VERSION 5.8 ;
BUSBITCHARS "[]" ;
DIVIDERCHAR "/" ;
UNITS
    DATABASE MICRONS 1000 ;
END UNITS

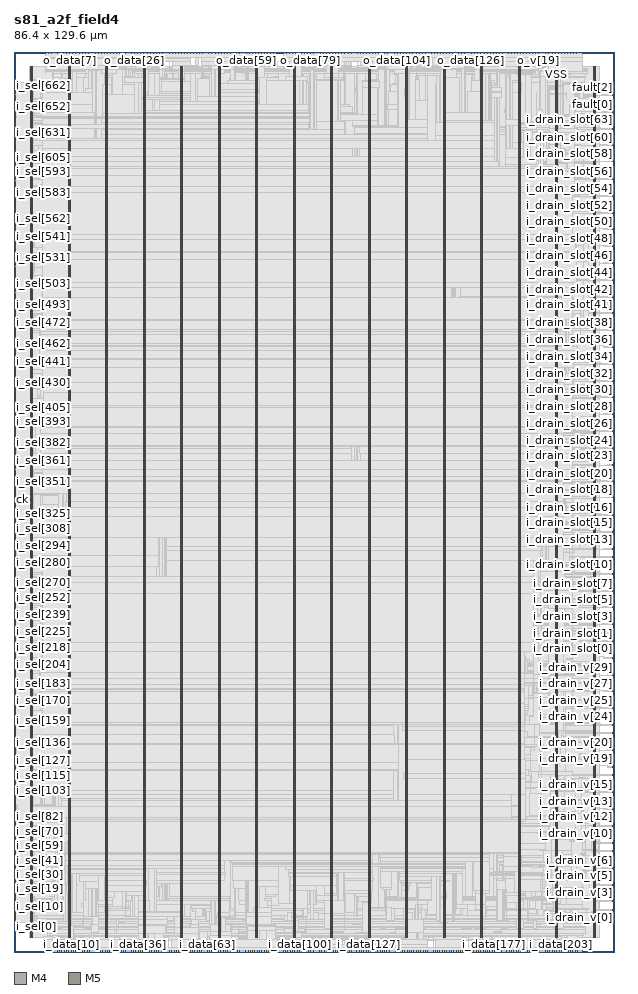
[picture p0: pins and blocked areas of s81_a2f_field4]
MACRO s81_a2f_field4
  FOREIGN s81_a2f_field4 0 0 ;
  CLASS BLOCK ;
  SIZE 86.4 BY 129.6 ;
  PIN ck
    DIRECTION INPUT ;
    USE SIGNAL ;
    PORT
      LAYER M4 ;
        RECT  0 64.08 0.192 64.104 ;
    END
  END ck
  PIN fault[0]
    DIRECTION OUTPUT ;
    USE SIGNAL ;
    PORT
      LAYER M4 ;
        RECT  86.208 120.96 86.4 120.984 ;
    END
  END fault[0]
  PIN fault[1]
    DIRECTION OUTPUT ;
    USE SIGNAL ;
    PORT
      LAYER M4 ;
        RECT  86.208 122.256 86.4 122.28 ;
    END
  END fault[1]
  PIN fault[2]
    DIRECTION OUTPUT ;
    USE SIGNAL ;
    PORT
      LAYER M4 ;
        RECT  86.208 123.408 86.4 123.432 ;
    END
  END fault[2]
  PIN fault[3]
    DIRECTION OUTPUT ;
    USE SIGNAL ;
    PORT
      LAYER M4 ;
        RECT  86.208 124.56 86.4 124.584 ;
    END
  END fault[3]
  PIN i_data[0]
    DIRECTION INPUT ;
    USE SIGNAL ;
    PORT
      LAYER M5 ;
        RECT  4.464 0 4.488 0.192 ;
    END
  END i_data[0]
  PIN i_data[100]
    DIRECTION INPUT ;
    USE SIGNAL ;
    PORT
      LAYER M5 ;
        RECT  41.136 0 41.16 0.192 ;
    END
  END i_data[100]
  PIN i_data[101]
    DIRECTION INPUT ;
    USE SIGNAL ;
    PORT
      LAYER M5 ;
        RECT  41.424 0 41.448 0.192 ;
    END
  END i_data[101]
  PIN i_data[102]
    DIRECTION INPUT ;
    USE SIGNAL ;
    PORT
      LAYER M5 ;
        RECT  41.712 0 41.736 0.192 ;
    END
  END i_data[102]
  PIN i_data[103]
    DIRECTION INPUT ;
    USE SIGNAL ;
    PORT
      LAYER M5 ;
        RECT  42.144 0 42.168 0.192 ;
    END
  END i_data[103]
  PIN i_data[104]
    DIRECTION INPUT ;
    USE SIGNAL ;
    PORT
      LAYER M5 ;
        RECT  42.432 0 42.456 0.192 ;
    END
  END i_data[104]
  PIN i_data[105]
    DIRECTION INPUT ;
    USE SIGNAL ;
    PORT
      LAYER M5 ;
        RECT  42.72 0 42.744 0.192 ;
    END
  END i_data[105]
  PIN i_data[106]
    DIRECTION INPUT ;
    USE SIGNAL ;
    PORT
      LAYER M5 ;
        RECT  43.152 0 43.176 0.192 ;
    END
  END i_data[106]
  PIN i_data[107]
    DIRECTION INPUT ;
    USE SIGNAL ;
    PORT
      LAYER M5 ;
        RECT  43.968 0 43.992 0.192 ;
    END
  END i_data[107]
  PIN i_data[108]
    DIRECTION INPUT ;
    USE SIGNAL ;
    PORT
      LAYER M5 ;
        RECT  44.256 0 44.28 0.192 ;
    END
  END i_data[108]
  PIN i_data[109]
    DIRECTION INPUT ;
    USE SIGNAL ;
    PORT
      LAYER M5 ;
        RECT  44.688 0 44.712 0.192 ;
    END
  END i_data[109]
  PIN i_data[10]
    DIRECTION INPUT ;
    USE SIGNAL ;
    PORT
      LAYER M5 ;
        RECT  8.304 0 8.328 0.192 ;
    END
  END i_data[10]
  PIN i_data[110]
    DIRECTION INPUT ;
    USE SIGNAL ;
    PORT
      LAYER M5 ;
        RECT  44.976 0 45 0.192 ;
    END
  END i_data[110]
  PIN i_data[111]
    DIRECTION INPUT ;
    USE SIGNAL ;
    PORT
      LAYER M5 ;
        RECT  45.264 0 45.288 0.192 ;
    END
  END i_data[111]
  PIN i_data[112]
    DIRECTION INPUT ;
    USE SIGNAL ;
    PORT
      LAYER M5 ;
        RECT  45.552 0 45.576 0.192 ;
    END
  END i_data[112]
  PIN i_data[113]
    DIRECTION INPUT ;
    USE SIGNAL ;
    PORT
      LAYER M5 ;
        RECT  45.984 0 46.008 0.192 ;
    END
  END i_data[113]
  PIN i_data[114]
    DIRECTION INPUT ;
    USE SIGNAL ;
    PORT
      LAYER M5 ;
        RECT  46.272 0 46.296 0.192 ;
    END
  END i_data[114]
  PIN i_data[115]
    DIRECTION INPUT ;
    USE SIGNAL ;
    PORT
      LAYER M5 ;
        RECT  46.56 0 46.584 0.192 ;
    END
  END i_data[115]
  PIN i_data[116]
    DIRECTION INPUT ;
    USE SIGNAL ;
    PORT
      LAYER M5 ;
        RECT  46.992 0 47.016 0.192 ;
    END
  END i_data[116]
  PIN i_data[117]
    DIRECTION INPUT ;
    USE SIGNAL ;
    PORT
      LAYER M5 ;
        RECT  47.28 0 47.304 0.192 ;
    END
  END i_data[117]
  PIN i_data[118]
    DIRECTION INPUT ;
    USE SIGNAL ;
    PORT
      LAYER M5 ;
        RECT  47.568 0 47.592 0.192 ;
    END
  END i_data[118]
  PIN i_data[119]
    DIRECTION INPUT ;
    USE SIGNAL ;
    PORT
      LAYER M5 ;
        RECT  48 0 48.024 0.192 ;
    END
  END i_data[119]
  PIN i_data[11]
    DIRECTION INPUT ;
    USE SIGNAL ;
    PORT
      LAYER M5 ;
        RECT  8.592 0 8.616 0.192 ;
    END
  END i_data[11]
  PIN i_data[120]
    DIRECTION INPUT ;
    USE SIGNAL ;
    PORT
      LAYER M5 ;
        RECT  48.288 0 48.312 0.192 ;
    END
  END i_data[120]
  PIN i_data[121]
    DIRECTION INPUT ;
    USE SIGNAL ;
    PORT
      LAYER M5 ;
        RECT  48.576 0 48.6 0.192 ;
    END
  END i_data[121]
  PIN i_data[122]
    DIRECTION INPUT ;
    USE SIGNAL ;
    PORT
      LAYER M5 ;
        RECT  49.344 0 49.368 0.192 ;
    END
  END i_data[122]
  PIN i_data[123]
    DIRECTION INPUT ;
    USE SIGNAL ;
    PORT
      LAYER M5 ;
        RECT  49.776 0 49.8 0.192 ;
    END
  END i_data[123]
  PIN i_data[124]
    DIRECTION INPUT ;
    USE SIGNAL ;
    PORT
      LAYER M5 ;
        RECT  50.064 0 50.088 0.192 ;
    END
  END i_data[124]
  PIN i_data[125]
    DIRECTION INPUT ;
    USE SIGNAL ;
    PORT
      LAYER M5 ;
        RECT  50.352 0 50.376 0.192 ;
    END
  END i_data[125]
  PIN i_data[126]
    DIRECTION INPUT ;
    USE SIGNAL ;
    PORT
      LAYER M5 ;
        RECT  50.784 0 50.808 0.192 ;
    END
  END i_data[126]
  PIN i_data[127]
    DIRECTION INPUT ;
    USE SIGNAL ;
    PORT
      LAYER M5 ;
        RECT  51.072 0 51.096 0.192 ;
    END
  END i_data[127]
  PIN i_data[128]
    DIRECTION INPUT ;
    USE SIGNAL ;
    PORT
      LAYER M5 ;
        RECT  51.36 0 51.384 0.192 ;
    END
  END i_data[128]
  PIN i_data[129]
    DIRECTION INPUT ;
    USE SIGNAL ;
    PORT
      LAYER M5 ;
        RECT  51.792 0 51.816 0.192 ;
    END
  END i_data[129]
  PIN i_data[12]
    DIRECTION INPUT ;
    USE SIGNAL ;
    PORT
      LAYER M5 ;
        RECT  8.88 0 8.904 0.192 ;
    END
  END i_data[12]
  PIN i_data[130]
    DIRECTION INPUT ;
    USE SIGNAL ;
    PORT
      LAYER M5 ;
        RECT  52.08 0 52.104 0.192 ;
    END
  END i_data[130]
  PIN i_data[131]
    DIRECTION INPUT ;
    USE SIGNAL ;
    PORT
      LAYER M5 ;
        RECT  52.368 0 52.392 0.192 ;
    END
  END i_data[131]
  PIN i_data[132]
    DIRECTION INPUT ;
    USE SIGNAL ;
    PORT
      LAYER M5 ;
        RECT  52.8 0 52.824 0.192 ;
    END
  END i_data[132]
  PIN i_data[133]
    DIRECTION INPUT ;
    USE SIGNAL ;
    PORT
      LAYER M5 ;
        RECT  53.088 0 53.112 0.192 ;
    END
  END i_data[133]
  PIN i_data[134]
    DIRECTION INPUT ;
    USE SIGNAL ;
    PORT
      LAYER M5 ;
        RECT  53.376 0 53.4 0.192 ;
    END
  END i_data[134]
  PIN i_data[135]
    DIRECTION INPUT ;
    USE SIGNAL ;
    PORT
      LAYER M5 ;
        RECT  53.664 0 53.688 0.192 ;
    END
  END i_data[135]
  PIN i_data[136]
    DIRECTION INPUT ;
    USE SIGNAL ;
    PORT
      LAYER M5 ;
        RECT  54.096 0 54.12 0.192 ;
    END
  END i_data[136]
  PIN i_data[137]
    DIRECTION INPUT ;
    USE SIGNAL ;
    PORT
      LAYER M5 ;
        RECT  54.912 0 54.936 0.192 ;
    END
  END i_data[137]
  PIN i_data[138]
    DIRECTION INPUT ;
    USE SIGNAL ;
    PORT
      LAYER M5 ;
        RECT  55.2 0 55.224 0.192 ;
    END
  END i_data[138]
  PIN i_data[139]
    DIRECTION INPUT ;
    USE SIGNAL ;
    PORT
      LAYER M5 ;
        RECT  55.632 0 55.656 0.192 ;
    END
  END i_data[139]
  PIN i_data[13]
    DIRECTION INPUT ;
    USE SIGNAL ;
    PORT
      LAYER M5 ;
        RECT  9.312 0 9.336 0.192 ;
    END
  END i_data[13]
  PIN i_data[140]
    DIRECTION INPUT ;
    USE SIGNAL ;
    PORT
      LAYER M5 ;
        RECT  55.92 0 55.944 0.192 ;
    END
  END i_data[140]
  PIN i_data[141]
    DIRECTION INPUT ;
    USE SIGNAL ;
    PORT
      LAYER M5 ;
        RECT  56.208 0 56.232 0.192 ;
    END
  END i_data[141]
  PIN i_data[142]
    DIRECTION INPUT ;
    USE SIGNAL ;
    PORT
      LAYER M5 ;
        RECT  56.64 0 56.664 0.192 ;
    END
  END i_data[142]
  PIN i_data[143]
    DIRECTION INPUT ;
    USE SIGNAL ;
    PORT
      LAYER M5 ;
        RECT  56.928 0 56.952 0.192 ;
    END
  END i_data[143]
  PIN i_data[144]
    DIRECTION INPUT ;
    USE SIGNAL ;
    PORT
      LAYER M5 ;
        RECT  57.216 0 57.24 0.192 ;
    END
  END i_data[144]
  PIN i_data[145]
    DIRECTION INPUT ;
    USE SIGNAL ;
    PORT
      LAYER M5 ;
        RECT  57.504 0 57.528 0.192 ;
    END
  END i_data[145]
  PIN i_data[146]
    DIRECTION INPUT ;
    USE SIGNAL ;
    PORT
      LAYER M5 ;
        RECT  57.936 0 57.96 0.192 ;
    END
  END i_data[146]
  PIN i_data[147]
    DIRECTION INPUT ;
    USE SIGNAL ;
    PORT
      LAYER M5 ;
        RECT  58.224 0 58.248 0.192 ;
    END
  END i_data[147]
  PIN i_data[148]
    DIRECTION INPUT ;
    USE SIGNAL ;
    PORT
      LAYER M5 ;
        RECT  58.512 0 58.536 0.192 ;
    END
  END i_data[148]
  PIN i_data[149]
    DIRECTION INPUT ;
    USE SIGNAL ;
    PORT
      LAYER M5 ;
        RECT  58.944 0 58.968 0.192 ;
    END
  END i_data[149]
  PIN i_data[14]
    DIRECTION INPUT ;
    USE SIGNAL ;
    PORT
      LAYER M5 ;
        RECT  9.6 0 9.624 0.192 ;
    END
  END i_data[14]
  PIN i_data[150]
    DIRECTION INPUT ;
    USE SIGNAL ;
    PORT
      LAYER M5 ;
        RECT  59.232 0 59.256 0.192 ;
    END
  END i_data[150]
  PIN i_data[151]
    DIRECTION INPUT ;
    USE SIGNAL ;
    PORT
      LAYER M5 ;
        RECT  59.52 0 59.544 0.192 ;
    END
  END i_data[151]
  PIN i_data[152]
    DIRECTION INPUT ;
    USE SIGNAL ;
    PORT
      LAYER M5 ;
        RECT  60.432 0 60.456 0.192 ;
    END
  END i_data[152]
  PIN i_data[153]
    DIRECTION INPUT ;
    USE SIGNAL ;
    PORT
      LAYER M5 ;
        RECT  60.72 0 60.744 0.192 ;
    END
  END i_data[153]
  PIN i_data[154]
    DIRECTION INPUT ;
    USE SIGNAL ;
    PORT
      LAYER M5 ;
        RECT  61.008 0 61.032 0.192 ;
    END
  END i_data[154]
  PIN i_data[155]
    DIRECTION INPUT ;
    USE SIGNAL ;
    PORT
      LAYER M5 ;
        RECT  61.296 0 61.32 0.192 ;
    END
  END i_data[155]
  PIN i_data[156]
    DIRECTION INPUT ;
    USE SIGNAL ;
    PORT
      LAYER M5 ;
        RECT  61.728 0 61.752 0.192 ;
    END
  END i_data[156]
  PIN i_data[157]
    DIRECTION INPUT ;
    USE SIGNAL ;
    PORT
      LAYER M5 ;
        RECT  62.016 0 62.04 0.192 ;
    END
  END i_data[157]
  PIN i_data[158]
    DIRECTION INPUT ;
    USE SIGNAL ;
    PORT
      LAYER M5 ;
        RECT  62.304 0 62.328 0.192 ;
    END
  END i_data[158]
  PIN i_data[159]
    DIRECTION INPUT ;
    USE SIGNAL ;
    PORT
      LAYER M5 ;
        RECT  62.736 0 62.76 0.192 ;
    END
  END i_data[159]
  PIN i_data[15]
    DIRECTION INPUT ;
    USE SIGNAL ;
    PORT
      LAYER M5 ;
        RECT  9.888 0 9.912 0.192 ;
    END
  END i_data[15]
  PIN i_data[160]
    DIRECTION INPUT ;
    USE SIGNAL ;
    PORT
      LAYER M5 ;
        RECT  63.024 0 63.048 0.192 ;
    END
  END i_data[160]
  PIN i_data[161]
    DIRECTION INPUT ;
    USE SIGNAL ;
    PORT
      LAYER M5 ;
        RECT  63.312 0 63.336 0.192 ;
    END
  END i_data[161]
  PIN i_data[162]
    DIRECTION INPUT ;
    USE SIGNAL ;
    PORT
      LAYER M5 ;
        RECT  63.744 0 63.768 0.192 ;
    END
  END i_data[162]
  PIN i_data[163]
    DIRECTION INPUT ;
    USE SIGNAL ;
    PORT
      LAYER M5 ;
        RECT  64.032 0 64.056 0.192 ;
    END
  END i_data[163]
  PIN i_data[164]
    DIRECTION INPUT ;
    USE SIGNAL ;
    PORT
      LAYER M5 ;
        RECT  64.32 0 64.344 0.192 ;
    END
  END i_data[164]
  PIN i_data[165]
    DIRECTION INPUT ;
    USE SIGNAL ;
    PORT
      LAYER M5 ;
        RECT  64.608 0 64.632 0.192 ;
    END
  END i_data[165]
  PIN i_data[166]
    DIRECTION INPUT ;
    USE SIGNAL ;
    PORT
      LAYER M5 ;
        RECT  65.568 0 65.592 0.192 ;
    END
  END i_data[166]
  PIN i_data[167]
    DIRECTION INPUT ;
    USE SIGNAL ;
    PORT
      LAYER M5 ;
        RECT  65.856 0 65.88 0.192 ;
    END
  END i_data[167]
  PIN i_data[168]
    DIRECTION INPUT ;
    USE SIGNAL ;
    PORT
      LAYER M5 ;
        RECT  66.144 0 66.168 0.192 ;
    END
  END i_data[168]
  PIN i_data[169]
    DIRECTION INPUT ;
    USE SIGNAL ;
    PORT
      LAYER M5 ;
        RECT  66.576 0 66.6 0.192 ;
    END
  END i_data[169]
  PIN i_data[16]
    DIRECTION INPUT ;
    USE SIGNAL ;
    PORT
      LAYER M5 ;
        RECT  10.176 0 10.2 0.192 ;
    END
  END i_data[16]
  PIN i_data[170]
    DIRECTION INPUT ;
    USE SIGNAL ;
    PORT
      LAYER M5 ;
        RECT  66.864 0 66.888 0.192 ;
    END
  END i_data[170]
  PIN i_data[171]
    DIRECTION INPUT ;
    USE SIGNAL ;
    PORT
      LAYER M5 ;
        RECT  67.152 0 67.176 0.192 ;
    END
  END i_data[171]
  PIN i_data[172]
    DIRECTION INPUT ;
    USE SIGNAL ;
    PORT
      LAYER M5 ;
        RECT  67.584 0 67.608 0.192 ;
    END
  END i_data[172]
  PIN i_data[173]
    DIRECTION INPUT ;
    USE SIGNAL ;
    PORT
      LAYER M5 ;
        RECT  67.872 0 67.896 0.192 ;
    END
  END i_data[173]
  PIN i_data[174]
    DIRECTION INPUT ;
    USE SIGNAL ;
    PORT
      LAYER M5 ;
        RECT  68.16 0 68.184 0.192 ;
    END
  END i_data[174]
  PIN i_data[175]
    DIRECTION INPUT ;
    USE SIGNAL ;
    PORT
      LAYER M5 ;
        RECT  68.448 0 68.472 0.192 ;
    END
  END i_data[175]
  PIN i_data[176]
    DIRECTION INPUT ;
    USE SIGNAL ;
    PORT
      LAYER M5 ;
        RECT  68.88 0 68.904 0.192 ;
    END
  END i_data[176]
  PIN i_data[177]
    DIRECTION INPUT ;
    USE SIGNAL ;
    PORT
      LAYER M5 ;
        RECT  69.168 0 69.192 0.192 ;
    END
  END i_data[177]
  PIN i_data[178]
    DIRECTION INPUT ;
    USE SIGNAL ;
    PORT
      LAYER M5 ;
        RECT  69.456 0 69.48 0.192 ;
    END
  END i_data[178]
  PIN i_data[179]
    DIRECTION INPUT ;
    USE SIGNAL ;
    PORT
      LAYER M5 ;
        RECT  69.888 0 69.912 0.192 ;
    END
  END i_data[179]
  PIN i_data[17]
    DIRECTION INPUT ;
    USE SIGNAL ;
    PORT
      LAYER M5 ;
        RECT  10.608 0 10.632 0.192 ;
    END
  END i_data[17]
  PIN i_data[180]
    DIRECTION INPUT ;
    USE SIGNAL ;
    PORT
      LAYER M5 ;
        RECT  70.176 0 70.2 0.192 ;
    END
  END i_data[180]
  PIN i_data[181]
    DIRECTION INPUT ;
    USE SIGNAL ;
    PORT
      LAYER M5 ;
        RECT  70.944 0 70.968 0.192 ;
    END
  END i_data[181]
  PIN i_data[182]
    DIRECTION INPUT ;
    USE SIGNAL ;
    PORT
      LAYER M5 ;
        RECT  71.376 0 71.4 0.192 ;
    END
  END i_data[182]
  PIN i_data[183]
    DIRECTION INPUT ;
    USE SIGNAL ;
    PORT
      LAYER M5 ;
        RECT  71.664 0 71.688 0.192 ;
    END
  END i_data[183]
  PIN i_data[184]
    DIRECTION INPUT ;
    USE SIGNAL ;
    PORT
      LAYER M5 ;
        RECT  71.952 0 71.976 0.192 ;
    END
  END i_data[184]
  PIN i_data[185]
    DIRECTION INPUT ;
    USE SIGNAL ;
    PORT
      LAYER M5 ;
        RECT  72.384 0 72.408 0.192 ;
    END
  END i_data[185]
  PIN i_data[186]
    DIRECTION INPUT ;
    USE SIGNAL ;
    PORT
      LAYER M5 ;
        RECT  72.672 0 72.696 0.192 ;
    END
  END i_data[186]
  PIN i_data[187]
    DIRECTION INPUT ;
    USE SIGNAL ;
    PORT
      LAYER M5 ;
        RECT  72.96 0 72.984 0.192 ;
    END
  END i_data[187]
  PIN i_data[188]
    DIRECTION INPUT ;
    USE SIGNAL ;
    PORT
      LAYER M5 ;
        RECT  73.248 0 73.272 0.192 ;
    END
  END i_data[188]
  PIN i_data[189]
    DIRECTION INPUT ;
    USE SIGNAL ;
    PORT
      LAYER M5 ;
        RECT  73.68 0 73.704 0.192 ;
    END
  END i_data[189]
  PIN i_data[18]
    DIRECTION INPUT ;
    USE SIGNAL ;
    PORT
      LAYER M5 ;
        RECT  10.896 0 10.92 0.192 ;
    END
  END i_data[18]
  PIN i_data[190]
    DIRECTION INPUT ;
    USE SIGNAL ;
    PORT
      LAYER M5 ;
        RECT  73.968 0 73.992 0.192 ;
    END
  END i_data[190]
  PIN i_data[191]
    DIRECTION INPUT ;
    USE SIGNAL ;
    PORT
      LAYER M5 ;
        RECT  74.256 0 74.28 0.192 ;
    END
  END i_data[191]
  PIN i_data[192]
    DIRECTION INPUT ;
    USE SIGNAL ;
    PORT
      LAYER M5 ;
        RECT  74.688 0 74.712 0.192 ;
    END
  END i_data[192]
  PIN i_data[193]
    DIRECTION INPUT ;
    USE SIGNAL ;
    PORT
      LAYER M5 ;
        RECT  74.976 0 75 0.192 ;
    END
  END i_data[193]
  PIN i_data[194]
    DIRECTION INPUT ;
    USE SIGNAL ;
    PORT
      LAYER M5 ;
        RECT  75.264 0 75.288 0.192 ;
    END
  END i_data[194]
  PIN i_data[195]
    DIRECTION INPUT ;
    USE SIGNAL ;
    PORT
      LAYER M5 ;
        RECT  75.696 0 75.72 0.192 ;
    END
  END i_data[195]
  PIN i_data[196]
    DIRECTION INPUT ;
    USE SIGNAL ;
    PORT
      LAYER M5 ;
        RECT  76.512 0 76.536 0.192 ;
    END
  END i_data[196]
  PIN i_data[197]
    DIRECTION INPUT ;
    USE SIGNAL ;
    PORT
      LAYER M5 ;
        RECT  76.8 0 76.824 0.192 ;
    END
  END i_data[197]
  PIN i_data[198]
    DIRECTION INPUT ;
    USE SIGNAL ;
    PORT
      LAYER M5 ;
        RECT  77.088 0 77.112 0.192 ;
    END
  END i_data[198]
  PIN i_data[199]
    DIRECTION INPUT ;
    USE SIGNAL ;
    PORT
      LAYER M5 ;
        RECT  77.52 0 77.544 0.192 ;
    END
  END i_data[199]
  PIN i_data[19]
    DIRECTION INPUT ;
    USE SIGNAL ;
    PORT
      LAYER M5 ;
        RECT  11.712 0 11.736 0.192 ;
    END
  END i_data[19]
  PIN i_data[1]
    DIRECTION INPUT ;
    USE SIGNAL ;
    PORT
      LAYER M5 ;
        RECT  4.752 0 4.776 0.192 ;
    END
  END i_data[1]
  PIN i_data[200]
    DIRECTION INPUT ;
    USE SIGNAL ;
    PORT
      LAYER M5 ;
        RECT  77.808 0 77.832 0.192 ;
    END
  END i_data[200]
  PIN i_data[201]
    DIRECTION INPUT ;
    USE SIGNAL ;
    PORT
      LAYER M5 ;
        RECT  78.096 0 78.12 0.192 ;
    END
  END i_data[201]
  PIN i_data[202]
    DIRECTION INPUT ;
    USE SIGNAL ;
    PORT
      LAYER M5 ;
        RECT  78.528 0 78.552 0.192 ;
    END
  END i_data[202]
  PIN i_data[203]
    DIRECTION INPUT ;
    USE SIGNAL ;
    PORT
      LAYER M5 ;
        RECT  78.816 0 78.84 0.192 ;
    END
  END i_data[203]
  PIN i_data[204]
    DIRECTION INPUT ;
    USE SIGNAL ;
    PORT
      LAYER M5 ;
        RECT  79.104 0 79.128 0.192 ;
    END
  END i_data[204]
  PIN i_data[205]
    DIRECTION INPUT ;
    USE SIGNAL ;
    PORT
      LAYER M5 ;
        RECT  79.536 0 79.56 0.192 ;
    END
  END i_data[205]
  PIN i_data[206]
    DIRECTION INPUT ;
    USE SIGNAL ;
    PORT
      LAYER M5 ;
        RECT  79.824 0 79.848 0.192 ;
    END
  END i_data[206]
  PIN i_data[207]
    DIRECTION INPUT ;
    USE SIGNAL ;
    PORT
      LAYER M5 ;
        RECT  80.112 0 80.136 0.192 ;
    END
  END i_data[207]
  PIN i_data[208]
    DIRECTION INPUT ;
    USE SIGNAL ;
    PORT
      LAYER M5 ;
        RECT  80.4 0 80.424 0.192 ;
    END
  END i_data[208]
  PIN i_data[209]
    DIRECTION INPUT ;
    USE SIGNAL ;
    PORT
      LAYER M5 ;
        RECT  80.832 0 80.856 0.192 ;
    END
  END i_data[209]
  PIN i_data[20]
    DIRECTION INPUT ;
    USE SIGNAL ;
    PORT
      LAYER M5 ;
        RECT  12.144 0 12.168 0.192 ;
    END
  END i_data[20]
  PIN i_data[210]
    DIRECTION INPUT ;
    USE SIGNAL ;
    PORT
      LAYER M5 ;
        RECT  81.12 0 81.144 0.192 ;
    END
  END i_data[210]
  PIN i_data[211]
    DIRECTION INPUT ;
    USE SIGNAL ;
    PORT
      LAYER M5 ;
        RECT  81.888 0 81.912 0.192 ;
    END
  END i_data[211]
  PIN i_data[21]
    DIRECTION INPUT ;
    USE SIGNAL ;
    PORT
      LAYER M5 ;
        RECT  12.432 0 12.456 0.192 ;
    END
  END i_data[21]
  PIN i_data[22]
    DIRECTION INPUT ;
    USE SIGNAL ;
    PORT
      LAYER M5 ;
        RECT  12.72 0 12.744 0.192 ;
    END
  END i_data[22]
  PIN i_data[23]
    DIRECTION INPUT ;
    USE SIGNAL ;
    PORT
      LAYER M5 ;
        RECT  13.152 0 13.176 0.192 ;
    END
  END i_data[23]
  PIN i_data[24]
    DIRECTION INPUT ;
    USE SIGNAL ;
    PORT
      LAYER M5 ;
        RECT  13.44 0 13.464 0.192 ;
    END
  END i_data[24]
  PIN i_data[25]
    DIRECTION INPUT ;
    USE SIGNAL ;
    PORT
      LAYER M5 ;
        RECT  13.728 0 13.752 0.192 ;
    END
  END i_data[25]
  PIN i_data[26]
    DIRECTION INPUT ;
    USE SIGNAL ;
    PORT
      LAYER M5 ;
        RECT  14.16 0 14.184 0.192 ;
    END
  END i_data[26]
  PIN i_data[27]
    DIRECTION INPUT ;
    USE SIGNAL ;
    PORT
      LAYER M5 ;
        RECT  14.448 0 14.472 0.192 ;
    END
  END i_data[27]
  PIN i_data[28]
    DIRECTION INPUT ;
    USE SIGNAL ;
    PORT
      LAYER M5 ;
        RECT  14.736 0 14.76 0.192 ;
    END
  END i_data[28]
  PIN i_data[29]
    DIRECTION INPUT ;
    USE SIGNAL ;
    PORT
      LAYER M5 ;
        RECT  15.024 0 15.048 0.192 ;
    END
  END i_data[29]
  PIN i_data[2]
    DIRECTION INPUT ;
    USE SIGNAL ;
    PORT
      LAYER M5 ;
        RECT  5.04 0 5.064 0.192 ;
    END
  END i_data[2]
  PIN i_data[30]
    DIRECTION INPUT ;
    USE SIGNAL ;
    PORT
      LAYER M5 ;
        RECT  15.456 0 15.48 0.192 ;
    END
  END i_data[30]
  PIN i_data[31]
    DIRECTION INPUT ;
    USE SIGNAL ;
    PORT
      LAYER M5 ;
        RECT  15.744 0 15.768 0.192 ;
    END
  END i_data[31]
  PIN i_data[32]
    DIRECTION INPUT ;
    USE SIGNAL ;
    PORT
      LAYER M5 ;
        RECT  16.032 0 16.056 0.192 ;
    END
  END i_data[32]
  PIN i_data[33]
    DIRECTION INPUT ;
    USE SIGNAL ;
    PORT
      LAYER M5 ;
        RECT  16.944 0 16.968 0.192 ;
    END
  END i_data[33]
  PIN i_data[34]
    DIRECTION INPUT ;
    USE SIGNAL ;
    PORT
      LAYER M5 ;
        RECT  17.232 0 17.256 0.192 ;
    END
  END i_data[34]
  PIN i_data[35]
    DIRECTION INPUT ;
    USE SIGNAL ;
    PORT
      LAYER M5 ;
        RECT  17.52 0 17.544 0.192 ;
    END
  END i_data[35]
  PIN i_data[36]
    DIRECTION INPUT ;
    USE SIGNAL ;
    PORT
      LAYER M5 ;
        RECT  17.952 0 17.976 0.192 ;
    END
  END i_data[36]
  PIN i_data[37]
    DIRECTION INPUT ;
    USE SIGNAL ;
    PORT
      LAYER M5 ;
        RECT  18.24 0 18.264 0.192 ;
    END
  END i_data[37]
  PIN i_data[38]
    DIRECTION INPUT ;
    USE SIGNAL ;
    PORT
      LAYER M5 ;
        RECT  18.528 0 18.552 0.192 ;
    END
  END i_data[38]
  PIN i_data[39]
    DIRECTION INPUT ;
    USE SIGNAL ;
    PORT
      LAYER M5 ;
        RECT  18.816 0 18.84 0.192 ;
    END
  END i_data[39]
  PIN i_data[3]
    DIRECTION INPUT ;
    USE SIGNAL ;
    PORT
      LAYER M5 ;
        RECT  5.472 0 5.496 0.192 ;
    END
  END i_data[3]
  PIN i_data[40]
    DIRECTION INPUT ;
    USE SIGNAL ;
    PORT
      LAYER M5 ;
        RECT  19.248 0 19.272 0.192 ;
    END
  END i_data[40]
  PIN i_data[41]
    DIRECTION INPUT ;
    USE SIGNAL ;
    PORT
      LAYER M5 ;
        RECT  19.536 0 19.56 0.192 ;
    END
  END i_data[41]
  PIN i_data[42]
    DIRECTION INPUT ;
    USE SIGNAL ;
    PORT
      LAYER M5 ;
        RECT  19.824 0 19.848 0.192 ;
    END
  END i_data[42]
  PIN i_data[43]
    DIRECTION INPUT ;
    USE SIGNAL ;
    PORT
      LAYER M5 ;
        RECT  20.256 0 20.28 0.192 ;
    END
  END i_data[43]
  PIN i_data[44]
    DIRECTION INPUT ;
    USE SIGNAL ;
    PORT
      LAYER M5 ;
        RECT  20.544 0 20.568 0.192 ;
    END
  END i_data[44]
  PIN i_data[45]
    DIRECTION INPUT ;
    USE SIGNAL ;
    PORT
      LAYER M5 ;
        RECT  20.832 0 20.856 0.192 ;
    END
  END i_data[45]
  PIN i_data[46]
    DIRECTION INPUT ;
    USE SIGNAL ;
    PORT
      LAYER M5 ;
        RECT  21.264 0 21.288 0.192 ;
    END
  END i_data[46]
  PIN i_data[47]
    DIRECTION INPUT ;
    USE SIGNAL ;
    PORT
      LAYER M5 ;
        RECT  21.552 0 21.576 0.192 ;
    END
  END i_data[47]
  PIN i_data[48]
    DIRECTION INPUT ;
    USE SIGNAL ;
    PORT
      LAYER M5 ;
        RECT  22.368 0 22.392 0.192 ;
    END
  END i_data[48]
  PIN i_data[49]
    DIRECTION INPUT ;
    USE SIGNAL ;
    PORT
      LAYER M5 ;
        RECT  22.656 0 22.68 0.192 ;
    END
  END i_data[49]
  PIN i_data[4]
    DIRECTION INPUT ;
    USE SIGNAL ;
    PORT
      LAYER M5 ;
        RECT  6.288 0 6.312 0.192 ;
    END
  END i_data[4]
  PIN i_data[50]
    DIRECTION INPUT ;
    USE SIGNAL ;
    PORT
      LAYER M5 ;
        RECT  23.088 0 23.112 0.192 ;
    END
  END i_data[50]
  PIN i_data[51]
    DIRECTION INPUT ;
    USE SIGNAL ;
    PORT
      LAYER M5 ;
        RECT  23.376 0 23.4 0.192 ;
    END
  END i_data[51]
  PIN i_data[52]
    DIRECTION INPUT ;
    USE SIGNAL ;
    PORT
      LAYER M5 ;
        RECT  23.664 0 23.688 0.192 ;
    END
  END i_data[52]
  PIN i_data[53]
    DIRECTION INPUT ;
    USE SIGNAL ;
    PORT
      LAYER M5 ;
        RECT  24.096 0 24.12 0.192 ;
    END
  END i_data[53]
  PIN i_data[54]
    DIRECTION INPUT ;
    USE SIGNAL ;
    PORT
      LAYER M5 ;
        RECT  24.384 0 24.408 0.192 ;
    END
  END i_data[54]
  PIN i_data[55]
    DIRECTION INPUT ;
    USE SIGNAL ;
    PORT
      LAYER M5 ;
        RECT  24.672 0 24.696 0.192 ;
    END
  END i_data[55]
  PIN i_data[56]
    DIRECTION INPUT ;
    USE SIGNAL ;
    PORT
      LAYER M5 ;
        RECT  25.104 0 25.128 0.192 ;
    END
  END i_data[56]
  PIN i_data[57]
    DIRECTION INPUT ;
    USE SIGNAL ;
    PORT
      LAYER M5 ;
        RECT  25.392 0 25.416 0.192 ;
    END
  END i_data[57]
  PIN i_data[58]
    DIRECTION INPUT ;
    USE SIGNAL ;
    PORT
      LAYER M5 ;
        RECT  25.68 0 25.704 0.192 ;
    END
  END i_data[58]
  PIN i_data[59]
    DIRECTION INPUT ;
    USE SIGNAL ;
    PORT
      LAYER M5 ;
        RECT  25.968 0 25.992 0.192 ;
    END
  END i_data[59]
  PIN i_data[5]
    DIRECTION INPUT ;
    USE SIGNAL ;
    PORT
      LAYER M5 ;
        RECT  6.576 0 6.6 0.192 ;
    END
  END i_data[5]
  PIN i_data[60]
    DIRECTION INPUT ;
    USE SIGNAL ;
    PORT
      LAYER M5 ;
        RECT  26.4 0 26.424 0.192 ;
    END
  END i_data[60]
  PIN i_data[61]
    DIRECTION INPUT ;
    USE SIGNAL ;
    PORT
      LAYER M5 ;
        RECT  26.688 0 26.712 0.192 ;
    END
  END i_data[61]
  PIN i_data[62]
    DIRECTION INPUT ;
    USE SIGNAL ;
    PORT
      LAYER M5 ;
        RECT  26.976 0 27 0.192 ;
    END
  END i_data[62]
  PIN i_data[63]
    DIRECTION INPUT ;
    USE SIGNAL ;
    PORT
      LAYER M5 ;
        RECT  27.888 0 27.912 0.192 ;
    END
  END i_data[63]
  PIN i_data[64]
    DIRECTION INPUT ;
    USE SIGNAL ;
    PORT
      LAYER M5 ;
        RECT  28.176 0 28.2 0.192 ;
    END
  END i_data[64]
  PIN i_data[65]
    DIRECTION INPUT ;
    USE SIGNAL ;
    PORT
      LAYER M5 ;
        RECT  28.464 0 28.488 0.192 ;
    END
  END i_data[65]
  PIN i_data[66]
    DIRECTION INPUT ;
    USE SIGNAL ;
    PORT
      LAYER M5 ;
        RECT  28.896 0 28.92 0.192 ;
    END
  END i_data[66]
  PIN i_data[67]
    DIRECTION INPUT ;
    USE SIGNAL ;
    PORT
      LAYER M5 ;
        RECT  29.184 0 29.208 0.192 ;
    END
  END i_data[67]
  PIN i_data[68]
    DIRECTION INPUT ;
    USE SIGNAL ;
    PORT
      LAYER M5 ;
        RECT  29.472 0 29.496 0.192 ;
    END
  END i_data[68]
  PIN i_data[69]
    DIRECTION INPUT ;
    USE SIGNAL ;
    PORT
      LAYER M5 ;
        RECT  29.76 0 29.784 0.192 ;
    END
  END i_data[69]
  PIN i_data[6]
    DIRECTION INPUT ;
    USE SIGNAL ;
    PORT
      LAYER M5 ;
        RECT  6.864 0 6.888 0.192 ;
    END
  END i_data[6]
  PIN i_data[70]
    DIRECTION INPUT ;
    USE SIGNAL ;
    PORT
      LAYER M5 ;
        RECT  30.192 0 30.216 0.192 ;
    END
  END i_data[70]
  PIN i_data[71]
    DIRECTION INPUT ;
    USE SIGNAL ;
    PORT
      LAYER M5 ;
        RECT  30.48 0 30.504 0.192 ;
    END
  END i_data[71]
  PIN i_data[72]
    DIRECTION INPUT ;
    USE SIGNAL ;
    PORT
      LAYER M5 ;
        RECT  30.768 0 30.792 0.192 ;
    END
  END i_data[72]
  PIN i_data[73]
    DIRECTION INPUT ;
    USE SIGNAL ;
    PORT
      LAYER M5 ;
        RECT  31.2 0 31.224 0.192 ;
    END
  END i_data[73]
  PIN i_data[74]
    DIRECTION INPUT ;
    USE SIGNAL ;
    PORT
      LAYER M5 ;
        RECT  31.488 0 31.512 0.192 ;
    END
  END i_data[74]
  PIN i_data[75]
    DIRECTION INPUT ;
    USE SIGNAL ;
    PORT
      LAYER M5 ;
        RECT  31.776 0 31.8 0.192 ;
    END
  END i_data[75]
  PIN i_data[76]
    DIRECTION INPUT ;
    USE SIGNAL ;
    PORT
      LAYER M5 ;
        RECT  32.208 0 32.232 0.192 ;
    END
  END i_data[76]
  PIN i_data[77]
    DIRECTION INPUT ;
    USE SIGNAL ;
    PORT
      LAYER M5 ;
        RECT  32.496 0 32.52 0.192 ;
    END
  END i_data[77]
  PIN i_data[78]
    DIRECTION INPUT ;
    USE SIGNAL ;
    PORT
      LAYER M5 ;
        RECT  33.312 0 33.336 0.192 ;
    END
  END i_data[78]
  PIN i_data[79]
    DIRECTION INPUT ;
    USE SIGNAL ;
    PORT
      LAYER M5 ;
        RECT  33.744 0 33.768 0.192 ;
    END
  END i_data[79]
  PIN i_data[7]
    DIRECTION INPUT ;
    USE SIGNAL ;
    PORT
      LAYER M5 ;
        RECT  7.296 0 7.32 0.192 ;
    END
  END i_data[7]
  PIN i_data[80]
    DIRECTION INPUT ;
    USE SIGNAL ;
    PORT
      LAYER M5 ;
        RECT  34.032 0 34.056 0.192 ;
    END
  END i_data[80]
  PIN i_data[81]
    DIRECTION INPUT ;
    USE SIGNAL ;
    PORT
      LAYER M5 ;
        RECT  34.32 0 34.344 0.192 ;
    END
  END i_data[81]
  PIN i_data[82]
    DIRECTION INPUT ;
    USE SIGNAL ;
    PORT
      LAYER M5 ;
        RECT  34.608 0 34.632 0.192 ;
    END
  END i_data[82]
  PIN i_data[83]
    DIRECTION INPUT ;
    USE SIGNAL ;
    PORT
      LAYER M5 ;
        RECT  35.04 0 35.064 0.192 ;
    END
  END i_data[83]
  PIN i_data[84]
    DIRECTION INPUT ;
    USE SIGNAL ;
    PORT
      LAYER M5 ;
        RECT  35.328 0 35.352 0.192 ;
    END
  END i_data[84]
  PIN i_data[85]
    DIRECTION INPUT ;
    USE SIGNAL ;
    PORT
      LAYER M5 ;
        RECT  35.616 0 35.64 0.192 ;
    END
  END i_data[85]
  PIN i_data[86]
    DIRECTION INPUT ;
    USE SIGNAL ;
    PORT
      LAYER M5 ;
        RECT  36.048 0 36.072 0.192 ;
    END
  END i_data[86]
  PIN i_data[87]
    DIRECTION INPUT ;
    USE SIGNAL ;
    PORT
      LAYER M5 ;
        RECT  36.336 0 36.36 0.192 ;
    END
  END i_data[87]
  PIN i_data[88]
    DIRECTION INPUT ;
    USE SIGNAL ;
    PORT
      LAYER M5 ;
        RECT  36.624 0 36.648 0.192 ;
    END
  END i_data[88]
  PIN i_data[89]
    DIRECTION INPUT ;
    USE SIGNAL ;
    PORT
      LAYER M5 ;
        RECT  37.056 0 37.08 0.192 ;
    END
  END i_data[89]
  PIN i_data[8]
    DIRECTION INPUT ;
    USE SIGNAL ;
    PORT
      LAYER M5 ;
        RECT  7.584 0 7.608 0.192 ;
    END
  END i_data[8]
  PIN i_data[90]
    DIRECTION INPUT ;
    USE SIGNAL ;
    PORT
      LAYER M5 ;
        RECT  37.344 0 37.368 0.192 ;
    END
  END i_data[90]
  PIN i_data[91]
    DIRECTION INPUT ;
    USE SIGNAL ;
    PORT
      LAYER M5 ;
        RECT  37.632 0 37.656 0.192 ;
    END
  END i_data[91]
  PIN i_data[92]
    DIRECTION INPUT ;
    USE SIGNAL ;
    PORT
      LAYER M5 ;
        RECT  37.92 0 37.944 0.192 ;
    END
  END i_data[92]
  PIN i_data[93]
    DIRECTION INPUT ;
    USE SIGNAL ;
    PORT
      LAYER M5 ;
        RECT  38.832 0 38.856 0.192 ;
    END
  END i_data[93]
  PIN i_data[94]
    DIRECTION INPUT ;
    USE SIGNAL ;
    PORT
      LAYER M5 ;
        RECT  39.12 0 39.144 0.192 ;
    END
  END i_data[94]
  PIN i_data[95]
    DIRECTION INPUT ;
    USE SIGNAL ;
    PORT
      LAYER M5 ;
        RECT  39.408 0 39.432 0.192 ;
    END
  END i_data[95]
  PIN i_data[96]
    DIRECTION INPUT ;
    USE SIGNAL ;
    PORT
      LAYER M5 ;
        RECT  39.84 0 39.864 0.192 ;
    END
  END i_data[96]
  PIN i_data[97]
    DIRECTION INPUT ;
    USE SIGNAL ;
    PORT
      LAYER M5 ;
        RECT  40.128 0 40.152 0.192 ;
    END
  END i_data[97]
  PIN i_data[98]
    DIRECTION INPUT ;
    USE SIGNAL ;
    PORT
      LAYER M5 ;
        RECT  40.416 0 40.44 0.192 ;
    END
  END i_data[98]
  PIN i_data[99]
    DIRECTION INPUT ;
    USE SIGNAL ;
    PORT
      LAYER M5 ;
        RECT  40.848 0 40.872 0.192 ;
    END
  END i_data[99]
  PIN i_data[9]
    DIRECTION INPUT ;
    USE SIGNAL ;
    PORT
      LAYER M5 ;
        RECT  7.872 0 7.896 0.192 ;
    END
  END i_data[9]
  PIN i_drain_slot[0]
    DIRECTION INPUT ;
    USE SIGNAL ;
    PORT
      LAYER M4 ;
        RECT  86.208 43.632 86.4 43.656 ;
    END
  END i_drain_slot[0]
  PIN i_drain_slot[10]
    DIRECTION INPUT ;
    USE SIGNAL ;
    PORT
      LAYER M4 ;
        RECT  86.208 55.728 86.4 55.752 ;
    END
  END i_drain_slot[10]
  PIN i_drain_slot[11]
    DIRECTION INPUT ;
    USE SIGNAL ;
    PORT
      LAYER M4 ;
        RECT  86.208 56.88 86.4 56.904 ;
    END
  END i_drain_slot[11]
  PIN i_drain_slot[12]
    DIRECTION INPUT ;
    USE SIGNAL ;
    PORT
      LAYER M4 ;
        RECT  86.208 58.032 86.4 58.056 ;
    END
  END i_drain_slot[12]
  PIN i_drain_slot[13]
    DIRECTION INPUT ;
    USE SIGNAL ;
    PORT
      LAYER M4 ;
        RECT  86.208 59.328 86.4 59.352 ;
    END
  END i_drain_slot[13]
  PIN i_drain_slot[14]
    DIRECTION INPUT ;
    USE SIGNAL ;
    PORT
      LAYER M4 ;
        RECT  86.208 60.48 86.4 60.504 ;
    END
  END i_drain_slot[14]
  PIN i_drain_slot[15]
    DIRECTION INPUT ;
    USE SIGNAL ;
    PORT
      LAYER M4 ;
        RECT  86.208 61.776 86.4 61.8 ;
    END
  END i_drain_slot[15]
  PIN i_drain_slot[16]
    DIRECTION INPUT ;
    USE SIGNAL ;
    PORT
      LAYER M4 ;
        RECT  86.208 62.928 86.4 62.952 ;
    END
  END i_drain_slot[16]
  PIN i_drain_slot[17]
    DIRECTION INPUT ;
    USE SIGNAL ;
    PORT
      LAYER M4 ;
        RECT  86.208 64.08 86.4 64.104 ;
    END
  END i_drain_slot[17]
  PIN i_drain_slot[18]
    DIRECTION INPUT ;
    USE SIGNAL ;
    PORT
      LAYER M4 ;
        RECT  86.208 65.376 86.4 65.4 ;
    END
  END i_drain_slot[18]
  PIN i_drain_slot[19]
    DIRECTION INPUT ;
    USE SIGNAL ;
    PORT
      LAYER M4 ;
        RECT  86.208 66.528 86.4 66.552 ;
    END
  END i_drain_slot[19]
  PIN i_drain_slot[1]
    DIRECTION INPUT ;
    USE SIGNAL ;
    PORT
      LAYER M4 ;
        RECT  86.208 44.784 86.4 44.808 ;
    END
  END i_drain_slot[1]
  PIN i_drain_slot[20]
    DIRECTION INPUT ;
    USE SIGNAL ;
    PORT
      LAYER M4 ;
        RECT  86.208 67.824 86.4 67.848 ;
    END
  END i_drain_slot[20]
  PIN i_drain_slot[21]
    DIRECTION INPUT ;
    USE SIGNAL ;
    PORT
      LAYER M4 ;
        RECT  86.208 68.976 86.4 69 ;
    END
  END i_drain_slot[21]
  PIN i_drain_slot[22]
    DIRECTION INPUT ;
    USE SIGNAL ;
    PORT
      LAYER M4 ;
        RECT  86.208 70.128 86.4 70.152 ;
    END
  END i_drain_slot[22]
  PIN i_drain_slot[23]
    DIRECTION INPUT ;
    USE SIGNAL ;
    PORT
      LAYER M4 ;
        RECT  86.208 71.424 86.4 71.448 ;
    END
  END i_drain_slot[23]
  PIN i_drain_slot[24]
    DIRECTION INPUT ;
    USE SIGNAL ;
    PORT
      LAYER M4 ;
        RECT  86.208 72.576 86.4 72.6 ;
    END
  END i_drain_slot[24]
  PIN i_drain_slot[25]
    DIRECTION INPUT ;
    USE SIGNAL ;
    PORT
      LAYER M4 ;
        RECT  86.208 73.872 86.4 73.896 ;
    END
  END i_drain_slot[25]
  PIN i_drain_slot[26]
    DIRECTION INPUT ;
    USE SIGNAL ;
    PORT
      LAYER M4 ;
        RECT  86.208 75.024 86.4 75.048 ;
    END
  END i_drain_slot[26]
  PIN i_drain_slot[27]
    DIRECTION INPUT ;
    USE SIGNAL ;
    PORT
      LAYER M4 ;
        RECT  86.208 76.176 86.4 76.2 ;
    END
  END i_drain_slot[27]
  PIN i_drain_slot[28]
    DIRECTION INPUT ;
    USE SIGNAL ;
    PORT
      LAYER M4 ;
        RECT  86.208 77.472 86.4 77.496 ;
    END
  END i_drain_slot[28]
  PIN i_drain_slot[29]
    DIRECTION INPUT ;
    USE SIGNAL ;
    PORT
      LAYER M4 ;
        RECT  86.208 78.624 86.4 78.648 ;
    END
  END i_drain_slot[29]
  PIN i_drain_slot[2]
    DIRECTION INPUT ;
    USE SIGNAL ;
    PORT
      LAYER M4 ;
        RECT  86.208 45.936 86.4 45.96 ;
    END
  END i_drain_slot[2]
  PIN i_drain_slot[30]
    DIRECTION INPUT ;
    USE SIGNAL ;
    PORT
      LAYER M4 ;
        RECT  86.208 79.92 86.4 79.944 ;
    END
  END i_drain_slot[30]
  PIN i_drain_slot[31]
    DIRECTION INPUT ;
    USE SIGNAL ;
    PORT
      LAYER M4 ;
        RECT  86.208 81.072 86.4 81.096 ;
    END
  END i_drain_slot[31]
  PIN i_drain_slot[32]
    DIRECTION INPUT ;
    USE SIGNAL ;
    PORT
      LAYER M4 ;
        RECT  86.208 82.224 86.4 82.248 ;
    END
  END i_drain_slot[32]
  PIN i_drain_slot[33]
    DIRECTION INPUT ;
    USE SIGNAL ;
    PORT
      LAYER M4 ;
        RECT  86.208 83.52 86.4 83.544 ;
    END
  END i_drain_slot[33]
  PIN i_drain_slot[34]
    DIRECTION INPUT ;
    USE SIGNAL ;
    PORT
      LAYER M4 ;
        RECT  86.208 84.672 86.4 84.696 ;
    END
  END i_drain_slot[34]
  PIN i_drain_slot[35]
    DIRECTION INPUT ;
    USE SIGNAL ;
    PORT
      LAYER M4 ;
        RECT  86.208 85.968 86.4 85.992 ;
    END
  END i_drain_slot[35]
  PIN i_drain_slot[36]
    DIRECTION INPUT ;
    USE SIGNAL ;
    PORT
      LAYER M4 ;
        RECT  86.208 87.12 86.4 87.144 ;
    END
  END i_drain_slot[36]
  PIN i_drain_slot[37]
    DIRECTION INPUT ;
    USE SIGNAL ;
    PORT
      LAYER M4 ;
        RECT  86.208 88.272 86.4 88.296 ;
    END
  END i_drain_slot[37]
  PIN i_drain_slot[38]
    DIRECTION INPUT ;
    USE SIGNAL ;
    PORT
      LAYER M4 ;
        RECT  86.208 89.568 86.4 89.592 ;
    END
  END i_drain_slot[38]
  PIN i_drain_slot[39]
    DIRECTION INPUT ;
    USE SIGNAL ;
    PORT
      LAYER M4 ;
        RECT  86.208 90.72 86.4 90.744 ;
    END
  END i_drain_slot[39]
  PIN i_drain_slot[3]
    DIRECTION INPUT ;
    USE SIGNAL ;
    PORT
      LAYER M4 ;
        RECT  86.208 47.232 86.4 47.256 ;
    END
  END i_drain_slot[3]
  PIN i_drain_slot[40]
    DIRECTION INPUT ;
    USE SIGNAL ;
    PORT
      LAYER M4 ;
        RECT  86.208 92.016 86.4 92.04 ;
    END
  END i_drain_slot[40]
  PIN i_drain_slot[41]
    DIRECTION INPUT ;
    USE SIGNAL ;
    PORT
      LAYER M4 ;
        RECT  86.208 93.168 86.4 93.192 ;
    END
  END i_drain_slot[41]
  PIN i_drain_slot[42]
    DIRECTION INPUT ;
    USE SIGNAL ;
    PORT
      LAYER M4 ;
        RECT  86.208 94.32 86.4 94.344 ;
    END
  END i_drain_slot[42]
  PIN i_drain_slot[43]
    DIRECTION INPUT ;
    USE SIGNAL ;
    PORT
      LAYER M4 ;
        RECT  86.208 95.616 86.4 95.64 ;
    END
  END i_drain_slot[43]
  PIN i_drain_slot[44]
    DIRECTION INPUT ;
    USE SIGNAL ;
    PORT
      LAYER M4 ;
        RECT  86.208 96.768 86.4 96.792 ;
    END
  END i_drain_slot[44]
  PIN i_drain_slot[45]
    DIRECTION INPUT ;
    USE SIGNAL ;
    PORT
      LAYER M4 ;
        RECT  86.208 98.064 86.4 98.088 ;
    END
  END i_drain_slot[45]
  PIN i_drain_slot[46]
    DIRECTION INPUT ;
    USE SIGNAL ;
    PORT
      LAYER M4 ;
        RECT  86.208 99.216 86.4 99.24 ;
    END
  END i_drain_slot[46]
  PIN i_drain_slot[47]
    DIRECTION INPUT ;
    USE SIGNAL ;
    PORT
      LAYER M4 ;
        RECT  86.208 100.368 86.4 100.392 ;
    END
  END i_drain_slot[47]
  PIN i_drain_slot[48]
    DIRECTION INPUT ;
    USE SIGNAL ;
    PORT
      LAYER M4 ;
        RECT  86.208 101.664 86.4 101.688 ;
    END
  END i_drain_slot[48]
  PIN i_drain_slot[49]
    DIRECTION INPUT ;
    USE SIGNAL ;
    PORT
      LAYER M4 ;
        RECT  86.208 102.816 86.4 102.84 ;
    END
  END i_drain_slot[49]
  PIN i_drain_slot[4]
    DIRECTION INPUT ;
    USE SIGNAL ;
    PORT
      LAYER M4 ;
        RECT  86.208 48.384 86.4 48.408 ;
    END
  END i_drain_slot[4]
  PIN i_drain_slot[50]
    DIRECTION INPUT ;
    USE SIGNAL ;
    PORT
      LAYER M4 ;
        RECT  86.208 104.112 86.4 104.136 ;
    END
  END i_drain_slot[50]
  PIN i_drain_slot[51]
    DIRECTION INPUT ;
    USE SIGNAL ;
    PORT
      LAYER M4 ;
        RECT  86.208 105.264 86.4 105.288 ;
    END
  END i_drain_slot[51]
  PIN i_drain_slot[52]
    DIRECTION INPUT ;
    USE SIGNAL ;
    PORT
      LAYER M4 ;
        RECT  86.208 106.416 86.4 106.44 ;
    END
  END i_drain_slot[52]
  PIN i_drain_slot[53]
    DIRECTION INPUT ;
    USE SIGNAL ;
    PORT
      LAYER M4 ;
        RECT  86.208 107.712 86.4 107.736 ;
    END
  END i_drain_slot[53]
  PIN i_drain_slot[54]
    DIRECTION INPUT ;
    USE SIGNAL ;
    PORT
      LAYER M4 ;
        RECT  86.208 108.864 86.4 108.888 ;
    END
  END i_drain_slot[54]
  PIN i_drain_slot[55]
    DIRECTION INPUT ;
    USE SIGNAL ;
    PORT
      LAYER M4 ;
        RECT  86.208 110.16 86.4 110.184 ;
    END
  END i_drain_slot[55]
  PIN i_drain_slot[56]
    DIRECTION INPUT ;
    USE SIGNAL ;
    PORT
      LAYER M4 ;
        RECT  86.208 111.312 86.4 111.336 ;
    END
  END i_drain_slot[56]
  PIN i_drain_slot[57]
    DIRECTION INPUT ;
    USE SIGNAL ;
    PORT
      LAYER M4 ;
        RECT  86.208 112.464 86.4 112.488 ;
    END
  END i_drain_slot[57]
  PIN i_drain_slot[58]
    DIRECTION INPUT ;
    USE SIGNAL ;
    PORT
      LAYER M4 ;
        RECT  86.208 113.76 86.4 113.784 ;
    END
  END i_drain_slot[58]
  PIN i_drain_slot[59]
    DIRECTION INPUT ;
    USE SIGNAL ;
    PORT
      LAYER M4 ;
        RECT  86.208 114.912 86.4 114.936 ;
    END
  END i_drain_slot[59]
  PIN i_drain_slot[5]
    DIRECTION INPUT ;
    USE SIGNAL ;
    PORT
      LAYER M4 ;
        RECT  86.208 49.68 86.4 49.704 ;
    END
  END i_drain_slot[5]
  PIN i_drain_slot[60]
    DIRECTION INPUT ;
    USE SIGNAL ;
    PORT
      LAYER M4 ;
        RECT  86.208 116.208 86.4 116.232 ;
    END
  END i_drain_slot[60]
  PIN i_drain_slot[61]
    DIRECTION INPUT ;
    USE SIGNAL ;
    PORT
      LAYER M4 ;
        RECT  86.208 117.36 86.4 117.384 ;
    END
  END i_drain_slot[61]
  PIN i_drain_slot[62]
    DIRECTION INPUT ;
    USE SIGNAL ;
    PORT
      LAYER M4 ;
        RECT  86.208 118.512 86.4 118.536 ;
    END
  END i_drain_slot[62]
  PIN i_drain_slot[63]
    DIRECTION INPUT ;
    USE SIGNAL ;
    PORT
      LAYER M4 ;
        RECT  86.208 119.808 86.4 119.832 ;
    END
  END i_drain_slot[63]
  PIN i_drain_slot[6]
    DIRECTION INPUT ;
    USE SIGNAL ;
    PORT
      LAYER M4 ;
        RECT  86.208 50.832 86.4 50.856 ;
    END
  END i_drain_slot[6]
  PIN i_drain_slot[7]
    DIRECTION INPUT ;
    USE SIGNAL ;
    PORT
      LAYER M4 ;
        RECT  86.208 51.984 86.4 52.008 ;
    END
  END i_drain_slot[7]
  PIN i_drain_slot[8]
    DIRECTION INPUT ;
    USE SIGNAL ;
    PORT
      LAYER M4 ;
        RECT  86.208 53.28 86.4 53.304 ;
    END
  END i_drain_slot[8]
  PIN i_drain_slot[9]
    DIRECTION INPUT ;
    USE SIGNAL ;
    PORT
      LAYER M4 ;
        RECT  86.208 54.432 86.4 54.456 ;
    END
  END i_drain_slot[9]
  PIN i_drain_v[0]
    DIRECTION INPUT ;
    USE SIGNAL ;
    PORT
      LAYER M4 ;
        RECT  86.208 4.896 86.4 4.92 ;
    END
  END i_drain_v[0]
  PIN i_drain_v[10]
    DIRECTION INPUT ;
    USE SIGNAL ;
    PORT
      LAYER M4 ;
        RECT  86.208 16.992 86.4 17.016 ;
    END
  END i_drain_v[10]
  PIN i_drain_v[11]
    DIRECTION INPUT ;
    USE SIGNAL ;
    PORT
      LAYER M4 ;
        RECT  86.208 18.144 86.4 18.168 ;
    END
  END i_drain_v[11]
  PIN i_drain_v[12]
    DIRECTION INPUT ;
    USE SIGNAL ;
    PORT
      LAYER M4 ;
        RECT  86.208 19.44 86.4 19.464 ;
    END
  END i_drain_v[12]
  PIN i_drain_v[13]
    DIRECTION INPUT ;
    USE SIGNAL ;
    PORT
      LAYER M4 ;
        RECT  86.208 20.592 86.4 20.616 ;
    END
  END i_drain_v[13]
  PIN i_drain_v[14]
    DIRECTION INPUT ;
    USE SIGNAL ;
    PORT
      LAYER M4 ;
        RECT  86.208 21.744 86.4 21.768 ;
    END
  END i_drain_v[14]
  PIN i_drain_v[15]
    DIRECTION INPUT ;
    USE SIGNAL ;
    PORT
      LAYER M4 ;
        RECT  86.208 23.04 86.4 23.064 ;
    END
  END i_drain_v[15]
  PIN i_drain_v[16]
    DIRECTION INPUT ;
    USE SIGNAL ;
    PORT
      LAYER M4 ;
        RECT  86.208 24.192 86.4 24.216 ;
    END
  END i_drain_v[16]
  PIN i_drain_v[17]
    DIRECTION INPUT ;
    USE SIGNAL ;
    PORT
      LAYER M4 ;
        RECT  86.208 25.488 86.4 25.512 ;
    END
  END i_drain_v[17]
  PIN i_drain_v[18]
    DIRECTION INPUT ;
    USE SIGNAL ;
    PORT
      LAYER M4 ;
        RECT  86.208 26.64 86.4 26.664 ;
    END
  END i_drain_v[18]
  PIN i_drain_v[19]
    DIRECTION INPUT ;
    USE SIGNAL ;
    PORT
      LAYER M4 ;
        RECT  86.208 27.792 86.4 27.816 ;
    END
  END i_drain_v[19]
  PIN i_drain_v[1]
    DIRECTION INPUT ;
    USE SIGNAL ;
    PORT
      LAYER M4 ;
        RECT  86.208 6.048 86.4 6.072 ;
    END
  END i_drain_v[1]
  PIN i_drain_v[20]
    DIRECTION INPUT ;
    USE SIGNAL ;
    PORT
      LAYER M4 ;
        RECT  86.208 29.088 86.4 29.112 ;
    END
  END i_drain_v[20]
  PIN i_drain_v[21]
    DIRECTION INPUT ;
    USE SIGNAL ;
    PORT
      LAYER M4 ;
        RECT  86.208 30.24 86.4 30.264 ;
    END
  END i_drain_v[21]
  PIN i_drain_v[22]
    DIRECTION INPUT ;
    USE SIGNAL ;
    PORT
      LAYER M4 ;
        RECT  86.208 31.536 86.4 31.56 ;
    END
  END i_drain_v[22]
  PIN i_drain_v[23]
    DIRECTION INPUT ;
    USE SIGNAL ;
    PORT
      LAYER M4 ;
        RECT  86.208 32.688 86.4 32.712 ;
    END
  END i_drain_v[23]
  PIN i_drain_v[24]
    DIRECTION INPUT ;
    USE SIGNAL ;
    PORT
      LAYER M4 ;
        RECT  86.208 33.84 86.4 33.864 ;
    END
  END i_drain_v[24]
  PIN i_drain_v[25]
    DIRECTION INPUT ;
    USE SIGNAL ;
    PORT
      LAYER M4 ;
        RECT  86.208 35.136 86.4 35.16 ;
    END
  END i_drain_v[25]
  PIN i_drain_v[26]
    DIRECTION INPUT ;
    USE SIGNAL ;
    PORT
      LAYER M4 ;
        RECT  86.208 36.288 86.4 36.312 ;
    END
  END i_drain_v[26]
  PIN i_drain_v[27]
    DIRECTION INPUT ;
    USE SIGNAL ;
    PORT
      LAYER M4 ;
        RECT  86.208 37.584 86.4 37.608 ;
    END
  END i_drain_v[27]
  PIN i_drain_v[28]
    DIRECTION INPUT ;
    USE SIGNAL ;
    PORT
      LAYER M4 ;
        RECT  86.208 38.736 86.4 38.76 ;
    END
  END i_drain_v[28]
  PIN i_drain_v[29]
    DIRECTION INPUT ;
    USE SIGNAL ;
    PORT
      LAYER M4 ;
        RECT  86.208 39.888 86.4 39.912 ;
    END
  END i_drain_v[29]
  PIN i_drain_v[2]
    DIRECTION INPUT ;
    USE SIGNAL ;
    PORT
      LAYER M4 ;
        RECT  86.208 7.344 86.4 7.368 ;
    END
  END i_drain_v[2]
  PIN i_drain_v[30]
    DIRECTION INPUT ;
    USE SIGNAL ;
    PORT
      LAYER M4 ;
        RECT  86.208 41.184 86.4 41.208 ;
    END
  END i_drain_v[30]
  PIN i_drain_v[31]
    DIRECTION INPUT ;
    USE SIGNAL ;
    PORT
      LAYER M4 ;
        RECT  86.208 42.336 86.4 42.36 ;
    END
  END i_drain_v[31]
  PIN i_drain_v[3]
    DIRECTION INPUT ;
    USE SIGNAL ;
    PORT
      LAYER M4 ;
        RECT  86.208 8.496 86.4 8.52 ;
    END
  END i_drain_v[3]
  PIN i_drain_v[4]
    DIRECTION INPUT ;
    USE SIGNAL ;
    PORT
      LAYER M4 ;
        RECT  86.208 9.648 86.4 9.672 ;
    END
  END i_drain_v[4]
  PIN i_drain_v[5]
    DIRECTION INPUT ;
    USE SIGNAL ;
    PORT
      LAYER M4 ;
        RECT  86.208 10.944 86.4 10.968 ;
    END
  END i_drain_v[5]
  PIN i_drain_v[6]
    DIRECTION INPUT ;
    USE SIGNAL ;
    PORT
      LAYER M4 ;
        RECT  86.208 12.096 86.4 12.12 ;
    END
  END i_drain_v[6]
  PIN i_drain_v[7]
    DIRECTION INPUT ;
    USE SIGNAL ;
    PORT
      LAYER M4 ;
        RECT  86.208 13.392 86.4 13.416 ;
    END
  END i_drain_v[7]
  PIN i_drain_v[8]
    DIRECTION INPUT ;
    USE SIGNAL ;
    PORT
      LAYER M4 ;
        RECT  86.208 14.544 86.4 14.568 ;
    END
  END i_drain_v[8]
  PIN i_drain_v[9]
    DIRECTION INPUT ;
    USE SIGNAL ;
    PORT
      LAYER M4 ;
        RECT  86.208 15.696 86.4 15.72 ;
    END
  END i_drain_v[9]
  PIN i_sel[0]
    DIRECTION INPUT ;
    USE SIGNAL ;
    PORT
      LAYER M4 ;
        RECT  0 4.752 0.192 4.776 ;
    END
  END i_sel[0]
  PIN i_sel[100]
    DIRECTION INPUT ;
    USE SIGNAL ;
    PORT
      LAYER M4 ;
        RECT  0 22.608 0.192 22.632 ;
    END
  END i_sel[100]
  PIN i_sel[101]
    DIRECTION INPUT ;
    USE SIGNAL ;
    PORT
      LAYER M4 ;
        RECT  0 22.752 0.192 22.776 ;
    END
  END i_sel[101]
  PIN i_sel[102]
    DIRECTION INPUT ;
    USE SIGNAL ;
    PORT
      LAYER M4 ;
        RECT  0 23.04 0.192 23.064 ;
    END
  END i_sel[102]
  PIN i_sel[103]
    DIRECTION INPUT ;
    USE SIGNAL ;
    PORT
      LAYER M4 ;
        RECT  0 23.184 0.192 23.208 ;
    END
  END i_sel[103]
  PIN i_sel[104]
    DIRECTION INPUT ;
    USE SIGNAL ;
    PORT
      LAYER M4 ;
        RECT  0 23.328 0.192 23.352 ;
    END
  END i_sel[104]
  PIN i_sel[105]
    DIRECTION INPUT ;
    USE SIGNAL ;
    PORT
      LAYER M4 ;
        RECT  0 23.472 0.192 23.496 ;
    END
  END i_sel[105]
  PIN i_sel[106]
    DIRECTION INPUT ;
    USE SIGNAL ;
    PORT
      LAYER M4 ;
        RECT  0 23.76 0.192 23.784 ;
    END
  END i_sel[106]
  PIN i_sel[107]
    DIRECTION INPUT ;
    USE SIGNAL ;
    PORT
      LAYER M4 ;
        RECT  0 23.904 0.192 23.928 ;
    END
  END i_sel[107]
  PIN i_sel[108]
    DIRECTION INPUT ;
    USE SIGNAL ;
    PORT
      LAYER M4 ;
        RECT  0 24.048 0.192 24.072 ;
    END
  END i_sel[108]
  PIN i_sel[109]
    DIRECTION INPUT ;
    USE SIGNAL ;
    PORT
      LAYER M4 ;
        RECT  0 24.192 0.192 24.216 ;
    END
  END i_sel[109]
  PIN i_sel[10]
    DIRECTION INPUT ;
    USE SIGNAL ;
    PORT
      LAYER M4 ;
        RECT  0 6.48 0.192 6.504 ;
    END
  END i_sel[10]
  PIN i_sel[110]
    DIRECTION INPUT ;
    USE SIGNAL ;
    PORT
      LAYER M4 ;
        RECT  0 24.48 0.192 24.504 ;
    END
  END i_sel[110]
  PIN i_sel[111]
    DIRECTION INPUT ;
    USE SIGNAL ;
    PORT
      LAYER M4 ;
        RECT  0 24.624 0.192 24.648 ;
    END
  END i_sel[111]
  PIN i_sel[112]
    DIRECTION INPUT ;
    USE SIGNAL ;
    PORT
      LAYER M4 ;
        RECT  0 24.768 0.192 24.792 ;
    END
  END i_sel[112]
  PIN i_sel[113]
    DIRECTION INPUT ;
    USE SIGNAL ;
    PORT
      LAYER M4 ;
        RECT  0 24.912 0.192 24.936 ;
    END
  END i_sel[113]
  PIN i_sel[114]
    DIRECTION INPUT ;
    USE SIGNAL ;
    PORT
      LAYER M4 ;
        RECT  0 25.2 0.192 25.224 ;
    END
  END i_sel[114]
  PIN i_sel[115]
    DIRECTION INPUT ;
    USE SIGNAL ;
    PORT
      LAYER M4 ;
        RECT  0 25.344 0.192 25.368 ;
    END
  END i_sel[115]
  PIN i_sel[116]
    DIRECTION INPUT ;
    USE SIGNAL ;
    PORT
      LAYER M4 ;
        RECT  0 25.488 0.192 25.512 ;
    END
  END i_sel[116]
  PIN i_sel[117]
    DIRECTION INPUT ;
    USE SIGNAL ;
    PORT
      LAYER M4 ;
        RECT  0 25.632 0.192 25.656 ;
    END
  END i_sel[117]
  PIN i_sel[118]
    DIRECTION INPUT ;
    USE SIGNAL ;
    PORT
      LAYER M4 ;
        RECT  0 25.92 0.192 25.944 ;
    END
  END i_sel[118]
  PIN i_sel[119]
    DIRECTION INPUT ;
    USE SIGNAL ;
    PORT
      LAYER M4 ;
        RECT  0 26.064 0.192 26.088 ;
    END
  END i_sel[119]
  PIN i_sel[11]
    DIRECTION INPUT ;
    USE SIGNAL ;
    PORT
      LAYER M4 ;
        RECT  0 6.624 0.192 6.648 ;
    END
  END i_sel[11]
  PIN i_sel[120]
    DIRECTION INPUT ;
    USE SIGNAL ;
    PORT
      LAYER M4 ;
        RECT  0 26.208 0.192 26.232 ;
    END
  END i_sel[120]
  PIN i_sel[121]
    DIRECTION INPUT ;
    USE SIGNAL ;
    PORT
      LAYER M4 ;
        RECT  0 26.352 0.192 26.376 ;
    END
  END i_sel[121]
  PIN i_sel[122]
    DIRECTION INPUT ;
    USE SIGNAL ;
    PORT
      LAYER M4 ;
        RECT  0 26.64 0.192 26.664 ;
    END
  END i_sel[122]
  PIN i_sel[123]
    DIRECTION INPUT ;
    USE SIGNAL ;
    PORT
      LAYER M4 ;
        RECT  0 26.784 0.192 26.808 ;
    END
  END i_sel[123]
  PIN i_sel[124]
    DIRECTION INPUT ;
    USE SIGNAL ;
    PORT
      LAYER M4 ;
        RECT  0 26.928 0.192 26.952 ;
    END
  END i_sel[124]
  PIN i_sel[125]
    DIRECTION INPUT ;
    USE SIGNAL ;
    PORT
      LAYER M4 ;
        RECT  0 27.072 0.192 27.096 ;
    END
  END i_sel[125]
  PIN i_sel[126]
    DIRECTION INPUT ;
    USE SIGNAL ;
    PORT
      LAYER M4 ;
        RECT  0 27.36 0.192 27.384 ;
    END
  END i_sel[126]
  PIN i_sel[127]
    DIRECTION INPUT ;
    USE SIGNAL ;
    PORT
      LAYER M4 ;
        RECT  0 27.504 0.192 27.528 ;
    END
  END i_sel[127]
  PIN i_sel[128]
    DIRECTION INPUT ;
    USE SIGNAL ;
    PORT
      LAYER M4 ;
        RECT  0 27.648 0.192 27.672 ;
    END
  END i_sel[128]
  PIN i_sel[129]
    DIRECTION INPUT ;
    USE SIGNAL ;
    PORT
      LAYER M4 ;
        RECT  0 27.792 0.192 27.816 ;
    END
  END i_sel[129]
  PIN i_sel[12]
    DIRECTION INPUT ;
    USE SIGNAL ;
    PORT
      LAYER M4 ;
        RECT  0 6.912 0.192 6.936 ;
    END
  END i_sel[12]
  PIN i_sel[130]
    DIRECTION INPUT ;
    USE SIGNAL ;
    PORT
      LAYER M4 ;
        RECT  0 28.08 0.192 28.104 ;
    END
  END i_sel[130]
  PIN i_sel[131]
    DIRECTION INPUT ;
    USE SIGNAL ;
    PORT
      LAYER M4 ;
        RECT  0 28.224 0.192 28.248 ;
    END
  END i_sel[131]
  PIN i_sel[132]
    DIRECTION INPUT ;
    USE SIGNAL ;
    PORT
      LAYER M4 ;
        RECT  0 28.368 0.192 28.392 ;
    END
  END i_sel[132]
  PIN i_sel[133]
    DIRECTION INPUT ;
    USE SIGNAL ;
    PORT
      LAYER M4 ;
        RECT  0 28.512 0.192 28.536 ;
    END
  END i_sel[133]
  PIN i_sel[134]
    DIRECTION INPUT ;
    USE SIGNAL ;
    PORT
      LAYER M4 ;
        RECT  0 28.8 0.192 28.824 ;
    END
  END i_sel[134]
  PIN i_sel[135]
    DIRECTION INPUT ;
    USE SIGNAL ;
    PORT
      LAYER M4 ;
        RECT  0 28.944 0.192 28.968 ;
    END
  END i_sel[135]
  PIN i_sel[136]
    DIRECTION INPUT ;
    USE SIGNAL ;
    PORT
      LAYER M4 ;
        RECT  0 29.088 0.192 29.112 ;
    END
  END i_sel[136]
  PIN i_sel[137]
    DIRECTION INPUT ;
    USE SIGNAL ;
    PORT
      LAYER M4 ;
        RECT  0 29.232 0.192 29.256 ;
    END
  END i_sel[137]
  PIN i_sel[138]
    DIRECTION INPUT ;
    USE SIGNAL ;
    PORT
      LAYER M4 ;
        RECT  0 29.52 0.192 29.544 ;
    END
  END i_sel[138]
  PIN i_sel[139]
    DIRECTION INPUT ;
    USE SIGNAL ;
    PORT
      LAYER M4 ;
        RECT  0 29.664 0.192 29.688 ;
    END
  END i_sel[139]
  PIN i_sel[13]
    DIRECTION INPUT ;
    USE SIGNAL ;
    PORT
      LAYER M4 ;
        RECT  0 7.056 0.192 7.08 ;
    END
  END i_sel[13]
  PIN i_sel[140]
    DIRECTION INPUT ;
    USE SIGNAL ;
    PORT
      LAYER M4 ;
        RECT  0 29.808 0.192 29.832 ;
    END
  END i_sel[140]
  PIN i_sel[141]
    DIRECTION INPUT ;
    USE SIGNAL ;
    PORT
      LAYER M4 ;
        RECT  0 29.952 0.192 29.976 ;
    END
  END i_sel[141]
  PIN i_sel[142]
    DIRECTION INPUT ;
    USE SIGNAL ;
    PORT
      LAYER M4 ;
        RECT  0 30.24 0.192 30.264 ;
    END
  END i_sel[142]
  PIN i_sel[143]
    DIRECTION INPUT ;
    USE SIGNAL ;
    PORT
      LAYER M4 ;
        RECT  0 30.384 0.192 30.408 ;
    END
  END i_sel[143]
  PIN i_sel[144]
    DIRECTION INPUT ;
    USE SIGNAL ;
    PORT
      LAYER M4 ;
        RECT  0 30.528 0.192 30.552 ;
    END
  END i_sel[144]
  PIN i_sel[145]
    DIRECTION INPUT ;
    USE SIGNAL ;
    PORT
      LAYER M4 ;
        RECT  0 30.672 0.192 30.696 ;
    END
  END i_sel[145]
  PIN i_sel[146]
    DIRECTION INPUT ;
    USE SIGNAL ;
    PORT
      LAYER M4 ;
        RECT  0 30.96 0.192 30.984 ;
    END
  END i_sel[146]
  PIN i_sel[147]
    DIRECTION INPUT ;
    USE SIGNAL ;
    PORT
      LAYER M4 ;
        RECT  0 31.104 0.192 31.128 ;
    END
  END i_sel[147]
  PIN i_sel[148]
    DIRECTION INPUT ;
    USE SIGNAL ;
    PORT
      LAYER M4 ;
        RECT  0 31.248 0.192 31.272 ;
    END
  END i_sel[148]
  PIN i_sel[149]
    DIRECTION INPUT ;
    USE SIGNAL ;
    PORT
      LAYER M4 ;
        RECT  0 31.392 0.192 31.416 ;
    END
  END i_sel[149]
  PIN i_sel[14]
    DIRECTION INPUT ;
    USE SIGNAL ;
    PORT
      LAYER M4 ;
        RECT  0 7.2 0.192 7.224 ;
    END
  END i_sel[14]
  PIN i_sel[150]
    DIRECTION INPUT ;
    USE SIGNAL ;
    PORT
      LAYER M4 ;
        RECT  0 31.68 0.192 31.704 ;
    END
  END i_sel[150]
  PIN i_sel[151]
    DIRECTION INPUT ;
    USE SIGNAL ;
    PORT
      LAYER M4 ;
        RECT  0 31.824 0.192 31.848 ;
    END
  END i_sel[151]
  PIN i_sel[152]
    DIRECTION INPUT ;
    USE SIGNAL ;
    PORT
      LAYER M4 ;
        RECT  0 31.968 0.192 31.992 ;
    END
  END i_sel[152]
  PIN i_sel[153]
    DIRECTION INPUT ;
    USE SIGNAL ;
    PORT
      LAYER M4 ;
        RECT  0 32.112 0.192 32.136 ;
    END
  END i_sel[153]
  PIN i_sel[154]
    DIRECTION INPUT ;
    USE SIGNAL ;
    PORT
      LAYER M4 ;
        RECT  0 32.4 0.192 32.424 ;
    END
  END i_sel[154]
  PIN i_sel[155]
    DIRECTION INPUT ;
    USE SIGNAL ;
    PORT
      LAYER M4 ;
        RECT  0 32.544 0.192 32.568 ;
    END
  END i_sel[155]
  PIN i_sel[156]
    DIRECTION INPUT ;
    USE SIGNAL ;
    PORT
      LAYER M4 ;
        RECT  0 32.688 0.192 32.712 ;
    END
  END i_sel[156]
  PIN i_sel[157]
    DIRECTION INPUT ;
    USE SIGNAL ;
    PORT
      LAYER M4 ;
        RECT  0 32.832 0.192 32.856 ;
    END
  END i_sel[157]
  PIN i_sel[158]
    DIRECTION INPUT ;
    USE SIGNAL ;
    PORT
      LAYER M4 ;
        RECT  0 33.12 0.192 33.144 ;
    END
  END i_sel[158]
  PIN i_sel[159]
    DIRECTION INPUT ;
    USE SIGNAL ;
    PORT
      LAYER M4 ;
        RECT  0 33.264 0.192 33.288 ;
    END
  END i_sel[159]
  PIN i_sel[15]
    DIRECTION INPUT ;
    USE SIGNAL ;
    PORT
      LAYER M4 ;
        RECT  0 7.344 0.192 7.368 ;
    END
  END i_sel[15]
  PIN i_sel[160]
    DIRECTION INPUT ;
    USE SIGNAL ;
    PORT
      LAYER M4 ;
        RECT  0 33.408 0.192 33.432 ;
    END
  END i_sel[160]
  PIN i_sel[161]
    DIRECTION INPUT ;
    USE SIGNAL ;
    PORT
      LAYER M4 ;
        RECT  0 33.552 0.192 33.576 ;
    END
  END i_sel[161]
  PIN i_sel[162]
    DIRECTION INPUT ;
    USE SIGNAL ;
    PORT
      LAYER M4 ;
        RECT  0 33.84 0.192 33.864 ;
    END
  END i_sel[162]
  PIN i_sel[163]
    DIRECTION INPUT ;
    USE SIGNAL ;
    PORT
      LAYER M4 ;
        RECT  0 33.984 0.192 34.008 ;
    END
  END i_sel[163]
  PIN i_sel[164]
    DIRECTION INPUT ;
    USE SIGNAL ;
    PORT
      LAYER M4 ;
        RECT  0 34.128 0.192 34.152 ;
    END
  END i_sel[164]
  PIN i_sel[165]
    DIRECTION INPUT ;
    USE SIGNAL ;
    PORT
      LAYER M4 ;
        RECT  0 34.272 0.192 34.296 ;
    END
  END i_sel[165]
  PIN i_sel[166]
    DIRECTION INPUT ;
    USE SIGNAL ;
    PORT
      LAYER M4 ;
        RECT  0 34.56 0.192 34.584 ;
    END
  END i_sel[166]
  PIN i_sel[167]
    DIRECTION INPUT ;
    USE SIGNAL ;
    PORT
      LAYER M4 ;
        RECT  0 34.704 0.192 34.728 ;
    END
  END i_sel[167]
  PIN i_sel[168]
    DIRECTION INPUT ;
    USE SIGNAL ;
    PORT
      LAYER M4 ;
        RECT  0 34.848 0.192 34.872 ;
    END
  END i_sel[168]
  PIN i_sel[169]
    DIRECTION INPUT ;
    USE SIGNAL ;
    PORT
      LAYER M4 ;
        RECT  0 34.992 0.192 35.016 ;
    END
  END i_sel[169]
  PIN i_sel[16]
    DIRECTION INPUT ;
    USE SIGNAL ;
    PORT
      LAYER M4 ;
        RECT  0 7.632 0.192 7.656 ;
    END
  END i_sel[16]
  PIN i_sel[170]
    DIRECTION INPUT ;
    USE SIGNAL ;
    PORT
      LAYER M4 ;
        RECT  0 35.136 0.192 35.16 ;
    END
  END i_sel[170]
  PIN i_sel[171]
    DIRECTION INPUT ;
    USE SIGNAL ;
    PORT
      LAYER M4 ;
        RECT  0 35.424 0.192 35.448 ;
    END
  END i_sel[171]
  PIN i_sel[172]
    DIRECTION INPUT ;
    USE SIGNAL ;
    PORT
      LAYER M4 ;
        RECT  0 35.568 0.192 35.592 ;
    END
  END i_sel[172]
  PIN i_sel[173]
    DIRECTION INPUT ;
    USE SIGNAL ;
    PORT
      LAYER M4 ;
        RECT  0 35.712 0.192 35.736 ;
    END
  END i_sel[173]
  PIN i_sel[174]
    DIRECTION INPUT ;
    USE SIGNAL ;
    PORT
      LAYER M4 ;
        RECT  0 35.856 0.192 35.88 ;
    END
  END i_sel[174]
  PIN i_sel[175]
    DIRECTION INPUT ;
    USE SIGNAL ;
    PORT
      LAYER M4 ;
        RECT  0 36.144 0.192 36.168 ;
    END
  END i_sel[175]
  PIN i_sel[176]
    DIRECTION INPUT ;
    USE SIGNAL ;
    PORT
      LAYER M4 ;
        RECT  0 36.288 0.192 36.312 ;
    END
  END i_sel[176]
  PIN i_sel[177]
    DIRECTION INPUT ;
    USE SIGNAL ;
    PORT
      LAYER M4 ;
        RECT  0 36.432 0.192 36.456 ;
    END
  END i_sel[177]
  PIN i_sel[178]
    DIRECTION INPUT ;
    USE SIGNAL ;
    PORT
      LAYER M4 ;
        RECT  0 36.576 0.192 36.6 ;
    END
  END i_sel[178]
  PIN i_sel[179]
    DIRECTION INPUT ;
    USE SIGNAL ;
    PORT
      LAYER M4 ;
        RECT  0 36.864 0.192 36.888 ;
    END
  END i_sel[179]
  PIN i_sel[17]
    DIRECTION INPUT ;
    USE SIGNAL ;
    PORT
      LAYER M4 ;
        RECT  0 7.776 0.192 7.8 ;
    END
  END i_sel[17]
  PIN i_sel[180]
    DIRECTION INPUT ;
    USE SIGNAL ;
    PORT
      LAYER M4 ;
        RECT  0 37.008 0.192 37.032 ;
    END
  END i_sel[180]
  PIN i_sel[181]
    DIRECTION INPUT ;
    USE SIGNAL ;
    PORT
      LAYER M4 ;
        RECT  0 37.152 0.192 37.176 ;
    END
  END i_sel[181]
  PIN i_sel[182]
    DIRECTION INPUT ;
    USE SIGNAL ;
    PORT
      LAYER M4 ;
        RECT  0 37.296 0.192 37.32 ;
    END
  END i_sel[182]
  PIN i_sel[183]
    DIRECTION INPUT ;
    USE SIGNAL ;
    PORT
      LAYER M4 ;
        RECT  0 37.584 0.192 37.608 ;
    END
  END i_sel[183]
  PIN i_sel[184]
    DIRECTION INPUT ;
    USE SIGNAL ;
    PORT
      LAYER M4 ;
        RECT  0 37.728 0.192 37.752 ;
    END
  END i_sel[184]
  PIN i_sel[185]
    DIRECTION INPUT ;
    USE SIGNAL ;
    PORT
      LAYER M4 ;
        RECT  0 37.872 0.192 37.896 ;
    END
  END i_sel[185]
  PIN i_sel[186]
    DIRECTION INPUT ;
    USE SIGNAL ;
    PORT
      LAYER M4 ;
        RECT  0 38.016 0.192 38.04 ;
    END
  END i_sel[186]
  PIN i_sel[187]
    DIRECTION INPUT ;
    USE SIGNAL ;
    PORT
      LAYER M4 ;
        RECT  0 38.304 0.192 38.328 ;
    END
  END i_sel[187]
  PIN i_sel[188]
    DIRECTION INPUT ;
    USE SIGNAL ;
    PORT
      LAYER M4 ;
        RECT  0 38.448 0.192 38.472 ;
    END
  END i_sel[188]
  PIN i_sel[189]
    DIRECTION INPUT ;
    USE SIGNAL ;
    PORT
      LAYER M4 ;
        RECT  0 38.592 0.192 38.616 ;
    END
  END i_sel[189]
  PIN i_sel[18]
    DIRECTION INPUT ;
    USE SIGNAL ;
    PORT
      LAYER M4 ;
        RECT  0 7.92 0.192 7.944 ;
    END
  END i_sel[18]
  PIN i_sel[190]
    DIRECTION INPUT ;
    USE SIGNAL ;
    PORT
      LAYER M4 ;
        RECT  0 38.736 0.192 38.76 ;
    END
  END i_sel[190]
  PIN i_sel[191]
    DIRECTION INPUT ;
    USE SIGNAL ;
    PORT
      LAYER M4 ;
        RECT  0 39.024 0.192 39.048 ;
    END
  END i_sel[191]
  PIN i_sel[192]
    DIRECTION INPUT ;
    USE SIGNAL ;
    PORT
      LAYER M4 ;
        RECT  0 39.168 0.192 39.192 ;
    END
  END i_sel[192]
  PIN i_sel[193]
    DIRECTION INPUT ;
    USE SIGNAL ;
    PORT
      LAYER M4 ;
        RECT  0 39.312 0.192 39.336 ;
    END
  END i_sel[193]
  PIN i_sel[194]
    DIRECTION INPUT ;
    USE SIGNAL ;
    PORT
      LAYER M4 ;
        RECT  0 39.456 0.192 39.48 ;
    END
  END i_sel[194]
  PIN i_sel[195]
    DIRECTION INPUT ;
    USE SIGNAL ;
    PORT
      LAYER M4 ;
        RECT  0 39.744 0.192 39.768 ;
    END
  END i_sel[195]
  PIN i_sel[196]
    DIRECTION INPUT ;
    USE SIGNAL ;
    PORT
      LAYER M4 ;
        RECT  0 39.888 0.192 39.912 ;
    END
  END i_sel[196]
  PIN i_sel[197]
    DIRECTION INPUT ;
    USE SIGNAL ;
    PORT
      LAYER M4 ;
        RECT  0 40.032 0.192 40.056 ;
    END
  END i_sel[197]
  PIN i_sel[198]
    DIRECTION INPUT ;
    USE SIGNAL ;
    PORT
      LAYER M4 ;
        RECT  0 40.176 0.192 40.2 ;
    END
  END i_sel[198]
  PIN i_sel[199]
    DIRECTION INPUT ;
    USE SIGNAL ;
    PORT
      LAYER M4 ;
        RECT  0 40.464 0.192 40.488 ;
    END
  END i_sel[199]
  PIN i_sel[19]
    DIRECTION INPUT ;
    USE SIGNAL ;
    PORT
      LAYER M4 ;
        RECT  0 8.064 0.192 8.088 ;
    END
  END i_sel[19]
  PIN i_sel[1]
    DIRECTION INPUT ;
    USE SIGNAL ;
    PORT
      LAYER M4 ;
        RECT  0 4.896 0.192 4.92 ;
    END
  END i_sel[1]
  PIN i_sel[200]
    DIRECTION INPUT ;
    USE SIGNAL ;
    PORT
      LAYER M4 ;
        RECT  0 40.608 0.192 40.632 ;
    END
  END i_sel[200]
  PIN i_sel[201]
    DIRECTION INPUT ;
    USE SIGNAL ;
    PORT
      LAYER M4 ;
        RECT  0 40.752 0.192 40.776 ;
    END
  END i_sel[201]
  PIN i_sel[202]
    DIRECTION INPUT ;
    USE SIGNAL ;
    PORT
      LAYER M4 ;
        RECT  0 40.896 0.192 40.92 ;
    END
  END i_sel[202]
  PIN i_sel[203]
    DIRECTION INPUT ;
    USE SIGNAL ;
    PORT
      LAYER M4 ;
        RECT  0 41.184 0.192 41.208 ;
    END
  END i_sel[203]
  PIN i_sel[204]
    DIRECTION INPUT ;
    USE SIGNAL ;
    PORT
      LAYER M4 ;
        RECT  0 41.328 0.192 41.352 ;
    END
  END i_sel[204]
  PIN i_sel[205]
    DIRECTION INPUT ;
    USE SIGNAL ;
    PORT
      LAYER M4 ;
        RECT  0 41.472 0.192 41.496 ;
    END
  END i_sel[205]
  PIN i_sel[206]
    DIRECTION INPUT ;
    USE SIGNAL ;
    PORT
      LAYER M4 ;
        RECT  0 41.616 0.192 41.64 ;
    END
  END i_sel[206]
  PIN i_sel[207]
    DIRECTION INPUT ;
    USE SIGNAL ;
    PORT
      LAYER M4 ;
        RECT  0 41.904 0.192 41.928 ;
    END
  END i_sel[207]
  PIN i_sel[208]
    DIRECTION INPUT ;
    USE SIGNAL ;
    PORT
      LAYER M4 ;
        RECT  0 42.048 0.192 42.072 ;
    END
  END i_sel[208]
  PIN i_sel[209]
    DIRECTION INPUT ;
    USE SIGNAL ;
    PORT
      LAYER M4 ;
        RECT  0 42.192 0.192 42.216 ;
    END
  END i_sel[209]
  PIN i_sel[20]
    DIRECTION INPUT ;
    USE SIGNAL ;
    PORT
      LAYER M4 ;
        RECT  0 8.352 0.192 8.376 ;
    END
  END i_sel[20]
  PIN i_sel[210]
    DIRECTION INPUT ;
    USE SIGNAL ;
    PORT
      LAYER M4 ;
        RECT  0 42.336 0.192 42.36 ;
    END
  END i_sel[210]
  PIN i_sel[211]
    DIRECTION INPUT ;
    USE SIGNAL ;
    PORT
      LAYER M4 ;
        RECT  0 42.624 0.192 42.648 ;
    END
  END i_sel[211]
  PIN i_sel[212]
    DIRECTION INPUT ;
    USE SIGNAL ;
    PORT
      LAYER M4 ;
        RECT  0 42.768 0.192 42.792 ;
    END
  END i_sel[212]
  PIN i_sel[213]
    DIRECTION INPUT ;
    USE SIGNAL ;
    PORT
      LAYER M4 ;
        RECT  0 42.912 0.192 42.936 ;
    END
  END i_sel[213]
  PIN i_sel[214]
    DIRECTION INPUT ;
    USE SIGNAL ;
    PORT
      LAYER M4 ;
        RECT  0 43.056 0.192 43.08 ;
    END
  END i_sel[214]
  PIN i_sel[215]
    DIRECTION INPUT ;
    USE SIGNAL ;
    PORT
      LAYER M4 ;
        RECT  0 43.344 0.192 43.368 ;
    END
  END i_sel[215]
  PIN i_sel[216]
    DIRECTION INPUT ;
    USE SIGNAL ;
    PORT
      LAYER M4 ;
        RECT  0 43.488 0.192 43.512 ;
    END
  END i_sel[216]
  PIN i_sel[217]
    DIRECTION INPUT ;
    USE SIGNAL ;
    PORT
      LAYER M4 ;
        RECT  0 43.632 0.192 43.656 ;
    END
  END i_sel[217]
  PIN i_sel[218]
    DIRECTION INPUT ;
    USE SIGNAL ;
    PORT
      LAYER M4 ;
        RECT  0 43.776 0.192 43.8 ;
    END
  END i_sel[218]
  PIN i_sel[219]
    DIRECTION INPUT ;
    USE SIGNAL ;
    PORT
      LAYER M4 ;
        RECT  0 44.064 0.192 44.088 ;
    END
  END i_sel[219]
  PIN i_sel[21]
    DIRECTION INPUT ;
    USE SIGNAL ;
    PORT
      LAYER M4 ;
        RECT  0 8.496 0.192 8.52 ;
    END
  END i_sel[21]
  PIN i_sel[220]
    DIRECTION INPUT ;
    USE SIGNAL ;
    PORT
      LAYER M4 ;
        RECT  0 44.208 0.192 44.232 ;
    END
  END i_sel[220]
  PIN i_sel[221]
    DIRECTION INPUT ;
    USE SIGNAL ;
    PORT
      LAYER M4 ;
        RECT  0 44.352 0.192 44.376 ;
    END
  END i_sel[221]
  PIN i_sel[222]
    DIRECTION INPUT ;
    USE SIGNAL ;
    PORT
      LAYER M4 ;
        RECT  0 44.496 0.192 44.52 ;
    END
  END i_sel[222]
  PIN i_sel[223]
    DIRECTION INPUT ;
    USE SIGNAL ;
    PORT
      LAYER M4 ;
        RECT  0 44.784 0.192 44.808 ;
    END
  END i_sel[223]
  PIN i_sel[224]
    DIRECTION INPUT ;
    USE SIGNAL ;
    PORT
      LAYER M4 ;
        RECT  0 44.928 0.192 44.952 ;
    END
  END i_sel[224]
  PIN i_sel[225]
    DIRECTION INPUT ;
    USE SIGNAL ;
    PORT
      LAYER M4 ;
        RECT  0 45.072 0.192 45.096 ;
    END
  END i_sel[225]
  PIN i_sel[226]
    DIRECTION INPUT ;
    USE SIGNAL ;
    PORT
      LAYER M4 ;
        RECT  0 45.216 0.192 45.24 ;
    END
  END i_sel[226]
  PIN i_sel[227]
    DIRECTION INPUT ;
    USE SIGNAL ;
    PORT
      LAYER M4 ;
        RECT  0 45.504 0.192 45.528 ;
    END
  END i_sel[227]
  PIN i_sel[228]
    DIRECTION INPUT ;
    USE SIGNAL ;
    PORT
      LAYER M4 ;
        RECT  0 45.648 0.192 45.672 ;
    END
  END i_sel[228]
  PIN i_sel[229]
    DIRECTION INPUT ;
    USE SIGNAL ;
    PORT
      LAYER M4 ;
        RECT  0 45.792 0.192 45.816 ;
    END
  END i_sel[229]
  PIN i_sel[22]
    DIRECTION INPUT ;
    USE SIGNAL ;
    PORT
      LAYER M4 ;
        RECT  0 8.64 0.192 8.664 ;
    END
  END i_sel[22]
  PIN i_sel[230]
    DIRECTION INPUT ;
    USE SIGNAL ;
    PORT
      LAYER M4 ;
        RECT  0 45.936 0.192 45.96 ;
    END
  END i_sel[230]
  PIN i_sel[231]
    DIRECTION INPUT ;
    USE SIGNAL ;
    PORT
      LAYER M4 ;
        RECT  0 46.224 0.192 46.248 ;
    END
  END i_sel[231]
  PIN i_sel[232]
    DIRECTION INPUT ;
    USE SIGNAL ;
    PORT
      LAYER M4 ;
        RECT  0 46.368 0.192 46.392 ;
    END
  END i_sel[232]
  PIN i_sel[233]
    DIRECTION INPUT ;
    USE SIGNAL ;
    PORT
      LAYER M4 ;
        RECT  0 46.512 0.192 46.536 ;
    END
  END i_sel[233]
  PIN i_sel[234]
    DIRECTION INPUT ;
    USE SIGNAL ;
    PORT
      LAYER M4 ;
        RECT  0 46.656 0.192 46.68 ;
    END
  END i_sel[234]
  PIN i_sel[235]
    DIRECTION INPUT ;
    USE SIGNAL ;
    PORT
      LAYER M4 ;
        RECT  0 46.8 0.192 46.824 ;
    END
  END i_sel[235]
  PIN i_sel[236]
    DIRECTION INPUT ;
    USE SIGNAL ;
    PORT
      LAYER M4 ;
        RECT  0 47.088 0.192 47.112 ;
    END
  END i_sel[236]
  PIN i_sel[237]
    DIRECTION INPUT ;
    USE SIGNAL ;
    PORT
      LAYER M4 ;
        RECT  0 47.232 0.192 47.256 ;
    END
  END i_sel[237]
  PIN i_sel[238]
    DIRECTION INPUT ;
    USE SIGNAL ;
    PORT
      LAYER M4 ;
        RECT  0 47.376 0.192 47.4 ;
    END
  END i_sel[238]
  PIN i_sel[239]
    DIRECTION INPUT ;
    USE SIGNAL ;
    PORT
      LAYER M4 ;
        RECT  0 47.52 0.192 47.544 ;
    END
  END i_sel[239]
  PIN i_sel[23]
    DIRECTION INPUT ;
    USE SIGNAL ;
    PORT
      LAYER M4 ;
        RECT  0 8.784 0.192 8.808 ;
    END
  END i_sel[23]
  PIN i_sel[240]
    DIRECTION INPUT ;
    USE SIGNAL ;
    PORT
      LAYER M4 ;
        RECT  0 47.808 0.192 47.832 ;
    END
  END i_sel[240]
  PIN i_sel[241]
    DIRECTION INPUT ;
    USE SIGNAL ;
    PORT
      LAYER M4 ;
        RECT  0 47.952 0.192 47.976 ;
    END
  END i_sel[241]
  PIN i_sel[242]
    DIRECTION INPUT ;
    USE SIGNAL ;
    PORT
      LAYER M4 ;
        RECT  0 48.096 0.192 48.12 ;
    END
  END i_sel[242]
  PIN i_sel[243]
    DIRECTION INPUT ;
    USE SIGNAL ;
    PORT
      LAYER M4 ;
        RECT  0 48.24 0.192 48.264 ;
    END
  END i_sel[243]
  PIN i_sel[244]
    DIRECTION INPUT ;
    USE SIGNAL ;
    PORT
      LAYER M4 ;
        RECT  0 48.528 0.192 48.552 ;
    END
  END i_sel[244]
  PIN i_sel[245]
    DIRECTION INPUT ;
    USE SIGNAL ;
    PORT
      LAYER M4 ;
        RECT  0 48.672 0.192 48.696 ;
    END
  END i_sel[245]
  PIN i_sel[246]
    DIRECTION INPUT ;
    USE SIGNAL ;
    PORT
      LAYER M4 ;
        RECT  0 48.816 0.192 48.84 ;
    END
  END i_sel[246]
  PIN i_sel[247]
    DIRECTION INPUT ;
    USE SIGNAL ;
    PORT
      LAYER M4 ;
        RECT  0 48.96 0.192 48.984 ;
    END
  END i_sel[247]
  PIN i_sel[248]
    DIRECTION INPUT ;
    USE SIGNAL ;
    PORT
      LAYER M4 ;
        RECT  0 49.248 0.192 49.272 ;
    END
  END i_sel[248]
  PIN i_sel[249]
    DIRECTION INPUT ;
    USE SIGNAL ;
    PORT
      LAYER M4 ;
        RECT  0 49.392 0.192 49.416 ;
    END
  END i_sel[249]
  PIN i_sel[24]
    DIRECTION INPUT ;
    USE SIGNAL ;
    PORT
      LAYER M4 ;
        RECT  0 9.072 0.192 9.096 ;
    END
  END i_sel[24]
  PIN i_sel[250]
    DIRECTION INPUT ;
    USE SIGNAL ;
    PORT
      LAYER M4 ;
        RECT  0 49.536 0.192 49.56 ;
    END
  END i_sel[250]
  PIN i_sel[251]
    DIRECTION INPUT ;
    USE SIGNAL ;
    PORT
      LAYER M4 ;
        RECT  0 49.68 0.192 49.704 ;
    END
  END i_sel[251]
  PIN i_sel[252]
    DIRECTION INPUT ;
    USE SIGNAL ;
    PORT
      LAYER M4 ;
        RECT  0 49.968 0.192 49.992 ;
    END
  END i_sel[252]
  PIN i_sel[253]
    DIRECTION INPUT ;
    USE SIGNAL ;
    PORT
      LAYER M4 ;
        RECT  0 50.112 0.192 50.136 ;
    END
  END i_sel[253]
  PIN i_sel[254]
    DIRECTION INPUT ;
    USE SIGNAL ;
    PORT
      LAYER M4 ;
        RECT  0 50.256 0.192 50.28 ;
    END
  END i_sel[254]
  PIN i_sel[255]
    DIRECTION INPUT ;
    USE SIGNAL ;
    PORT
      LAYER M4 ;
        RECT  0 50.4 0.192 50.424 ;
    END
  END i_sel[255]
  PIN i_sel[256]
    DIRECTION INPUT ;
    USE SIGNAL ;
    PORT
      LAYER M4 ;
        RECT  0 50.688 0.192 50.712 ;
    END
  END i_sel[256]
  PIN i_sel[257]
    DIRECTION INPUT ;
    USE SIGNAL ;
    PORT
      LAYER M4 ;
        RECT  0 50.832 0.192 50.856 ;
    END
  END i_sel[257]
  PIN i_sel[258]
    DIRECTION INPUT ;
    USE SIGNAL ;
    PORT
      LAYER M4 ;
        RECT  0 50.976 0.192 51 ;
    END
  END i_sel[258]
  PIN i_sel[259]
    DIRECTION INPUT ;
    USE SIGNAL ;
    PORT
      LAYER M4 ;
        RECT  0 51.12 0.192 51.144 ;
    END
  END i_sel[259]
  PIN i_sel[25]
    DIRECTION INPUT ;
    USE SIGNAL ;
    PORT
      LAYER M4 ;
        RECT  0 9.216 0.192 9.24 ;
    END
  END i_sel[25]
  PIN i_sel[260]
    DIRECTION INPUT ;
    USE SIGNAL ;
    PORT
      LAYER M4 ;
        RECT  0 51.408 0.192 51.432 ;
    END
  END i_sel[260]
  PIN i_sel[261]
    DIRECTION INPUT ;
    USE SIGNAL ;
    PORT
      LAYER M4 ;
        RECT  0 51.552 0.192 51.576 ;
    END
  END i_sel[261]
  PIN i_sel[262]
    DIRECTION INPUT ;
    USE SIGNAL ;
    PORT
      LAYER M4 ;
        RECT  0 51.696 0.192 51.72 ;
    END
  END i_sel[262]
  PIN i_sel[263]
    DIRECTION INPUT ;
    USE SIGNAL ;
    PORT
      LAYER M4 ;
        RECT  0 51.84 0.192 51.864 ;
    END
  END i_sel[263]
  PIN i_sel[264]
    DIRECTION INPUT ;
    USE SIGNAL ;
    PORT
      LAYER M4 ;
        RECT  0 52.128 0.192 52.152 ;
    END
  END i_sel[264]
  PIN i_sel[265]
    DIRECTION INPUT ;
    USE SIGNAL ;
    PORT
      LAYER M4 ;
        RECT  0 52.272 0.192 52.296 ;
    END
  END i_sel[265]
  PIN i_sel[266]
    DIRECTION INPUT ;
    USE SIGNAL ;
    PORT
      LAYER M4 ;
        RECT  0 52.416 0.192 52.44 ;
    END
  END i_sel[266]
  PIN i_sel[267]
    DIRECTION INPUT ;
    USE SIGNAL ;
    PORT
      LAYER M4 ;
        RECT  0 52.56 0.192 52.584 ;
    END
  END i_sel[267]
  PIN i_sel[268]
    DIRECTION INPUT ;
    USE SIGNAL ;
    PORT
      LAYER M4 ;
        RECT  0 52.848 0.192 52.872 ;
    END
  END i_sel[268]
  PIN i_sel[269]
    DIRECTION INPUT ;
    USE SIGNAL ;
    PORT
      LAYER M4 ;
        RECT  0 52.992 0.192 53.016 ;
    END
  END i_sel[269]
  PIN i_sel[26]
    DIRECTION INPUT ;
    USE SIGNAL ;
    PORT
      LAYER M4 ;
        RECT  0 9.36 0.192 9.384 ;
    END
  END i_sel[26]
  PIN i_sel[270]
    DIRECTION INPUT ;
    USE SIGNAL ;
    PORT
      LAYER M4 ;
        RECT  0 53.136 0.192 53.16 ;
    END
  END i_sel[270]
  PIN i_sel[271]
    DIRECTION INPUT ;
    USE SIGNAL ;
    PORT
      LAYER M4 ;
        RECT  0 53.28 0.192 53.304 ;
    END
  END i_sel[271]
  PIN i_sel[272]
    DIRECTION INPUT ;
    USE SIGNAL ;
    PORT
      LAYER M4 ;
        RECT  0 53.568 0.192 53.592 ;
    END
  END i_sel[272]
  PIN i_sel[273]
    DIRECTION INPUT ;
    USE SIGNAL ;
    PORT
      LAYER M4 ;
        RECT  0 53.712 0.192 53.736 ;
    END
  END i_sel[273]
  PIN i_sel[274]
    DIRECTION INPUT ;
    USE SIGNAL ;
    PORT
      LAYER M4 ;
        RECT  0 53.856 0.192 53.88 ;
    END
  END i_sel[274]
  PIN i_sel[275]
    DIRECTION INPUT ;
    USE SIGNAL ;
    PORT
      LAYER M4 ;
        RECT  0 54 0.192 54.024 ;
    END
  END i_sel[275]
  PIN i_sel[276]
    DIRECTION INPUT ;
    USE SIGNAL ;
    PORT
      LAYER M4 ;
        RECT  0 54.288 0.192 54.312 ;
    END
  END i_sel[276]
  PIN i_sel[277]
    DIRECTION INPUT ;
    USE SIGNAL ;
    PORT
      LAYER M4 ;
        RECT  0 54.432 0.192 54.456 ;
    END
  END i_sel[277]
  PIN i_sel[278]
    DIRECTION INPUT ;
    USE SIGNAL ;
    PORT
      LAYER M4 ;
        RECT  0 54.576 0.192 54.6 ;
    END
  END i_sel[278]
  PIN i_sel[279]
    DIRECTION INPUT ;
    USE SIGNAL ;
    PORT
      LAYER M4 ;
        RECT  0 54.72 0.192 54.744 ;
    END
  END i_sel[279]
  PIN i_sel[27]
    DIRECTION INPUT ;
    USE SIGNAL ;
    PORT
      LAYER M4 ;
        RECT  0 9.504 0.192 9.528 ;
    END
  END i_sel[27]
  PIN i_sel[280]
    DIRECTION INPUT ;
    USE SIGNAL ;
    PORT
      LAYER M4 ;
        RECT  0 55.008 0.192 55.032 ;
    END
  END i_sel[280]
  PIN i_sel[281]
    DIRECTION INPUT ;
    USE SIGNAL ;
    PORT
      LAYER M4 ;
        RECT  0 55.152 0.192 55.176 ;
    END
  END i_sel[281]
  PIN i_sel[282]
    DIRECTION INPUT ;
    USE SIGNAL ;
    PORT
      LAYER M4 ;
        RECT  0 55.296 0.192 55.32 ;
    END
  END i_sel[282]
  PIN i_sel[283]
    DIRECTION INPUT ;
    USE SIGNAL ;
    PORT
      LAYER M4 ;
        RECT  0 55.44 0.192 55.464 ;
    END
  END i_sel[283]
  PIN i_sel[284]
    DIRECTION INPUT ;
    USE SIGNAL ;
    PORT
      LAYER M4 ;
        RECT  0 55.728 0.192 55.752 ;
    END
  END i_sel[284]
  PIN i_sel[285]
    DIRECTION INPUT ;
    USE SIGNAL ;
    PORT
      LAYER M4 ;
        RECT  0 55.872 0.192 55.896 ;
    END
  END i_sel[285]
  PIN i_sel[286]
    DIRECTION INPUT ;
    USE SIGNAL ;
    PORT
      LAYER M4 ;
        RECT  0 56.016 0.192 56.04 ;
    END
  END i_sel[286]
  PIN i_sel[287]
    DIRECTION INPUT ;
    USE SIGNAL ;
    PORT
      LAYER M4 ;
        RECT  0 56.16 0.192 56.184 ;
    END
  END i_sel[287]
  PIN i_sel[288]
    DIRECTION INPUT ;
    USE SIGNAL ;
    PORT
      LAYER M4 ;
        RECT  0 56.448 0.192 56.472 ;
    END
  END i_sel[288]
  PIN i_sel[289]
    DIRECTION INPUT ;
    USE SIGNAL ;
    PORT
      LAYER M4 ;
        RECT  0 56.592 0.192 56.616 ;
    END
  END i_sel[289]
  PIN i_sel[28]
    DIRECTION INPUT ;
    USE SIGNAL ;
    PORT
      LAYER M4 ;
        RECT  0 9.792 0.192 9.816 ;
    END
  END i_sel[28]
  PIN i_sel[290]
    DIRECTION INPUT ;
    USE SIGNAL ;
    PORT
      LAYER M4 ;
        RECT  0 56.736 0.192 56.76 ;
    END
  END i_sel[290]
  PIN i_sel[291]
    DIRECTION INPUT ;
    USE SIGNAL ;
    PORT
      LAYER M4 ;
        RECT  0 56.88 0.192 56.904 ;
    END
  END i_sel[291]
  PIN i_sel[292]
    DIRECTION INPUT ;
    USE SIGNAL ;
    PORT
      LAYER M4 ;
        RECT  0 57.168 0.192 57.192 ;
    END
  END i_sel[292]
  PIN i_sel[293]
    DIRECTION INPUT ;
    USE SIGNAL ;
    PORT
      LAYER M4 ;
        RECT  0 57.312 0.192 57.336 ;
    END
  END i_sel[293]
  PIN i_sel[294]
    DIRECTION INPUT ;
    USE SIGNAL ;
    PORT
      LAYER M4 ;
        RECT  0 57.456 0.192 57.48 ;
    END
  END i_sel[294]
  PIN i_sel[295]
    DIRECTION INPUT ;
    USE SIGNAL ;
    PORT
      LAYER M4 ;
        RECT  0 57.6 0.192 57.624 ;
    END
  END i_sel[295]
  PIN i_sel[296]
    DIRECTION INPUT ;
    USE SIGNAL ;
    PORT
      LAYER M4 ;
        RECT  0 57.888 0.192 57.912 ;
    END
  END i_sel[296]
  PIN i_sel[297]
    DIRECTION INPUT ;
    USE SIGNAL ;
    PORT
      LAYER M4 ;
        RECT  0 58.032 0.192 58.056 ;
    END
  END i_sel[297]
  PIN i_sel[298]
    DIRECTION INPUT ;
    USE SIGNAL ;
    PORT
      LAYER M4 ;
        RECT  0 58.176 0.192 58.2 ;
    END
  END i_sel[298]
  PIN i_sel[299]
    DIRECTION INPUT ;
    USE SIGNAL ;
    PORT
      LAYER M4 ;
        RECT  0 58.32 0.192 58.344 ;
    END
  END i_sel[299]
  PIN i_sel[29]
    DIRECTION INPUT ;
    USE SIGNAL ;
    PORT
      LAYER M4 ;
        RECT  0 9.936 0.192 9.96 ;
    END
  END i_sel[29]
  PIN i_sel[2]
    DIRECTION INPUT ;
    USE SIGNAL ;
    PORT
      LAYER M4 ;
        RECT  0 5.04 0.192 5.064 ;
    END
  END i_sel[2]
  PIN i_sel[300]
    DIRECTION INPUT ;
    USE SIGNAL ;
    PORT
      LAYER M4 ;
        RECT  0 58.608 0.192 58.632 ;
    END
  END i_sel[300]
  PIN i_sel[301]
    DIRECTION INPUT ;
    USE SIGNAL ;
    PORT
      LAYER M4 ;
        RECT  0 58.752 0.192 58.776 ;
    END
  END i_sel[301]
  PIN i_sel[302]
    DIRECTION INPUT ;
    USE SIGNAL ;
    PORT
      LAYER M4 ;
        RECT  0 58.896 0.192 58.92 ;
    END
  END i_sel[302]
  PIN i_sel[303]
    DIRECTION INPUT ;
    USE SIGNAL ;
    PORT
      LAYER M4 ;
        RECT  0 59.04 0.192 59.064 ;
    END
  END i_sel[303]
  PIN i_sel[304]
    DIRECTION INPUT ;
    USE SIGNAL ;
    PORT
      LAYER M4 ;
        RECT  0 59.184 0.192 59.208 ;
    END
  END i_sel[304]
  PIN i_sel[305]
    DIRECTION INPUT ;
    USE SIGNAL ;
    PORT
      LAYER M4 ;
        RECT  0 59.472 0.192 59.496 ;
    END
  END i_sel[305]
  PIN i_sel[306]
    DIRECTION INPUT ;
    USE SIGNAL ;
    PORT
      LAYER M4 ;
        RECT  0 59.616 0.192 59.64 ;
    END
  END i_sel[306]
  PIN i_sel[307]
    DIRECTION INPUT ;
    USE SIGNAL ;
    PORT
      LAYER M4 ;
        RECT  0 59.76 0.192 59.784 ;
    END
  END i_sel[307]
  PIN i_sel[308]
    DIRECTION INPUT ;
    USE SIGNAL ;
    PORT
      LAYER M4 ;
        RECT  0 59.904 0.192 59.928 ;
    END
  END i_sel[308]
  PIN i_sel[309]
    DIRECTION INPUT ;
    USE SIGNAL ;
    PORT
      LAYER M4 ;
        RECT  0 60.192 0.192 60.216 ;
    END
  END i_sel[309]
  PIN i_sel[30]
    DIRECTION INPUT ;
    USE SIGNAL ;
    PORT
      LAYER M4 ;
        RECT  0 10.08 0.192 10.104 ;
    END
  END i_sel[30]
  PIN i_sel[310]
    DIRECTION INPUT ;
    USE SIGNAL ;
    PORT
      LAYER M4 ;
        RECT  0 60.336 0.192 60.36 ;
    END
  END i_sel[310]
  PIN i_sel[311]
    DIRECTION INPUT ;
    USE SIGNAL ;
    PORT
      LAYER M4 ;
        RECT  0 60.48 0.192 60.504 ;
    END
  END i_sel[311]
  PIN i_sel[312]
    DIRECTION INPUT ;
    USE SIGNAL ;
    PORT
      LAYER M4 ;
        RECT  0 60.624 0.192 60.648 ;
    END
  END i_sel[312]
  PIN i_sel[313]
    DIRECTION INPUT ;
    USE SIGNAL ;
    PORT
      LAYER M4 ;
        RECT  0 60.912 0.192 60.936 ;
    END
  END i_sel[313]
  PIN i_sel[314]
    DIRECTION INPUT ;
    USE SIGNAL ;
    PORT
      LAYER M4 ;
        RECT  0 61.056 0.192 61.08 ;
    END
  END i_sel[314]
  PIN i_sel[315]
    DIRECTION INPUT ;
    USE SIGNAL ;
    PORT
      LAYER M4 ;
        RECT  0 61.2 0.192 61.224 ;
    END
  END i_sel[315]
  PIN i_sel[316]
    DIRECTION INPUT ;
    USE SIGNAL ;
    PORT
      LAYER M4 ;
        RECT  0 61.344 0.192 61.368 ;
    END
  END i_sel[316]
  PIN i_sel[317]
    DIRECTION INPUT ;
    USE SIGNAL ;
    PORT
      LAYER M4 ;
        RECT  0 61.632 0.192 61.656 ;
    END
  END i_sel[317]
  PIN i_sel[318]
    DIRECTION INPUT ;
    USE SIGNAL ;
    PORT
      LAYER M4 ;
        RECT  0 61.776 0.192 61.8 ;
    END
  END i_sel[318]
  PIN i_sel[319]
    DIRECTION INPUT ;
    USE SIGNAL ;
    PORT
      LAYER M4 ;
        RECT  0 61.92 0.192 61.944 ;
    END
  END i_sel[319]
  PIN i_sel[31]
    DIRECTION INPUT ;
    USE SIGNAL ;
    PORT
      LAYER M4 ;
        RECT  0 10.224 0.192 10.248 ;
    END
  END i_sel[31]
  PIN i_sel[320]
    DIRECTION INPUT ;
    USE SIGNAL ;
    PORT
      LAYER M4 ;
        RECT  0 62.064 0.192 62.088 ;
    END
  END i_sel[320]
  PIN i_sel[321]
    DIRECTION INPUT ;
    USE SIGNAL ;
    PORT
      LAYER M4 ;
        RECT  0 62.352 0.192 62.376 ;
    END
  END i_sel[321]
  PIN i_sel[322]
    DIRECTION INPUT ;
    USE SIGNAL ;
    PORT
      LAYER M4 ;
        RECT  0 62.496 0.192 62.52 ;
    END
  END i_sel[322]
  PIN i_sel[323]
    DIRECTION INPUT ;
    USE SIGNAL ;
    PORT
      LAYER M4 ;
        RECT  0 62.64 0.192 62.664 ;
    END
  END i_sel[323]
  PIN i_sel[324]
    DIRECTION INPUT ;
    USE SIGNAL ;
    PORT
      LAYER M4 ;
        RECT  0 62.784 0.192 62.808 ;
    END
  END i_sel[324]
  PIN i_sel[325]
    DIRECTION INPUT ;
    USE SIGNAL ;
    PORT
      LAYER M4 ;
        RECT  0 63.072 0.192 63.096 ;
    END
  END i_sel[325]
  PIN i_sel[326]
    DIRECTION INPUT ;
    USE SIGNAL ;
    PORT
      LAYER M4 ;
        RECT  0 63.216 0.192 63.24 ;
    END
  END i_sel[326]
  PIN i_sel[327]
    DIRECTION INPUT ;
    USE SIGNAL ;
    PORT
      LAYER M4 ;
        RECT  0 63.36 0.192 63.384 ;
    END
  END i_sel[327]
  PIN i_sel[328]
    DIRECTION INPUT ;
    USE SIGNAL ;
    PORT
      LAYER M4 ;
        RECT  0 63.504 0.192 63.528 ;
    END
  END i_sel[328]
  PIN i_sel[329]
    DIRECTION INPUT ;
    USE SIGNAL ;
    PORT
      LAYER M4 ;
        RECT  0 63.792 0.192 63.816 ;
    END
  END i_sel[329]
  PIN i_sel[32]
    DIRECTION INPUT ;
    USE SIGNAL ;
    PORT
      LAYER M4 ;
        RECT  0 10.368 0.192 10.392 ;
    END
  END i_sel[32]
  PIN i_sel[330]
    DIRECTION INPUT ;
    USE SIGNAL ;
    PORT
      LAYER M4 ;
        RECT  0 63.936 0.192 63.96 ;
    END
  END i_sel[330]
  PIN i_sel[331]
    DIRECTION INPUT ;
    USE SIGNAL ;
    PORT
      LAYER M4 ;
        RECT  0 4.32 0.192 4.344 ;
    END
  END i_sel[331]
  PIN i_sel[332]
    DIRECTION INPUT ;
    USE SIGNAL ;
    PORT
      LAYER M4 ;
        RECT  0 64.224 0.192 64.248 ;
    END
  END i_sel[332]
  PIN i_sel[333]
    DIRECTION INPUT ;
    USE SIGNAL ;
    PORT
      LAYER M4 ;
        RECT  0 64.512 0.192 64.536 ;
    END
  END i_sel[333]
  PIN i_sel[334]
    DIRECTION INPUT ;
    USE SIGNAL ;
    PORT
      LAYER M4 ;
        RECT  0 64.656 0.192 64.68 ;
    END
  END i_sel[334]
  PIN i_sel[335]
    DIRECTION INPUT ;
    USE SIGNAL ;
    PORT
      LAYER M4 ;
        RECT  0 64.8 0.192 64.824 ;
    END
  END i_sel[335]
  PIN i_sel[336]
    DIRECTION INPUT ;
    USE SIGNAL ;
    PORT
      LAYER M4 ;
        RECT  0 64.944 0.192 64.968 ;
    END
  END i_sel[336]
  PIN i_sel[337]
    DIRECTION INPUT ;
    USE SIGNAL ;
    PORT
      LAYER M4 ;
        RECT  0 65.232 0.192 65.256 ;
    END
  END i_sel[337]
  PIN i_sel[338]
    DIRECTION INPUT ;
    USE SIGNAL ;
    PORT
      LAYER M4 ;
        RECT  0 65.376 0.192 65.4 ;
    END
  END i_sel[338]
  PIN i_sel[339]
    DIRECTION INPUT ;
    USE SIGNAL ;
    PORT
      LAYER M4 ;
        RECT  0 65.52 0.192 65.544 ;
    END
  END i_sel[339]
  PIN i_sel[33]
    DIRECTION INPUT ;
    USE SIGNAL ;
    PORT
      LAYER M4 ;
        RECT  0 10.656 0.192 10.68 ;
    END
  END i_sel[33]
  PIN i_sel[340]
    DIRECTION INPUT ;
    USE SIGNAL ;
    PORT
      LAYER M4 ;
        RECT  0 65.664 0.192 65.688 ;
    END
  END i_sel[340]
  PIN i_sel[341]
    DIRECTION INPUT ;
    USE SIGNAL ;
    PORT
      LAYER M4 ;
        RECT  0 65.952 0.192 65.976 ;
    END
  END i_sel[341]
  PIN i_sel[342]
    DIRECTION INPUT ;
    USE SIGNAL ;
    PORT
      LAYER M4 ;
        RECT  0 66.096 0.192 66.12 ;
    END
  END i_sel[342]
  PIN i_sel[343]
    DIRECTION INPUT ;
    USE SIGNAL ;
    PORT
      LAYER M4 ;
        RECT  0 66.24 0.192 66.264 ;
    END
  END i_sel[343]
  PIN i_sel[344]
    DIRECTION INPUT ;
    USE SIGNAL ;
    PORT
      LAYER M4 ;
        RECT  0 66.384 0.192 66.408 ;
    END
  END i_sel[344]
  PIN i_sel[345]
    DIRECTION INPUT ;
    USE SIGNAL ;
    PORT
      LAYER M4 ;
        RECT  0 66.672 0.192 66.696 ;
    END
  END i_sel[345]
  PIN i_sel[346]
    DIRECTION INPUT ;
    USE SIGNAL ;
    PORT
      LAYER M4 ;
        RECT  0 66.816 0.192 66.84 ;
    END
  END i_sel[346]
  PIN i_sel[347]
    DIRECTION INPUT ;
    USE SIGNAL ;
    PORT
      LAYER M4 ;
        RECT  0 66.96 0.192 66.984 ;
    END
  END i_sel[347]
  PIN i_sel[348]
    DIRECTION INPUT ;
    USE SIGNAL ;
    PORT
      LAYER M4 ;
        RECT  0 67.104 0.192 67.128 ;
    END
  END i_sel[348]
  PIN i_sel[349]
    DIRECTION INPUT ;
    USE SIGNAL ;
    PORT
      LAYER M4 ;
        RECT  0 67.392 0.192 67.416 ;
    END
  END i_sel[349]
  PIN i_sel[34]
    DIRECTION INPUT ;
    USE SIGNAL ;
    PORT
      LAYER M4 ;
        RECT  0 10.8 0.192 10.824 ;
    END
  END i_sel[34]
  PIN i_sel[350]
    DIRECTION INPUT ;
    USE SIGNAL ;
    PORT
      LAYER M4 ;
        RECT  0 67.536 0.192 67.56 ;
    END
  END i_sel[350]
  PIN i_sel[351]
    DIRECTION INPUT ;
    USE SIGNAL ;
    PORT
      LAYER M4 ;
        RECT  0 67.68 0.192 67.704 ;
    END
  END i_sel[351]
  PIN i_sel[352]
    DIRECTION INPUT ;
    USE SIGNAL ;
    PORT
      LAYER M4 ;
        RECT  0 67.824 0.192 67.848 ;
    END
  END i_sel[352]
  PIN i_sel[353]
    DIRECTION INPUT ;
    USE SIGNAL ;
    PORT
      LAYER M4 ;
        RECT  0 68.112 0.192 68.136 ;
    END
  END i_sel[353]
  PIN i_sel[354]
    DIRECTION INPUT ;
    USE SIGNAL ;
    PORT
      LAYER M4 ;
        RECT  0 68.256 0.192 68.28 ;
    END
  END i_sel[354]
  PIN i_sel[355]
    DIRECTION INPUT ;
    USE SIGNAL ;
    PORT
      LAYER M4 ;
        RECT  0 68.4 0.192 68.424 ;
    END
  END i_sel[355]
  PIN i_sel[356]
    DIRECTION INPUT ;
    USE SIGNAL ;
    PORT
      LAYER M4 ;
        RECT  0 68.544 0.192 68.568 ;
    END
  END i_sel[356]
  PIN i_sel[357]
    DIRECTION INPUT ;
    USE SIGNAL ;
    PORT
      LAYER M4 ;
        RECT  0 68.832 0.192 68.856 ;
    END
  END i_sel[357]
  PIN i_sel[358]
    DIRECTION INPUT ;
    USE SIGNAL ;
    PORT
      LAYER M4 ;
        RECT  0 68.976 0.192 69 ;
    END
  END i_sel[358]
  PIN i_sel[359]
    DIRECTION INPUT ;
    USE SIGNAL ;
    PORT
      LAYER M4 ;
        RECT  0 69.12 0.192 69.144 ;
    END
  END i_sel[359]
  PIN i_sel[35]
    DIRECTION INPUT ;
    USE SIGNAL ;
    PORT
      LAYER M4 ;
        RECT  0 10.944 0.192 10.968 ;
    END
  END i_sel[35]
  PIN i_sel[360]
    DIRECTION INPUT ;
    USE SIGNAL ;
    PORT
      LAYER M4 ;
        RECT  0 69.264 0.192 69.288 ;
    END
  END i_sel[360]
  PIN i_sel[361]
    DIRECTION INPUT ;
    USE SIGNAL ;
    PORT
      LAYER M4 ;
        RECT  0 69.552 0.192 69.576 ;
    END
  END i_sel[361]
  PIN i_sel[362]
    DIRECTION INPUT ;
    USE SIGNAL ;
    PORT
      LAYER M4 ;
        RECT  0 69.696 0.192 69.72 ;
    END
  END i_sel[362]
  PIN i_sel[363]
    DIRECTION INPUT ;
    USE SIGNAL ;
    PORT
      LAYER M4 ;
        RECT  0 69.84 0.192 69.864 ;
    END
  END i_sel[363]
  PIN i_sel[364]
    DIRECTION INPUT ;
    USE SIGNAL ;
    PORT
      LAYER M4 ;
        RECT  0 69.984 0.192 70.008 ;
    END
  END i_sel[364]
  PIN i_sel[365]
    DIRECTION INPUT ;
    USE SIGNAL ;
    PORT
      LAYER M4 ;
        RECT  0 70.272 0.192 70.296 ;
    END
  END i_sel[365]
  PIN i_sel[366]
    DIRECTION INPUT ;
    USE SIGNAL ;
    PORT
      LAYER M4 ;
        RECT  0 70.416 0.192 70.44 ;
    END
  END i_sel[366]
  PIN i_sel[367]
    DIRECTION INPUT ;
    USE SIGNAL ;
    PORT
      LAYER M4 ;
        RECT  0 70.56 0.192 70.584 ;
    END
  END i_sel[367]
  PIN i_sel[368]
    DIRECTION INPUT ;
    USE SIGNAL ;
    PORT
      LAYER M4 ;
        RECT  0 70.704 0.192 70.728 ;
    END
  END i_sel[368]
  PIN i_sel[369]
    DIRECTION INPUT ;
    USE SIGNAL ;
    PORT
      LAYER M4 ;
        RECT  0 70.848 0.192 70.872 ;
    END
  END i_sel[369]
  PIN i_sel[36]
    DIRECTION INPUT ;
    USE SIGNAL ;
    PORT
      LAYER M4 ;
        RECT  0 11.088 0.192 11.112 ;
    END
  END i_sel[36]
  PIN i_sel[370]
    DIRECTION INPUT ;
    USE SIGNAL ;
    PORT
      LAYER M4 ;
        RECT  0 71.136 0.192 71.16 ;
    END
  END i_sel[370]
  PIN i_sel[371]
    DIRECTION INPUT ;
    USE SIGNAL ;
    PORT
      LAYER M4 ;
        RECT  0 71.28 0.192 71.304 ;
    END
  END i_sel[371]
  PIN i_sel[372]
    DIRECTION INPUT ;
    USE SIGNAL ;
    PORT
      LAYER M4 ;
        RECT  0 71.424 0.192 71.448 ;
    END
  END i_sel[372]
  PIN i_sel[373]
    DIRECTION INPUT ;
    USE SIGNAL ;
    PORT
      LAYER M4 ;
        RECT  0 71.568 0.192 71.592 ;
    END
  END i_sel[373]
  PIN i_sel[374]
    DIRECTION INPUT ;
    USE SIGNAL ;
    PORT
      LAYER M4 ;
        RECT  0 71.856 0.192 71.88 ;
    END
  END i_sel[374]
  PIN i_sel[375]
    DIRECTION INPUT ;
    USE SIGNAL ;
    PORT
      LAYER M4 ;
        RECT  0 72 0.192 72.024 ;
    END
  END i_sel[375]
  PIN i_sel[376]
    DIRECTION INPUT ;
    USE SIGNAL ;
    PORT
      LAYER M4 ;
        RECT  0 72.144 0.192 72.168 ;
    END
  END i_sel[376]
  PIN i_sel[377]
    DIRECTION INPUT ;
    USE SIGNAL ;
    PORT
      LAYER M4 ;
        RECT  0 72.288 0.192 72.312 ;
    END
  END i_sel[377]
  PIN i_sel[378]
    DIRECTION INPUT ;
    USE SIGNAL ;
    PORT
      LAYER M4 ;
        RECT  0 72.576 0.192 72.6 ;
    END
  END i_sel[378]
  PIN i_sel[379]
    DIRECTION INPUT ;
    USE SIGNAL ;
    PORT
      LAYER M4 ;
        RECT  0 72.72 0.192 72.744 ;
    END
  END i_sel[379]
  PIN i_sel[37]
    DIRECTION INPUT ;
    USE SIGNAL ;
    PORT
      LAYER M4 ;
        RECT  0 11.376 0.192 11.4 ;
    END
  END i_sel[37]
  PIN i_sel[380]
    DIRECTION INPUT ;
    USE SIGNAL ;
    PORT
      LAYER M4 ;
        RECT  0 72.864 0.192 72.888 ;
    END
  END i_sel[380]
  PIN i_sel[381]
    DIRECTION INPUT ;
    USE SIGNAL ;
    PORT
      LAYER M4 ;
        RECT  0 73.008 0.192 73.032 ;
    END
  END i_sel[381]
  PIN i_sel[382]
    DIRECTION INPUT ;
    USE SIGNAL ;
    PORT
      LAYER M4 ;
        RECT  0 73.296 0.192 73.32 ;
    END
  END i_sel[382]
  PIN i_sel[383]
    DIRECTION INPUT ;
    USE SIGNAL ;
    PORT
      LAYER M4 ;
        RECT  0 73.44 0.192 73.464 ;
    END
  END i_sel[383]
  PIN i_sel[384]
    DIRECTION INPUT ;
    USE SIGNAL ;
    PORT
      LAYER M4 ;
        RECT  0 73.584 0.192 73.608 ;
    END
  END i_sel[384]
  PIN i_sel[385]
    DIRECTION INPUT ;
    USE SIGNAL ;
    PORT
      LAYER M4 ;
        RECT  0 73.728 0.192 73.752 ;
    END
  END i_sel[385]
  PIN i_sel[386]
    DIRECTION INPUT ;
    USE SIGNAL ;
    PORT
      LAYER M4 ;
        RECT  0 74.016 0.192 74.04 ;
    END
  END i_sel[386]
  PIN i_sel[387]
    DIRECTION INPUT ;
    USE SIGNAL ;
    PORT
      LAYER M4 ;
        RECT  0 74.16 0.192 74.184 ;
    END
  END i_sel[387]
  PIN i_sel[388]
    DIRECTION INPUT ;
    USE SIGNAL ;
    PORT
      LAYER M4 ;
        RECT  0 74.304 0.192 74.328 ;
    END
  END i_sel[388]
  PIN i_sel[389]
    DIRECTION INPUT ;
    USE SIGNAL ;
    PORT
      LAYER M4 ;
        RECT  0 74.448 0.192 74.472 ;
    END
  END i_sel[389]
  PIN i_sel[38]
    DIRECTION INPUT ;
    USE SIGNAL ;
    PORT
      LAYER M4 ;
        RECT  0 11.52 0.192 11.544 ;
    END
  END i_sel[38]
  PIN i_sel[390]
    DIRECTION INPUT ;
    USE SIGNAL ;
    PORT
      LAYER M4 ;
        RECT  0 74.736 0.192 74.76 ;
    END
  END i_sel[390]
  PIN i_sel[391]
    DIRECTION INPUT ;
    USE SIGNAL ;
    PORT
      LAYER M4 ;
        RECT  0 74.88 0.192 74.904 ;
    END
  END i_sel[391]
  PIN i_sel[392]
    DIRECTION INPUT ;
    USE SIGNAL ;
    PORT
      LAYER M4 ;
        RECT  0 75.024 0.192 75.048 ;
    END
  END i_sel[392]
  PIN i_sel[393]
    DIRECTION INPUT ;
    USE SIGNAL ;
    PORT
      LAYER M4 ;
        RECT  0 75.168 0.192 75.192 ;
    END
  END i_sel[393]
  PIN i_sel[394]
    DIRECTION INPUT ;
    USE SIGNAL ;
    PORT
      LAYER M4 ;
        RECT  0 75.456 0.192 75.48 ;
    END
  END i_sel[394]
  PIN i_sel[395]
    DIRECTION INPUT ;
    USE SIGNAL ;
    PORT
      LAYER M4 ;
        RECT  0 75.6 0.192 75.624 ;
    END
  END i_sel[395]
  PIN i_sel[396]
    DIRECTION INPUT ;
    USE SIGNAL ;
    PORT
      LAYER M4 ;
        RECT  0 75.744 0.192 75.768 ;
    END
  END i_sel[396]
  PIN i_sel[397]
    DIRECTION INPUT ;
    USE SIGNAL ;
    PORT
      LAYER M4 ;
        RECT  0 75.888 0.192 75.912 ;
    END
  END i_sel[397]
  PIN i_sel[398]
    DIRECTION INPUT ;
    USE SIGNAL ;
    PORT
      LAYER M4 ;
        RECT  0 76.176 0.192 76.2 ;
    END
  END i_sel[398]
  PIN i_sel[399]
    DIRECTION INPUT ;
    USE SIGNAL ;
    PORT
      LAYER M4 ;
        RECT  0 76.32 0.192 76.344 ;
    END
  END i_sel[399]
  PIN i_sel[39]
    DIRECTION INPUT ;
    USE SIGNAL ;
    PORT
      LAYER M4 ;
        RECT  0 11.664 0.192 11.688 ;
    END
  END i_sel[39]
  PIN i_sel[3]
    DIRECTION INPUT ;
    USE SIGNAL ;
    PORT
      LAYER M4 ;
        RECT  0 5.184 0.192 5.208 ;
    END
  END i_sel[3]
  PIN i_sel[400]
    DIRECTION INPUT ;
    USE SIGNAL ;
    PORT
      LAYER M4 ;
        RECT  0 76.464 0.192 76.488 ;
    END
  END i_sel[400]
  PIN i_sel[401]
    DIRECTION INPUT ;
    USE SIGNAL ;
    PORT
      LAYER M4 ;
        RECT  0 76.608 0.192 76.632 ;
    END
  END i_sel[401]
  PIN i_sel[402]
    DIRECTION INPUT ;
    USE SIGNAL ;
    PORT
      LAYER M4 ;
        RECT  0 76.896 0.192 76.92 ;
    END
  END i_sel[402]
  PIN i_sel[403]
    DIRECTION INPUT ;
    USE SIGNAL ;
    PORT
      LAYER M4 ;
        RECT  0 77.04 0.192 77.064 ;
    END
  END i_sel[403]
  PIN i_sel[404]
    DIRECTION INPUT ;
    USE SIGNAL ;
    PORT
      LAYER M4 ;
        RECT  0 77.184 0.192 77.208 ;
    END
  END i_sel[404]
  PIN i_sel[405]
    DIRECTION INPUT ;
    USE SIGNAL ;
    PORT
      LAYER M4 ;
        RECT  0 77.328 0.192 77.352 ;
    END
  END i_sel[405]
  PIN i_sel[406]
    DIRECTION INPUT ;
    USE SIGNAL ;
    PORT
      LAYER M4 ;
        RECT  0 77.616 0.192 77.64 ;
    END
  END i_sel[406]
  PIN i_sel[407]
    DIRECTION INPUT ;
    USE SIGNAL ;
    PORT
      LAYER M4 ;
        RECT  0 77.76 0.192 77.784 ;
    END
  END i_sel[407]
  PIN i_sel[408]
    DIRECTION INPUT ;
    USE SIGNAL ;
    PORT
      LAYER M4 ;
        RECT  0 77.904 0.192 77.928 ;
    END
  END i_sel[408]
  PIN i_sel[409]
    DIRECTION INPUT ;
    USE SIGNAL ;
    PORT
      LAYER M4 ;
        RECT  0 78.048 0.192 78.072 ;
    END
  END i_sel[409]
  PIN i_sel[40]
    DIRECTION INPUT ;
    USE SIGNAL ;
    PORT
      LAYER M4 ;
        RECT  0 11.808 0.192 11.832 ;
    END
  END i_sel[40]
  PIN i_sel[410]
    DIRECTION INPUT ;
    USE SIGNAL ;
    PORT
      LAYER M4 ;
        RECT  0 78.336 0.192 78.36 ;
    END
  END i_sel[410]
  PIN i_sel[411]
    DIRECTION INPUT ;
    USE SIGNAL ;
    PORT
      LAYER M4 ;
        RECT  0 78.48 0.192 78.504 ;
    END
  END i_sel[411]
  PIN i_sel[412]
    DIRECTION INPUT ;
    USE SIGNAL ;
    PORT
      LAYER M4 ;
        RECT  0 78.624 0.192 78.648 ;
    END
  END i_sel[412]
  PIN i_sel[413]
    DIRECTION INPUT ;
    USE SIGNAL ;
    PORT
      LAYER M4 ;
        RECT  0 78.768 0.192 78.792 ;
    END
  END i_sel[413]
  PIN i_sel[414]
    DIRECTION INPUT ;
    USE SIGNAL ;
    PORT
      LAYER M4 ;
        RECT  0 79.056 0.192 79.08 ;
    END
  END i_sel[414]
  PIN i_sel[415]
    DIRECTION INPUT ;
    USE SIGNAL ;
    PORT
      LAYER M4 ;
        RECT  0 79.2 0.192 79.224 ;
    END
  END i_sel[415]
  PIN i_sel[416]
    DIRECTION INPUT ;
    USE SIGNAL ;
    PORT
      LAYER M4 ;
        RECT  0 79.344 0.192 79.368 ;
    END
  END i_sel[416]
  PIN i_sel[417]
    DIRECTION INPUT ;
    USE SIGNAL ;
    PORT
      LAYER M4 ;
        RECT  0 79.488 0.192 79.512 ;
    END
  END i_sel[417]
  PIN i_sel[418]
    DIRECTION INPUT ;
    USE SIGNAL ;
    PORT
      LAYER M4 ;
        RECT  0 79.776 0.192 79.8 ;
    END
  END i_sel[418]
  PIN i_sel[419]
    DIRECTION INPUT ;
    USE SIGNAL ;
    PORT
      LAYER M4 ;
        RECT  0 79.92 0.192 79.944 ;
    END
  END i_sel[419]
  PIN i_sel[41]
    DIRECTION INPUT ;
    USE SIGNAL ;
    PORT
      LAYER M4 ;
        RECT  0 12.096 0.192 12.12 ;
    END
  END i_sel[41]
  PIN i_sel[420]
    DIRECTION INPUT ;
    USE SIGNAL ;
    PORT
      LAYER M4 ;
        RECT  0 80.064 0.192 80.088 ;
    END
  END i_sel[420]
  PIN i_sel[421]
    DIRECTION INPUT ;
    USE SIGNAL ;
    PORT
      LAYER M4 ;
        RECT  0 80.208 0.192 80.232 ;
    END
  END i_sel[421]
  PIN i_sel[422]
    DIRECTION INPUT ;
    USE SIGNAL ;
    PORT
      LAYER M4 ;
        RECT  0 80.496 0.192 80.52 ;
    END
  END i_sel[422]
  PIN i_sel[423]
    DIRECTION INPUT ;
    USE SIGNAL ;
    PORT
      LAYER M4 ;
        RECT  0 80.64 0.192 80.664 ;
    END
  END i_sel[423]
  PIN i_sel[424]
    DIRECTION INPUT ;
    USE SIGNAL ;
    PORT
      LAYER M4 ;
        RECT  0 80.784 0.192 80.808 ;
    END
  END i_sel[424]
  PIN i_sel[425]
    DIRECTION INPUT ;
    USE SIGNAL ;
    PORT
      LAYER M4 ;
        RECT  0 80.928 0.192 80.952 ;
    END
  END i_sel[425]
  PIN i_sel[426]
    DIRECTION INPUT ;
    USE SIGNAL ;
    PORT
      LAYER M4 ;
        RECT  0 81.216 0.192 81.24 ;
    END
  END i_sel[426]
  PIN i_sel[427]
    DIRECTION INPUT ;
    USE SIGNAL ;
    PORT
      LAYER M4 ;
        RECT  0 81.36 0.192 81.384 ;
    END
  END i_sel[427]
  PIN i_sel[428]
    DIRECTION INPUT ;
    USE SIGNAL ;
    PORT
      LAYER M4 ;
        RECT  0 81.504 0.192 81.528 ;
    END
  END i_sel[428]
  PIN i_sel[429]
    DIRECTION INPUT ;
    USE SIGNAL ;
    PORT
      LAYER M4 ;
        RECT  0 81.648 0.192 81.672 ;
    END
  END i_sel[429]
  PIN i_sel[42]
    DIRECTION INPUT ;
    USE SIGNAL ;
    PORT
      LAYER M4 ;
        RECT  0 12.24 0.192 12.264 ;
    END
  END i_sel[42]
  PIN i_sel[430]
    DIRECTION INPUT ;
    USE SIGNAL ;
    PORT
      LAYER M4 ;
        RECT  0 81.936 0.192 81.96 ;
    END
  END i_sel[430]
  PIN i_sel[431]
    DIRECTION INPUT ;
    USE SIGNAL ;
    PORT
      LAYER M4 ;
        RECT  0 82.08 0.192 82.104 ;
    END
  END i_sel[431]
  PIN i_sel[432]
    DIRECTION INPUT ;
    USE SIGNAL ;
    PORT
      LAYER M4 ;
        RECT  0 82.224 0.192 82.248 ;
    END
  END i_sel[432]
  PIN i_sel[433]
    DIRECTION INPUT ;
    USE SIGNAL ;
    PORT
      LAYER M4 ;
        RECT  0 82.368 0.192 82.392 ;
    END
  END i_sel[433]
  PIN i_sel[434]
    DIRECTION INPUT ;
    USE SIGNAL ;
    PORT
      LAYER M4 ;
        RECT  0 82.656 0.192 82.68 ;
    END
  END i_sel[434]
  PIN i_sel[435]
    DIRECTION INPUT ;
    USE SIGNAL ;
    PORT
      LAYER M4 ;
        RECT  0 82.8 0.192 82.824 ;
    END
  END i_sel[435]
  PIN i_sel[436]
    DIRECTION INPUT ;
    USE SIGNAL ;
    PORT
      LAYER M4 ;
        RECT  0 82.944 0.192 82.968 ;
    END
  END i_sel[436]
  PIN i_sel[437]
    DIRECTION INPUT ;
    USE SIGNAL ;
    PORT
      LAYER M4 ;
        RECT  0 83.088 0.192 83.112 ;
    END
  END i_sel[437]
  PIN i_sel[438]
    DIRECTION INPUT ;
    USE SIGNAL ;
    PORT
      LAYER M4 ;
        RECT  0 83.232 0.192 83.256 ;
    END
  END i_sel[438]
  PIN i_sel[439]
    DIRECTION INPUT ;
    USE SIGNAL ;
    PORT
      LAYER M4 ;
        RECT  0 83.52 0.192 83.544 ;
    END
  END i_sel[439]
  PIN i_sel[43]
    DIRECTION INPUT ;
    USE SIGNAL ;
    PORT
      LAYER M4 ;
        RECT  0 12.384 0.192 12.408 ;
    END
  END i_sel[43]
  PIN i_sel[440]
    DIRECTION INPUT ;
    USE SIGNAL ;
    PORT
      LAYER M4 ;
        RECT  0 83.664 0.192 83.688 ;
    END
  END i_sel[440]
  PIN i_sel[441]
    DIRECTION INPUT ;
    USE SIGNAL ;
    PORT
      LAYER M4 ;
        RECT  0 83.808 0.192 83.832 ;
    END
  END i_sel[441]
  PIN i_sel[442]
    DIRECTION INPUT ;
    USE SIGNAL ;
    PORT
      LAYER M4 ;
        RECT  0 83.952 0.192 83.976 ;
    END
  END i_sel[442]
  PIN i_sel[443]
    DIRECTION INPUT ;
    USE SIGNAL ;
    PORT
      LAYER M4 ;
        RECT  0 84.24 0.192 84.264 ;
    END
  END i_sel[443]
  PIN i_sel[444]
    DIRECTION INPUT ;
    USE SIGNAL ;
    PORT
      LAYER M4 ;
        RECT  0 84.384 0.192 84.408 ;
    END
  END i_sel[444]
  PIN i_sel[445]
    DIRECTION INPUT ;
    USE SIGNAL ;
    PORT
      LAYER M4 ;
        RECT  0 84.528 0.192 84.552 ;
    END
  END i_sel[445]
  PIN i_sel[446]
    DIRECTION INPUT ;
    USE SIGNAL ;
    PORT
      LAYER M4 ;
        RECT  0 84.672 0.192 84.696 ;
    END
  END i_sel[446]
  PIN i_sel[447]
    DIRECTION INPUT ;
    USE SIGNAL ;
    PORT
      LAYER M4 ;
        RECT  0 84.96 0.192 84.984 ;
    END
  END i_sel[447]
  PIN i_sel[448]
    DIRECTION INPUT ;
    USE SIGNAL ;
    PORT
      LAYER M4 ;
        RECT  0 85.104 0.192 85.128 ;
    END
  END i_sel[448]
  PIN i_sel[449]
    DIRECTION INPUT ;
    USE SIGNAL ;
    PORT
      LAYER M4 ;
        RECT  0 85.248 0.192 85.272 ;
    END
  END i_sel[449]
  PIN i_sel[44]
    DIRECTION INPUT ;
    USE SIGNAL ;
    PORT
      LAYER M4 ;
        RECT  0 12.528 0.192 12.552 ;
    END
  END i_sel[44]
  PIN i_sel[450]
    DIRECTION INPUT ;
    USE SIGNAL ;
    PORT
      LAYER M4 ;
        RECT  0 85.392 0.192 85.416 ;
    END
  END i_sel[450]
  PIN i_sel[451]
    DIRECTION INPUT ;
    USE SIGNAL ;
    PORT
      LAYER M4 ;
        RECT  0 85.68 0.192 85.704 ;
    END
  END i_sel[451]
  PIN i_sel[452]
    DIRECTION INPUT ;
    USE SIGNAL ;
    PORT
      LAYER M4 ;
        RECT  0 85.824 0.192 85.848 ;
    END
  END i_sel[452]
  PIN i_sel[453]
    DIRECTION INPUT ;
    USE SIGNAL ;
    PORT
      LAYER M4 ;
        RECT  0 85.968 0.192 85.992 ;
    END
  END i_sel[453]
  PIN i_sel[454]
    DIRECTION INPUT ;
    USE SIGNAL ;
    PORT
      LAYER M4 ;
        RECT  0 86.112 0.192 86.136 ;
    END
  END i_sel[454]
  PIN i_sel[455]
    DIRECTION INPUT ;
    USE SIGNAL ;
    PORT
      LAYER M4 ;
        RECT  0 86.4 0.192 86.424 ;
    END
  END i_sel[455]
  PIN i_sel[456]
    DIRECTION INPUT ;
    USE SIGNAL ;
    PORT
      LAYER M4 ;
        RECT  0 86.544 0.192 86.568 ;
    END
  END i_sel[456]
  PIN i_sel[457]
    DIRECTION INPUT ;
    USE SIGNAL ;
    PORT
      LAYER M4 ;
        RECT  0 86.688 0.192 86.712 ;
    END
  END i_sel[457]
  PIN i_sel[458]
    DIRECTION INPUT ;
    USE SIGNAL ;
    PORT
      LAYER M4 ;
        RECT  0 86.832 0.192 86.856 ;
    END
  END i_sel[458]
  PIN i_sel[459]
    DIRECTION INPUT ;
    USE SIGNAL ;
    PORT
      LAYER M4 ;
        RECT  0 87.12 0.192 87.144 ;
    END
  END i_sel[459]
  PIN i_sel[45]
    DIRECTION INPUT ;
    USE SIGNAL ;
    PORT
      LAYER M4 ;
        RECT  0 12.816 0.192 12.84 ;
    END
  END i_sel[45]
  PIN i_sel[460]
    DIRECTION INPUT ;
    USE SIGNAL ;
    PORT
      LAYER M4 ;
        RECT  0 87.264 0.192 87.288 ;
    END
  END i_sel[460]
  PIN i_sel[461]
    DIRECTION INPUT ;
    USE SIGNAL ;
    PORT
      LAYER M4 ;
        RECT  0 87.408 0.192 87.432 ;
    END
  END i_sel[461]
  PIN i_sel[462]
    DIRECTION INPUT ;
    USE SIGNAL ;
    PORT
      LAYER M4 ;
        RECT  0 87.552 0.192 87.576 ;
    END
  END i_sel[462]
  PIN i_sel[463]
    DIRECTION INPUT ;
    USE SIGNAL ;
    PORT
      LAYER M4 ;
        RECT  0 87.84 0.192 87.864 ;
    END
  END i_sel[463]
  PIN i_sel[464]
    DIRECTION INPUT ;
    USE SIGNAL ;
    PORT
      LAYER M4 ;
        RECT  0 87.984 0.192 88.008 ;
    END
  END i_sel[464]
  PIN i_sel[465]
    DIRECTION INPUT ;
    USE SIGNAL ;
    PORT
      LAYER M4 ;
        RECT  0 88.128 0.192 88.152 ;
    END
  END i_sel[465]
  PIN i_sel[466]
    DIRECTION INPUT ;
    USE SIGNAL ;
    PORT
      LAYER M4 ;
        RECT  0 88.272 0.192 88.296 ;
    END
  END i_sel[466]
  PIN i_sel[467]
    DIRECTION INPUT ;
    USE SIGNAL ;
    PORT
      LAYER M4 ;
        RECT  0 88.56 0.192 88.584 ;
    END
  END i_sel[467]
  PIN i_sel[468]
    DIRECTION INPUT ;
    USE SIGNAL ;
    PORT
      LAYER M4 ;
        RECT  0 88.704 0.192 88.728 ;
    END
  END i_sel[468]
  PIN i_sel[469]
    DIRECTION INPUT ;
    USE SIGNAL ;
    PORT
      LAYER M4 ;
        RECT  0 88.848 0.192 88.872 ;
    END
  END i_sel[469]
  PIN i_sel[46]
    DIRECTION INPUT ;
    USE SIGNAL ;
    PORT
      LAYER M4 ;
        RECT  0 12.96 0.192 12.984 ;
    END
  END i_sel[46]
  PIN i_sel[470]
    DIRECTION INPUT ;
    USE SIGNAL ;
    PORT
      LAYER M4 ;
        RECT  0 88.992 0.192 89.016 ;
    END
  END i_sel[470]
  PIN i_sel[471]
    DIRECTION INPUT ;
    USE SIGNAL ;
    PORT
      LAYER M4 ;
        RECT  0 89.28 0.192 89.304 ;
    END
  END i_sel[471]
  PIN i_sel[472]
    DIRECTION INPUT ;
    USE SIGNAL ;
    PORT
      LAYER M4 ;
        RECT  0 89.424 0.192 89.448 ;
    END
  END i_sel[472]
  PIN i_sel[473]
    DIRECTION INPUT ;
    USE SIGNAL ;
    PORT
      LAYER M4 ;
        RECT  0 89.568 0.192 89.592 ;
    END
  END i_sel[473]
  PIN i_sel[474]
    DIRECTION INPUT ;
    USE SIGNAL ;
    PORT
      LAYER M4 ;
        RECT  0 89.712 0.192 89.736 ;
    END
  END i_sel[474]
  PIN i_sel[475]
    DIRECTION INPUT ;
    USE SIGNAL ;
    PORT
      LAYER M4 ;
        RECT  0 90 0.192 90.024 ;
    END
  END i_sel[475]
  PIN i_sel[476]
    DIRECTION INPUT ;
    USE SIGNAL ;
    PORT
      LAYER M4 ;
        RECT  0 90.144 0.192 90.168 ;
    END
  END i_sel[476]
  PIN i_sel[477]
    DIRECTION INPUT ;
    USE SIGNAL ;
    PORT
      LAYER M4 ;
        RECT  0 90.288 0.192 90.312 ;
    END
  END i_sel[477]
  PIN i_sel[478]
    DIRECTION INPUT ;
    USE SIGNAL ;
    PORT
      LAYER M4 ;
        RECT  0 90.432 0.192 90.456 ;
    END
  END i_sel[478]
  PIN i_sel[479]
    DIRECTION INPUT ;
    USE SIGNAL ;
    PORT
      LAYER M4 ;
        RECT  0 90.72 0.192 90.744 ;
    END
  END i_sel[479]
  PIN i_sel[47]
    DIRECTION INPUT ;
    USE SIGNAL ;
    PORT
      LAYER M4 ;
        RECT  0 13.104 0.192 13.128 ;
    END
  END i_sel[47]
  PIN i_sel[480]
    DIRECTION INPUT ;
    USE SIGNAL ;
    PORT
      LAYER M4 ;
        RECT  0 90.864 0.192 90.888 ;
    END
  END i_sel[480]
  PIN i_sel[481]
    DIRECTION INPUT ;
    USE SIGNAL ;
    PORT
      LAYER M4 ;
        RECT  0 91.008 0.192 91.032 ;
    END
  END i_sel[481]
  PIN i_sel[482]
    DIRECTION INPUT ;
    USE SIGNAL ;
    PORT
      LAYER M4 ;
        RECT  0 91.152 0.192 91.176 ;
    END
  END i_sel[482]
  PIN i_sel[483]
    DIRECTION INPUT ;
    USE SIGNAL ;
    PORT
      LAYER M4 ;
        RECT  0 91.44 0.192 91.464 ;
    END
  END i_sel[483]
  PIN i_sel[484]
    DIRECTION INPUT ;
    USE SIGNAL ;
    PORT
      LAYER M4 ;
        RECT  0 91.584 0.192 91.608 ;
    END
  END i_sel[484]
  PIN i_sel[485]
    DIRECTION INPUT ;
    USE SIGNAL ;
    PORT
      LAYER M4 ;
        RECT  0 91.728 0.192 91.752 ;
    END
  END i_sel[485]
  PIN i_sel[486]
    DIRECTION INPUT ;
    USE SIGNAL ;
    PORT
      LAYER M4 ;
        RECT  0 91.872 0.192 91.896 ;
    END
  END i_sel[486]
  PIN i_sel[487]
    DIRECTION INPUT ;
    USE SIGNAL ;
    PORT
      LAYER M4 ;
        RECT  0 92.16 0.192 92.184 ;
    END
  END i_sel[487]
  PIN i_sel[488]
    DIRECTION INPUT ;
    USE SIGNAL ;
    PORT
      LAYER M4 ;
        RECT  0 92.304 0.192 92.328 ;
    END
  END i_sel[488]
  PIN i_sel[489]
    DIRECTION INPUT ;
    USE SIGNAL ;
    PORT
      LAYER M4 ;
        RECT  0 92.448 0.192 92.472 ;
    END
  END i_sel[489]
  PIN i_sel[48]
    DIRECTION INPUT ;
    USE SIGNAL ;
    PORT
      LAYER M4 ;
        RECT  0 13.248 0.192 13.272 ;
    END
  END i_sel[48]
  PIN i_sel[490]
    DIRECTION INPUT ;
    USE SIGNAL ;
    PORT
      LAYER M4 ;
        RECT  0 92.592 0.192 92.616 ;
    END
  END i_sel[490]
  PIN i_sel[491]
    DIRECTION INPUT ;
    USE SIGNAL ;
    PORT
      LAYER M4 ;
        RECT  0 92.88 0.192 92.904 ;
    END
  END i_sel[491]
  PIN i_sel[492]
    DIRECTION INPUT ;
    USE SIGNAL ;
    PORT
      LAYER M4 ;
        RECT  0 93.024 0.192 93.048 ;
    END
  END i_sel[492]
  PIN i_sel[493]
    DIRECTION INPUT ;
    USE SIGNAL ;
    PORT
      LAYER M4 ;
        RECT  0 93.168 0.192 93.192 ;
    END
  END i_sel[493]
  PIN i_sel[494]
    DIRECTION INPUT ;
    USE SIGNAL ;
    PORT
      LAYER M4 ;
        RECT  0 93.312 0.192 93.336 ;
    END
  END i_sel[494]
  PIN i_sel[495]
    DIRECTION INPUT ;
    USE SIGNAL ;
    PORT
      LAYER M4 ;
        RECT  0 93.6 0.192 93.624 ;
    END
  END i_sel[495]
  PIN i_sel[496]
    DIRECTION INPUT ;
    USE SIGNAL ;
    PORT
      LAYER M4 ;
        RECT  0 93.744 0.192 93.768 ;
    END
  END i_sel[496]
  PIN i_sel[497]
    DIRECTION INPUT ;
    USE SIGNAL ;
    PORT
      LAYER M4 ;
        RECT  0 93.888 0.192 93.912 ;
    END
  END i_sel[497]
  PIN i_sel[498]
    DIRECTION INPUT ;
    USE SIGNAL ;
    PORT
      LAYER M4 ;
        RECT  0 94.032 0.192 94.056 ;
    END
  END i_sel[498]
  PIN i_sel[499]
    DIRECTION INPUT ;
    USE SIGNAL ;
    PORT
      LAYER M4 ;
        RECT  0 94.32 0.192 94.344 ;
    END
  END i_sel[499]
  PIN i_sel[49]
    DIRECTION INPUT ;
    USE SIGNAL ;
    PORT
      LAYER M4 ;
        RECT  0 13.536 0.192 13.56 ;
    END
  END i_sel[49]
  PIN i_sel[4]
    DIRECTION INPUT ;
    USE SIGNAL ;
    PORT
      LAYER M4 ;
        RECT  0 5.472 0.192 5.496 ;
    END
  END i_sel[4]
  PIN i_sel[500]
    DIRECTION INPUT ;
    USE SIGNAL ;
    PORT
      LAYER M4 ;
        RECT  0 94.464 0.192 94.488 ;
    END
  END i_sel[500]
  PIN i_sel[501]
    DIRECTION INPUT ;
    USE SIGNAL ;
    PORT
      LAYER M4 ;
        RECT  0 94.608 0.192 94.632 ;
    END
  END i_sel[501]
  PIN i_sel[502]
    DIRECTION INPUT ;
    USE SIGNAL ;
    PORT
      LAYER M4 ;
        RECT  0 94.752 0.192 94.776 ;
    END
  END i_sel[502]
  PIN i_sel[503]
    DIRECTION INPUT ;
    USE SIGNAL ;
    PORT
      LAYER M4 ;
        RECT  0 95.04 0.192 95.064 ;
    END
  END i_sel[503]
  PIN i_sel[504]
    DIRECTION INPUT ;
    USE SIGNAL ;
    PORT
      LAYER M4 ;
        RECT  0 95.184 0.192 95.208 ;
    END
  END i_sel[504]
  PIN i_sel[505]
    DIRECTION INPUT ;
    USE SIGNAL ;
    PORT
      LAYER M4 ;
        RECT  0 95.328 0.192 95.352 ;
    END
  END i_sel[505]
  PIN i_sel[506]
    DIRECTION INPUT ;
    USE SIGNAL ;
    PORT
      LAYER M4 ;
        RECT  0 95.472 0.192 95.496 ;
    END
  END i_sel[506]
  PIN i_sel[507]
    DIRECTION INPUT ;
    USE SIGNAL ;
    PORT
      LAYER M4 ;
        RECT  0 95.616 0.192 95.64 ;
    END
  END i_sel[507]
  PIN i_sel[508]
    DIRECTION INPUT ;
    USE SIGNAL ;
    PORT
      LAYER M4 ;
        RECT  0 95.904 0.192 95.928 ;
    END
  END i_sel[508]
  PIN i_sel[509]
    DIRECTION INPUT ;
    USE SIGNAL ;
    PORT
      LAYER M4 ;
        RECT  0 96.048 0.192 96.072 ;
    END
  END i_sel[509]
  PIN i_sel[50]
    DIRECTION INPUT ;
    USE SIGNAL ;
    PORT
      LAYER M4 ;
        RECT  0 13.68 0.192 13.704 ;
    END
  END i_sel[50]
  PIN i_sel[510]
    DIRECTION INPUT ;
    USE SIGNAL ;
    PORT
      LAYER M4 ;
        RECT  0 96.192 0.192 96.216 ;
    END
  END i_sel[510]
  PIN i_sel[511]
    DIRECTION INPUT ;
    USE SIGNAL ;
    PORT
      LAYER M4 ;
        RECT  0 96.336 0.192 96.36 ;
    END
  END i_sel[511]
  PIN i_sel[512]
    DIRECTION INPUT ;
    USE SIGNAL ;
    PORT
      LAYER M4 ;
        RECT  0 96.624 0.192 96.648 ;
    END
  END i_sel[512]
  PIN i_sel[513]
    DIRECTION INPUT ;
    USE SIGNAL ;
    PORT
      LAYER M4 ;
        RECT  0 96.768 0.192 96.792 ;
    END
  END i_sel[513]
  PIN i_sel[514]
    DIRECTION INPUT ;
    USE SIGNAL ;
    PORT
      LAYER M4 ;
        RECT  0 96.912 0.192 96.936 ;
    END
  END i_sel[514]
  PIN i_sel[515]
    DIRECTION INPUT ;
    USE SIGNAL ;
    PORT
      LAYER M4 ;
        RECT  0 97.056 0.192 97.08 ;
    END
  END i_sel[515]
  PIN i_sel[516]
    DIRECTION INPUT ;
    USE SIGNAL ;
    PORT
      LAYER M4 ;
        RECT  0 97.344 0.192 97.368 ;
    END
  END i_sel[516]
  PIN i_sel[517]
    DIRECTION INPUT ;
    USE SIGNAL ;
    PORT
      LAYER M4 ;
        RECT  0 97.488 0.192 97.512 ;
    END
  END i_sel[517]
  PIN i_sel[518]
    DIRECTION INPUT ;
    USE SIGNAL ;
    PORT
      LAYER M4 ;
        RECT  0 97.632 0.192 97.656 ;
    END
  END i_sel[518]
  PIN i_sel[519]
    DIRECTION INPUT ;
    USE SIGNAL ;
    PORT
      LAYER M4 ;
        RECT  0 97.776 0.192 97.8 ;
    END
  END i_sel[519]
  PIN i_sel[51]
    DIRECTION INPUT ;
    USE SIGNAL ;
    PORT
      LAYER M4 ;
        RECT  0 13.824 0.192 13.848 ;
    END
  END i_sel[51]
  PIN i_sel[520]
    DIRECTION INPUT ;
    USE SIGNAL ;
    PORT
      LAYER M4 ;
        RECT  0 98.064 0.192 98.088 ;
    END
  END i_sel[520]
  PIN i_sel[521]
    DIRECTION INPUT ;
    USE SIGNAL ;
    PORT
      LAYER M4 ;
        RECT  0 98.208 0.192 98.232 ;
    END
  END i_sel[521]
  PIN i_sel[522]
    DIRECTION INPUT ;
    USE SIGNAL ;
    PORT
      LAYER M4 ;
        RECT  0 98.352 0.192 98.376 ;
    END
  END i_sel[522]
  PIN i_sel[523]
    DIRECTION INPUT ;
    USE SIGNAL ;
    PORT
      LAYER M4 ;
        RECT  0 98.496 0.192 98.52 ;
    END
  END i_sel[523]
  PIN i_sel[524]
    DIRECTION INPUT ;
    USE SIGNAL ;
    PORT
      LAYER M4 ;
        RECT  0 98.784 0.192 98.808 ;
    END
  END i_sel[524]
  PIN i_sel[525]
    DIRECTION INPUT ;
    USE SIGNAL ;
    PORT
      LAYER M4 ;
        RECT  0 98.928 0.192 98.952 ;
    END
  END i_sel[525]
  PIN i_sel[526]
    DIRECTION INPUT ;
    USE SIGNAL ;
    PORT
      LAYER M4 ;
        RECT  0 99.072 0.192 99.096 ;
    END
  END i_sel[526]
  PIN i_sel[527]
    DIRECTION INPUT ;
    USE SIGNAL ;
    PORT
      LAYER M4 ;
        RECT  0 99.216 0.192 99.24 ;
    END
  END i_sel[527]
  PIN i_sel[528]
    DIRECTION INPUT ;
    USE SIGNAL ;
    PORT
      LAYER M4 ;
        RECT  0 99.504 0.192 99.528 ;
    END
  END i_sel[528]
  PIN i_sel[529]
    DIRECTION INPUT ;
    USE SIGNAL ;
    PORT
      LAYER M4 ;
        RECT  0 99.648 0.192 99.672 ;
    END
  END i_sel[529]
  PIN i_sel[52]
    DIRECTION INPUT ;
    USE SIGNAL ;
    PORT
      LAYER M4 ;
        RECT  0 13.968 0.192 13.992 ;
    END
  END i_sel[52]
  PIN i_sel[530]
    DIRECTION INPUT ;
    USE SIGNAL ;
    PORT
      LAYER M4 ;
        RECT  0 99.792 0.192 99.816 ;
    END
  END i_sel[530]
  PIN i_sel[531]
    DIRECTION INPUT ;
    USE SIGNAL ;
    PORT
      LAYER M4 ;
        RECT  0 99.936 0.192 99.96 ;
    END
  END i_sel[531]
  PIN i_sel[532]
    DIRECTION INPUT ;
    USE SIGNAL ;
    PORT
      LAYER M4 ;
        RECT  0 100.224 0.192 100.248 ;
    END
  END i_sel[532]
  PIN i_sel[533]
    DIRECTION INPUT ;
    USE SIGNAL ;
    PORT
      LAYER M4 ;
        RECT  0 100.368 0.192 100.392 ;
    END
  END i_sel[533]
  PIN i_sel[534]
    DIRECTION INPUT ;
    USE SIGNAL ;
    PORT
      LAYER M4 ;
        RECT  0 100.512 0.192 100.536 ;
    END
  END i_sel[534]
  PIN i_sel[535]
    DIRECTION INPUT ;
    USE SIGNAL ;
    PORT
      LAYER M4 ;
        RECT  0 100.656 0.192 100.68 ;
    END
  END i_sel[535]
  PIN i_sel[536]
    DIRECTION INPUT ;
    USE SIGNAL ;
    PORT
      LAYER M4 ;
        RECT  0 100.944 0.192 100.968 ;
    END
  END i_sel[536]
  PIN i_sel[537]
    DIRECTION INPUT ;
    USE SIGNAL ;
    PORT
      LAYER M4 ;
        RECT  0 101.088 0.192 101.112 ;
    END
  END i_sel[537]
  PIN i_sel[538]
    DIRECTION INPUT ;
    USE SIGNAL ;
    PORT
      LAYER M4 ;
        RECT  0 101.232 0.192 101.256 ;
    END
  END i_sel[538]
  PIN i_sel[539]
    DIRECTION INPUT ;
    USE SIGNAL ;
    PORT
      LAYER M4 ;
        RECT  0 101.376 0.192 101.4 ;
    END
  END i_sel[539]
  PIN i_sel[53]
    DIRECTION INPUT ;
    USE SIGNAL ;
    PORT
      LAYER M4 ;
        RECT  0 14.256 0.192 14.28 ;
    END
  END i_sel[53]
  PIN i_sel[540]
    DIRECTION INPUT ;
    USE SIGNAL ;
    PORT
      LAYER M4 ;
        RECT  0 101.664 0.192 101.688 ;
    END
  END i_sel[540]
  PIN i_sel[541]
    DIRECTION INPUT ;
    USE SIGNAL ;
    PORT
      LAYER M4 ;
        RECT  0 101.808 0.192 101.832 ;
    END
  END i_sel[541]
  PIN i_sel[542]
    DIRECTION INPUT ;
    USE SIGNAL ;
    PORT
      LAYER M4 ;
        RECT  0 101.952 0.192 101.976 ;
    END
  END i_sel[542]
  PIN i_sel[543]
    DIRECTION INPUT ;
    USE SIGNAL ;
    PORT
      LAYER M4 ;
        RECT  0 102.096 0.192 102.12 ;
    END
  END i_sel[543]
  PIN i_sel[544]
    DIRECTION INPUT ;
    USE SIGNAL ;
    PORT
      LAYER M4 ;
        RECT  0 102.384 0.192 102.408 ;
    END
  END i_sel[544]
  PIN i_sel[545]
    DIRECTION INPUT ;
    USE SIGNAL ;
    PORT
      LAYER M4 ;
        RECT  0 102.528 0.192 102.552 ;
    END
  END i_sel[545]
  PIN i_sel[546]
    DIRECTION INPUT ;
    USE SIGNAL ;
    PORT
      LAYER M4 ;
        RECT  0 102.672 0.192 102.696 ;
    END
  END i_sel[546]
  PIN i_sel[547]
    DIRECTION INPUT ;
    USE SIGNAL ;
    PORT
      LAYER M4 ;
        RECT  0 102.816 0.192 102.84 ;
    END
  END i_sel[547]
  PIN i_sel[548]
    DIRECTION INPUT ;
    USE SIGNAL ;
    PORT
      LAYER M4 ;
        RECT  0 103.104 0.192 103.128 ;
    END
  END i_sel[548]
  PIN i_sel[549]
    DIRECTION INPUT ;
    USE SIGNAL ;
    PORT
      LAYER M4 ;
        RECT  0 103.248 0.192 103.272 ;
    END
  END i_sel[549]
  PIN i_sel[54]
    DIRECTION INPUT ;
    USE SIGNAL ;
    PORT
      LAYER M4 ;
        RECT  0 14.4 0.192 14.424 ;
    END
  END i_sel[54]
  PIN i_sel[550]
    DIRECTION INPUT ;
    USE SIGNAL ;
    PORT
      LAYER M4 ;
        RECT  0 103.392 0.192 103.416 ;
    END
  END i_sel[550]
  PIN i_sel[551]
    DIRECTION INPUT ;
    USE SIGNAL ;
    PORT
      LAYER M4 ;
        RECT  0 103.536 0.192 103.56 ;
    END
  END i_sel[551]
  PIN i_sel[552]
    DIRECTION INPUT ;
    USE SIGNAL ;
    PORT
      LAYER M4 ;
        RECT  0 103.824 0.192 103.848 ;
    END
  END i_sel[552]
  PIN i_sel[553]
    DIRECTION INPUT ;
    USE SIGNAL ;
    PORT
      LAYER M4 ;
        RECT  0 103.968 0.192 103.992 ;
    END
  END i_sel[553]
  PIN i_sel[554]
    DIRECTION INPUT ;
    USE SIGNAL ;
    PORT
      LAYER M4 ;
        RECT  0 104.112 0.192 104.136 ;
    END
  END i_sel[554]
  PIN i_sel[555]
    DIRECTION INPUT ;
    USE SIGNAL ;
    PORT
      LAYER M4 ;
        RECT  0 104.256 0.192 104.28 ;
    END
  END i_sel[555]
  PIN i_sel[556]
    DIRECTION INPUT ;
    USE SIGNAL ;
    PORT
      LAYER M4 ;
        RECT  0 104.544 0.192 104.568 ;
    END
  END i_sel[556]
  PIN i_sel[557]
    DIRECTION INPUT ;
    USE SIGNAL ;
    PORT
      LAYER M4 ;
        RECT  0 104.688 0.192 104.712 ;
    END
  END i_sel[557]
  PIN i_sel[558]
    DIRECTION INPUT ;
    USE SIGNAL ;
    PORT
      LAYER M4 ;
        RECT  0 104.832 0.192 104.856 ;
    END
  END i_sel[558]
  PIN i_sel[559]
    DIRECTION INPUT ;
    USE SIGNAL ;
    PORT
      LAYER M4 ;
        RECT  0 104.976 0.192 105 ;
    END
  END i_sel[559]
  PIN i_sel[55]
    DIRECTION INPUT ;
    USE SIGNAL ;
    PORT
      LAYER M4 ;
        RECT  0 14.544 0.192 14.568 ;
    END
  END i_sel[55]
  PIN i_sel[560]
    DIRECTION INPUT ;
    USE SIGNAL ;
    PORT
      LAYER M4 ;
        RECT  0 105.264 0.192 105.288 ;
    END
  END i_sel[560]
  PIN i_sel[561]
    DIRECTION INPUT ;
    USE SIGNAL ;
    PORT
      LAYER M4 ;
        RECT  0 105.408 0.192 105.432 ;
    END
  END i_sel[561]
  PIN i_sel[562]
    DIRECTION INPUT ;
    USE SIGNAL ;
    PORT
      LAYER M4 ;
        RECT  0 105.552 0.192 105.576 ;
    END
  END i_sel[562]
  PIN i_sel[563]
    DIRECTION INPUT ;
    USE SIGNAL ;
    PORT
      LAYER M4 ;
        RECT  0 105.696 0.192 105.72 ;
    END
  END i_sel[563]
  PIN i_sel[564]
    DIRECTION INPUT ;
    USE SIGNAL ;
    PORT
      LAYER M4 ;
        RECT  0 105.984 0.192 106.008 ;
    END
  END i_sel[564]
  PIN i_sel[565]
    DIRECTION INPUT ;
    USE SIGNAL ;
    PORT
      LAYER M4 ;
        RECT  0 106.128 0.192 106.152 ;
    END
  END i_sel[565]
  PIN i_sel[566]
    DIRECTION INPUT ;
    USE SIGNAL ;
    PORT
      LAYER M4 ;
        RECT  0 106.272 0.192 106.296 ;
    END
  END i_sel[566]
  PIN i_sel[567]
    DIRECTION INPUT ;
    USE SIGNAL ;
    PORT
      LAYER M4 ;
        RECT  0 106.416 0.192 106.44 ;
    END
  END i_sel[567]
  PIN i_sel[568]
    DIRECTION INPUT ;
    USE SIGNAL ;
    PORT
      LAYER M4 ;
        RECT  0 106.704 0.192 106.728 ;
    END
  END i_sel[568]
  PIN i_sel[569]
    DIRECTION INPUT ;
    USE SIGNAL ;
    PORT
      LAYER M4 ;
        RECT  0 106.848 0.192 106.872 ;
    END
  END i_sel[569]
  PIN i_sel[56]
    DIRECTION INPUT ;
    USE SIGNAL ;
    PORT
      LAYER M4 ;
        RECT  0 14.688 0.192 14.712 ;
    END
  END i_sel[56]
  PIN i_sel[570]
    DIRECTION INPUT ;
    USE SIGNAL ;
    PORT
      LAYER M4 ;
        RECT  0 106.992 0.192 107.016 ;
    END
  END i_sel[570]
  PIN i_sel[571]
    DIRECTION INPUT ;
    USE SIGNAL ;
    PORT
      LAYER M4 ;
        RECT  0 107.136 0.192 107.16 ;
    END
  END i_sel[571]
  PIN i_sel[572]
    DIRECTION INPUT ;
    USE SIGNAL ;
    PORT
      LAYER M4 ;
        RECT  0 107.28 0.192 107.304 ;
    END
  END i_sel[572]
  PIN i_sel[573]
    DIRECTION INPUT ;
    USE SIGNAL ;
    PORT
      LAYER M4 ;
        RECT  0 107.568 0.192 107.592 ;
    END
  END i_sel[573]
  PIN i_sel[574]
    DIRECTION INPUT ;
    USE SIGNAL ;
    PORT
      LAYER M4 ;
        RECT  0 107.712 0.192 107.736 ;
    END
  END i_sel[574]
  PIN i_sel[575]
    DIRECTION INPUT ;
    USE SIGNAL ;
    PORT
      LAYER M4 ;
        RECT  0 107.856 0.192 107.88 ;
    END
  END i_sel[575]
  PIN i_sel[576]
    DIRECTION INPUT ;
    USE SIGNAL ;
    PORT
      LAYER M4 ;
        RECT  0 108 0.192 108.024 ;
    END
  END i_sel[576]
  PIN i_sel[577]
    DIRECTION INPUT ;
    USE SIGNAL ;
    PORT
      LAYER M4 ;
        RECT  0 108.288 0.192 108.312 ;
    END
  END i_sel[577]
  PIN i_sel[578]
    DIRECTION INPUT ;
    USE SIGNAL ;
    PORT
      LAYER M4 ;
        RECT  0 108.432 0.192 108.456 ;
    END
  END i_sel[578]
  PIN i_sel[579]
    DIRECTION INPUT ;
    USE SIGNAL ;
    PORT
      LAYER M4 ;
        RECT  0 108.576 0.192 108.6 ;
    END
  END i_sel[579]
  PIN i_sel[57]
    DIRECTION INPUT ;
    USE SIGNAL ;
    PORT
      LAYER M4 ;
        RECT  0 14.976 0.192 15 ;
    END
  END i_sel[57]
  PIN i_sel[580]
    DIRECTION INPUT ;
    USE SIGNAL ;
    PORT
      LAYER M4 ;
        RECT  0 108.72 0.192 108.744 ;
    END
  END i_sel[580]
  PIN i_sel[581]
    DIRECTION INPUT ;
    USE SIGNAL ;
    PORT
      LAYER M4 ;
        RECT  0 109.008 0.192 109.032 ;
    END
  END i_sel[581]
  PIN i_sel[582]
    DIRECTION INPUT ;
    USE SIGNAL ;
    PORT
      LAYER M4 ;
        RECT  0 109.152 0.192 109.176 ;
    END
  END i_sel[582]
  PIN i_sel[583]
    DIRECTION INPUT ;
    USE SIGNAL ;
    PORT
      LAYER M4 ;
        RECT  0 109.296 0.192 109.32 ;
    END
  END i_sel[583]
  PIN i_sel[584]
    DIRECTION INPUT ;
    USE SIGNAL ;
    PORT
      LAYER M4 ;
        RECT  0 109.44 0.192 109.464 ;
    END
  END i_sel[584]
  PIN i_sel[585]
    DIRECTION INPUT ;
    USE SIGNAL ;
    PORT
      LAYER M4 ;
        RECT  0 109.728 0.192 109.752 ;
    END
  END i_sel[585]
  PIN i_sel[586]
    DIRECTION INPUT ;
    USE SIGNAL ;
    PORT
      LAYER M4 ;
        RECT  0 109.872 0.192 109.896 ;
    END
  END i_sel[586]
  PIN i_sel[587]
    DIRECTION INPUT ;
    USE SIGNAL ;
    PORT
      LAYER M4 ;
        RECT  0 110.016 0.192 110.04 ;
    END
  END i_sel[587]
  PIN i_sel[588]
    DIRECTION INPUT ;
    USE SIGNAL ;
    PORT
      LAYER M4 ;
        RECT  0 110.16 0.192 110.184 ;
    END
  END i_sel[588]
  PIN i_sel[589]
    DIRECTION INPUT ;
    USE SIGNAL ;
    PORT
      LAYER M4 ;
        RECT  0 110.448 0.192 110.472 ;
    END
  END i_sel[589]
  PIN i_sel[58]
    DIRECTION INPUT ;
    USE SIGNAL ;
    PORT
      LAYER M4 ;
        RECT  0 15.12 0.192 15.144 ;
    END
  END i_sel[58]
  PIN i_sel[590]
    DIRECTION INPUT ;
    USE SIGNAL ;
    PORT
      LAYER M4 ;
        RECT  0 110.592 0.192 110.616 ;
    END
  END i_sel[590]
  PIN i_sel[591]
    DIRECTION INPUT ;
    USE SIGNAL ;
    PORT
      LAYER M4 ;
        RECT  0 110.736 0.192 110.76 ;
    END
  END i_sel[591]
  PIN i_sel[592]
    DIRECTION INPUT ;
    USE SIGNAL ;
    PORT
      LAYER M4 ;
        RECT  0 110.88 0.192 110.904 ;
    END
  END i_sel[592]
  PIN i_sel[593]
    DIRECTION INPUT ;
    USE SIGNAL ;
    PORT
      LAYER M4 ;
        RECT  0 111.168 0.192 111.192 ;
    END
  END i_sel[593]
  PIN i_sel[594]
    DIRECTION INPUT ;
    USE SIGNAL ;
    PORT
      LAYER M4 ;
        RECT  0 111.312 0.192 111.336 ;
    END
  END i_sel[594]
  PIN i_sel[595]
    DIRECTION INPUT ;
    USE SIGNAL ;
    PORT
      LAYER M4 ;
        RECT  0 111.456 0.192 111.48 ;
    END
  END i_sel[595]
  PIN i_sel[596]
    DIRECTION INPUT ;
    USE SIGNAL ;
    PORT
      LAYER M4 ;
        RECT  0 111.6 0.192 111.624 ;
    END
  END i_sel[596]
  PIN i_sel[597]
    DIRECTION INPUT ;
    USE SIGNAL ;
    PORT
      LAYER M4 ;
        RECT  0 111.888 0.192 111.912 ;
    END
  END i_sel[597]
  PIN i_sel[598]
    DIRECTION INPUT ;
    USE SIGNAL ;
    PORT
      LAYER M4 ;
        RECT  0 112.032 0.192 112.056 ;
    END
  END i_sel[598]
  PIN i_sel[599]
    DIRECTION INPUT ;
    USE SIGNAL ;
    PORT
      LAYER M4 ;
        RECT  0 112.176 0.192 112.2 ;
    END
  END i_sel[599]
  PIN i_sel[59]
    DIRECTION INPUT ;
    USE SIGNAL ;
    PORT
      LAYER M4 ;
        RECT  0 15.264 0.192 15.288 ;
    END
  END i_sel[59]
  PIN i_sel[5]
    DIRECTION INPUT ;
    USE SIGNAL ;
    PORT
      LAYER M4 ;
        RECT  0 5.616 0.192 5.64 ;
    END
  END i_sel[5]
  PIN i_sel[600]
    DIRECTION INPUT ;
    USE SIGNAL ;
    PORT
      LAYER M4 ;
        RECT  0 112.32 0.192 112.344 ;
    END
  END i_sel[600]
  PIN i_sel[601]
    DIRECTION INPUT ;
    USE SIGNAL ;
    PORT
      LAYER M4 ;
        RECT  0 112.608 0.192 112.632 ;
    END
  END i_sel[601]
  PIN i_sel[602]
    DIRECTION INPUT ;
    USE SIGNAL ;
    PORT
      LAYER M4 ;
        RECT  0 112.752 0.192 112.776 ;
    END
  END i_sel[602]
  PIN i_sel[603]
    DIRECTION INPUT ;
    USE SIGNAL ;
    PORT
      LAYER M4 ;
        RECT  0 112.896 0.192 112.92 ;
    END
  END i_sel[603]
  PIN i_sel[604]
    DIRECTION INPUT ;
    USE SIGNAL ;
    PORT
      LAYER M4 ;
        RECT  0 113.04 0.192 113.064 ;
    END
  END i_sel[604]
  PIN i_sel[605]
    DIRECTION INPUT ;
    USE SIGNAL ;
    PORT
      LAYER M4 ;
        RECT  0 113.328 0.192 113.352 ;
    END
  END i_sel[605]
  PIN i_sel[606]
    DIRECTION INPUT ;
    USE SIGNAL ;
    PORT
      LAYER M4 ;
        RECT  0 113.472 0.192 113.496 ;
    END
  END i_sel[606]
  PIN i_sel[607]
    DIRECTION INPUT ;
    USE SIGNAL ;
    PORT
      LAYER M4 ;
        RECT  0 113.616 0.192 113.64 ;
    END
  END i_sel[607]
  PIN i_sel[608]
    DIRECTION INPUT ;
    USE SIGNAL ;
    PORT
      LAYER M4 ;
        RECT  0 113.76 0.192 113.784 ;
    END
  END i_sel[608]
  PIN i_sel[609]
    DIRECTION INPUT ;
    USE SIGNAL ;
    PORT
      LAYER M4 ;
        RECT  0 114.048 0.192 114.072 ;
    END
  END i_sel[609]
  PIN i_sel[60]
    DIRECTION INPUT ;
    USE SIGNAL ;
    PORT
      LAYER M4 ;
        RECT  0 15.408 0.192 15.432 ;
    END
  END i_sel[60]
  PIN i_sel[610]
    DIRECTION INPUT ;
    USE SIGNAL ;
    PORT
      LAYER M4 ;
        RECT  0 114.192 0.192 114.216 ;
    END
  END i_sel[610]
  PIN i_sel[611]
    DIRECTION INPUT ;
    USE SIGNAL ;
    PORT
      LAYER M4 ;
        RECT  0 114.336 0.192 114.36 ;
    END
  END i_sel[611]
  PIN i_sel[612]
    DIRECTION INPUT ;
    USE SIGNAL ;
    PORT
      LAYER M4 ;
        RECT  0 114.48 0.192 114.504 ;
    END
  END i_sel[612]
  PIN i_sel[613]
    DIRECTION INPUT ;
    USE SIGNAL ;
    PORT
      LAYER M4 ;
        RECT  0 114.768 0.192 114.792 ;
    END
  END i_sel[613]
  PIN i_sel[614]
    DIRECTION INPUT ;
    USE SIGNAL ;
    PORT
      LAYER M4 ;
        RECT  0 114.912 0.192 114.936 ;
    END
  END i_sel[614]
  PIN i_sel[615]
    DIRECTION INPUT ;
    USE SIGNAL ;
    PORT
      LAYER M4 ;
        RECT  0 115.056 0.192 115.08 ;
    END
  END i_sel[615]
  PIN i_sel[616]
    DIRECTION INPUT ;
    USE SIGNAL ;
    PORT
      LAYER M4 ;
        RECT  0 115.2 0.192 115.224 ;
    END
  END i_sel[616]
  PIN i_sel[617]
    DIRECTION INPUT ;
    USE SIGNAL ;
    PORT
      LAYER M4 ;
        RECT  0 115.488 0.192 115.512 ;
    END
  END i_sel[617]
  PIN i_sel[618]
    DIRECTION INPUT ;
    USE SIGNAL ;
    PORT
      LAYER M4 ;
        RECT  0 115.632 0.192 115.656 ;
    END
  END i_sel[618]
  PIN i_sel[619]
    DIRECTION INPUT ;
    USE SIGNAL ;
    PORT
      LAYER M4 ;
        RECT  0 115.776 0.192 115.8 ;
    END
  END i_sel[619]
  PIN i_sel[61]
    DIRECTION INPUT ;
    USE SIGNAL ;
    PORT
      LAYER M4 ;
        RECT  0 15.696 0.192 15.72 ;
    END
  END i_sel[61]
  PIN i_sel[620]
    DIRECTION INPUT ;
    USE SIGNAL ;
    PORT
      LAYER M4 ;
        RECT  0 115.92 0.192 115.944 ;
    END
  END i_sel[620]
  PIN i_sel[621]
    DIRECTION INPUT ;
    USE SIGNAL ;
    PORT
      LAYER M4 ;
        RECT  0 116.208 0.192 116.232 ;
    END
  END i_sel[621]
  PIN i_sel[622]
    DIRECTION INPUT ;
    USE SIGNAL ;
    PORT
      LAYER M4 ;
        RECT  0 116.352 0.192 116.376 ;
    END
  END i_sel[622]
  PIN i_sel[623]
    DIRECTION INPUT ;
    USE SIGNAL ;
    PORT
      LAYER M4 ;
        RECT  0 116.496 0.192 116.52 ;
    END
  END i_sel[623]
  PIN i_sel[624]
    DIRECTION INPUT ;
    USE SIGNAL ;
    PORT
      LAYER M4 ;
        RECT  0 116.64 0.192 116.664 ;
    END
  END i_sel[624]
  PIN i_sel[625]
    DIRECTION INPUT ;
    USE SIGNAL ;
    PORT
      LAYER M4 ;
        RECT  0 116.928 0.192 116.952 ;
    END
  END i_sel[625]
  PIN i_sel[626]
    DIRECTION INPUT ;
    USE SIGNAL ;
    PORT
      LAYER M4 ;
        RECT  0 117.072 0.192 117.096 ;
    END
  END i_sel[626]
  PIN i_sel[627]
    DIRECTION INPUT ;
    USE SIGNAL ;
    PORT
      LAYER M4 ;
        RECT  0 117.216 0.192 117.24 ;
    END
  END i_sel[627]
  PIN i_sel[628]
    DIRECTION INPUT ;
    USE SIGNAL ;
    PORT
      LAYER M4 ;
        RECT  0 117.36 0.192 117.384 ;
    END
  END i_sel[628]
  PIN i_sel[629]
    DIRECTION INPUT ;
    USE SIGNAL ;
    PORT
      LAYER M4 ;
        RECT  0 117.648 0.192 117.672 ;
    END
  END i_sel[629]
  PIN i_sel[62]
    DIRECTION INPUT ;
    USE SIGNAL ;
    PORT
      LAYER M4 ;
        RECT  0 15.84 0.192 15.864 ;
    END
  END i_sel[62]
  PIN i_sel[630]
    DIRECTION INPUT ;
    USE SIGNAL ;
    PORT
      LAYER M4 ;
        RECT  0 117.792 0.192 117.816 ;
    END
  END i_sel[630]
  PIN i_sel[631]
    DIRECTION INPUT ;
    USE SIGNAL ;
    PORT
      LAYER M4 ;
        RECT  0 117.936 0.192 117.96 ;
    END
  END i_sel[631]
  PIN i_sel[632]
    DIRECTION INPUT ;
    USE SIGNAL ;
    PORT
      LAYER M4 ;
        RECT  0 118.08 0.192 118.104 ;
    END
  END i_sel[632]
  PIN i_sel[633]
    DIRECTION INPUT ;
    USE SIGNAL ;
    PORT
      LAYER M4 ;
        RECT  0 118.368 0.192 118.392 ;
    END
  END i_sel[633]
  PIN i_sel[634]
    DIRECTION INPUT ;
    USE SIGNAL ;
    PORT
      LAYER M4 ;
        RECT  0 118.512 0.192 118.536 ;
    END
  END i_sel[634]
  PIN i_sel[635]
    DIRECTION INPUT ;
    USE SIGNAL ;
    PORT
      LAYER M4 ;
        RECT  0 118.656 0.192 118.68 ;
    END
  END i_sel[635]
  PIN i_sel[636]
    DIRECTION INPUT ;
    USE SIGNAL ;
    PORT
      LAYER M4 ;
        RECT  0 118.8 0.192 118.824 ;
    END
  END i_sel[636]
  PIN i_sel[637]
    DIRECTION INPUT ;
    USE SIGNAL ;
    PORT
      LAYER M4 ;
        RECT  0 119.088 0.192 119.112 ;
    END
  END i_sel[637]
  PIN i_sel[638]
    DIRECTION INPUT ;
    USE SIGNAL ;
    PORT
      LAYER M4 ;
        RECT  0 119.232 0.192 119.256 ;
    END
  END i_sel[638]
  PIN i_sel[639]
    DIRECTION INPUT ;
    USE SIGNAL ;
    PORT
      LAYER M4 ;
        RECT  0 119.376 0.192 119.4 ;
    END
  END i_sel[639]
  PIN i_sel[63]
    DIRECTION INPUT ;
    USE SIGNAL ;
    PORT
      LAYER M4 ;
        RECT  0 15.984 0.192 16.008 ;
    END
  END i_sel[63]
  PIN i_sel[640]
    DIRECTION INPUT ;
    USE SIGNAL ;
    PORT
      LAYER M4 ;
        RECT  0 119.52 0.192 119.544 ;
    END
  END i_sel[640]
  PIN i_sel[641]
    DIRECTION INPUT ;
    USE SIGNAL ;
    PORT
      LAYER M4 ;
        RECT  0 119.664 0.192 119.688 ;
    END
  END i_sel[641]
  PIN i_sel[642]
    DIRECTION INPUT ;
    USE SIGNAL ;
    PORT
      LAYER M4 ;
        RECT  0 119.952 0.192 119.976 ;
    END
  END i_sel[642]
  PIN i_sel[643]
    DIRECTION INPUT ;
    USE SIGNAL ;
    PORT
      LAYER M4 ;
        RECT  0 120.096 0.192 120.12 ;
    END
  END i_sel[643]
  PIN i_sel[644]
    DIRECTION INPUT ;
    USE SIGNAL ;
    PORT
      LAYER M4 ;
        RECT  0 120.24 0.192 120.264 ;
    END
  END i_sel[644]
  PIN i_sel[645]
    DIRECTION INPUT ;
    USE SIGNAL ;
    PORT
      LAYER M4 ;
        RECT  0 120.384 0.192 120.408 ;
    END
  END i_sel[645]
  PIN i_sel[646]
    DIRECTION INPUT ;
    USE SIGNAL ;
    PORT
      LAYER M4 ;
        RECT  0 120.672 0.192 120.696 ;
    END
  END i_sel[646]
  PIN i_sel[647]
    DIRECTION INPUT ;
    USE SIGNAL ;
    PORT
      LAYER M4 ;
        RECT  0 120.816 0.192 120.84 ;
    END
  END i_sel[647]
  PIN i_sel[648]
    DIRECTION INPUT ;
    USE SIGNAL ;
    PORT
      LAYER M4 ;
        RECT  0 120.96 0.192 120.984 ;
    END
  END i_sel[648]
  PIN i_sel[649]
    DIRECTION INPUT ;
    USE SIGNAL ;
    PORT
      LAYER M4 ;
        RECT  0 121.104 0.192 121.128 ;
    END
  END i_sel[649]
  PIN i_sel[64]
    DIRECTION INPUT ;
    USE SIGNAL ;
    PORT
      LAYER M4 ;
        RECT  0 16.128 0.192 16.152 ;
    END
  END i_sel[64]
  PIN i_sel[650]
    DIRECTION INPUT ;
    USE SIGNAL ;
    PORT
      LAYER M4 ;
        RECT  0 121.392 0.192 121.416 ;
    END
  END i_sel[650]
  PIN i_sel[651]
    DIRECTION INPUT ;
    USE SIGNAL ;
    PORT
      LAYER M4 ;
        RECT  0 121.536 0.192 121.56 ;
    END
  END i_sel[651]
  PIN i_sel[652]
    DIRECTION INPUT ;
    USE SIGNAL ;
    PORT
      LAYER M4 ;
        RECT  0 121.68 0.192 121.704 ;
    END
  END i_sel[652]
  PIN i_sel[653]
    DIRECTION INPUT ;
    USE SIGNAL ;
    PORT
      LAYER M4 ;
        RECT  0 121.824 0.192 121.848 ;
    END
  END i_sel[653]
  PIN i_sel[654]
    DIRECTION INPUT ;
    USE SIGNAL ;
    PORT
      LAYER M4 ;
        RECT  0 122.112 0.192 122.136 ;
    END
  END i_sel[654]
  PIN i_sel[655]
    DIRECTION INPUT ;
    USE SIGNAL ;
    PORT
      LAYER M4 ;
        RECT  0 122.256 0.192 122.28 ;
    END
  END i_sel[655]
  PIN i_sel[656]
    DIRECTION INPUT ;
    USE SIGNAL ;
    PORT
      LAYER M4 ;
        RECT  0 122.4 0.192 122.424 ;
    END
  END i_sel[656]
  PIN i_sel[657]
    DIRECTION INPUT ;
    USE SIGNAL ;
    PORT
      LAYER M4 ;
        RECT  0 122.544 0.192 122.568 ;
    END
  END i_sel[657]
  PIN i_sel[658]
    DIRECTION INPUT ;
    USE SIGNAL ;
    PORT
      LAYER M4 ;
        RECT  0 122.832 0.192 122.856 ;
    END
  END i_sel[658]
  PIN i_sel[659]
    DIRECTION INPUT ;
    USE SIGNAL ;
    PORT
      LAYER M4 ;
        RECT  0 122.976 0.192 123 ;
    END
  END i_sel[659]
  PIN i_sel[65]
    DIRECTION INPUT ;
    USE SIGNAL ;
    PORT
      LAYER M4 ;
        RECT  0 16.416 0.192 16.44 ;
    END
  END i_sel[65]
  PIN i_sel[660]
    DIRECTION INPUT ;
    USE SIGNAL ;
    PORT
      LAYER M4 ;
        RECT  0 123.12 0.192 123.144 ;
    END
  END i_sel[660]
  PIN i_sel[661]
    DIRECTION INPUT ;
    USE SIGNAL ;
    PORT
      LAYER M4 ;
        RECT  0 123.264 0.192 123.288 ;
    END
  END i_sel[661]
  PIN i_sel[662]
    DIRECTION INPUT ;
    USE SIGNAL ;
    PORT
      LAYER M4 ;
        RECT  0 123.552 0.192 123.576 ;
    END
  END i_sel[662]
  PIN i_sel[663]
    DIRECTION INPUT ;
    USE SIGNAL ;
    PORT
      LAYER M4 ;
        RECT  0 123.696 0.192 123.72 ;
    END
  END i_sel[663]
  PIN i_sel[664]
    DIRECTION INPUT ;
    USE SIGNAL ;
    PORT
      LAYER M4 ;
        RECT  0 123.84 0.192 123.864 ;
    END
  END i_sel[664]
  PIN i_sel[665]
    DIRECTION INPUT ;
    USE SIGNAL ;
    PORT
      LAYER M4 ;
        RECT  0 123.984 0.192 124.008 ;
    END
  END i_sel[665]
  PIN i_sel[666]
    DIRECTION INPUT ;
    USE SIGNAL ;
    PORT
      LAYER M4 ;
        RECT  0 124.272 0.192 124.296 ;
    END
  END i_sel[666]
  PIN i_sel[667]
    DIRECTION INPUT ;
    USE SIGNAL ;
    PORT
      LAYER M4 ;
        RECT  0 124.416 0.192 124.44 ;
    END
  END i_sel[667]
  PIN i_sel[668]
    DIRECTION INPUT ;
    USE SIGNAL ;
    PORT
      LAYER M4 ;
        RECT  0 124.56 0.192 124.584 ;
    END
  END i_sel[668]
  PIN i_sel[669]
    DIRECTION INPUT ;
    USE SIGNAL ;
    PORT
      LAYER M4 ;
        RECT  0 124.704 0.192 124.728 ;
    END
  END i_sel[669]
  PIN i_sel[66]
    DIRECTION INPUT ;
    USE SIGNAL ;
    PORT
      LAYER M4 ;
        RECT  0 16.56 0.192 16.584 ;
    END
  END i_sel[66]
  PIN i_sel[670]
    DIRECTION INPUT ;
    USE SIGNAL ;
    PORT
      LAYER M4 ;
        RECT  0 124.992 0.192 125.016 ;
    END
  END i_sel[670]
  PIN i_sel[671]
    DIRECTION INPUT ;
    USE SIGNAL ;
    PORT
      LAYER M4 ;
        RECT  0 125.136 0.192 125.16 ;
    END
  END i_sel[671]
  PIN i_sel[67]
    DIRECTION INPUT ;
    USE SIGNAL ;
    PORT
      LAYER M4 ;
        RECT  0 16.704 0.192 16.728 ;
    END
  END i_sel[67]
  PIN i_sel[68]
    DIRECTION INPUT ;
    USE SIGNAL ;
    PORT
      LAYER M4 ;
        RECT  0 16.848 0.192 16.872 ;
    END
  END i_sel[68]
  PIN i_sel[69]
    DIRECTION INPUT ;
    USE SIGNAL ;
    PORT
      LAYER M4 ;
        RECT  0 17.136 0.192 17.16 ;
    END
  END i_sel[69]
  PIN i_sel[6]
    DIRECTION INPUT ;
    USE SIGNAL ;
    PORT
      LAYER M4 ;
        RECT  0 5.76 0.192 5.784 ;
    END
  END i_sel[6]
  PIN i_sel[70]
    DIRECTION INPUT ;
    USE SIGNAL ;
    PORT
      LAYER M4 ;
        RECT  0 17.28 0.192 17.304 ;
    END
  END i_sel[70]
  PIN i_sel[71]
    DIRECTION INPUT ;
    USE SIGNAL ;
    PORT
      LAYER M4 ;
        RECT  0 17.424 0.192 17.448 ;
    END
  END i_sel[71]
  PIN i_sel[72]
    DIRECTION INPUT ;
    USE SIGNAL ;
    PORT
      LAYER M4 ;
        RECT  0 17.568 0.192 17.592 ;
    END
  END i_sel[72]
  PIN i_sel[73]
    DIRECTION INPUT ;
    USE SIGNAL ;
    PORT
      LAYER M4 ;
        RECT  0 17.856 0.192 17.88 ;
    END
  END i_sel[73]
  PIN i_sel[74]
    DIRECTION INPUT ;
    USE SIGNAL ;
    PORT
      LAYER M4 ;
        RECT  0 18 0.192 18.024 ;
    END
  END i_sel[74]
  PIN i_sel[75]
    DIRECTION INPUT ;
    USE SIGNAL ;
    PORT
      LAYER M4 ;
        RECT  0 18.144 0.192 18.168 ;
    END
  END i_sel[75]
  PIN i_sel[76]
    DIRECTION INPUT ;
    USE SIGNAL ;
    PORT
      LAYER M4 ;
        RECT  0 18.288 0.192 18.312 ;
    END
  END i_sel[76]
  PIN i_sel[77]
    DIRECTION INPUT ;
    USE SIGNAL ;
    PORT
      LAYER M4 ;
        RECT  0 18.576 0.192 18.6 ;
    END
  END i_sel[77]
  PIN i_sel[78]
    DIRECTION INPUT ;
    USE SIGNAL ;
    PORT
      LAYER M4 ;
        RECT  0 18.72 0.192 18.744 ;
    END
  END i_sel[78]
  PIN i_sel[79]
    DIRECTION INPUT ;
    USE SIGNAL ;
    PORT
      LAYER M4 ;
        RECT  0 18.864 0.192 18.888 ;
    END
  END i_sel[79]
  PIN i_sel[7]
    DIRECTION INPUT ;
    USE SIGNAL ;
    PORT
      LAYER M4 ;
        RECT  0 5.904 0.192 5.928 ;
    END
  END i_sel[7]
  PIN i_sel[80]
    DIRECTION INPUT ;
    USE SIGNAL ;
    PORT
      LAYER M4 ;
        RECT  0 19.008 0.192 19.032 ;
    END
  END i_sel[80]
  PIN i_sel[81]
    DIRECTION INPUT ;
    USE SIGNAL ;
    PORT
      LAYER M4 ;
        RECT  0 19.296 0.192 19.32 ;
    END
  END i_sel[81]
  PIN i_sel[82]
    DIRECTION INPUT ;
    USE SIGNAL ;
    PORT
      LAYER M4 ;
        RECT  0 19.44 0.192 19.464 ;
    END
  END i_sel[82]
  PIN i_sel[83]
    DIRECTION INPUT ;
    USE SIGNAL ;
    PORT
      LAYER M4 ;
        RECT  0 19.584 0.192 19.608 ;
    END
  END i_sel[83]
  PIN i_sel[84]
    DIRECTION INPUT ;
    USE SIGNAL ;
    PORT
      LAYER M4 ;
        RECT  0 19.728 0.192 19.752 ;
    END
  END i_sel[84]
  PIN i_sel[85]
    DIRECTION INPUT ;
    USE SIGNAL ;
    PORT
      LAYER M4 ;
        RECT  0 20.016 0.192 20.04 ;
    END
  END i_sel[85]
  PIN i_sel[86]
    DIRECTION INPUT ;
    USE SIGNAL ;
    PORT
      LAYER M4 ;
        RECT  0 20.16 0.192 20.184 ;
    END
  END i_sel[86]
  PIN i_sel[87]
    DIRECTION INPUT ;
    USE SIGNAL ;
    PORT
      LAYER M4 ;
        RECT  0 20.304 0.192 20.328 ;
    END
  END i_sel[87]
  PIN i_sel[88]
    DIRECTION INPUT ;
    USE SIGNAL ;
    PORT
      LAYER M4 ;
        RECT  0 20.448 0.192 20.472 ;
    END
  END i_sel[88]
  PIN i_sel[89]
    DIRECTION INPUT ;
    USE SIGNAL ;
    PORT
      LAYER M4 ;
        RECT  0 20.736 0.192 20.76 ;
    END
  END i_sel[89]
  PIN i_sel[8]
    DIRECTION INPUT ;
    USE SIGNAL ;
    PORT
      LAYER M4 ;
        RECT  0 6.192 0.192 6.216 ;
    END
  END i_sel[8]
  PIN i_sel[90]
    DIRECTION INPUT ;
    USE SIGNAL ;
    PORT
      LAYER M4 ;
        RECT  0 20.88 0.192 20.904 ;
    END
  END i_sel[90]
  PIN i_sel[91]
    DIRECTION INPUT ;
    USE SIGNAL ;
    PORT
      LAYER M4 ;
        RECT  0 21.024 0.192 21.048 ;
    END
  END i_sel[91]
  PIN i_sel[92]
    DIRECTION INPUT ;
    USE SIGNAL ;
    PORT
      LAYER M4 ;
        RECT  0 21.168 0.192 21.192 ;
    END
  END i_sel[92]
  PIN i_sel[93]
    DIRECTION INPUT ;
    USE SIGNAL ;
    PORT
      LAYER M4 ;
        RECT  0 21.456 0.192 21.48 ;
    END
  END i_sel[93]
  PIN i_sel[94]
    DIRECTION INPUT ;
    USE SIGNAL ;
    PORT
      LAYER M4 ;
        RECT  0 21.6 0.192 21.624 ;
    END
  END i_sel[94]
  PIN i_sel[95]
    DIRECTION INPUT ;
    USE SIGNAL ;
    PORT
      LAYER M4 ;
        RECT  0 21.744 0.192 21.768 ;
    END
  END i_sel[95]
  PIN i_sel[96]
    DIRECTION INPUT ;
    USE SIGNAL ;
    PORT
      LAYER M4 ;
        RECT  0 21.888 0.192 21.912 ;
    END
  END i_sel[96]
  PIN i_sel[97]
    DIRECTION INPUT ;
    USE SIGNAL ;
    PORT
      LAYER M4 ;
        RECT  0 22.176 0.192 22.2 ;
    END
  END i_sel[97]
  PIN i_sel[98]
    DIRECTION INPUT ;
    USE SIGNAL ;
    PORT
      LAYER M4 ;
        RECT  0 22.32 0.192 22.344 ;
    END
  END i_sel[98]
  PIN i_sel[99]
    DIRECTION INPUT ;
    USE SIGNAL ;
    PORT
      LAYER M4 ;
        RECT  0 22.464 0.192 22.488 ;
    END
  END i_sel[99]
  PIN i_sel[9]
    DIRECTION INPUT ;
    USE SIGNAL ;
    PORT
      LAYER M4 ;
        RECT  0 6.336 0.192 6.36 ;
    END
  END i_sel[9]
  PIN o_data[0]
    DIRECTION OUTPUT ;
    USE SIGNAL ;
    PORT
      LAYER M5 ;
        RECT  4.464 129.408 4.488 129.6 ;
    END
  END o_data[0]
  PIN o_data[100]
    DIRECTION OUTPUT ;
    USE SIGNAL ;
    PORT
      LAYER M5 ;
        RECT  52.944 129.408 52.968 129.6 ;
    END
  END o_data[100]
  PIN o_data[101]
    DIRECTION OUTPUT ;
    USE SIGNAL ;
    PORT
      LAYER M5 ;
        RECT  53.376 129.408 53.4 129.6 ;
    END
  END o_data[101]
  PIN o_data[102]
    DIRECTION OUTPUT ;
    USE SIGNAL ;
    PORT
      LAYER M5 ;
        RECT  53.808 129.408 53.832 129.6 ;
    END
  END o_data[102]
  PIN o_data[103]
    DIRECTION OUTPUT ;
    USE SIGNAL ;
    PORT
      LAYER M5 ;
        RECT  54.768 129.408 54.792 129.6 ;
    END
  END o_data[103]
  PIN o_data[104]
    DIRECTION OUTPUT ;
    USE SIGNAL ;
    PORT
      LAYER M5 ;
        RECT  55.2 129.408 55.224 129.6 ;
    END
  END o_data[104]
  PIN o_data[105]
    DIRECTION OUTPUT ;
    USE SIGNAL ;
    PORT
      LAYER M5 ;
        RECT  55.632 129.408 55.656 129.6 ;
    END
  END o_data[105]
  PIN o_data[106]
    DIRECTION OUTPUT ;
    USE SIGNAL ;
    PORT
      LAYER M5 ;
        RECT  56.064 129.408 56.088 129.6 ;
    END
  END o_data[106]
  PIN o_data[107]
    DIRECTION OUTPUT ;
    USE SIGNAL ;
    PORT
      LAYER M5 ;
        RECT  56.496 129.408 56.52 129.6 ;
    END
  END o_data[107]
  PIN o_data[108]
    DIRECTION OUTPUT ;
    USE SIGNAL ;
    PORT
      LAYER M5 ;
        RECT  56.928 129.408 56.952 129.6 ;
    END
  END o_data[108]
  PIN o_data[109]
    DIRECTION OUTPUT ;
    USE SIGNAL ;
    PORT
      LAYER M5 ;
        RECT  57.36 129.408 57.384 129.6 ;
    END
  END o_data[109]
  PIN o_data[10]
    DIRECTION OUTPUT ;
    USE SIGNAL ;
    PORT
      LAYER M5 ;
        RECT  9.456 129.408 9.48 129.6 ;
    END
  END o_data[10]
  PIN o_data[110]
    DIRECTION OUTPUT ;
    USE SIGNAL ;
    PORT
      LAYER M5 ;
        RECT  57.936 129.408 57.96 129.6 ;
    END
  END o_data[110]
  PIN o_data[111]
    DIRECTION OUTPUT ;
    USE SIGNAL ;
    PORT
      LAYER M5 ;
        RECT  58.368 129.408 58.392 129.6 ;
    END
  END o_data[111]
  PIN o_data[112]
    DIRECTION OUTPUT ;
    USE SIGNAL ;
    PORT
      LAYER M5 ;
        RECT  58.8 129.408 58.824 129.6 ;
    END
  END o_data[112]
  PIN o_data[113]
    DIRECTION OUTPUT ;
    USE SIGNAL ;
    PORT
      LAYER M5 ;
        RECT  59.232 129.408 59.256 129.6 ;
    END
  END o_data[113]
  PIN o_data[114]
    DIRECTION OUTPUT ;
    USE SIGNAL ;
    PORT
      LAYER M5 ;
        RECT  60.144 129.408 60.168 129.6 ;
    END
  END o_data[114]
  PIN o_data[115]
    DIRECTION OUTPUT ;
    USE SIGNAL ;
    PORT
      LAYER M5 ;
        RECT  60.576 129.408 60.6 129.6 ;
    END
  END o_data[115]
  PIN o_data[116]
    DIRECTION OUTPUT ;
    USE SIGNAL ;
    PORT
      LAYER M5 ;
        RECT  61.008 129.408 61.032 129.6 ;
    END
  END o_data[116]
  PIN o_data[117]
    DIRECTION OUTPUT ;
    USE SIGNAL ;
    PORT
      LAYER M5 ;
        RECT  61.44 129.408 61.464 129.6 ;
    END
  END o_data[117]
  PIN o_data[118]
    DIRECTION OUTPUT ;
    USE SIGNAL ;
    PORT
      LAYER M5 ;
        RECT  61.872 129.408 61.896 129.6 ;
    END
  END o_data[118]
  PIN o_data[119]
    DIRECTION OUTPUT ;
    USE SIGNAL ;
    PORT
      LAYER M5 ;
        RECT  62.304 129.408 62.328 129.6 ;
    END
  END o_data[119]
  PIN o_data[11]
    DIRECTION OUTPUT ;
    USE SIGNAL ;
    PORT
      LAYER M5 ;
        RECT  9.888 129.408 9.912 129.6 ;
    END
  END o_data[11]
  PIN o_data[120]
    DIRECTION OUTPUT ;
    USE SIGNAL ;
    PORT
      LAYER M5 ;
        RECT  62.736 129.408 62.76 129.6 ;
    END
  END o_data[120]
  PIN o_data[121]
    DIRECTION OUTPUT ;
    USE SIGNAL ;
    PORT
      LAYER M5 ;
        RECT  63.168 129.408 63.192 129.6 ;
    END
  END o_data[121]
  PIN o_data[122]
    DIRECTION OUTPUT ;
    USE SIGNAL ;
    PORT
      LAYER M5 ;
        RECT  63.6 129.408 63.624 129.6 ;
    END
  END o_data[122]
  PIN o_data[123]
    DIRECTION OUTPUT ;
    USE SIGNAL ;
    PORT
      LAYER M5 ;
        RECT  64.032 129.408 64.056 129.6 ;
    END
  END o_data[123]
  PIN o_data[124]
    DIRECTION OUTPUT ;
    USE SIGNAL ;
    PORT
      LAYER M5 ;
        RECT  64.464 129.408 64.488 129.6 ;
    END
  END o_data[124]
  PIN o_data[125]
    DIRECTION OUTPUT ;
    USE SIGNAL ;
    PORT
      LAYER M5 ;
        RECT  64.896 129.408 64.92 129.6 ;
    END
  END o_data[125]
  PIN o_data[126]
    DIRECTION OUTPUT ;
    USE SIGNAL ;
    PORT
      LAYER M5 ;
        RECT  65.856 129.408 65.88 129.6 ;
    END
  END o_data[126]
  PIN o_data[127]
    DIRECTION OUTPUT ;
    USE SIGNAL ;
    PORT
      LAYER M5 ;
        RECT  66.288 129.408 66.312 129.6 ;
    END
  END o_data[127]
  PIN o_data[12]
    DIRECTION OUTPUT ;
    USE SIGNAL ;
    PORT
      LAYER M5 ;
        RECT  10.32 129.408 10.344 129.6 ;
    END
  END o_data[12]
  PIN o_data[13]
    DIRECTION OUTPUT ;
    USE SIGNAL ;
    PORT
      LAYER M5 ;
        RECT  10.752 129.408 10.776 129.6 ;
    END
  END o_data[13]
  PIN o_data[14]
    DIRECTION OUTPUT ;
    USE SIGNAL ;
    PORT
      LAYER M5 ;
        RECT  11.712 129.408 11.736 129.6 ;
    END
  END o_data[14]
  PIN o_data[15]
    DIRECTION OUTPUT ;
    USE SIGNAL ;
    PORT
      LAYER M5 ;
        RECT  12.144 129.408 12.168 129.6 ;
    END
  END o_data[15]
  PIN o_data[16]
    DIRECTION OUTPUT ;
    USE SIGNAL ;
    PORT
      LAYER M5 ;
        RECT  12.576 129.408 12.6 129.6 ;
    END
  END o_data[16]
  PIN o_data[17]
    DIRECTION OUTPUT ;
    USE SIGNAL ;
    PORT
      LAYER M5 ;
        RECT  13.008 129.408 13.032 129.6 ;
    END
  END o_data[17]
  PIN o_data[18]
    DIRECTION OUTPUT ;
    USE SIGNAL ;
    PORT
      LAYER M5 ;
        RECT  13.44 129.408 13.464 129.6 ;
    END
  END o_data[18]
  PIN o_data[19]
    DIRECTION OUTPUT ;
    USE SIGNAL ;
    PORT
      LAYER M5 ;
        RECT  13.872 129.408 13.896 129.6 ;
    END
  END o_data[19]
  PIN o_data[1]
    DIRECTION OUTPUT ;
    USE SIGNAL ;
    PORT
      LAYER M5 ;
        RECT  4.896 129.408 4.92 129.6 ;
    END
  END o_data[1]
  PIN o_data[20]
    DIRECTION OUTPUT ;
    USE SIGNAL ;
    PORT
      LAYER M5 ;
        RECT  14.304 129.408 14.328 129.6 ;
    END
  END o_data[20]
  PIN o_data[21]
    DIRECTION OUTPUT ;
    USE SIGNAL ;
    PORT
      LAYER M5 ;
        RECT  14.736 129.408 14.76 129.6 ;
    END
  END o_data[21]
  PIN o_data[22]
    DIRECTION OUTPUT ;
    USE SIGNAL ;
    PORT
      LAYER M5 ;
        RECT  15.168 129.408 15.192 129.6 ;
    END
  END o_data[22]
  PIN o_data[23]
    DIRECTION OUTPUT ;
    USE SIGNAL ;
    PORT
      LAYER M5 ;
        RECT  15.6 129.408 15.624 129.6 ;
    END
  END o_data[23]
  PIN o_data[24]
    DIRECTION OUTPUT ;
    USE SIGNAL ;
    PORT
      LAYER M5 ;
        RECT  16.032 129.408 16.056 129.6 ;
    END
  END o_data[24]
  PIN o_data[25]
    DIRECTION OUTPUT ;
    USE SIGNAL ;
    PORT
      LAYER M5 ;
        RECT  16.944 129.408 16.968 129.6 ;
    END
  END o_data[25]
  PIN o_data[26]
    DIRECTION OUTPUT ;
    USE SIGNAL ;
    PORT
      LAYER M5 ;
        RECT  17.376 129.408 17.4 129.6 ;
    END
  END o_data[26]
  PIN o_data[27]
    DIRECTION OUTPUT ;
    USE SIGNAL ;
    PORT
      LAYER M5 ;
        RECT  17.808 129.408 17.832 129.6 ;
    END
  END o_data[27]
  PIN o_data[28]
    DIRECTION OUTPUT ;
    USE SIGNAL ;
    PORT
      LAYER M5 ;
        RECT  18.24 129.408 18.264 129.6 ;
    END
  END o_data[28]
  PIN o_data[29]
    DIRECTION OUTPUT ;
    USE SIGNAL ;
    PORT
      LAYER M5 ;
        RECT  18.672 129.408 18.696 129.6 ;
    END
  END o_data[29]
  PIN o_data[2]
    DIRECTION OUTPUT ;
    USE SIGNAL ;
    PORT
      LAYER M5 ;
        RECT  5.328 129.408 5.352 129.6 ;
    END
  END o_data[2]
  PIN o_data[30]
    DIRECTION OUTPUT ;
    USE SIGNAL ;
    PORT
      LAYER M5 ;
        RECT  19.248 129.408 19.272 129.6 ;
    END
  END o_data[30]
  PIN o_data[31]
    DIRECTION OUTPUT ;
    USE SIGNAL ;
    PORT
      LAYER M5 ;
        RECT  19.68 129.408 19.704 129.6 ;
    END
  END o_data[31]
  PIN o_data[32]
    DIRECTION OUTPUT ;
    USE SIGNAL ;
    PORT
      LAYER M5 ;
        RECT  20.112 129.408 20.136 129.6 ;
    END
  END o_data[32]
  PIN o_data[33]
    DIRECTION OUTPUT ;
    USE SIGNAL ;
    PORT
      LAYER M5 ;
        RECT  20.544 129.408 20.568 129.6 ;
    END
  END o_data[33]
  PIN o_data[34]
    DIRECTION OUTPUT ;
    USE SIGNAL ;
    PORT
      LAYER M5 ;
        RECT  20.976 129.408 21 129.6 ;
    END
  END o_data[34]
  PIN o_data[35]
    DIRECTION OUTPUT ;
    USE SIGNAL ;
    PORT
      LAYER M5 ;
        RECT  21.408 129.408 21.432 129.6 ;
    END
  END o_data[35]
  PIN o_data[36]
    DIRECTION OUTPUT ;
    USE SIGNAL ;
    PORT
      LAYER M5 ;
        RECT  22.368 129.408 22.392 129.6 ;
    END
  END o_data[36]
  PIN o_data[37]
    DIRECTION OUTPUT ;
    USE SIGNAL ;
    PORT
      LAYER M5 ;
        RECT  22.8 129.408 22.824 129.6 ;
    END
  END o_data[37]
  PIN o_data[38]
    DIRECTION OUTPUT ;
    USE SIGNAL ;
    PORT
      LAYER M5 ;
        RECT  23.232 129.408 23.256 129.6 ;
    END
  END o_data[38]
  PIN o_data[39]
    DIRECTION OUTPUT ;
    USE SIGNAL ;
    PORT
      LAYER M5 ;
        RECT  23.664 129.408 23.688 129.6 ;
    END
  END o_data[39]
  PIN o_data[3]
    DIRECTION OUTPUT ;
    USE SIGNAL ;
    PORT
      LAYER M5 ;
        RECT  6.288 129.408 6.312 129.6 ;
    END
  END o_data[3]
  PIN o_data[40]
    DIRECTION OUTPUT ;
    USE SIGNAL ;
    PORT
      LAYER M5 ;
        RECT  24.096 129.408 24.12 129.6 ;
    END
  END o_data[40]
  PIN o_data[41]
    DIRECTION OUTPUT ;
    USE SIGNAL ;
    PORT
      LAYER M5 ;
        RECT  24.528 129.408 24.552 129.6 ;
    END
  END o_data[41]
  PIN o_data[42]
    DIRECTION OUTPUT ;
    USE SIGNAL ;
    PORT
      LAYER M5 ;
        RECT  24.96 129.408 24.984 129.6 ;
    END
  END o_data[42]
  PIN o_data[43]
    DIRECTION OUTPUT ;
    USE SIGNAL ;
    PORT
      LAYER M5 ;
        RECT  25.392 129.408 25.416 129.6 ;
    END
  END o_data[43]
  PIN o_data[44]
    DIRECTION OUTPUT ;
    USE SIGNAL ;
    PORT
      LAYER M5 ;
        RECT  25.824 129.408 25.848 129.6 ;
    END
  END o_data[44]
  PIN o_data[45]
    DIRECTION OUTPUT ;
    USE SIGNAL ;
    PORT
      LAYER M5 ;
        RECT  26.256 129.408 26.28 129.6 ;
    END
  END o_data[45]
  PIN o_data[46]
    DIRECTION OUTPUT ;
    USE SIGNAL ;
    PORT
      LAYER M5 ;
        RECT  26.688 129.408 26.712 129.6 ;
    END
  END o_data[46]
  PIN o_data[47]
    DIRECTION OUTPUT ;
    USE SIGNAL ;
    PORT
      LAYER M5 ;
        RECT  27.12 129.408 27.144 129.6 ;
    END
  END o_data[47]
  PIN o_data[48]
    DIRECTION OUTPUT ;
    USE SIGNAL ;
    PORT
      LAYER M5 ;
        RECT  28.032 129.408 28.056 129.6 ;
    END
  END o_data[48]
  PIN o_data[49]
    DIRECTION OUTPUT ;
    USE SIGNAL ;
    PORT
      LAYER M5 ;
        RECT  28.464 129.408 28.488 129.6 ;
    END
  END o_data[49]
  PIN o_data[4]
    DIRECTION OUTPUT ;
    USE SIGNAL ;
    PORT
      LAYER M5 ;
        RECT  6.72 129.408 6.744 129.6 ;
    END
  END o_data[4]
  PIN o_data[50]
    DIRECTION OUTPUT ;
    USE SIGNAL ;
    PORT
      LAYER M5 ;
        RECT  29.04 129.408 29.064 129.6 ;
    END
  END o_data[50]
  PIN o_data[51]
    DIRECTION OUTPUT ;
    USE SIGNAL ;
    PORT
      LAYER M5 ;
        RECT  29.472 129.408 29.496 129.6 ;
    END
  END o_data[51]
  PIN o_data[52]
    DIRECTION OUTPUT ;
    USE SIGNAL ;
    PORT
      LAYER M5 ;
        RECT  29.904 129.408 29.928 129.6 ;
    END
  END o_data[52]
  PIN o_data[53]
    DIRECTION OUTPUT ;
    USE SIGNAL ;
    PORT
      LAYER M5 ;
        RECT  30.336 129.408 30.36 129.6 ;
    END
  END o_data[53]
  PIN o_data[54]
    DIRECTION OUTPUT ;
    USE SIGNAL ;
    PORT
      LAYER M5 ;
        RECT  30.768 129.408 30.792 129.6 ;
    END
  END o_data[54]
  PIN o_data[55]
    DIRECTION OUTPUT ;
    USE SIGNAL ;
    PORT
      LAYER M5 ;
        RECT  31.2 129.408 31.224 129.6 ;
    END
  END o_data[55]
  PIN o_data[56]
    DIRECTION OUTPUT ;
    USE SIGNAL ;
    PORT
      LAYER M5 ;
        RECT  31.632 129.408 31.656 129.6 ;
    END
  END o_data[56]
  PIN o_data[57]
    DIRECTION OUTPUT ;
    USE SIGNAL ;
    PORT
      LAYER M5 ;
        RECT  32.064 129.408 32.088 129.6 ;
    END
  END o_data[57]
  PIN o_data[58]
    DIRECTION OUTPUT ;
    USE SIGNAL ;
    PORT
      LAYER M5 ;
        RECT  32.496 129.408 32.52 129.6 ;
    END
  END o_data[58]
  PIN o_data[59]
    DIRECTION OUTPUT ;
    USE SIGNAL ;
    PORT
      LAYER M5 ;
        RECT  33.456 129.408 33.48 129.6 ;
    END
  END o_data[59]
  PIN o_data[5]
    DIRECTION OUTPUT ;
    USE SIGNAL ;
    PORT
      LAYER M5 ;
        RECT  7.152 129.408 7.176 129.6 ;
    END
  END o_data[5]
  PIN o_data[60]
    DIRECTION OUTPUT ;
    USE SIGNAL ;
    PORT
      LAYER M5 ;
        RECT  33.888 129.408 33.912 129.6 ;
    END
  END o_data[60]
  PIN o_data[61]
    DIRECTION OUTPUT ;
    USE SIGNAL ;
    PORT
      LAYER M5 ;
        RECT  34.32 129.408 34.344 129.6 ;
    END
  END o_data[61]
  PIN o_data[62]
    DIRECTION OUTPUT ;
    USE SIGNAL ;
    PORT
      LAYER M5 ;
        RECT  34.752 129.408 34.776 129.6 ;
    END
  END o_data[62]
  PIN o_data[63]
    DIRECTION OUTPUT ;
    USE SIGNAL ;
    PORT
      LAYER M5 ;
        RECT  35.184 129.408 35.208 129.6 ;
    END
  END o_data[63]
  PIN o_data[64]
    DIRECTION OUTPUT ;
    USE SIGNAL ;
    PORT
      LAYER M5 ;
        RECT  35.616 129.408 35.64 129.6 ;
    END
  END o_data[64]
  PIN o_data[65]
    DIRECTION OUTPUT ;
    USE SIGNAL ;
    PORT
      LAYER M5 ;
        RECT  36.048 129.408 36.072 129.6 ;
    END
  END o_data[65]
  PIN o_data[66]
    DIRECTION OUTPUT ;
    USE SIGNAL ;
    PORT
      LAYER M5 ;
        RECT  36.48 129.408 36.504 129.6 ;
    END
  END o_data[66]
  PIN o_data[67]
    DIRECTION OUTPUT ;
    USE SIGNAL ;
    PORT
      LAYER M5 ;
        RECT  36.912 129.408 36.936 129.6 ;
    END
  END o_data[67]
  PIN o_data[68]
    DIRECTION OUTPUT ;
    USE SIGNAL ;
    PORT
      LAYER M5 ;
        RECT  37.344 129.408 37.368 129.6 ;
    END
  END o_data[68]
  PIN o_data[69]
    DIRECTION OUTPUT ;
    USE SIGNAL ;
    PORT
      LAYER M5 ;
        RECT  37.776 129.408 37.8 129.6 ;
    END
  END o_data[69]
  PIN o_data[6]
    DIRECTION OUTPUT ;
    USE SIGNAL ;
    PORT
      LAYER M5 ;
        RECT  7.584 129.408 7.608 129.6 ;
    END
  END o_data[6]
  PIN o_data[70]
    DIRECTION OUTPUT ;
    USE SIGNAL ;
    PORT
      LAYER M5 ;
        RECT  38.832 129.408 38.856 129.6 ;
    END
  END o_data[70]
  PIN o_data[71]
    DIRECTION OUTPUT ;
    USE SIGNAL ;
    PORT
      LAYER M5 ;
        RECT  39.264 129.408 39.288 129.6 ;
    END
  END o_data[71]
  PIN o_data[72]
    DIRECTION OUTPUT ;
    USE SIGNAL ;
    PORT
      LAYER M5 ;
        RECT  39.696 129.408 39.72 129.6 ;
    END
  END o_data[72]
  PIN o_data[73]
    DIRECTION OUTPUT ;
    USE SIGNAL ;
    PORT
      LAYER M5 ;
        RECT  40.128 129.408 40.152 129.6 ;
    END
  END o_data[73]
  PIN o_data[74]
    DIRECTION OUTPUT ;
    USE SIGNAL ;
    PORT
      LAYER M5 ;
        RECT  40.56 129.408 40.584 129.6 ;
    END
  END o_data[74]
  PIN o_data[75]
    DIRECTION OUTPUT ;
    USE SIGNAL ;
    PORT
      LAYER M5 ;
        RECT  40.992 129.408 41.016 129.6 ;
    END
  END o_data[75]
  PIN o_data[76]
    DIRECTION OUTPUT ;
    USE SIGNAL ;
    PORT
      LAYER M5 ;
        RECT  41.424 129.408 41.448 129.6 ;
    END
  END o_data[76]
  PIN o_data[77]
    DIRECTION OUTPUT ;
    USE SIGNAL ;
    PORT
      LAYER M5 ;
        RECT  41.856 129.408 41.88 129.6 ;
    END
  END o_data[77]
  PIN o_data[78]
    DIRECTION OUTPUT ;
    USE SIGNAL ;
    PORT
      LAYER M5 ;
        RECT  42.288 129.408 42.312 129.6 ;
    END
  END o_data[78]
  PIN o_data[79]
    DIRECTION OUTPUT ;
    USE SIGNAL ;
    PORT
      LAYER M5 ;
        RECT  42.72 129.408 42.744 129.6 ;
    END
  END o_data[79]
  PIN o_data[7]
    DIRECTION OUTPUT ;
    USE SIGNAL ;
    PORT
      LAYER M5 ;
        RECT  8.016 129.408 8.04 129.6 ;
    END
  END o_data[7]
  PIN o_data[80]
    DIRECTION OUTPUT ;
    USE SIGNAL ;
    PORT
      LAYER M5 ;
        RECT  43.152 129.408 43.176 129.6 ;
    END
  END o_data[80]
  PIN o_data[81]
    DIRECTION OUTPUT ;
    USE SIGNAL ;
    PORT
      LAYER M5 ;
        RECT  44.112 129.408 44.136 129.6 ;
    END
  END o_data[81]
  PIN o_data[82]
    DIRECTION OUTPUT ;
    USE SIGNAL ;
    PORT
      LAYER M5 ;
        RECT  44.544 129.408 44.568 129.6 ;
    END
  END o_data[82]
  PIN o_data[83]
    DIRECTION OUTPUT ;
    USE SIGNAL ;
    PORT
      LAYER M5 ;
        RECT  44.976 129.408 45 129.6 ;
    END
  END o_data[83]
  PIN o_data[84]
    DIRECTION OUTPUT ;
    USE SIGNAL ;
    PORT
      LAYER M5 ;
        RECT  45.408 129.408 45.432 129.6 ;
    END
  END o_data[84]
  PIN o_data[85]
    DIRECTION OUTPUT ;
    USE SIGNAL ;
    PORT
      LAYER M5 ;
        RECT  45.84 129.408 45.864 129.6 ;
    END
  END o_data[85]
  PIN o_data[86]
    DIRECTION OUTPUT ;
    USE SIGNAL ;
    PORT
      LAYER M5 ;
        RECT  46.272 129.408 46.296 129.6 ;
    END
  END o_data[86]
  PIN o_data[87]
    DIRECTION OUTPUT ;
    USE SIGNAL ;
    PORT
      LAYER M5 ;
        RECT  46.704 129.408 46.728 129.6 ;
    END
  END o_data[87]
  PIN o_data[88]
    DIRECTION OUTPUT ;
    USE SIGNAL ;
    PORT
      LAYER M5 ;
        RECT  47.136 129.408 47.16 129.6 ;
    END
  END o_data[88]
  PIN o_data[89]
    DIRECTION OUTPUT ;
    USE SIGNAL ;
    PORT
      LAYER M5 ;
        RECT  47.568 129.408 47.592 129.6 ;
    END
  END o_data[89]
  PIN o_data[8]
    DIRECTION OUTPUT ;
    USE SIGNAL ;
    PORT
      LAYER M5 ;
        RECT  8.448 129.408 8.472 129.6 ;
    END
  END o_data[8]
  PIN o_data[90]
    DIRECTION OUTPUT ;
    USE SIGNAL ;
    PORT
      LAYER M5 ;
        RECT  48.144 129.408 48.168 129.6 ;
    END
  END o_data[90]
  PIN o_data[91]
    DIRECTION OUTPUT ;
    USE SIGNAL ;
    PORT
      LAYER M5 ;
        RECT  48.576 129.408 48.6 129.6 ;
    END
  END o_data[91]
  PIN o_data[92]
    DIRECTION OUTPUT ;
    USE SIGNAL ;
    PORT
      LAYER M5 ;
        RECT  49.488 129.408 49.512 129.6 ;
    END
  END o_data[92]
  PIN o_data[93]
    DIRECTION OUTPUT ;
    USE SIGNAL ;
    PORT
      LAYER M5 ;
        RECT  49.92 129.408 49.944 129.6 ;
    END
  END o_data[93]
  PIN o_data[94]
    DIRECTION OUTPUT ;
    USE SIGNAL ;
    PORT
      LAYER M5 ;
        RECT  50.352 129.408 50.376 129.6 ;
    END
  END o_data[94]
  PIN o_data[95]
    DIRECTION OUTPUT ;
    USE SIGNAL ;
    PORT
      LAYER M5 ;
        RECT  50.784 129.408 50.808 129.6 ;
    END
  END o_data[95]
  PIN o_data[96]
    DIRECTION OUTPUT ;
    USE SIGNAL ;
    PORT
      LAYER M5 ;
        RECT  51.216 129.408 51.24 129.6 ;
    END
  END o_data[96]
  PIN o_data[97]
    DIRECTION OUTPUT ;
    USE SIGNAL ;
    PORT
      LAYER M5 ;
        RECT  51.648 129.408 51.672 129.6 ;
    END
  END o_data[97]
  PIN o_data[98]
    DIRECTION OUTPUT ;
    USE SIGNAL ;
    PORT
      LAYER M5 ;
        RECT  52.08 129.408 52.104 129.6 ;
    END
  END o_data[98]
  PIN o_data[99]
    DIRECTION OUTPUT ;
    USE SIGNAL ;
    PORT
      LAYER M5 ;
        RECT  52.512 129.408 52.536 129.6 ;
    END
  END o_data[99]
  PIN o_data[9]
    DIRECTION OUTPUT ;
    USE SIGNAL ;
    PORT
      LAYER M5 ;
        RECT  8.88 129.408 8.904 129.6 ;
    END
  END o_data[9]
  PIN o_v[0]
    DIRECTION OUTPUT ;
    USE SIGNAL ;
    PORT
      LAYER M5 ;
        RECT  66.72 129.408 66.744 129.6 ;
    END
  END o_v[0]
  PIN o_v[10]
    DIRECTION OUTPUT ;
    USE SIGNAL ;
    PORT
      LAYER M5 ;
        RECT  71.664 129.408 71.688 129.6 ;
    END
  END o_v[10]
  PIN o_v[11]
    DIRECTION OUTPUT ;
    USE SIGNAL ;
    PORT
      LAYER M5 ;
        RECT  72.096 129.408 72.12 129.6 ;
    END
  END o_v[11]
  PIN o_v[12]
    DIRECTION OUTPUT ;
    USE SIGNAL ;
    PORT
      LAYER M5 ;
        RECT  72.528 129.408 72.552 129.6 ;
    END
  END o_v[12]
  PIN o_v[13]
    DIRECTION OUTPUT ;
    USE SIGNAL ;
    PORT
      LAYER M5 ;
        RECT  72.96 129.408 72.984 129.6 ;
    END
  END o_v[13]
  PIN o_v[14]
    DIRECTION OUTPUT ;
    USE SIGNAL ;
    PORT
      LAYER M5 ;
        RECT  73.392 129.408 73.416 129.6 ;
    END
  END o_v[14]
  PIN o_v[15]
    DIRECTION OUTPUT ;
    USE SIGNAL ;
    PORT
      LAYER M5 ;
        RECT  73.824 129.408 73.848 129.6 ;
    END
  END o_v[15]
  PIN o_v[16]
    DIRECTION OUTPUT ;
    USE SIGNAL ;
    PORT
      LAYER M5 ;
        RECT  74.256 129.408 74.28 129.6 ;
    END
  END o_v[16]
  PIN o_v[17]
    DIRECTION OUTPUT ;
    USE SIGNAL ;
    PORT
      LAYER M5 ;
        RECT  74.688 129.408 74.712 129.6 ;
    END
  END o_v[17]
  PIN o_v[18]
    DIRECTION OUTPUT ;
    USE SIGNAL ;
    PORT
      LAYER M5 ;
        RECT  75.12 129.408 75.144 129.6 ;
    END
  END o_v[18]
  PIN o_v[19]
    DIRECTION OUTPUT ;
    USE SIGNAL ;
    PORT
      LAYER M5 ;
        RECT  75.552 129.408 75.576 129.6 ;
    END
  END o_v[19]
  PIN o_v[1]
    DIRECTION OUTPUT ;
    USE SIGNAL ;
    PORT
      LAYER M5 ;
        RECT  67.152 129.408 67.176 129.6 ;
    END
  END o_v[1]
  PIN o_v[20]
    DIRECTION OUTPUT ;
    USE SIGNAL ;
    PORT
      LAYER M5 ;
        RECT  76.512 129.408 76.536 129.6 ;
    END
  END o_v[20]
  PIN o_v[21]
    DIRECTION OUTPUT ;
    USE SIGNAL ;
    PORT
      LAYER M5 ;
        RECT  76.944 129.408 76.968 129.6 ;
    END
  END o_v[21]
  PIN o_v[22]
    DIRECTION OUTPUT ;
    USE SIGNAL ;
    PORT
      LAYER M5 ;
        RECT  77.52 129.408 77.544 129.6 ;
    END
  END o_v[22]
  PIN o_v[23]
    DIRECTION OUTPUT ;
    USE SIGNAL ;
    PORT
      LAYER M5 ;
        RECT  77.952 129.408 77.976 129.6 ;
    END
  END o_v[23]
  PIN o_v[24]
    DIRECTION OUTPUT ;
    USE SIGNAL ;
    PORT
      LAYER M5 ;
        RECT  78.384 129.408 78.408 129.6 ;
    END
  END o_v[24]
  PIN o_v[25]
    DIRECTION OUTPUT ;
    USE SIGNAL ;
    PORT
      LAYER M5 ;
        RECT  78.816 129.408 78.84 129.6 ;
    END
  END o_v[25]
  PIN o_v[26]
    DIRECTION OUTPUT ;
    USE SIGNAL ;
    PORT
      LAYER M5 ;
        RECT  79.248 129.408 79.272 129.6 ;
    END
  END o_v[26]
  PIN o_v[27]
    DIRECTION OUTPUT ;
    USE SIGNAL ;
    PORT
      LAYER M5 ;
        RECT  79.68 129.408 79.704 129.6 ;
    END
  END o_v[27]
  PIN o_v[28]
    DIRECTION OUTPUT ;
    USE SIGNAL ;
    PORT
      LAYER M5 ;
        RECT  80.112 129.408 80.136 129.6 ;
    END
  END o_v[28]
  PIN o_v[29]
    DIRECTION OUTPUT ;
    USE SIGNAL ;
    PORT
      LAYER M5 ;
        RECT  80.544 129.408 80.568 129.6 ;
    END
  END o_v[29]
  PIN o_v[2]
    DIRECTION OUTPUT ;
    USE SIGNAL ;
    PORT
      LAYER M5 ;
        RECT  67.728 129.408 67.752 129.6 ;
    END
  END o_v[2]
  PIN o_v[30]
    DIRECTION OUTPUT ;
    USE SIGNAL ;
    PORT
      LAYER M5 ;
        RECT  80.976 129.408 81 129.6 ;
    END
  END o_v[30]
  PIN o_v[31]
    DIRECTION OUTPUT ;
    USE SIGNAL ;
    PORT
      LAYER M5 ;
        RECT  81.888 129.408 81.912 129.6 ;
    END
  END o_v[31]
  PIN o_v[3]
    DIRECTION OUTPUT ;
    USE SIGNAL ;
    PORT
      LAYER M5 ;
        RECT  68.16 129.408 68.184 129.6 ;
    END
  END o_v[3]
  PIN o_v[4]
    DIRECTION OUTPUT ;
    USE SIGNAL ;
    PORT
      LAYER M5 ;
        RECT  68.592 129.408 68.616 129.6 ;
    END
  END o_v[4]
  PIN o_v[5]
    DIRECTION OUTPUT ;
    USE SIGNAL ;
    PORT
      LAYER M5 ;
        RECT  69.024 129.408 69.048 129.6 ;
    END
  END o_v[5]
  PIN o_v[6]
    DIRECTION OUTPUT ;
    USE SIGNAL ;
    PORT
      LAYER M5 ;
        RECT  69.456 129.408 69.48 129.6 ;
    END
  END o_v[6]
  PIN o_v[7]
    DIRECTION OUTPUT ;
    USE SIGNAL ;
    PORT
      LAYER M5 ;
        RECT  69.888 129.408 69.912 129.6 ;
    END
  END o_v[7]
  PIN o_v[8]
    DIRECTION OUTPUT ;
    USE SIGNAL ;
    PORT
      LAYER M5 ;
        RECT  70.32 129.408 70.344 129.6 ;
    END
  END o_v[8]
  PIN o_v[9]
    DIRECTION OUTPUT ;
    USE SIGNAL ;
    PORT
      LAYER M5 ;
        RECT  71.232 129.408 71.256 129.6 ;
    END
  END o_v[9]
  PIN rst_n
    DIRECTION INPUT ;
    USE SIGNAL ;
    PORT
      LAYER M4 ;
        RECT  0 4.464 0.192 4.488 ;
    END
  END rst_n
  PIN VDD
    DIRECTION INOUT ;
    USE POWER ;
    PORT
      LAYER M5 ;
        RECT  83.592 2.151 83.712 127.449 ;
        RECT  78.192 2.151 78.312 127.449 ;
        RECT  72.792 2.151 72.912 127.449 ;
        RECT  67.392 2.151 67.512 127.449 ;
        RECT  61.992 2.151 62.112 127.449 ;
        RECT  56.592 2.151 56.712 127.449 ;
        RECT  51.192 2.151 51.312 127.449 ;
        RECT  45.792 2.151 45.912 127.449 ;
        RECT  40.392 2.151 40.512 127.449 ;
        RECT  34.992 2.151 35.112 127.449 ;
        RECT  29.592 2.151 29.712 127.449 ;
        RECT  24.192 2.151 24.312 127.449 ;
        RECT  18.792 2.151 18.912 127.449 ;
        RECT  13.392 2.151 13.512 127.449 ;
        RECT  7.992 2.151 8.112 127.449 ;
        RECT  2.592 2.151 2.712 127.449 ;
    END
  END VDD
  PIN VSS
    DIRECTION INOUT ;
    USE GROUND ;
    PORT
      LAYER M5 ;
        RECT  83.4 2.137 83.52 127.463 ;
        RECT  78 2.137 78.12 127.463 ;
        RECT  72.6 2.137 72.72 127.463 ;
        RECT  67.2 2.137 67.32 127.463 ;
        RECT  61.8 2.137 61.92 127.463 ;
        RECT  56.4 2.137 56.52 127.463 ;
        RECT  51 2.137 51.12 127.463 ;
        RECT  45.6 2.137 45.72 127.463 ;
        RECT  40.2 2.137 40.32 127.463 ;
        RECT  34.8 2.137 34.92 127.463 ;
        RECT  29.4 2.137 29.52 127.463 ;
        RECT  24 2.137 24.12 127.463 ;
        RECT  18.6 2.137 18.72 127.463 ;
        RECT  13.2 2.137 13.32 127.463 ;
        RECT  7.8 2.137 7.92 127.463 ;
        RECT  2.4 2.137 2.52 127.463 ;
    END
  END VSS
  OBS
    LAYER RVTN ;
     RECT  2.16 2.16 84.24 2.295 ;
     RECT  2.16 2.565 84.24 2.835 ;
     RECT  2.16 3.105 84.24 3.375 ;
     RECT  2.16 3.645 84.24 3.915 ;
     RECT  2.16 4.185 84.24 4.455 ;
     RECT  2.16 4.725 84.24 4.995 ;
     RECT  2.16 5.265 84.24 5.535 ;
     RECT  2.16 5.805 84.24 6.075 ;
     RECT  2.16 6.345 84.24 6.615 ;
     RECT  2.16 6.885 84.24 7.155 ;
     RECT  2.16 7.425 84.24 7.695 ;
     RECT  2.16 7.965 84.24 8.235 ;
     RECT  2.16 8.505 84.24 8.775 ;
     RECT  2.16 9.045 84.24 9.315 ;
     RECT  2.16 9.585 84.24 9.855 ;
     RECT  2.16 10.125 84.24 10.395 ;
     RECT  2.16 10.665 84.24 10.935 ;
     RECT  2.16 11.205 84.24 11.475 ;
     RECT  2.16 11.745 84.24 12.015 ;
     RECT  2.16 12.285 84.24 12.555 ;
     RECT  2.16 12.825 84.24 13.095 ;
     RECT  2.16 13.365 84.24 13.635 ;
     RECT  2.16 13.905 84.24 14.175 ;
     RECT  2.16 14.445 84.24 14.715 ;
     RECT  2.16 14.985 84.24 15.255 ;
     RECT  2.16 15.525 84.24 15.795 ;
     RECT  2.16 16.065 84.24 16.335 ;
     RECT  2.16 16.605 84.24 16.875 ;
     RECT  2.16 17.145 84.24 17.415 ;
     RECT  2.16 17.685 84.24 17.955 ;
     RECT  2.16 18.225 84.24 18.495 ;
     RECT  2.16 18.765 84.24 19.035 ;
     RECT  2.16 19.305 84.24 19.575 ;
     RECT  2.16 19.845 84.24 20.115 ;
     RECT  2.16 20.385 84.24 20.655 ;
     RECT  2.16 20.925 84.24 21.195 ;
     RECT  2.16 21.465 84.24 21.735 ;
     RECT  2.16 22.005 84.24 22.275 ;
     RECT  2.16 22.545 84.24 22.815 ;
     RECT  2.16 23.085 84.24 23.355 ;
     RECT  2.16 23.625 84.24 23.895 ;
     RECT  2.16 24.165 84.24 24.435 ;
     RECT  2.16 24.705 84.24 24.975 ;
     RECT  2.16 25.245 84.24 25.515 ;
     RECT  2.16 25.785 84.24 26.055 ;
     RECT  2.16 26.325 84.24 26.595 ;
     RECT  2.16 26.865 84.24 27.135 ;
     RECT  2.16 27.405 84.24 27.675 ;
     RECT  2.16 27.945 84.24 28.215 ;
     RECT  2.16 28.485 84.24 28.755 ;
     RECT  2.16 29.025 84.24 29.295 ;
     RECT  2.16 29.565 84.24 29.835 ;
     RECT  2.16 30.105 84.24 30.375 ;
     RECT  2.16 30.645 84.24 30.915 ;
     RECT  2.16 31.185 84.24 31.455 ;
     RECT  2.16 31.725 84.24 31.995 ;
     RECT  2.16 32.265 84.24 32.535 ;
     RECT  2.16 32.805 84.24 33.075 ;
     RECT  2.16 33.345 84.24 33.615 ;
     RECT  2.16 33.885 84.24 34.155 ;
     RECT  2.16 34.425 84.24 34.695 ;
     RECT  2.16 34.965 84.24 35.235 ;
     RECT  2.16 35.505 84.24 35.775 ;
     RECT  2.16 36.045 84.24 36.315 ;
     RECT  2.16 36.585 84.24 36.855 ;
     RECT  2.16 37.125 84.24 37.395 ;
     RECT  2.16 37.665 84.24 37.935 ;
     RECT  2.16 38.205 84.24 38.475 ;
     RECT  2.16 38.745 84.24 39.015 ;
     RECT  2.16 39.285 84.24 39.555 ;
     RECT  2.16 39.825 84.24 40.095 ;
     RECT  2.16 40.365 84.24 40.635 ;
     RECT  2.16 40.905 84.24 41.175 ;
     RECT  2.16 41.445 84.24 41.715 ;
     RECT  2.16 41.985 84.24 42.255 ;
     RECT  2.16 42.525 84.24 42.795 ;
     RECT  2.16 43.065 84.24 43.335 ;
     RECT  2.16 43.605 84.24 43.875 ;
     RECT  2.16 44.145 84.24 44.415 ;
     RECT  2.16 44.685 84.24 44.955 ;
     RECT  2.16 45.225 84.24 45.495 ;
     RECT  2.16 45.765 84.24 46.035 ;
     RECT  2.16 46.305 84.24 46.575 ;
     RECT  2.16 46.845 84.24 47.115 ;
     RECT  2.16 47.385 84.24 47.655 ;
     RECT  2.16 47.925 84.24 48.195 ;
     RECT  2.16 48.465 84.24 48.735 ;
     RECT  2.16 49.005 84.24 49.275 ;
     RECT  2.16 49.545 84.24 49.815 ;
     RECT  2.16 50.085 84.24 50.355 ;
     RECT  2.16 50.625 84.24 50.895 ;
     RECT  2.16 51.165 84.24 51.435 ;
     RECT  2.16 51.705 84.24 51.975 ;
     RECT  2.16 52.245 84.24 52.515 ;
     RECT  2.16 52.785 84.24 53.055 ;
     RECT  2.16 53.325 84.24 53.595 ;
     RECT  2.16 53.865 84.24 54.135 ;
     RECT  2.16 54.405 84.24 54.675 ;
     RECT  2.16 54.945 84.24 55.215 ;
     RECT  2.16 55.485 84.24 55.755 ;
     RECT  2.16 56.025 84.24 56.295 ;
     RECT  2.16 56.565 84.24 56.835 ;
     RECT  2.16 57.105 84.24 57.375 ;
     RECT  2.16 57.645 84.24 57.915 ;
     RECT  2.16 58.185 84.24 58.455 ;
     RECT  2.16 58.725 84.24 58.995 ;
     RECT  2.16 59.265 84.24 59.535 ;
     RECT  2.16 59.805 84.24 60.075 ;
     RECT  2.16 60.345 84.24 60.615 ;
     RECT  2.16 60.885 84.24 61.155 ;
     RECT  2.16 61.425 84.24 61.695 ;
     RECT  2.16 61.965 84.24 62.235 ;
     RECT  2.16 62.505 84.24 62.775 ;
     RECT  2.16 63.045 84.24 63.315 ;
     RECT  2.16 63.585 84.24 63.855 ;
     RECT  2.16 64.125 84.24 64.395 ;
     RECT  2.16 64.665 84.24 64.935 ;
     RECT  2.16 65.205 84.24 65.475 ;
     RECT  2.16 65.745 84.24 66.015 ;
     RECT  2.16 66.285 84.24 66.555 ;
     RECT  2.16 66.825 84.24 67.095 ;
     RECT  2.16 67.365 84.24 67.635 ;
     RECT  2.16 67.905 84.24 68.175 ;
     RECT  2.16 68.445 84.24 68.715 ;
     RECT  2.16 68.985 84.24 69.255 ;
     RECT  2.16 69.525 84.24 69.795 ;
     RECT  2.16 70.065 84.24 70.335 ;
     RECT  2.16 70.605 84.24 70.875 ;
     RECT  2.16 71.145 84.24 71.415 ;
     RECT  2.16 71.685 84.24 71.955 ;
     RECT  2.16 72.225 84.24 72.495 ;
     RECT  2.16 72.765 84.24 73.035 ;
     RECT  2.16 73.305 84.24 73.575 ;
     RECT  2.16 73.845 84.24 74.115 ;
     RECT  2.16 74.385 84.24 74.655 ;
     RECT  2.16 74.925 84.24 75.195 ;
     RECT  2.16 75.465 84.24 75.735 ;
     RECT  2.16 76.005 84.24 76.275 ;
     RECT  2.16 76.545 84.24 76.815 ;
     RECT  2.16 77.085 84.24 77.355 ;
     RECT  2.16 77.625 84.24 77.895 ;
     RECT  2.16 78.165 84.24 78.435 ;
     RECT  2.16 78.705 84.24 78.975 ;
     RECT  2.16 79.245 84.24 79.515 ;
     RECT  2.16 79.785 84.24 80.055 ;
     RECT  2.16 80.325 84.24 80.595 ;
     RECT  2.16 80.865 84.24 81.135 ;
     RECT  2.16 81.405 84.24 81.675 ;
     RECT  2.16 81.945 84.24 82.215 ;
     RECT  2.16 82.485 84.24 82.755 ;
     RECT  2.16 83.025 84.24 83.295 ;
     RECT  2.16 83.565 84.24 83.835 ;
     RECT  2.16 84.105 84.24 84.375 ;
     RECT  2.16 84.645 84.24 84.915 ;
     RECT  2.16 85.185 84.24 85.455 ;
     RECT  2.16 85.725 84.24 85.995 ;
     RECT  2.16 86.265 84.24 86.535 ;
     RECT  2.16 86.805 84.24 87.075 ;
     RECT  2.16 87.345 84.24 87.615 ;
     RECT  2.16 87.885 84.24 88.155 ;
     RECT  2.16 88.425 84.24 88.695 ;
     RECT  2.16 88.965 84.24 89.235 ;
     RECT  2.16 89.505 84.24 89.775 ;
     RECT  2.16 90.045 84.24 90.315 ;
     RECT  2.16 90.585 84.24 90.855 ;
     RECT  2.16 91.125 84.24 91.395 ;
     RECT  2.16 91.665 84.24 91.935 ;
     RECT  2.16 92.205 84.24 92.475 ;
     RECT  2.16 92.745 84.24 93.015 ;
     RECT  2.16 93.285 84.24 93.555 ;
     RECT  2.16 93.825 84.24 94.095 ;
     RECT  2.16 94.365 84.24 94.635 ;
     RECT  2.16 94.905 84.24 95.175 ;
     RECT  2.16 95.445 84.24 95.715 ;
     RECT  2.16 95.985 84.24 96.255 ;
     RECT  2.16 96.525 84.24 96.795 ;
     RECT  2.16 97.065 84.24 97.335 ;
     RECT  2.16 97.605 84.24 97.875 ;
     RECT  2.16 98.145 84.24 98.415 ;
     RECT  2.16 98.685 84.24 98.955 ;
     RECT  2.16 99.225 84.24 99.495 ;
     RECT  2.16 99.765 84.24 100.035 ;
     RECT  2.16 100.305 84.24 100.575 ;
     RECT  2.16 100.845 84.24 101.115 ;
     RECT  2.16 101.385 84.24 101.655 ;
     RECT  2.16 101.925 84.24 102.195 ;
     RECT  2.16 102.465 84.24 102.735 ;
     RECT  2.16 103.005 84.24 103.275 ;
     RECT  2.16 103.545 84.24 103.815 ;
     RECT  2.16 104.085 84.24 104.355 ;
     RECT  2.16 104.625 84.24 104.895 ;
     RECT  2.16 105.165 84.24 105.435 ;
     RECT  2.16 105.705 84.24 105.975 ;
     RECT  2.16 106.245 84.24 106.515 ;
     RECT  2.16 106.785 84.24 107.055 ;
     RECT  2.16 107.325 84.24 107.595 ;
     RECT  2.16 107.865 84.24 108.135 ;
     RECT  2.16 108.405 84.24 108.675 ;
     RECT  2.16 108.945 84.24 109.215 ;
     RECT  2.16 109.485 84.24 109.755 ;
     RECT  2.16 110.025 84.24 110.295 ;
     RECT  2.16 110.565 84.24 110.835 ;
     RECT  2.16 111.105 84.24 111.375 ;
     RECT  2.16 111.645 84.24 111.915 ;
     RECT  2.16 112.185 84.24 112.455 ;
     RECT  2.16 112.725 84.24 112.995 ;
     RECT  2.16 113.265 84.24 113.535 ;
     RECT  2.16 113.805 84.24 114.075 ;
     RECT  2.16 114.345 84.24 114.615 ;
     RECT  2.16 114.885 84.24 115.155 ;
     RECT  2.16 115.425 84.24 115.695 ;
     RECT  2.16 115.965 84.24 116.235 ;
     RECT  2.16 116.505 84.24 116.775 ;
     RECT  2.16 117.045 84.24 117.315 ;
     RECT  2.16 117.585 84.24 117.855 ;
     RECT  2.16 118.125 84.24 118.395 ;
     RECT  2.16 118.665 84.24 118.935 ;
     RECT  2.16 119.205 84.24 119.475 ;
     RECT  2.16 119.745 84.24 120.015 ;
     RECT  2.16 120.285 84.24 120.555 ;
     RECT  2.16 120.825 84.24 121.095 ;
     RECT  2.16 121.365 84.24 121.635 ;
     RECT  2.16 121.905 84.24 122.175 ;
     RECT  2.16 122.445 84.24 122.715 ;
     RECT  2.16 122.985 84.24 123.255 ;
     RECT  2.16 123.525 84.24 123.795 ;
     RECT  2.16 124.065 84.24 124.335 ;
     RECT  2.16 124.605 84.24 124.875 ;
     RECT  2.16 125.145 84.24 125.415 ;
     RECT  2.16 125.685 84.24 125.955 ;
     RECT  2.16 126.225 84.24 126.495 ;
     RECT  2.16 126.765 84.24 127.035 ;
     RECT  2.16 127.305 84.24 127.44 ;
    LAYER RVTP ;
     RECT  2.16 2.295 84.24 2.565 ;
     RECT  2.16 2.835 84.24 3.105 ;
     RECT  2.16 3.375 84.24 3.645 ;
     RECT  2.16 3.915 84.24 4.185 ;
     RECT  2.16 4.455 84.24 4.725 ;
     RECT  2.16 4.995 84.24 5.265 ;
     RECT  2.16 5.535 84.24 5.805 ;
     RECT  2.16 6.075 84.24 6.345 ;
     RECT  2.16 6.615 84.24 6.885 ;
     RECT  2.16 7.155 84.24 7.425 ;
     RECT  2.16 7.695 84.24 7.965 ;
     RECT  2.16 8.235 84.24 8.505 ;
     RECT  2.16 8.775 84.24 9.045 ;
     RECT  2.16 9.315 84.24 9.585 ;
     RECT  2.16 9.855 84.24 10.125 ;
     RECT  2.16 10.395 84.24 10.665 ;
     RECT  2.16 10.935 84.24 11.205 ;
     RECT  2.16 11.475 84.24 11.745 ;
     RECT  2.16 12.015 84.24 12.285 ;
     RECT  2.16 12.555 84.24 12.825 ;
     RECT  2.16 13.095 84.24 13.365 ;
     RECT  2.16 13.635 84.24 13.905 ;
     RECT  2.16 14.175 84.24 14.445 ;
     RECT  2.16 14.715 84.24 14.985 ;
     RECT  2.16 15.255 84.24 15.525 ;
     RECT  2.16 15.795 84.24 16.065 ;
     RECT  2.16 16.335 84.24 16.605 ;
     RECT  2.16 16.875 84.24 17.145 ;
     RECT  2.16 17.415 84.24 17.685 ;
     RECT  2.16 17.955 84.24 18.225 ;
     RECT  2.16 18.495 84.24 18.765 ;
     RECT  2.16 19.035 84.24 19.305 ;
     RECT  2.16 19.575 84.24 19.845 ;
     RECT  2.16 20.115 84.24 20.385 ;
     RECT  2.16 20.655 84.24 20.925 ;
     RECT  2.16 21.195 84.24 21.465 ;
     RECT  2.16 21.735 84.24 22.005 ;
     RECT  2.16 22.275 84.24 22.545 ;
     RECT  2.16 22.815 84.24 23.085 ;
     RECT  2.16 23.355 84.24 23.625 ;
     RECT  2.16 23.895 84.24 24.165 ;
     RECT  2.16 24.435 84.24 24.705 ;
     RECT  2.16 24.975 84.24 25.245 ;
     RECT  2.16 25.515 84.24 25.785 ;
     RECT  2.16 26.055 84.24 26.325 ;
     RECT  2.16 26.595 84.24 26.865 ;
     RECT  2.16 27.135 84.24 27.405 ;
     RECT  2.16 27.675 84.24 27.945 ;
     RECT  2.16 28.215 84.24 28.485 ;
     RECT  2.16 28.755 84.24 29.025 ;
     RECT  2.16 29.295 84.24 29.565 ;
     RECT  2.16 29.835 84.24 30.105 ;
     RECT  2.16 30.375 84.24 30.645 ;
     RECT  2.16 30.915 84.24 31.185 ;
     RECT  2.16 31.455 84.24 31.725 ;
     RECT  2.16 31.995 84.24 32.265 ;
     RECT  2.16 32.535 84.24 32.805 ;
     RECT  2.16 33.075 84.24 33.345 ;
     RECT  2.16 33.615 84.24 33.885 ;
     RECT  2.16 34.155 84.24 34.425 ;
     RECT  2.16 34.695 84.24 34.965 ;
     RECT  2.16 35.235 84.24 35.505 ;
     RECT  2.16 35.775 84.24 36.045 ;
     RECT  2.16 36.315 84.24 36.585 ;
     RECT  2.16 36.855 84.24 37.125 ;
     RECT  2.16 37.395 84.24 37.665 ;
     RECT  2.16 37.935 84.24 38.205 ;
     RECT  2.16 38.475 84.24 38.745 ;
     RECT  2.16 39.015 84.24 39.285 ;
     RECT  2.16 39.555 84.24 39.825 ;
     RECT  2.16 40.095 84.24 40.365 ;
     RECT  2.16 40.635 84.24 40.905 ;
     RECT  2.16 41.175 84.24 41.445 ;
     RECT  2.16 41.715 84.24 41.985 ;
     RECT  2.16 42.255 84.24 42.525 ;
     RECT  2.16 42.795 84.24 43.065 ;
     RECT  2.16 43.335 84.24 43.605 ;
     RECT  2.16 43.875 84.24 44.145 ;
     RECT  2.16 44.415 84.24 44.685 ;
     RECT  2.16 44.955 84.24 45.225 ;
     RECT  2.16 45.495 84.24 45.765 ;
     RECT  2.16 46.035 84.24 46.305 ;
     RECT  2.16 46.575 84.24 46.845 ;
     RECT  2.16 47.115 84.24 47.385 ;
     RECT  2.16 47.655 84.24 47.925 ;
     RECT  2.16 48.195 84.24 48.465 ;
     RECT  2.16 48.735 84.24 49.005 ;
     RECT  2.16 49.275 84.24 49.545 ;
     RECT  2.16 49.815 84.24 50.085 ;
     RECT  2.16 50.355 84.24 50.625 ;
     RECT  2.16 50.895 84.24 51.165 ;
     RECT  2.16 51.435 84.24 51.705 ;
     RECT  2.16 51.975 84.24 52.245 ;
     RECT  2.16 52.515 84.24 52.785 ;
     RECT  2.16 53.055 84.24 53.325 ;
     RECT  2.16 53.595 84.24 53.865 ;
     RECT  2.16 54.135 84.24 54.405 ;
     RECT  2.16 54.675 84.24 54.945 ;
     RECT  2.16 55.215 84.24 55.485 ;
     RECT  2.16 55.755 84.24 56.025 ;
     RECT  2.16 56.295 84.24 56.565 ;
     RECT  2.16 56.835 84.24 57.105 ;
     RECT  2.16 57.375 84.24 57.645 ;
     RECT  2.16 57.915 84.24 58.185 ;
     RECT  2.16 58.455 84.24 58.725 ;
     RECT  2.16 58.995 84.24 59.265 ;
     RECT  2.16 59.535 84.24 59.805 ;
     RECT  2.16 60.075 84.24 60.345 ;
     RECT  2.16 60.615 84.24 60.885 ;
     RECT  2.16 61.155 84.24 61.425 ;
     RECT  2.16 61.695 84.24 61.965 ;
     RECT  2.16 62.235 84.24 62.505 ;
     RECT  2.16 62.775 84.24 63.045 ;
     RECT  2.16 63.315 84.24 63.585 ;
     RECT  2.16 63.855 84.24 64.125 ;
     RECT  2.16 64.395 84.24 64.665 ;
     RECT  2.16 64.935 84.24 65.205 ;
     RECT  2.16 65.475 84.24 65.745 ;
     RECT  2.16 66.015 84.24 66.285 ;
     RECT  2.16 66.555 84.24 66.825 ;
     RECT  2.16 67.095 84.24 67.365 ;
     RECT  2.16 67.635 84.24 67.905 ;
     RECT  2.16 68.175 84.24 68.445 ;
     RECT  2.16 68.715 84.24 68.985 ;
     RECT  2.16 69.255 84.24 69.525 ;
     RECT  2.16 69.795 84.24 70.065 ;
     RECT  2.16 70.335 84.24 70.605 ;
     RECT  2.16 70.875 84.24 71.145 ;
     RECT  2.16 71.415 84.24 71.685 ;
     RECT  2.16 71.955 84.24 72.225 ;
     RECT  2.16 72.495 84.24 72.765 ;
     RECT  2.16 73.035 84.24 73.305 ;
     RECT  2.16 73.575 84.24 73.845 ;
     RECT  2.16 74.115 84.24 74.385 ;
     RECT  2.16 74.655 84.24 74.925 ;
     RECT  2.16 75.195 84.24 75.465 ;
     RECT  2.16 75.735 84.24 76.005 ;
     RECT  2.16 76.275 84.24 76.545 ;
     RECT  2.16 76.815 84.24 77.085 ;
     RECT  2.16 77.355 84.24 77.625 ;
     RECT  2.16 77.895 84.24 78.165 ;
     RECT  2.16 78.435 84.24 78.705 ;
     RECT  2.16 78.975 84.24 79.245 ;
     RECT  2.16 79.515 84.24 79.785 ;
     RECT  2.16 80.055 84.24 80.325 ;
     RECT  2.16 80.595 84.24 80.865 ;
     RECT  2.16 81.135 84.24 81.405 ;
     RECT  2.16 81.675 84.24 81.945 ;
     RECT  2.16 82.215 84.24 82.485 ;
     RECT  2.16 82.755 84.24 83.025 ;
     RECT  2.16 83.295 84.24 83.565 ;
     RECT  2.16 83.835 84.24 84.105 ;
     RECT  2.16 84.375 84.24 84.645 ;
     RECT  2.16 84.915 84.24 85.185 ;
     RECT  2.16 85.455 84.24 85.725 ;
     RECT  2.16 85.995 84.24 86.265 ;
     RECT  2.16 86.535 84.24 86.805 ;
     RECT  2.16 87.075 84.24 87.345 ;
     RECT  2.16 87.615 84.24 87.885 ;
     RECT  2.16 88.155 84.24 88.425 ;
     RECT  2.16 88.695 84.24 88.965 ;
     RECT  2.16 89.235 84.24 89.505 ;
     RECT  2.16 89.775 84.24 90.045 ;
     RECT  2.16 90.315 84.24 90.585 ;
     RECT  2.16 90.855 84.24 91.125 ;
     RECT  2.16 91.395 84.24 91.665 ;
     RECT  2.16 91.935 84.24 92.205 ;
     RECT  2.16 92.475 84.24 92.745 ;
     RECT  2.16 93.015 84.24 93.285 ;
     RECT  2.16 93.555 84.24 93.825 ;
     RECT  2.16 94.095 84.24 94.365 ;
     RECT  2.16 94.635 84.24 94.905 ;
     RECT  2.16 95.175 84.24 95.445 ;
     RECT  2.16 95.715 84.24 95.985 ;
     RECT  2.16 96.255 84.24 96.525 ;
     RECT  2.16 96.795 84.24 97.065 ;
     RECT  2.16 97.335 84.24 97.605 ;
     RECT  2.16 97.875 84.24 98.145 ;
     RECT  2.16 98.415 84.24 98.685 ;
     RECT  2.16 98.955 84.24 99.225 ;
     RECT  2.16 99.495 84.24 99.765 ;
     RECT  2.16 100.035 84.24 100.305 ;
     RECT  2.16 100.575 84.24 100.845 ;
     RECT  2.16 101.115 84.24 101.385 ;
     RECT  2.16 101.655 84.24 101.925 ;
     RECT  2.16 102.195 84.24 102.465 ;
     RECT  2.16 102.735 84.24 103.005 ;
     RECT  2.16 103.275 84.24 103.545 ;
     RECT  2.16 103.815 84.24 104.085 ;
     RECT  2.16 104.355 84.24 104.625 ;
     RECT  2.16 104.895 84.24 105.165 ;
     RECT  2.16 105.435 84.24 105.705 ;
     RECT  2.16 105.975 84.24 106.245 ;
     RECT  2.16 106.515 84.24 106.785 ;
     RECT  2.16 107.055 84.24 107.325 ;
     RECT  2.16 107.595 84.24 107.865 ;
     RECT  2.16 108.135 84.24 108.405 ;
     RECT  2.16 108.675 84.24 108.945 ;
     RECT  2.16 109.215 84.24 109.485 ;
     RECT  2.16 109.755 84.24 110.025 ;
     RECT  2.16 110.295 84.24 110.565 ;
     RECT  2.16 110.835 84.24 111.105 ;
     RECT  2.16 111.375 84.24 111.645 ;
     RECT  2.16 111.915 84.24 112.185 ;
     RECT  2.16 112.455 84.24 112.725 ;
     RECT  2.16 112.995 84.24 113.265 ;
     RECT  2.16 113.535 84.24 113.805 ;
     RECT  2.16 114.075 84.24 114.345 ;
     RECT  2.16 114.615 84.24 114.885 ;
     RECT  2.16 115.155 84.24 115.425 ;
     RECT  2.16 115.695 84.24 115.965 ;
     RECT  2.16 116.235 84.24 116.505 ;
     RECT  2.16 116.775 84.24 117.045 ;
     RECT  2.16 117.315 84.24 117.585 ;
     RECT  2.16 117.855 84.24 118.125 ;
     RECT  2.16 118.395 84.24 118.665 ;
     RECT  2.16 118.935 84.24 119.205 ;
     RECT  2.16 119.475 84.24 119.745 ;
     RECT  2.16 120.015 84.24 120.285 ;
     RECT  2.16 120.555 84.24 120.825 ;
     RECT  2.16 121.095 84.24 121.365 ;
     RECT  2.16 121.635 84.24 121.905 ;
     RECT  2.16 122.175 84.24 122.445 ;
     RECT  2.16 122.715 84.24 122.985 ;
     RECT  2.16 123.255 84.24 123.525 ;
     RECT  2.16 123.795 84.24 124.065 ;
     RECT  2.16 124.335 84.24 124.605 ;
     RECT  2.16 124.875 84.24 125.145 ;
     RECT  2.16 125.415 84.24 125.685 ;
     RECT  2.16 125.955 84.24 126.225 ;
     RECT  2.16 126.495 84.24 126.765 ;
     RECT  2.16 127.035 84.24 127.305 ;
    LAYER M1 ;
     RECT  2.16 2.151 84.24 127.449 ;
    LAYER M2 ;
     RECT  0.211 7.902 2.16 7.92 ;
     RECT  0.535 16.956 2.16 16.974 ;
     RECT  0.535 29.34 2.16 29.358 ;
     RECT  0.535 47.664 2.16 47.682 ;
     RECT  0.211 53.568 2.16 53.586 ;
     RECT  0.535 64.17 2.16 64.188 ;
     RECT  0.211 79.218 2.16 79.236 ;
     RECT  2.16 2.151 33.619 127.449 ;
     RECT  33.619 2.106 34.331 127.449 ;
     RECT  34.331 2.151 60.979 127.449 ;
     RECT  60.979 2.106 67.351 127.449 ;
     RECT  67.351 2.034 68.279 127.449 ;
     RECT  68.279 2.106 68.315 127.449 ;
     RECT  68.315 2.151 84.24 127.449 ;
     RECT  84.24 5.04 84.407 5.058 ;
     RECT  84.24 7.74 84.407 7.758 ;
     RECT  84.24 9.63 84.407 9.648 ;
     RECT  84.24 12.258 84.407 12.276 ;
     RECT  84.24 13.608 84.407 13.626 ;
     RECT  84.24 14.49 84.407 14.508 ;
     RECT  84.24 15.84 84.407 15.858 ;
     RECT  84.24 16.92 84.407 16.938 ;
     RECT  84.24 18.198 84.407 18.216 ;
     RECT  84.24 19.62 84.407 19.638 ;
     RECT  84.24 21.78 84.407 21.798 ;
     RECT  84.24 23.058 84.407 23.076 ;
     RECT  84.24 24.21 84.407 24.228 ;
     RECT  84.24 25.56 84.407 25.578 ;
     RECT  84.24 27.918 84.407 27.936 ;
     RECT  84.24 31.5 84.407 31.518 ;
     RECT  84.24 32.85 84.407 32.868 ;
     RECT  84.24 35.28 84.407 35.298 ;
     RECT  84.24 36.288 84.407 36.306 ;
     RECT  84.24 38.682 84.407 38.7 ;
     RECT  84.24 41.418 84.407 41.436 ;
     RECT  84.24 44.73 84.407 44.748 ;
     RECT  84.24 47.16 84.407 47.178 ;
     RECT  84.24 48.438 84.407 48.456 ;
     RECT  84.24 49.86 84.407 49.878 ;
     RECT  84.24 52.02 84.407 52.038 ;
     RECT  84.24 53.37 84.407 53.388 ;
     RECT  84.24 54.648 84.407 54.666 ;
     RECT  84.24 55.8 84.407 55.818 ;
     RECT  84.24 56.88 84.407 56.898 ;
     RECT  84.24 60.66 84.407 60.678 ;
     RECT  84.24 61.74 84.407 61.758 ;
     RECT  84.24 63.09 84.407 63.108 ;
     RECT  84.24 64.17 84.407 64.188 ;
     RECT  84.24 67.95 84.407 67.968 ;
     RECT  84.24 68.958 84.407 68.976 ;
     RECT  84.24 71.46 84.407 71.478 ;
     RECT  84.24 72.54 84.407 72.558 ;
     RECT  84.24 73.89 84.407 73.908 ;
     RECT  84.24 74.97 84.407 74.988 ;
     RECT  84.24 78.516 84.407 78.534 ;
     RECT  84.24 80.1 84.407 80.118 ;
     RECT  84.24 81.18 84.407 81.198 ;
     RECT  84.24 84.888 84.407 84.906 ;
     RECT  84.24 85.968 84.407 85.986 ;
     RECT  84.24 88.398 84.407 88.416 ;
     RECT  84.24 90.828 84.407 90.846 ;
     RECT  84.24 91.98 84.407 91.998 ;
     RECT  84.24 94.41 84.407 94.428 ;
     RECT  84.24 95.688 84.407 95.706 ;
     RECT  84.24 96.84 84.407 96.858 ;
     RECT  84.24 98.19 84.407 98.208 ;
     RECT  84.24 100.62 84.407 100.638 ;
     RECT  84.24 106.56 84.407 106.578 ;
     RECT  84.24 107.91 84.407 107.928 ;
     RECT  84.24 110.34 84.407 110.358 ;
     RECT  84.24 111.42 84.407 111.438 ;
     RECT  84.24 112.5 84.407 112.518 ;
     RECT  84.24 114.93 84.407 114.948 ;
     RECT  84.24 117.36 84.407 117.378 ;
     RECT  84.24 118.71 84.407 118.728 ;
     RECT  84.24 101.7 84.911 101.718 ;
     RECT  84.24 104.13 84.911 104.148 ;
     RECT  84.24 8.82 84.947 8.838 ;
     RECT  84.24 20.7 84.947 20.718 ;
     RECT  84.24 33.93 84.947 33.948 ;
     RECT  84.24 37.602 84.947 37.62 ;
     RECT  84.24 42.57 84.947 42.588 ;
     RECT  84.24 43.65 84.947 43.668 ;
     RECT  84.24 57.996 84.947 58.014 ;
     RECT  84.24 77.4 84.947 77.418 ;
     RECT  84.24 83.538 84.947 83.556 ;
     RECT  84.24 87.39 84.947 87.408 ;
     RECT  84.24 99.162 84.947 99.18 ;
     RECT  84.24 102.78 84.947 102.798 ;
     RECT  84.24 116.208 84.947 116.226 ;
     RECT  84.24 26.91 85.523 26.928 ;
     RECT  84.24 29.034 85.523 29.052 ;
     RECT  84.24 39.87 85.523 39.888 ;
     RECT  84.24 59.238 85.523 59.256 ;
     RECT  84.24 70.074 85.523 70.092 ;
     RECT  84.24 93.6 85.523 93.618 ;
     RECT  84.24 105.246 85.523 105.264 ;
    LAYER M3 ;
     RECT  12.492 0.187 12.51 0.571 ;
     RECT  46.836 0.187 46.854 0.571 ;
     RECT  33.552 0.187 33.57 1.675 ;
     RECT  34.308 0.571 34.326 1.675 ;
     RECT  6.264 0.571 6.282 1.723 ;
     RECT  8.928 1.099 8.946 1.723 ;
     RECT  12.024 0.571 12.51 1.723 ;
     RECT  22.248 0.571 22.266 1.723 ;
     RECT  23.184 0.187 23.202 1.723 ;
     RECT  23.976 0.571 23.994 1.723 ;
     RECT  33.552 1.675 34.326 1.723 ;
     RECT  38.808 0.571 38.826 1.723 ;
     RECT  41.688 0.571 41.706 1.723 ;
     RECT  44.784 1.675 44.802 1.723 ;
     RECT  46.224 0.571 46.854 1.723 ;
     RECT  47.664 1.099 47.682 1.723 ;
     RECT  53.64 0.571 53.658 1.723 ;
     RECT  56.376 0.235 56.394 1.723 ;
     RECT  60.444 0.571 60.462 1.723 ;
     RECT  65.412 0.187 65.43 1.723 ;
     RECT  76.392 0.571 76.41 1.723 ;
     RECT  77.508 0.187 77.526 1.723 ;
     RECT  79.776 0.187 79.794 1.723 ;
     RECT  10.008 1.723 14.346 1.771 ;
     RECT  35.496 1.723 36.018 1.771 ;
     RECT  36.756 1.723 39.834 1.771 ;
     RECT  65.412 1.723 78.786 1.771 ;
     RECT  30.816 1.723 34.326 2.011 ;
     RECT  35.496 1.771 39.834 2.011 ;
     RECT  40.788 1.723 57.186 2.011 ;
     RECT  6.264 1.723 7.794 2.143 ;
     RECT  29.772 2.059 29.79 2.143 ;
     RECT  30.816 2.011 34.758 2.143 ;
     RECT  35.496 2.011 57.186 2.143 ;
     RECT  6.264 2.143 7.905 2.191 ;
     RECT  8.712 1.723 9.054 2.191 ;
     RECT  10.008 1.771 14.454 2.191 ;
     RECT  15.192 1.723 17.586 2.191 ;
     RECT  18.54 1.723 20.286 2.191 ;
     RECT  22.248 1.723 25.218 2.191 ;
     RECT  26.712 1.723 26.946 2.191 ;
     RECT  27.828 1.723 27.846 2.191 ;
     RECT  29.415 2.143 29.79 2.191 ;
     RECT  30.816 2.143 57.186 2.191 ;
     RECT  58.248 1.723 59.706 2.191 ;
     RECT  60.444 1.723 64.638 2.191 ;
     RECT  65.412 1.771 78.894 2.191 ;
     RECT  18.54 2.191 20.358 2.251 ;
     RECT  21.276 2.191 26.946 2.251 ;
     RECT  29.232 2.191 57.186 2.251 ;
     RECT  4.284 1.723 5.49 2.255 ;
     RECT  18.54 2.251 20.394 2.263 ;
     RECT  21.24 2.251 26.946 2.263 ;
     RECT  4.788 2.255 5.49 2.335 ;
     RECT  6.264 2.191 17.586 2.335 ;
     RECT  58.14 2.191 78.894 2.335 ;
     RECT  4.788 2.335 17.586 2.371 ;
     RECT  18.54 2.263 26.946 2.371 ;
     RECT  27.828 2.191 27.954 2.371 ;
     RECT  28.908 2.251 57.186 2.371 ;
     RECT  57.96 2.335 78.894 2.371 ;
     RECT  79.632 1.723 81.09 2.371 ;
     RECT  81.828 1.723 81.846 2.371 ;
     RECT  2.415 2.143 2.505 2.413 ;
     RECT  83.415 2.143 83.505 2.413 ;
     RECT  4.788 2.371 81.954 2.641 ;
     RECT  4.788 2.641 82.278 3.181 ;
     RECT  4.68 3.181 82.278 3.569 ;
     RECT  4.752 3.569 82.278 3.721 ;
     RECT  4.752 3.721 82.35 4.109 ;
     RECT  2.415 2.413 2.697 4.225 ;
     RECT  2.304 4.225 2.697 4.261 ;
     RECT  3.456 4.117 3.474 4.261 ;
     RECT  83.415 2.413 83.697 4.261 ;
     RECT  4.752 4.109 82.134 4.415 ;
     RECT  4.752 4.415 81.918 4.459 ;
     RECT  2.304 4.261 3.474 4.555 ;
     RECT  4.644 4.459 81.918 4.649 ;
     RECT  77.508 4.649 81.918 4.685 ;
     RECT  82.944 4.261 83.697 4.721 ;
     RECT  2.304 4.555 3.906 4.765 ;
     RECT  4.644 4.649 76.626 4.765 ;
     RECT  83.34 4.721 83.697 4.891 ;
     RECT  0.252 4.891 0.27 5.021 ;
     RECT  83.34 4.891 84.402 5.063 ;
     RECT  2.304 4.765 76.626 5.297 ;
     RECT  79.524 4.685 81.918 5.575 ;
     RECT  83.34 5.063 84.114 5.575 ;
     RECT  76.212 5.297 76.626 5.611 ;
     RECT  77.508 4.685 78.75 5.611 ;
     RECT  79.524 5.575 81.954 5.611 ;
     RECT  83.124 5.575 84.114 5.765 ;
     RECT  76.212 5.611 81.954 5.873 ;
     RECT  76.248 5.873 81.954 5.971 ;
     RECT  2.304 5.297 75.438 5.999 ;
     RECT  0.216 5.899 0.234 6.029 ;
     RECT  2.304 5.999 75.366 6.035 ;
     RECT  76.248 5.971 82.314 6.091 ;
     RECT  76.248 6.091 82.386 6.151 ;
     RECT  2.304 6.035 75.15 6.269 ;
     RECT  76.248 6.151 82.674 6.269 ;
     RECT  82.656 6.269 82.674 6.305 ;
     RECT  76.248 6.269 81.918 6.781 ;
     RECT  76.212 6.781 81.918 6.811 ;
     RECT  76.032 6.811 81.918 6.845 ;
     RECT  76.032 6.845 78.714 6.917 ;
     RECT  83.415 5.765 84.114 7.339 ;
     RECT  2.304 6.269 73.314 7.385 ;
     RECT  74.196 6.269 75.15 7.465 ;
     RECT  76.032 6.917 76.698 7.465 ;
     RECT  2.415 7.385 73.314 7.627 ;
     RECT  74.196 7.465 76.698 7.627 ;
     RECT  2.415 7.627 76.698 7.661 ;
     RECT  2.415 7.661 10.422 7.678 ;
     RECT  83.415 7.339 84.402 7.763 ;
     RECT  11.304 7.661 76.698 7.771 ;
     RECT  77.508 6.917 78.714 7.771 ;
     RECT  79.524 6.845 81.918 7.771 ;
     RECT  83.415 7.763 84.114 7.771 ;
     RECT  11.304 7.771 78.714 7.889 ;
     RECT  74.448 7.889 78.714 7.925 ;
     RECT  79.524 7.771 84.114 7.997 ;
     RECT  0.216 7.897 0.234 8.093 ;
     RECT  11.304 7.889 73.638 8.159 ;
     RECT  79.524 7.997 82.638 8.195 ;
     RECT  39.6 8.159 73.638 8.285 ;
     RECT  39.744 8.285 73.638 8.477 ;
     RECT  2.415 7.678 10.386 8.491 ;
     RECT  75.888 7.925 78.714 8.501 ;
     RECT  2.304 8.491 10.386 8.545 ;
     RECT  11.304 8.159 38.826 8.545 ;
     RECT  77.22 8.501 78.714 8.581 ;
     RECT  79.524 8.195 81.918 8.581 ;
     RECT  2.304 8.545 38.826 8.635 ;
     RECT  74.448 7.925 75.15 8.735 ;
     RECT  54.936 8.477 73.638 8.843 ;
     RECT  84.924 8.491 84.942 8.843 ;
     RECT  77.22 8.581 81.918 8.969 ;
     RECT  2.268 8.635 38.826 9.112 ;
     RECT  77.508 8.969 81.918 9.121 ;
     RECT  2.268 9.112 38.862 9.211 ;
     RECT  39.744 8.477 54.198 9.211 ;
     RECT  54.936 8.843 73.602 9.211 ;
     RECT  77.508 9.121 82.062 9.275 ;
     RECT  75.888 8.501 76.446 9.391 ;
     RECT  2.268 9.211 73.602 9.581 ;
     RECT  83.415 7.997 84.114 9.625 ;
     RECT  74.52 8.735 75.15 9.661 ;
     RECT  75.888 9.391 76.482 9.661 ;
     RECT  83.415 9.625 84.402 9.677 ;
     RECT  2.304 9.581 73.602 9.823 ;
     RECT  2.304 9.823 73.782 10.201 ;
     RECT  74.52 9.661 76.482 10.201 ;
     RECT  83.415 9.677 84.114 10.201 ;
     RECT  0.252 10.123 0.27 10.253 ;
     RECT  77.508 9.275 81.918 10.291 ;
     RECT  83.232 10.201 84.114 10.315 ;
     RECT  83.088 10.315 84.114 10.355 ;
     RECT  77.364 10.291 81.918 10.427 ;
     RECT  2.304 10.201 76.482 10.463 ;
     RECT  77.364 10.427 80.802 10.463 ;
     RECT  3.6 10.463 76.482 11.011 ;
     RECT  77.364 10.463 80.226 11.011 ;
     RECT  3.6 11.011 80.226 11.129 ;
     RECT  2.304 10.463 2.697 11.281 ;
     RECT  3.6 11.129 76.194 11.281 ;
     RECT  83.415 10.355 84.114 11.281 ;
     RECT  81.9 10.427 81.918 11.371 ;
     RECT  2.304 11.281 76.194 11.399 ;
     RECT  81.9 11.371 82.458 11.407 ;
     RECT  81.36 11.407 82.458 11.453 ;
     RECT  81.9 11.453 82.458 11.551 ;
     RECT  83.34 11.281 84.114 11.551 ;
     RECT  81.9 11.551 84.114 11.705 ;
     RECT  81.9 11.705 82.35 11.849 ;
     RECT  2.304 11.399 4.734 11.975 ;
     RECT  83.415 11.705 84.114 12.091 ;
     RECT  5.508 11.399 76.194 12.253 ;
     RECT  83.415 12.091 84.402 12.281 ;
     RECT  77.364 11.129 80.226 12.353 ;
     RECT  3.744 11.975 4.734 12.361 ;
     RECT  5.508 12.253 76.41 12.361 ;
     RECT  2.304 11.975 2.97 12.379 ;
     RECT  3.744 12.361 76.41 12.451 ;
     RECT  81 12.091 81.018 12.479 ;
     RECT  2.268 12.379 2.97 12.551 ;
     RECT  3.744 12.451 76.518 12.631 ;
     RECT  77.364 12.353 78.297 12.631 ;
     RECT  3.744 12.631 78.297 12.821 ;
     RECT  2.304 12.551 2.97 12.829 ;
     RECT  3.744 12.821 76.518 12.829 ;
     RECT  2.304 12.829 76.518 13.019 ;
     RECT  3.6 13.019 76.41 13.055 ;
     RECT  83.415 12.281 84.114 13.387 ;
     RECT  81.9 11.849 82.314 13.531 ;
     RECT  3.6 13.055 76.23 13.595 ;
     RECT  83.415 13.387 84.402 13.631 ;
     RECT  79.02 12.353 80.226 13.801 ;
     RECT  81.9 13.531 82.674 13.829 ;
     RECT  3.636 13.595 76.23 13.901 ;
     RECT  81.9 13.829 82.314 13.981 ;
     RECT  79.02 13.801 80.514 14.099 ;
     RECT  2.304 13.019 2.826 14.107 ;
     RECT  81.576 13.981 82.314 14.135 ;
     RECT  81.828 14.135 82.314 14.243 ;
     RECT  2.304 14.107 2.898 14.485 ;
     RECT  3.636 13.901 70.326 14.485 ;
     RECT  83.415 13.631 84.114 14.485 ;
     RECT  83.415 14.485 84.402 14.521 ;
     RECT  2.304 14.485 70.326 14.539 ;
     RECT  83.088 14.521 84.402 14.573 ;
     RECT  77.364 12.821 78.297 14.611 ;
     RECT  79.02 14.099 80.226 14.611 ;
     RECT  81.9 14.243 82.314 14.647 ;
     RECT  83.088 14.573 84.114 14.647 ;
     RECT  2.268 14.539 70.326 14.755 ;
     RECT  71.064 13.901 76.23 14.755 ;
     RECT  2.268 14.755 76.23 14.791 ;
     RECT  81.9 14.647 84.114 14.819 ;
     RECT  2.268 14.791 76.59 15.557 ;
     RECT  83.16 14.819 84.114 15.691 ;
     RECT  81.9 14.819 82.314 15.791 ;
     RECT  83.16 15.691 84.402 15.863 ;
     RECT  77.364 14.611 80.226 16.141 ;
     RECT  83.16 15.863 84.114 16.915 ;
     RECT  83.16 16.915 84.402 17.021 ;
     RECT  77.364 16.141 80.91 17.105 ;
     RECT  0.54 16.951 0.558 17.165 ;
     RECT  2.304 15.557 76.59 17.221 ;
     RECT  81.936 15.791 82.314 17.221 ;
     RECT  83.16 17.021 84.114 17.221 ;
     RECT  81.936 17.221 84.114 17.375 ;
     RECT  81.936 17.375 82.314 17.491 ;
     RECT  2.304 17.221 76.95 18.031 ;
     RECT  83.16 17.375 84.114 18.139 ;
     RECT  81.756 17.491 82.314 18.193 ;
     RECT  83.16 18.139 84.402 18.193 ;
     RECT  81.756 18.193 84.402 18.221 ;
     RECT  2.304 18.031 77.238 18.283 ;
     RECT  81.756 18.221 84.114 18.455 ;
     RECT  2.268 18.283 77.238 18.563 ;
     RECT  83.16 18.455 84.114 19.435 ;
     RECT  2.304 18.563 77.238 19.499 ;
     RECT  83.16 19.435 84.402 19.643 ;
     RECT  74.232 19.499 77.238 19.679 ;
     RECT  0.216 19.723 0.234 19.853 ;
     RECT  83.16 19.643 84.114 19.921 ;
     RECT  81.756 18.455 82.314 20.047 ;
     RECT  83.052 19.921 84.114 20.047 ;
     RECT  78.015 17.105 80.91 20.219 ;
     RECT  77.22 19.679 77.238 20.581 ;
     RECT  84.924 20.587 84.942 20.723 ;
     RECT  77.22 20.581 77.274 20.731 ;
     RECT  78.015 20.219 78.354 20.731 ;
     RECT  77.22 20.731 78.354 20.849 ;
     RECT  2.304 19.499 73.314 20.965 ;
     RECT  78.015 20.849 78.354 20.993 ;
     RECT  2.268 20.965 73.314 21.053 ;
     RECT  2.304 21.053 73.314 21.091 ;
     RECT  0.216 21.163 0.234 21.293 ;
     RECT  77.22 20.849 77.238 21.397 ;
     RECT  81.756 20.047 84.114 21.739 ;
     RECT  81.756 21.739 84.402 21.803 ;
     RECT  78.015 20.993 78.297 21.811 ;
     RECT  79.272 20.219 80.91 21.811 ;
     RECT  81.756 21.803 84.114 21.811 ;
     RECT  78.015 21.811 84.114 21.929 ;
     RECT  78.015 21.929 78.462 21.971 ;
     RECT  74.232 19.679 75.978 22.847 ;
     RECT  81.756 21.929 84.114 23.035 ;
     RECT  81.756 23.035 84.402 23.081 ;
     RECT  77.184 21.397 77.238 23.161 ;
     RECT  78.015 21.971 78.297 23.161 ;
     RECT  79.272 21.929 80.91 23.161 ;
     RECT  81.756 23.081 84.114 23.161 ;
     RECT  77.184 23.161 84.114 23.315 ;
     RECT  79.272 23.315 84.114 23.351 ;
     RECT  81.756 23.351 84.114 23.459 ;
     RECT  79.272 23.351 80.91 23.729 ;
     RECT  82.764 23.459 84.114 24.187 ;
     RECT  82.764 24.187 84.402 24.233 ;
     RECT  74.304 22.847 75.978 24.359 ;
     RECT  2.304 21.091 73.386 24.469 ;
     RECT  74.304 24.359 74.538 24.469 ;
     RECT  2.304 24.469 74.538 24.509 ;
     RECT  82.764 24.233 83.934 24.665 ;
     RECT  77.184 23.315 78.297 24.709 ;
     RECT  79.38 23.729 80.91 24.709 ;
     RECT  81.756 23.459 81.954 24.745 ;
     RECT  82.764 24.665 83.697 24.745 ;
     RECT  77.184 24.709 80.91 24.809 ;
     RECT  79.2 24.809 80.91 25.051 ;
     RECT  81.756 24.745 83.697 25.051 ;
     RECT  74.304 24.509 74.538 25.469 ;
     RECT  79.2 25.051 83.697 25.475 ;
     RECT  79.38 25.475 83.697 25.483 ;
     RECT  77.184 24.809 78.297 25.555 ;
     RECT  79.38 25.483 84.402 25.583 ;
     RECT  75.492 24.359 75.978 25.591 ;
     RECT  76.716 25.555 78.297 25.591 ;
     RECT  75.492 25.591 78.297 26.045 ;
     RECT  2.304 24.509 73.386 26.095 ;
     RECT  2.304 26.095 73.53 26.251 ;
     RECT  74.304 25.469 74.322 26.251 ;
     RECT  85.5 26.635 85.518 26.933 ;
     RECT  79.38 25.583 83.697 27.205 ;
     RECT  79.164 27.205 83.697 27.245 ;
     RECT  79.38 27.245 83.697 27.787 ;
     RECT  2.304 26.251 74.322 27.905 ;
     RECT  2.412 27.905 74.322 27.917 ;
     RECT  79.38 27.787 84.402 27.941 ;
     RECT  2.415 27.917 74.322 28.409 ;
     RECT  2.415 28.409 73.566 28.493 ;
     RECT  0.216 28.507 0.234 28.733 ;
     RECT  2.415 28.493 73.494 28.795 ;
     RECT  74.304 28.409 74.322 28.993 ;
     RECT  85.5 29.029 85.518 29.117 ;
     RECT  2.304 28.795 73.494 29.461 ;
     RECT  74.304 28.993 74.934 29.461 ;
     RECT  0.54 29.335 0.558 29.693 ;
     RECT  79.38 27.941 83.697 30.235 ;
     RECT  79.38 30.235 83.826 30.371 ;
     RECT  79.38 30.371 83.697 31.495 ;
     RECT  75.672 26.045 78.297 31.531 ;
     RECT  79.38 31.495 84.402 31.565 ;
     RECT  75.672 31.531 78.39 31.649 ;
     RECT  79.38 31.565 83.79 31.649 ;
     RECT  79.38 31.649 83.697 31.801 ;
     RECT  79.164 31.801 83.697 31.901 ;
     RECT  79.38 31.901 83.697 32.683 ;
     RECT  2.304 29.461 74.934 32.729 ;
     RECT  79.38 32.683 84.402 32.873 ;
     RECT  75.672 31.649 78.297 32.971 ;
     RECT  79.38 32.873 83.898 32.999 ;
     RECT  75.672 32.971 78.642 33.008 ;
     RECT  2.304 32.729 74.286 33.385 ;
     RECT  2.268 33.385 74.286 33.629 ;
     RECT  75.672 33.008 78.297 33.817 ;
     RECT  84.924 33.835 84.942 33.953 ;
     RECT  2.268 33.629 73.998 34.115 ;
     RECT  75.564 33.817 78.297 34.223 ;
     RECT  2.304 34.115 73.998 34.771 ;
     RECT  2.304 34.771 74.07 35.131 ;
     RECT  79.38 32.999 83.697 35.131 ;
     RECT  2.268 35.131 74.07 35.303 ;
     RECT  79.38 35.131 84.402 35.303 ;
     RECT  2.304 35.303 74.07 35.581 ;
     RECT  79.38 35.303 83.697 36.277 ;
     RECT  79.38 36.277 84.402 36.317 ;
     RECT  2.304 35.581 74.142 36.481 ;
     RECT  2.304 36.481 74.79 36.589 ;
     RECT  75.672 34.223 78.297 36.589 ;
     RECT  2.304 36.589 78.297 37.291 ;
     RECT  79.38 36.317 83.697 37.471 ;
     RECT  79.38 37.471 83.754 37.589 ;
     RECT  84.924 37.579 84.942 37.625 ;
     RECT  2.268 37.291 78.297 37.975 ;
     RECT  79.38 37.589 83.697 37.975 ;
     RECT  2.268 37.975 83.697 38.003 ;
     RECT  2.304 38.003 83.697 38.677 ;
     RECT  2.304 38.677 84.402 38.765 ;
     RECT  2.304 38.765 83.697 39.451 ;
     RECT  85.5 39.865 85.518 39.917 ;
     RECT  2.268 39.451 83.697 40.127 ;
     RECT  2.304 40.127 83.697 40.595 ;
     RECT  2.34 40.595 83.697 41.179 ;
     RECT  2.34 41.179 84.402 41.323 ;
     RECT  2.304 41.323 84.402 41.441 ;
     RECT  2.304 41.441 83.697 41.611 ;
     RECT  2.268 41.611 83.697 41.783 ;
     RECT  84.924 42.331 84.942 42.593 ;
     RECT  84.924 43.627 84.942 43.673 ;
     RECT  2.304 41.783 83.697 43.835 ;
     RECT  75.132 43.835 83.697 44.105 ;
     RECT  2.304 43.835 74.322 44.587 ;
     RECT  75.42 44.105 83.697 44.645 ;
     RECT  75.456 44.645 83.697 44.725 ;
     RECT  75.456 44.725 84.402 44.813 ;
     RECT  2.304 44.587 74.682 44.879 ;
     RECT  2.304 44.879 74.61 45.805 ;
     RECT  2.304 45.805 74.646 45.841 ;
     RECT  75.456 44.813 83.697 45.841 ;
     RECT  2.304 45.841 83.697 45.931 ;
     RECT  2.268 45.931 83.826 46.103 ;
     RECT  2.268 46.103 83.697 46.265 ;
     RECT  2.304 46.265 83.697 46.535 ;
     RECT  2.34 46.535 83.697 46.949 ;
     RECT  3.78 46.949 83.697 47.155 ;
     RECT  3.78 47.155 84.402 47.261 ;
     RECT  2.34 46.949 2.862 47.371 ;
     RECT  2.304 47.371 2.862 47.515 ;
     RECT  2.268 47.515 2.862 47.615 ;
     RECT  2.304 47.615 2.862 47.731 ;
     RECT  3.78 47.261 83.697 47.731 ;
     RECT  2.304 47.731 83.697 48.379 ;
     RECT  2.304 48.379 84.402 48.461 ;
     RECT  0.54 47.659 0.558 48.557 ;
     RECT  2.304 48.461 83.697 49.675 ;
     RECT  2.304 49.675 84.402 49.883 ;
     RECT  2.304 49.883 83.697 50.251 ;
     RECT  2.268 50.251 83.697 50.387 ;
     RECT  2.304 50.387 83.697 50.827 ;
     RECT  2.304 50.827 83.826 50.891 ;
     RECT  0.252 51.739 0.27 51.869 ;
     RECT  2.304 50.891 83.697 51.979 ;
     RECT  2.304 51.979 84.402 52.043 ;
     RECT  2.304 52.043 83.697 52.951 ;
     RECT  2.304 52.951 83.754 53.275 ;
     RECT  2.304 53.275 84.402 53.393 ;
     RECT  0.216 53.563 0.234 53.6 ;
     RECT  2.304 53.393 83.697 53.995 ;
     RECT  2.268 53.995 83.697 54.095 ;
     RECT  2.304 54.095 83.697 54.427 ;
     RECT  2.304 54.427 84.402 54.671 ;
     RECT  2.304 54.671 83.697 55.517 ;
     RECT  6.408 55.517 83.697 55.723 ;
     RECT  6.408 55.723 84.402 55.823 ;
     RECT  6.408 55.823 83.697 56.129 ;
     RECT  2.304 55.517 5.49 56.299 ;
     RECT  6.408 56.129 79.182 56.299 ;
     RECT  2.304 56.299 79.182 56.731 ;
     RECT  79.92 56.129 83.697 56.869 ;
     RECT  79.92 56.869 84.402 56.909 ;
     RECT  2.268 56.731 79.182 57.065 ;
     RECT  2.304 57.065 79.182 57.581 ;
     RECT  79.92 56.909 83.697 57.991 ;
     RECT  84.924 57.991 84.942 58.061 ;
     RECT  79.164 57.581 79.182 58.123 ;
     RECT  79.92 57.991 83.97 58.123 ;
     RECT  79.164 58.123 83.97 58.145 ;
     RECT  2.304 57.581 78.354 58.693 ;
     RECT  79.164 58.145 83.697 58.693 ;
     RECT  85.5 59.233 85.518 59.357 ;
     RECT  2.304 58.693 83.697 60.475 ;
     RECT  2.304 60.475 84.402 60.683 ;
     RECT  2.304 60.683 83.697 60.845 ;
     RECT  2.34 60.845 83.697 61.735 ;
     RECT  2.34 61.735 84.402 61.805 ;
     RECT  2.34 61.805 83.697 62.059 ;
     RECT  2.304 62.059 83.697 62.923 ;
     RECT  2.304 62.923 84.402 63.113 ;
     RECT  2.304 63.113 83.697 63.211 ;
     RECT  2.268 63.211 83.697 63.545 ;
     RECT  2.304 63.545 83.697 64.075 ;
     RECT  2.304 64.075 84.402 64.193 ;
     RECT  0.54 64.165 0.558 64.685 ;
     RECT  2.304 64.193 83.697 65.371 ;
     RECT  2.304 65.371 83.826 65.543 ;
     RECT  0.216 66.379 0.234 66.509 ;
     RECT  2.304 65.543 83.697 66.523 ;
     RECT  2.304 66.523 83.826 66.623 ;
     RECT  0.252 66.955 0.27 67.085 ;
     RECT  2.304 66.623 83.697 67.531 ;
     RECT  2.268 67.531 83.697 67.667 ;
     RECT  2.304 67.667 83.697 67.819 ;
     RECT  2.304 67.819 84.402 67.973 ;
     RECT  2.304 67.973 83.697 68.953 ;
     RECT  2.304 68.953 84.402 69.005 ;
     RECT  2.304 69.005 83.697 69.115 ;
     RECT  2.268 69.115 83.697 69.791 ;
     RECT  2.304 69.791 83.697 70.033 ;
     RECT  85.5 70.069 85.518 70.157 ;
     RECT  2.304 70.033 83.718 70.169 ;
     RECT  2.304 70.169 83.697 70.699 ;
     RECT  2.268 70.699 83.697 71.105 ;
     RECT  2.304 71.105 83.697 71.339 ;
     RECT  79.848 71.339 83.697 71.419 ;
     RECT  79.848 71.419 84.402 71.483 ;
     RECT  2.304 71.339 78.966 72.283 ;
     RECT  2.268 72.283 78.966 72.301 ;
     RECT  79.848 71.483 83.697 72.301 ;
     RECT  2.268 72.301 83.697 72.455 ;
     RECT  2.304 72.455 83.697 72.535 ;
     RECT  2.304 72.535 84.402 72.605 ;
     RECT  0.252 72.763 0.27 73.469 ;
     RECT  2.304 72.605 83.697 73.867 ;
     RECT  2.304 73.867 84.402 73.913 ;
     RECT  2.304 73.913 83.697 74.443 ;
     RECT  2.268 74.443 83.697 74.615 ;
     RECT  2.304 74.615 83.697 74.849 ;
     RECT  3.564 74.849 83.697 74.965 ;
     RECT  3.564 74.965 84.402 75.053 ;
     RECT  2.304 74.849 2.754 75.691 ;
     RECT  3.564 75.053 83.697 75.691 ;
     RECT  2.304 75.691 83.697 76.171 ;
     RECT  2.304 76.171 83.826 76.271 ;
     RECT  2.304 76.271 83.697 77.179 ;
     RECT  84.924 77.395 84.942 77.501 ;
     RECT  2.268 77.179 83.697 78.125 ;
     RECT  2.304 78.125 83.697 78.511 ;
     RECT  2.304 78.511 84.402 78.653 ;
     RECT  2.304 78.653 83.79 78.701 ;
     RECT  0.216 79.213 0.234 79.373 ;
     RECT  2.304 78.701 83.697 79.745 ;
     RECT  2.304 79.745 2.697 79.915 ;
     RECT  3.42 79.745 83.697 79.915 ;
     RECT  3.42 79.915 84.402 80.123 ;
     RECT  3.42 80.123 83.697 81.067 ;
     RECT  2.268 79.915 2.697 81.095 ;
     RECT  2.304 81.095 2.697 81.139 ;
     RECT  3.42 81.067 84.402 81.139 ;
     RECT  2.304 81.139 84.402 81.203 ;
     RECT  2.304 81.203 83.697 82.219 ;
     RECT  2.304 82.219 83.826 82.481 ;
     RECT  2.304 82.481 83.697 82.651 ;
     RECT  84.924 83.515 84.942 83.561 ;
     RECT  2.268 82.651 83.697 83.867 ;
     RECT  2.304 83.867 83.697 84.667 ;
     RECT  2.304 84.667 84.402 84.911 ;
     RECT  2.304 84.911 83.934 85.243 ;
     RECT  2.268 85.243 83.934 85.523 ;
     RECT  2.304 85.523 83.934 85.957 ;
     RECT  2.304 85.957 84.402 85.997 ;
     RECT  84.924 87.115 84.942 87.413 ;
     RECT  2.304 85.997 83.697 87.979 ;
     RECT  2.268 87.979 83.697 88.267 ;
     RECT  2.268 88.267 84.402 88.385 ;
     RECT  2.304 88.385 84.402 88.421 ;
     RECT  2.304 88.421 83.697 89.563 ;
     RECT  2.304 89.563 83.826 89.843 ;
     RECT  2.304 89.843 83.697 90.041 ;
     RECT  82.728 90.041 83.697 90.715 ;
     RECT  82.728 90.715 84.402 90.851 ;
     RECT  2.304 90.041 81.954 91.723 ;
     RECT  2.268 91.723 81.954 91.895 ;
     RECT  82.728 90.851 83.697 91.975 ;
     RECT  82.728 91.975 84.402 92.045 ;
     RECT  2.304 91.895 81.954 92.395 ;
     RECT  82.728 92.045 83.754 92.395 ;
     RECT  2.304 92.395 83.754 92.435 ;
     RECT  82.728 92.435 83.754 92.741 ;
     RECT  2.304 92.435 81.954 93.451 ;
     RECT  82.728 92.741 83.697 93.451 ;
     RECT  85.5 93.163 85.518 93.623 ;
     RECT  2.304 93.451 83.697 93.785 ;
     RECT  82.728 93.785 83.697 94.315 ;
     RECT  82.728 94.315 84.402 94.433 ;
     RECT  2.304 93.785 81.954 95.521 ;
     RECT  82.728 94.433 83.697 95.611 ;
     RECT  2.268 95.521 81.954 95.645 ;
     RECT  2.304 95.645 81.954 95.659 ;
     RECT  82.728 95.611 84.402 95.659 ;
     RECT  2.304 95.659 84.402 95.711 ;
     RECT  2.304 95.711 83.697 95.945 ;
     RECT  2.304 95.945 81.954 96.763 ;
     RECT  82.728 95.945 83.697 96.763 ;
     RECT  2.304 96.763 84.402 96.863 ;
     RECT  2.304 96.863 83.697 97.439 ;
     RECT  0.216 97.771 0.234 97.901 ;
     RECT  82.728 97.439 83.697 98.059 ;
     RECT  82.728 98.059 84.402 98.213 ;
     RECT  82.728 98.213 83.697 98.419 ;
     RECT  82.692 98.419 83.697 98.519 ;
     RECT  84.924 99.157 84.942 99.245 ;
     RECT  2.304 97.439 81.954 99.499 ;
     RECT  82.728 98.519 83.697 99.499 ;
     RECT  0.252 99.547 0.27 99.677 ;
     RECT  2.304 99.499 83.697 99.725 ;
     RECT  2.304 99.725 81.954 99.931 ;
     RECT  82.728 99.725 83.697 100.363 ;
     RECT  2.268 99.931 81.954 100.607 ;
     RECT  82.728 100.363 84.402 100.643 ;
     RECT  2.304 100.607 81.954 100.769 ;
     RECT  2.304 100.769 2.697 101.695 ;
     RECT  3.42 100.769 81.954 101.695 ;
     RECT  84.888 101.659 84.906 101.723 ;
     RECT  2.304 101.695 81.954 102.091 ;
     RECT  2.268 102.091 81.954 102.155 ;
     RECT  2.304 102.155 81.954 102.541 ;
     RECT  82.728 100.643 83.697 102.541 ;
     RECT  84.924 102.775 84.942 102.845 ;
     RECT  84.888 104.107 84.906 104.153 ;
     RECT  2.304 102.541 83.697 105.259 ;
     RECT  85.5 105.241 85.518 105.293 ;
     RECT  2.268 105.259 83.697 105.395 ;
     RECT  2.304 105.395 83.697 106.411 ;
     RECT  2.268 106.411 84.402 106.583 ;
     RECT  2.268 106.583 83.697 107.015 ;
     RECT  2.304 107.015 83.697 107.707 ;
     RECT  0.252 107.611 0.27 107.741 ;
     RECT  2.304 107.707 84.402 107.933 ;
     RECT  2.304 107.933 83.697 107.995 ;
     RECT  2.268 107.995 83.697 108.095 ;
     RECT  2.304 108.095 83.697 108.859 ;
     RECT  2.304 108.859 83.826 109.013 ;
     RECT  2.304 109.013 83.697 109.921 ;
     RECT  2.304 109.921 83.754 110.155 ;
     RECT  2.304 110.155 84.402 110.363 ;
     RECT  2.304 110.363 83.697 111.307 ;
     RECT  2.304 111.307 84.402 111.443 ;
     RECT  2.304 111.443 83.697 112.459 ;
     RECT  2.304 112.459 84.402 112.523 ;
     RECT  2.304 112.523 83.697 113.495 ;
     RECT  2.34 113.495 83.697 113.755 ;
     RECT  2.34 113.755 83.826 113.873 ;
     RECT  2.34 113.873 83.697 114.475 ;
     RECT  2.304 114.475 83.697 114.907 ;
     RECT  2.304 114.907 84.402 114.953 ;
     RECT  2.304 114.953 83.697 115.385 ;
     RECT  2.304 115.385 2.79 116.131 ;
     RECT  3.564 115.385 83.697 116.131 ;
     RECT  84.924 116.197 84.942 116.237 ;
     RECT  2.304 116.131 83.697 117.349 ;
     RECT  2.304 117.349 84.402 117.389 ;
     RECT  2.304 117.389 83.697 118.085 ;
     RECT  2.304 118.085 2.934 118.319 ;
     RECT  3.744 118.085 83.697 118.507 ;
     RECT  3.744 118.507 84.402 118.733 ;
     RECT  2.304 118.319 2.754 119.209 ;
     RECT  3.744 118.733 83.697 119.209 ;
     RECT  2.304 119.209 83.697 119.371 ;
     RECT  2.268 119.371 83.697 119.435 ;
     RECT  2.304 119.435 83.697 119.803 ;
     RECT  0.396 120.091 0.414 120.269 ;
     RECT  2.304 119.803 83.826 120.379 ;
     RECT  2.268 120.379 83.826 120.515 ;
     RECT  2.304 120.515 83.826 120.721 ;
     RECT  2.304 120.721 84.042 120.989 ;
     RECT  2.304 120.989 84.006 121.019 ;
     RECT  2.304 121.019 83.754 121.055 ;
     RECT  3.42 121.055 83.697 121.289 ;
     RECT  2.304 121.055 2.697 121.531 ;
     RECT  3.456 121.289 83.697 121.559 ;
     RECT  2.268 121.531 2.697 121.703 ;
     RECT  39.888 121.559 65.538 121.865 ;
     RECT  66.42 121.559 83.697 121.945 ;
     RECT  66.42 121.945 84.114 121.997 ;
     RECT  2.304 121.703 2.697 122.251 ;
     RECT  3.456 121.559 38.934 122.251 ;
     RECT  55.368 121.865 65.538 122.341 ;
     RECT  66.42 121.997 83.862 122.341 ;
     RECT  55.368 122.341 83.862 122.369 ;
     RECT  2.304 122.251 38.934 122.539 ;
     RECT  2.268 122.539 38.934 122.747 ;
     RECT  39.888 121.865 54.522 122.791 ;
     RECT  39.708 122.791 54.522 122.881 ;
     RECT  2.304 122.747 38.934 122.909 ;
     RECT  39.672 122.881 54.522 122.989 ;
     RECT  55.368 122.369 83.697 122.989 ;
     RECT  3.744 122.909 38.934 123.089 ;
     RECT  39.672 122.989 83.697 123.151 ;
     RECT  39.276 123.151 83.697 123.293 ;
     RECT  39.636 123.293 83.697 123.403 ;
     RECT  39.636 123.403 84.114 123.485 ;
     RECT  3.744 123.089 38.178 123.629 ;
     RECT  3.744 123.629 30.906 123.719 ;
     RECT  42.588 123.485 84.114 123.719 ;
     RECT  3.744 123.719 29.862 124.025 ;
     RECT  3.744 124.025 17.118 124.069 ;
     RECT  2.304 122.909 2.862 124.141 ;
     RECT  3.6 124.069 17.118 124.141 ;
     RECT  17.856 124.025 29.862 124.169 ;
     RECT  2.304 124.141 17.118 124.205 ;
     RECT  31.644 123.629 38.178 124.219 ;
     RECT  2.304 124.205 16.866 124.259 ;
     RECT  42.588 123.719 83.697 124.259 ;
     RECT  39.672 123.485 41.634 124.267 ;
     RECT  31.644 124.219 38.646 124.303 ;
     RECT  31.644 124.303 38.898 124.339 ;
     RECT  39.672 124.267 41.85 124.339 ;
     RECT  42.588 124.259 81.99 124.339 ;
     RECT  30.6 123.719 30.906 124.375 ;
     RECT  31.644 124.339 81.99 124.375 ;
     RECT  30.6 124.375 81.99 124.439 ;
     RECT  30.6 124.439 81.918 124.541 ;
     RECT  83.124 124.259 83.697 124.555 ;
     RECT  17.928 124.169 29.862 124.565 ;
     RECT  83.124 124.555 84.114 124.565 ;
     RECT  2.304 124.259 11.538 124.601 ;
     RECT  23.688 124.565 29.862 124.609 ;
     RECT  30.6 124.541 48.51 124.609 ;
     RECT  17.928 124.565 22.95 124.799 ;
     RECT  49.248 124.541 81.918 125.069 ;
     RECT  83.415 124.565 84.114 125.069 ;
     RECT  17.928 124.799 22.842 125.077 ;
     RECT  83.415 125.069 83.862 125.105 ;
     RECT  12.276 124.259 16.686 125.113 ;
     RECT  17.46 125.077 22.842 125.113 ;
     RECT  12.276 125.113 22.842 125.185 ;
     RECT  2.304 124.601 11.322 125.213 ;
     RECT  50.184 125.069 81.918 125.221 ;
     RECT  2.415 125.213 11.322 125.347 ;
     RECT  23.688 124.609 48.51 125.347 ;
     RECT  23.616 125.347 48.51 125.419 ;
     RECT  49.248 125.069 49.446 125.419 ;
     RECT  2.415 125.347 11.394 125.519 ;
     RECT  12.168 125.185 22.842 125.581 ;
     RECT  23.616 125.419 49.446 125.581 ;
     RECT  4.14 125.519 4.41 125.609 ;
     RECT  5.436 125.519 11.394 125.609 ;
     RECT  2.415 125.519 3.042 125.645 ;
     RECT  12.168 125.581 49.446 125.645 ;
     RECT  12.348 125.645 49.446 125.693 ;
     RECT  4.14 125.609 4.158 125.753 ;
     RECT  5.544 125.609 11.394 125.887 ;
     RECT  12.456 125.693 49.446 125.887 ;
     RECT  50.184 125.221 82.17 125.887 ;
     RECT  5.544 125.887 11.538 125.915 ;
     RECT  12.456 125.887 82.17 125.923 ;
     RECT  12.456 125.923 82.278 126.029 ;
     RECT  76.536 126.029 82.278 126.499 ;
     RECT  5.688 125.915 11.538 126.535 ;
     RECT  12.456 126.029 75.798 126.535 ;
     RECT  4.5 126.535 4.518 126.805 ;
     RECT  5.688 126.535 75.798 126.805 ;
     RECT  4.5 126.805 75.798 126.841 ;
     RECT  76.536 126.499 82.638 126.841 ;
     RECT  4.5 126.841 82.638 126.931 ;
     RECT  4.428 126.931 82.638 126.959 ;
     RECT  4.428 126.959 69.93 126.989 ;
     RECT  4.572 126.989 69.93 127.031 ;
     RECT  77.724 126.959 82.566 127.031 ;
     RECT  6.336 127.031 44.694 127.067 ;
     RECT  8.892 127.067 44.694 127.085 ;
     RECT  6.336 127.067 8.154 127.103 ;
     RECT  79.812 127.031 82.566 127.103 ;
     RECT  45.504 127.031 69.93 127.181 ;
     RECT  2.415 125.645 2.697 127.187 ;
     RECT  77.724 127.031 79.074 127.187 ;
     RECT  83.415 125.105 83.697 127.187 ;
     RECT  4.572 127.031 5.562 127.229 ;
     RECT  6.48 127.103 8.154 127.229 ;
     RECT  8.892 127.085 9.054 127.229 ;
     RECT  9.792 127.085 11.322 127.229 ;
     RECT  12.132 127.085 14.094 127.229 ;
     RECT  15.12 127.085 44.694 127.229 ;
     RECT  45.504 127.181 53.838 127.229 ;
     RECT  54.72 127.181 69.93 127.229 ;
     RECT  70.704 126.959 76.554 127.229 ;
     RECT  77.724 127.187 78.105 127.229 ;
     RECT  78.876 127.187 79.074 127.229 ;
     RECT  79.812 127.103 80.334 127.229 ;
     RECT  81.648 127.103 82.566 127.229 ;
     RECT  4.572 127.229 4.95 127.265 ;
     RECT  11.052 127.229 11.07 127.265 ;
     RECT  12.132 127.229 12.402 127.265 ;
     RECT  30.672 127.229 32.994 127.265 ;
     RECT  38.808 127.229 44.658 127.265 ;
     RECT  54.72 127.229 54.738 127.265 ;
     RECT  75.24 127.229 76.554 127.265 ;
     RECT  81.648 127.229 81.666 127.265 ;
     RECT  6.48 127.229 6.498 127.301 ;
     RECT  7.56 127.229 7.905 127.301 ;
     RECT  13.215 127.229 13.806 127.301 ;
     RECT  19.728 127.229 21.042 127.301 ;
     RECT  38.808 127.265 43.326 127.301 ;
     RECT  45.576 127.229 48.618 127.301 ;
     RECT  55.836 127.229 57.366 127.301 ;
     RECT  58.14 127.229 62.226 127.301 ;
     RECT  63.144 127.229 67.842 127.301 ;
     RECT  72.615 127.229 72.954 127.301 ;
     RECT  73.764 127.229 74.214 127.301 ;
     RECT  75.24 127.265 76.518 127.301 ;
     RECT  22.392 127.229 26.874 127.373 ;
     RECT  4.932 127.265 4.95 127.409 ;
     RECT  8.892 127.229 8.91 127.409 ;
     RECT  15.372 127.229 16.254 127.409 ;
     RECT  20.556 127.301 21.042 127.409 ;
     RECT  23.292 127.373 26.874 127.409 ;
     RECT  27.972 127.229 28.206 127.409 ;
     RECT  30.672 127.265 32.742 127.409 ;
     RECT  40.176 127.301 42.57 127.409 ;
     RECT  49.428 127.229 53.406 127.409 ;
     RECT  58.14 127.301 59.274 127.409 ;
     RECT  63.144 127.301 64.962 127.409 ;
     RECT  65.916 127.301 67.842 127.409 ;
     RECT  69.048 127.229 69.93 127.409 ;
     RECT  75.816 127.301 76.518 127.409 ;
     RECT  79.812 127.229 79.83 127.409 ;
     RECT  43.308 127.301 43.326 127.421 ;
     RECT  2.415 127.187 2.505 127.457 ;
     RECT  7.815 127.301 7.905 127.457 ;
     RECT  13.215 127.301 13.305 127.457 ;
     RECT  23.292 127.409 26.622 127.457 ;
     RECT  29.268 127.229 29.505 127.457 ;
     RECT  33.804 127.229 34.905 127.457 ;
     RECT  45.615 127.301 48.618 127.457 ;
     RECT  60.3 127.301 62.226 127.457 ;
     RECT  72.615 127.301 72.705 127.457 ;
     RECT  78.015 127.229 78.105 127.457 ;
     RECT  83.415 127.187 83.505 127.457 ;
     RECT  17.496 127.229 18.774 127.613 ;
     RECT  33.804 127.457 34.722 127.613 ;
     RECT  49.428 127.409 52.11 127.613 ;
     RECT  62.136 127.457 62.226 127.613 ;
     RECT  65.916 127.409 67.734 127.613 ;
     RECT  23.292 127.457 23.31 127.661 ;
     RECT  49.428 127.613 50.814 127.661 ;
     RECT  16.236 127.409 16.254 127.709 ;
     RECT  17.496 127.613 18.45 127.709 ;
     RECT  20.664 127.409 20.682 127.709 ;
     RECT  24.336 127.457 26.622 127.709 ;
     RECT  28.188 127.409 28.206 127.709 ;
     RECT  32.22 127.409 32.742 127.709 ;
     RECT  33.804 127.613 34.542 127.709 ;
     RECT  36.72 127.229 37.926 127.709 ;
     RECT  40.176 127.409 40.77 127.709 ;
     RECT  45.756 127.457 48.618 127.709 ;
     RECT  50.616 127.661 50.814 127.709 ;
     RECT  52.992 127.409 53.406 127.709 ;
     RECT  56.052 127.301 56.574 127.709 ;
     RECT  58.356 127.409 59.058 127.709 ;
     RECT  60.3 127.457 61.182 127.709 ;
     RECT  65.916 127.613 66.654 127.709 ;
     RECT  69.048 127.409 69.066 127.709 ;
     RECT  69.912 127.409 69.93 127.709 ;
     RECT  22.392 127.373 22.41 128.237 ;
     RECT  35.784 127.229 35.802 128.237 ;
     RECT  36.72 127.709 36.99 128.237 ;
     RECT  37.908 127.709 37.926 128.237 ;
     RECT  38.808 127.301 39.294 128.237 ;
     RECT  45.756 127.709 47.178 128.237 ;
     RECT  48.132 127.709 48.618 128.237 ;
     RECT  49.428 127.661 49.446 128.237 ;
     RECT  51.66 127.613 52.11 128.237 ;
     RECT  15.372 127.409 15.39 128.285 ;
     RECT  66.636 127.709 66.654 128.285 ;
     RECT  76.5 127.409 76.518 128.285 ;
     RECT  19.728 127.301 19.782 128.765 ;
     RECT  12.132 127.265 12.15 128.813 ;
     RECT  10.116 127.229 10.134 128.861 ;
     RECT  18.072 127.709 18.09 128.861 ;
     RECT  19.764 128.765 19.782 128.861 ;
     RECT  24.336 127.709 25.038 128.861 ;
     RECT  26.1 127.709 26.622 128.861 ;
     RECT  29.268 127.457 29.286 128.861 ;
     RECT  30.672 127.409 30.69 128.861 ;
     RECT  34.524 127.709 34.542 128.861 ;
     RECT  36.972 128.237 36.99 128.861 ;
     RECT  40.176 127.709 40.194 128.861 ;
     RECT  41.868 127.409 42.57 128.861 ;
     RECT  44.244 127.265 44.658 128.861 ;
     RECT  46.44 128.237 46.458 128.861 ;
     RECT  52.092 128.237 52.11 128.861 ;
     RECT  52.992 127.709 53.01 128.861 ;
     RECT  56.052 127.709 56.07 128.861 ;
     RECT  57.348 127.301 57.366 128.861 ;
     RECT  58.356 127.709 58.374 128.861 ;
     RECT  60.3 127.709 60.858 128.861 ;
     RECT  62.208 127.613 62.226 128.861 ;
     RECT  63.144 127.409 63.162 128.861 ;
     RECT  64.26 127.409 64.278 128.861 ;
     RECT  67.716 127.613 67.734 128.861 ;
     RECT  74.232 129.355 74.25 129.485 ;
    LAYER M4 ;
     RECT  0.156 4.32 2.408 125.16 ;
     RECT  2.408 2.148 2.512 127.452 ;
     RECT  2.512 2.418 2.704 127.182 ;
     RECT  2.704 4.464 2.765 6.36 ;
     RECT  2.704 13.824 2.765 13.848 ;
     RECT  2.704 37.008 2.765 39.432 ;
     RECT  2.704 45.504 2.765 46.824 ;
     RECT  2.704 55.728 2.765 55.752 ;
     RECT  2.704 90.288 2.765 91.896 ;
     RECT  2.704 94.848 2.765 94.872 ;
     RECT  2.704 97.344 2.765 99.72 ;
     RECT  2.704 110.016 2.765 110.28 ;
     RECT  2.704 113.76 2.765 115.224 ;
     RECT  2.704 116.496 2.765 117.816 ;
     RECT  2.704 119.52 2.765 120.84 ;
     RECT  2.765 4.464 2.801 6.024 ;
     RECT  2.704 101.424 2.801 107.64 ;
     RECT  2.765 114.528 2.801 115.224 ;
     RECT  2.765 116.832 2.801 117.816 ;
     RECT  2.704 122.976 2.801 123.288 ;
     RECT  2.704 11.664 2.837 11.688 ;
     RECT  2.704 16.272 2.845 28.536 ;
     RECT  2.704 56.928 2.845 68.28 ;
     RECT  2.845 56.928 2.867 68.088 ;
     RECT  2.704 48.672 2.873 48.696 ;
     RECT  2.704 7.92 2.909 7.944 ;
     RECT  2.801 101.424 2.909 106.584 ;
     RECT  2.801 4.56 2.981 6.024 ;
     RECT  2.704 10.08 2.981 10.152 ;
     RECT  2.765 45.504 2.981 46.536 ;
     RECT  2.765 97.872 2.981 99.72 ;
     RECT  2.801 114.528 2.981 114.936 ;
     RECT  2.765 90.672 3.017 91.896 ;
     RECT  2.765 120.24 3.017 120.84 ;
     RECT  2.704 69.504 3.089 78.648 ;
     RECT  2.704 111.312 3.161 112.776 ;
     RECT  2.981 4.56 3.197 5.064 ;
     RECT  3.017 91.728 3.197 91.896 ;
     RECT  2.801 107.616 3.197 107.64 ;
     RECT  3.161 111.312 3.197 111.336 ;
     RECT  3.161 112.752 3.197 112.776 ;
     RECT  2.801 116.832 3.233 117.384 ;
     RECT  2.981 45.792 3.305 46.536 ;
     RECT  3.197 4.56 3.413 5.016 ;
     RECT  2.765 38.544 3.443 39.432 ;
     RECT  2.704 84.576 3.692 89.256 ;
     RECT  2.704 92.928 3.701 93.48 ;
     RECT  2.765 37.008 3.733 37.032 ;
     RECT  2.704 43.632 3.733 44.184 ;
     RECT  2.704 81.36 3.733 81.384 ;
     RECT  3.443 39.408 3.74 39.432 ;
     RECT  2.704 40.992 3.74 42.36 ;
     RECT  3.74 14.352 3.769 14.376 ;
     RECT  2.704 29.616 3.769 32.952 ;
     RECT  3.733 43.44 3.769 44.184 ;
     RECT  3.733 81.024 3.769 81.384 ;
     RECT  2.704 83.28 3.769 83.304 ;
     RECT  2.845 16.272 3.781 17.208 ;
     RECT  2.704 34.8 3.805 35.736 ;
     RECT  3.733 37.008 3.805 37.56 ;
     RECT  3.305 46.176 3.805 46.536 ;
     RECT  2.704 50.736 3.805 53.256 ;
     RECT  3.769 14.016 3.827 14.376 ;
     RECT  2.845 18.288 3.836 28.536 ;
     RECT  3.769 29.616 3.836 33.144 ;
     RECT  3.805 50.256 3.841 53.256 ;
     RECT  3.692 84.576 3.841 89.688 ;
     RECT  3.017 90.672 3.841 90.696 ;
     RECT  3.841 50.256 3.877 53.544 ;
     RECT  2.867 57.12 3.877 68.088 ;
     RECT  3.697 79.68 3.877 79.704 ;
     RECT  3.769 81.024 3.877 83.304 ;
     RECT  2.765 110.208 3.877 110.28 ;
     RECT  3.413 4.56 3.917 4.872 ;
     RECT  3.781 15.408 3.925 17.208 ;
     RECT  3.836 18.288 3.925 33.144 ;
     RECT  3.841 122.592 3.925 122.616 ;
     RECT  3.74 39.408 3.949 42.36 ;
     RECT  3.769 43.44 3.949 44.376 ;
     RECT  3.877 49.392 3.949 53.544 ;
     RECT  2.704 54.624 3.949 54.648 ;
     RECT  3.769 96.864 3.949 96.888 ;
     RECT  3.017 120.24 3.971 120.264 ;
     RECT  3.925 122.064 4.025 122.616 ;
     RECT  3.769 12.912 4.057 12.936 ;
     RECT  3.827 14.016 4.057 14.04 ;
     RECT  2.909 101.424 4.057 105.48 ;
     RECT  2.981 10.128 4.061 10.152 ;
     RECT  3.925 15.408 4.069 33.144 ;
     RECT  3.841 84.576 4.076 90.696 ;
     RECT  3.949 49.392 4.093 54.648 ;
     RECT  3.089 69.504 4.117 78.6 ;
     RECT  4.093 48.768 4.129 54.648 ;
     RECT  4.076 84.528 4.129 90.696 ;
     RECT  2.981 98.592 4.129 99.72 ;
     RECT  4.129 98.592 4.165 100.104 ;
     RECT  4.057 101.328 4.165 105.48 ;
     RECT  2.909 106.56 4.165 106.584 ;
     RECT  3.805 34.8 4.201 37.56 ;
     RECT  3.949 96.864 4.201 97.272 ;
     RECT  3.233 116.832 4.201 116.856 ;
     RECT  4.129 48.768 4.237 55.32 ;
     RECT  3.877 57.12 4.237 68.472 ;
     RECT  3.877 110.208 4.237 110.568 ;
     RECT  3.805 46.176 4.268 46.776 ;
     RECT  4.237 48.768 4.268 68.472 ;
     RECT  4.117 69.504 4.268 78.696 ;
     RECT  3.701 92.928 4.277 92.952 ;
     RECT  3.877 79.68 4.281 83.304 ;
     RECT  4.129 84.288 4.281 90.696 ;
     RECT  4.165 98.592 4.345 106.584 ;
     RECT  4.069 15.408 4.381 33.624 ;
     RECT  4.201 34.608 4.381 37.56 ;
     RECT  4.268 46.176 4.381 47.256 ;
     RECT  3.949 39.408 4.417 45 ;
     RECT  4.381 46.176 4.417 47.736 ;
     RECT  3.949 94.56 4.417 94.68 ;
     RECT  4.057 12.912 4.453 14.04 ;
     RECT  4.237 109.92 4.489 110.568 ;
     RECT  4.201 116.832 4.497 116.952 ;
     RECT  4.412 126.96 4.499 126.984 ;
     RECT  4.268 48.768 4.501 78.696 ;
     RECT  4.281 79.68 4.501 90.696 ;
     RECT  4.417 94.56 4.525 94.968 ;
     RECT  4.201 96.72 4.525 97.272 ;
     RECT  4.345 98.592 4.525 106.968 ;
     RECT  2.704 108.72 4.525 108.744 ;
     RECT  4.489 109.92 4.525 110.616 ;
     RECT  4.417 39.408 4.529 47.736 ;
     RECT  4.525 94.416 4.561 94.968 ;
     RECT  4.525 108.48 4.561 108.744 ;
     RECT  3.917 4.848 4.565 4.872 ;
     RECT  4.501 48.768 4.597 90.696 ;
     RECT  3.197 91.728 4.597 91.752 ;
     RECT  4.025 122.064 4.633 122.088 ;
     RECT  4.525 118.992 4.705 119.016 ;
     RECT  4.381 15.408 4.741 37.56 ;
     RECT  4.453 12.336 4.745 14.04 ;
     RECT  4.525 96.72 4.813 106.968 ;
     RECT  4.561 94.416 4.849 95.112 ;
     RECT  4.813 96.48 4.849 106.968 ;
     RECT  4.497 116.16 4.957 116.952 ;
     RECT  4.597 48.768 5.029 91.752 ;
     RECT  4.345 120.864 5.029 120.888 ;
     RECT  4.633 121.968 5.029 122.088 ;
     RECT  4.117 125.472 5.077 125.496 ;
     RECT  4.561 108.288 5.101 108.744 ;
     RECT  4.525 109.824 5.101 111.48 ;
     RECT  5.029 121.968 5.101 122.28 ;
     RECT  4.849 94.416 5.173 106.968 ;
     RECT  4.741 15.408 5.177 38.136 ;
     RECT  5.101 108.288 5.209 111.48 ;
     RECT  5.173 112.464 5.209 112.488 ;
     RECT  4.529 39.504 5.249 47.736 ;
     RECT  5.029 120.816 5.276 120.888 ;
     RECT  5.276 120.768 5.281 120.888 ;
     RECT  5.101 121.968 5.281 123 ;
     RECT  5.209 11.328 5.353 11.352 ;
     RECT  4.705 118.992 5.353 119.208 ;
     RECT  5.281 120.768 5.353 123 ;
     RECT  2.981 114.528 5.365 114.552 ;
     RECT  5.077 124.896 5.42 125.496 ;
     RECT  4.957 116.16 5.459 117.528 ;
     RECT  5.173 94.416 5.461 107.064 ;
     RECT  5.209 108.288 5.461 112.488 ;
     RECT  5.353 118.992 5.461 123 ;
     RECT  4.844 126.864 5.461 126.888 ;
     RECT  5.249 39.504 5.497 43.896 ;
     RECT  5.461 94.416 5.533 112.488 ;
     RECT  5.42 124.704 5.533 125.496 ;
     RECT  4.273 1.728 5.545 1.752 ;
     RECT  5.245 15.024 5.569 15.048 ;
     RECT  5.533 94.272 5.569 113.208 ;
     RECT  5.365 114.528 5.569 115.176 ;
     RECT  4.745 12.336 5.573 13.704 ;
     RECT  5.029 48.768 5.597 92.856 ;
     RECT  5.569 94.272 5.597 115.176 ;
     RECT  5.101 6.24 5.605 6.264 ;
     RECT  5.137 8.016 5.605 8.04 ;
     RECT  4.957 9.36 5.605 9.384 ;
     RECT  5.353 10.896 5.605 11.352 ;
     RECT  5.597 48.768 5.609 115.176 ;
     RECT  5.605 9.36 5.641 11.688 ;
     RECT  5.459 117.408 5.677 117.528 ;
     RECT  5.461 118.704 5.677 123.624 ;
     RECT  5.533 124.704 5.677 125.64 ;
     RECT  5.677 117.408 5.747 125.64 ;
     RECT  5.177 16.128 5.749 38.136 ;
     RECT  5.497 39.312 5.749 43.896 ;
     RECT  5.609 74.112 5.785 115.176 ;
     RECT  5.459 116.16 5.785 116.184 ;
     RECT  5.605 5.904 5.821 8.04 ;
     RECT  5.641 9.024 5.821 11.688 ;
     RECT  5.747 117.408 5.825 125.496 ;
     RECT  5.749 16.128 5.891 43.896 ;
     RECT  5.249 44.976 5.929 47.736 ;
     RECT  5.609 48.768 5.929 73.08 ;
     RECT  5.891 16.128 5.939 16.152 ;
     RECT  5.891 17.136 6.005 43.896 ;
     RECT  5.573 12.768 6.253 13.704 ;
     RECT  5.569 14.688 6.253 15.048 ;
     RECT  5.821 5.904 6.275 11.688 ;
     RECT  6.253 0.576 6.337 0.6 ;
     RECT  6.005 17.328 6.433 43.896 ;
     RECT  5.929 44.976 6.433 73.08 ;
     RECT  6.253 12.768 6.505 15.048 ;
     RECT  5.785 74.112 6.577 116.184 ;
     RECT  5.461 126.864 6.677 126.984 ;
     RECT  6.577 74.112 6.793 116.28 ;
     RECT  5.825 117.456 6.793 125.496 ;
     RECT  5.425 3.312 6.833 3.336 ;
     RECT  6.793 74.112 6.86 125.496 ;
     RECT  6.677 126.48 6.86 126.984 ;
     RECT  6.275 5.904 6.937 9.528 ;
     RECT  6.433 17.328 7.009 73.08 ;
     RECT  7.009 17.136 7.052 73.08 ;
     RECT  6.86 74.112 7.052 126.984 ;
     RECT  6.649 4.368 7.081 4.392 ;
     RECT  6.937 5.76 7.081 9.528 ;
     RECT  6.505 12.768 7.117 15.72 ;
     RECT  7.052 17.136 7.141 126.984 ;
     RECT  6.275 10.512 7.261 11.688 ;
     RECT  7.117 12.768 7.261 15.816 ;
     RECT  7.081 4.368 7.405 9.528 ;
     RECT  7.261 10.512 7.405 15.816 ;
     RECT  7.141 17.136 7.621 127.032 ;
     RECT  7.405 4.368 7.765 15.816 ;
     RECT  6.541 1.728 7.808 1.752 ;
     RECT  7.765 4.368 7.808 16.008 ;
     RECT  7.621 17.136 7.808 127.128 ;
     RECT  7.808 1.728 8.005 127.452 ;
     RECT  8.005 1.728 8.104 127.56 ;
     RECT  8.104 3.792 8.237 127.56 ;
     RECT  8.237 5.664 8.341 127.56 ;
     RECT  8.341 5.664 8.483 127.656 ;
     RECT  8.104 1.728 8.669 2.712 ;
     RECT  8.669 1.728 8.917 2.28 ;
     RECT  8.483 5.664 8.993 126.984 ;
     RECT  8.917 1.104 9.347 2.28 ;
     RECT  8.993 126.96 9.445 126.984 ;
     RECT  9.347 1.728 9.635 2.28 ;
     RECT  9.445 126.96 9.781 127.08 ;
     RECT  8.237 3.792 9.889 3.816 ;
     RECT  9.889 3.792 9.973 4.536 ;
     RECT  8.993 5.664 9.997 125.976 ;
     RECT  9.973 3.792 10.037 3.816 ;
     RECT  9.877 128.832 10.145 128.856 ;
     RECT  9.781 126.96 10.259 127.128 ;
     RECT  10.259 126.96 10.469 127.08 ;
     RECT  9.997 5.088 10.741 125.976 ;
     RECT  10.469 126.96 10.741 126.984 ;
     RECT  9.635 1.728 10.933 1.8 ;
     RECT  10.213 3.408 11.077 3.432 ;
     RECT  10.741 5.088 11.189 126.984 ;
     RECT  11.077 3.408 11.317 4.008 ;
     RECT  11.189 5.136 11.363 126.984 ;
     RECT  10.933 1.728 11.411 2.28 ;
     RECT  11.317 3.312 11.441 4.008 ;
     RECT  11.363 5.184 11.689 126.984 ;
     RECT  11.689 5.184 11.773 127.08 ;
     RECT  11.773 5.184 11.837 126.984 ;
     RECT  11.441 3.312 12.049 3.528 ;
     RECT  12.049 2.832 12.133 3.528 ;
     RECT  12.013 0.576 12.179 0.6 ;
     RECT  12.121 128.784 12.205 128.808 ;
     RECT  12.481 0.192 12.755 0.216 ;
     RECT  11.837 5.712 13.021 126.984 ;
     RECT  11.411 1.728 13.208 1.752 ;
     RECT  12.133 3.408 13.208 3.528 ;
     RECT  13.021 5.712 13.208 127.128 ;
     RECT  13.208 1.728 13.312 127.452 ;
     RECT  13.312 1.728 13.504 127.182 ;
     RECT  13.429 128.784 13.619 128.808 ;
     RECT  13.504 5.088 13.673 5.112 ;
     RECT  13.504 6.624 14.243 127.128 ;
     RECT  13.504 3.696 14.533 3.72 ;
     RECT  14.533 3.12 14.712 3.72 ;
     RECT  14.712 3.12 14.713 4.248 ;
     RECT  13.504 1.728 14.771 1.8 ;
     RECT  14.713 2.832 14.819 4.248 ;
     RECT  14.819 3.12 14.821 4.248 ;
     RECT  14.821 3.12 14.825 4.728 ;
     RECT  14.825 3.696 15.005 4.728 ;
     RECT  15.005 3.696 15.113 4.248 ;
     RECT  15.361 128.256 15.635 128.28 ;
     RECT  14.243 6.624 15.685 127.08 ;
     RECT  15.113 4.224 15.905 4.248 ;
     RECT  15.685 6.432 16.021 127.08 ;
     RECT  16.021 6.432 16.265 127.704 ;
     RECT  16.265 6.432 16.549 127.128 ;
     RECT  15.98 5.184 16.801 5.208 ;
     RECT  16.549 6.384 16.801 127.128 ;
     RECT  16.801 5.184 17.093 127.128 ;
     RECT  17.093 5.184 17.317 126.6 ;
     RECT  17.804 3.84 17.893 3.864 ;
     RECT  17.317 5.184 17.893 126.504 ;
     RECT  17.797 128.832 18.101 128.856 ;
     RECT  14.771 1.728 18.181 1.752 ;
     RECT  17.989 2.832 18.181 2.856 ;
     RECT  18.181 1.728 18.349 2.856 ;
     RECT  17.893 3.84 18.349 126.504 ;
     RECT  17.365 127.68 18.461 127.704 ;
     RECT  18.349 1.728 18.608 126.504 ;
     RECT  18.608 1.728 18.785 127.608 ;
     RECT  18.785 1.728 18.904 127.182 ;
     RECT  18.904 1.728 19.397 127.128 ;
     RECT  19.669 128.832 19.717 128.856 ;
     RECT  19.717 128.736 19.793 128.856 ;
     RECT  19.793 128.736 20.147 128.76 ;
     RECT  19.397 1.728 20.297 126.552 ;
     RECT  20.533 127.68 20.693 127.704 ;
     RECT  20.297 2.256 20.965 126.552 ;
     RECT  20.965 2.256 21.347 127.128 ;
     RECT  21.347 2.688 21.665 127.128 ;
     RECT  21.665 2.688 21.779 126.504 ;
     RECT  21.779 2.736 21.989 126.504 ;
     RECT  21.989 3.936 22.067 126.504 ;
     RECT  22.237 0.576 22.403 0.6 ;
     RECT  22.337 128.208 22.421 128.232 ;
     RECT  22.067 4.512 23.033 126.504 ;
     RECT  23.221 127.632 23.321 127.656 ;
     RECT  23.173 0.192 23.411 0.216 ;
     RECT  21.989 2.736 23.557 2.76 ;
     RECT  23.033 5.856 23.653 126.504 ;
     RECT  23.557 2.736 23.797 3.336 ;
     RECT  23.033 4.512 23.797 4.728 ;
     RECT  22.645 1.728 24.008 1.752 ;
     RECT  23.797 2.736 24.008 4.728 ;
     RECT  23.653 5.856 24.008 127.452 ;
     RECT  24.008 1.728 24.112 127.452 ;
     RECT  23.965 0.576 24.131 0.6 ;
     RECT  24.112 1.728 24.304 127.182 ;
     RECT  24.304 5.088 24.604 126.888 ;
     RECT  24.304 1.728 25.229 3.48 ;
     RECT  25.229 2.208 25.297 3.48 ;
     RECT  25.297 2.208 25.427 4.008 ;
     RECT  25.381 127.68 25.468 127.704 ;
     RECT  24.604 5.088 25.477 126.504 ;
     RECT  25.427 2.208 26.029 3.432 ;
     RECT  25.477 4.56 26.065 126.504 ;
     RECT  26.029 2.208 26.195 3.336 ;
     RECT  24.085 128.832 26.633 128.856 ;
     RECT  26.195 2.208 26.657 2.904 ;
     RECT  26.677 128.88 26.963 128.904 ;
     RECT  26.065 4.752 27.109 126.504 ;
     RECT  27.109 4.752 27.353 127.128 ;
     RECT  27.353 4.752 27.452 126.504 ;
     RECT  27.452 4.656 27.781 126.504 ;
     RECT  26.657 1.728 27.923 2.904 ;
     RECT  27.781 4.512 28.213 126.504 ;
     RECT  28.021 127.68 28.217 127.704 ;
     RECT  28.213 3.984 28.453 126.504 ;
     RECT  27.923 2.304 28.885 2.904 ;
     RECT  28.453 3.984 28.885 127.128 ;
     RECT  28.885 2.304 28.892 127.128 ;
     RECT  28.892 2.256 29.077 127.128 ;
     RECT  29.077 2.064 29.408 127.128 ;
     RECT  29.221 0.288 29.507 0.312 ;
     RECT  29.257 128.832 29.507 128.856 ;
     RECT  29.408 2.064 29.512 127.452 ;
     RECT  29.512 2.064 29.704 127.182 ;
     RECT  29.704 2.064 29.801 126.6 ;
     RECT  29.801 2.688 29.939 5.208 ;
     RECT  29.939 2.88 30.449 5.208 ;
     RECT  30.661 128.832 30.757 128.856 ;
     RECT  29.749 0.192 30.899 0.216 ;
     RECT  30.757 128.832 30.899 129.384 ;
     RECT  30.449 4.992 31.169 5.208 ;
     RECT  29.801 6.24 31.189 126.6 ;
     RECT  30.449 2.88 31.196 4.008 ;
     RECT  30.805 1.728 31.244 1.752 ;
     RECT  31.196 2.736 31.244 4.008 ;
     RECT  31.244 1.728 31.283 4.008 ;
     RECT  31.283 3.408 31.421 4.008 ;
     RECT  31.169 5.04 31.777 5.208 ;
     RECT  31.189 6.24 31.777 127.128 ;
     RECT  31.777 5.04 31.853 127.128 ;
     RECT  31.853 5.136 31.925 127.128 ;
     RECT  31.925 5.136 31.961 126.648 ;
     RECT  31.283 1.728 32.339 2.232 ;
     RECT  32.053 127.68 32.753 127.704 ;
     RECT  31.421 3.984 33.001 4.008 ;
     RECT  33.001 3.984 33.397 4.584 ;
     RECT  31.961 5.712 33.397 126.648 ;
     RECT  32.353 2.88 33.445 2.904 ;
     RECT  33.397 3.936 33.445 126.648 ;
     RECT  32.339 1.728 33.541 1.752 ;
     RECT  33.445 2.88 33.541 127.128 ;
     RECT  33.541 1.728 33.625 127.128 ;
     RECT  33.625 5.712 33.725 127.128 ;
     RECT  33.541 0.192 33.779 0.216 ;
     RECT  33.793 127.68 33.923 127.704 ;
     RECT  33.625 1.728 34.117 4.584 ;
     RECT  34.297 0.576 34.381 0.6 ;
     RECT  34.309 128.832 34.553 128.856 ;
     RECT  34.117 1.68 34.643 4.584 ;
     RECT  34.643 1.728 34.693 4.584 ;
     RECT  34.693 1.728 34.808 4.68 ;
     RECT  33.725 5.712 34.808 126.504 ;
     RECT  34.693 127.584 34.808 127.608 ;
     RECT  34.808 1.728 34.912 127.608 ;
     RECT  34.912 1.728 35.104 127.182 ;
     RECT  35.104 1.728 35.345 127.128 ;
     RECT  35.345 1.728 36.461 126.504 ;
     RECT  36.461 1.728 36.605 5.496 ;
     RECT  36.605 3.84 36.677 5.496 ;
     RECT  35.605 128.208 36.749 128.232 ;
     RECT  36.901 128.832 37.001 128.856 ;
     RECT  36.677 3.84 37.037 4.056 ;
     RECT  36.677 5.136 37.043 5.496 ;
     RECT  37.037 3.84 37.217 4.008 ;
     RECT  36.605 1.728 37.541 2.856 ;
     RECT  37.333 127.68 37.577 127.704 ;
     RECT  37.541 1.728 37.649 2.808 ;
     RECT  37.217 3.984 37.667 4.008 ;
     RECT  36.461 6.672 38.081 126.504 ;
     RECT  38.041 5.232 38.473 5.256 ;
     RECT  38.797 0.576 38.881 0.6 ;
     RECT  37.649 2.784 38.905 2.808 ;
     RECT  38.473 4.896 38.905 5.256 ;
     RECT  37.765 128.208 39.305 128.232 ;
     RECT  38.905 4.512 39.445 5.256 ;
     RECT  38.081 6.96 39.685 126.504 ;
     RECT  37.649 1.728 40.076 1.752 ;
     RECT  38.905 2.784 40.076 3.432 ;
     RECT  40.117 128.832 40.205 128.856 ;
     RECT  40.076 1.728 40.208 3.432 ;
     RECT  39.445 4.512 40.208 5.736 ;
     RECT  39.685 6.96 40.208 126.552 ;
     RECT  40.208 1.728 40.504 127.452 ;
     RECT  40.504 6.24 40.549 127.452 ;
     RECT  40.549 6.24 40.781 127.704 ;
     RECT  40.781 6.24 41.033 127.128 ;
     RECT  40.504 4.752 41.605 5.16 ;
     RECT  41.033 6.24 41.605 126.504 ;
     RECT  41.605 4.752 41.717 126.504 ;
     RECT  41.677 0.576 41.761 0.6 ;
     RECT  40.504 2.88 41.825 3.432 ;
     RECT  41.825 2.88 42.037 3.24 ;
     RECT  42.037 2.832 42.121 3.24 ;
     RECT  42.121 3.216 42.172 3.24 ;
     RECT  41.717 6.864 42.581 126.504 ;
     RECT  41.845 128.832 42.581 128.856 ;
     RECT  42.581 72.768 42.677 126.504 ;
     RECT  41.717 4.752 42.721 5.736 ;
     RECT  42.581 6.864 42.721 71.736 ;
     RECT  42.721 4.752 43.085 71.736 ;
     RECT  42.677 72.768 43.141 127.128 ;
     RECT  43.141 72.768 43.337 127.416 ;
     RECT  43.085 6.816 43.373 71.736 ;
     RECT  43.373 6.864 43.573 71.736 ;
     RECT  43.337 72.768 43.573 126.504 ;
     RECT  43.573 6.864 43.619 126.504 ;
     RECT  43.085 4.752 43.913 5.688 ;
     RECT  43.405 3.216 44.381 3.24 ;
     RECT  44.101 128.832 44.669 128.856 ;
     RECT  40.504 1.728 44.773 1.752 ;
     RECT  43.913 4.752 45.025 5.544 ;
     RECT  44.773 1.68 45.299 1.752 ;
     RECT  43.619 7.152 45.397 126.504 ;
     RECT  45.299 1.728 45.608 1.752 ;
     RECT  44.665 3.408 45.608 3.432 ;
     RECT  45.025 4.752 45.608 6.12 ;
     RECT  45.397 7.152 45.608 127.128 ;
     RECT  45.608 1.728 45.712 127.452 ;
     RECT  45.745 128.208 45.875 128.232 ;
     RECT  45.712 1.728 45.904 127.182 ;
     RECT  46.213 0.576 46.307 0.6 ;
     RECT  46.261 128.832 46.469 128.856 ;
     RECT  45.904 5.52 46.649 126.552 ;
     RECT  46.649 5.616 46.691 126.552 ;
     RECT  45.904 2.88 47.405 2.904 ;
     RECT  46.691 5.808 47.473 126.552 ;
     RECT  47.473 5.808 47.557 126.792 ;
     RECT  47.105 128.208 47.557 128.232 ;
     RECT  46.825 0.192 47.603 0.216 ;
     RECT  47.557 5.808 47.621 128.232 ;
     RECT  47.564 3.216 47.651 3.24 ;
     RECT  45.904 1.728 47.653 1.752 ;
     RECT  47.621 5.808 47.761 126.456 ;
     RECT  47.621 127.68 47.837 128.232 ;
     RECT  47.653 1.104 48.035 1.752 ;
     RECT  47.761 5.664 48.985 126.456 ;
     RECT  48.985 5.232 49.309 126.456 ;
     RECT  49.309 5.136 49.457 126.456 ;
     RECT  49.457 5.232 49.493 126.456 ;
     RECT  47.837 128.208 49.523 128.232 ;
     RECT  48.697 3.936 49.889 3.96 ;
     RECT  49.877 127.632 49.961 127.704 ;
     RECT  49.165 2.784 50.173 2.808 ;
     RECT  49.493 5.232 50.677 5.256 ;
     RECT  49.493 6.24 50.677 126.456 ;
     RECT  48.035 1.728 50.965 1.752 ;
     RECT  50.173 2.784 50.965 2.856 ;
     RECT  49.961 127.68 50.965 127.704 ;
     RECT  50.965 1.728 51.008 2.856 ;
     RECT  50.677 5.232 51.008 126.456 ;
     RECT  50.965 127.584 51.008 127.704 ;
     RECT  51.008 1.728 51.251 127.704 ;
     RECT  51.251 1.728 51.304 127.182 ;
     RECT  51.304 3.408 51.473 3.432 ;
     RECT  51.605 128.208 51.689 128.232 ;
     RECT  51.304 6.384 52.501 126.456 ;
     RECT  52.069 128.832 53.021 128.856 ;
     RECT  52.501 6.384 53.365 127.128 ;
     RECT  51.304 5.232 53.449 5.256 ;
     RECT  53.365 6.384 53.449 127.704 ;
     RECT  53.449 5.232 53.452 127.704 ;
     RECT  52.729 3.408 53.525 3.432 ;
     RECT  53.452 5.232 53.699 127.176 ;
     RECT  53.699 5.232 53.701 6.408 ;
     RECT  53.629 0.576 53.713 0.6 ;
     RECT  53.699 8.016 54.137 127.176 ;
     RECT  53.701 4.56 54.425 6.408 ;
     RECT  54.425 4.56 54.821 6.264 ;
     RECT  54.025 2.736 54.925 2.76 ;
     RECT  54.925 2.736 54.965 3.432 ;
     RECT  54.137 8.016 55.189 126.456 ;
     RECT  55.189 8.016 55.276 127.128 ;
     RECT  55.276 8.016 55.321 126.504 ;
     RECT  54.821 5.28 56.077 6.264 ;
     RECT  56.012 128.832 56.099 128.856 ;
     RECT  51.304 1.728 56.408 1.752 ;
     RECT  54.965 3.408 56.408 3.432 ;
     RECT  56.077 4.656 56.408 6.264 ;
     RECT  55.321 7.92 56.408 126.504 ;
     RECT  56.408 1.728 56.485 127.452 ;
     RECT  56.485 1.728 56.585 127.704 ;
     RECT  56.585 1.728 56.704 127.182 ;
     RECT  56.704 96.816 56.873 127.128 ;
     RECT  56.365 0.24 56.963 0.264 ;
     RECT  56.873 96.912 57.017 127.128 ;
     RECT  56.704 1.728 57.733 1.752 ;
     RECT  56.704 2.832 57.733 6.168 ;
     RECT  57.733 1.728 57.877 6.168 ;
     RECT  56.704 7.92 57.949 95.688 ;
     RECT  57.017 96.912 57.949 126.504 ;
     RECT  57.877 1.728 58.117 6.84 ;
     RECT  57.949 7.92 58.117 126.504 ;
     RECT  58.117 1.728 58.133 126.504 ;
     RECT  58.133 1.728 58.277 126.264 ;
     RECT  57.308 128.832 58.403 128.856 ;
     RECT  58.277 1.728 59.033 5.64 ;
     RECT  58.789 127.68 59.069 127.704 ;
     RECT  58.277 6.816 59.221 126.264 ;
     RECT  59.033 1.728 59.267 2.28 ;
     RECT  59.221 6.816 59.308 127.128 ;
     RECT  59.033 4.8 59.315 5.64 ;
     RECT  59.033 3.408 59.321 3.432 ;
     RECT  59.315 5.376 59.509 5.64 ;
     RECT  59.308 6.816 59.509 126.264 ;
     RECT  60.389 0.576 60.473 0.6 ;
     RECT  59.509 5.376 60.829 126.264 ;
     RECT  60.133 128.832 60.869 128.856 ;
     RECT  60.997 127.68 61.193 127.704 ;
     RECT  60.829 4.512 61.261 126.264 ;
     RECT  61.261 4.224 61.429 126.264 ;
     RECT  59.267 1.728 61.808 1.752 ;
     RECT  61.429 4.224 61.808 127.608 ;
     RECT  61.808 1.728 62.104 127.608 ;
     RECT  62.104 5.472 62.165 127.608 ;
     RECT  62.104 4.224 62.381 4.248 ;
     RECT  62.165 5.472 63.097 127.128 ;
     RECT  63.097 4.56 63.281 127.128 ;
     RECT  63.281 4.56 63.389 126.504 ;
     RECT  63.389 118.896 63.533 126.504 ;
     RECT  63.389 5.472 63.641 117.912 ;
     RECT  62.197 128.832 64.289 128.856 ;
     RECT  63.641 5.472 64.357 117.864 ;
     RECT  63.533 118.944 64.453 126.504 ;
     RECT  64.357 5.328 64.613 117.864 ;
     RECT  64.453 118.944 64.885 127.176 ;
     RECT  64.885 118.944 64.973 127.272 ;
     RECT  64.613 8.016 65.005 117.864 ;
     RECT  64.973 118.944 65.005 126.312 ;
     RECT  64.613 5.328 65.267 6.84 ;
     RECT  65.401 0.192 65.603 0.216 ;
     RECT  64.501 3.312 65.837 3.336 ;
     RECT  65.845 127.68 65.945 127.704 ;
     RECT  65.005 8.016 66.083 126.312 ;
     RECT  66.083 98.928 66.277 126.312 ;
     RECT  62.104 1.728 66.697 1.752 ;
     RECT  65.267 6 66.697 6.84 ;
     RECT  66.083 8.016 66.697 97.608 ;
     RECT  66.625 128.256 66.755 128.28 ;
     RECT  66.277 98.928 67.1 127.128 ;
     RECT  67.1 98.928 67.187 127.608 ;
     RECT  66.697 1.728 67.208 2.28 ;
     RECT  66.301 3.408 67.208 3.432 ;
     RECT  65.977 4.656 67.208 4.68 ;
     RECT  66.697 6 67.208 97.608 ;
     RECT  67.187 98.928 67.208 127.452 ;
     RECT  67.208 1.728 67.312 127.452 ;
     RECT  67.312 1.728 67.504 127.182 ;
     RECT  67.676 128.832 67.763 128.856 ;
     RECT  67.504 3.408 67.853 3.432 ;
     RECT  67.504 5.184 67.889 127.176 ;
     RECT  67.889 5.184 67.907 11.064 ;
     RECT  67.907 5.184 67.933 6.84 ;
     RECT  67.933 5.184 67.997 6.552 ;
     RECT  67.889 12.048 68.393 127.176 ;
     RECT  68.393 12.048 68.429 126.504 ;
     RECT  68.429 16.56 68.609 126.504 ;
     RECT  67.504 1.728 68.821 1.848 ;
     RECT  68.821 1.728 68.915 2.28 ;
     RECT  67.907 7.968 69.001 11.064 ;
     RECT  68.429 12.048 69.001 15.576 ;
     RECT  69.001 7.968 69.005 15.576 ;
     RECT  68.609 16.608 69.445 126.504 ;
     RECT  69.013 127.68 69.445 127.704 ;
     RECT  69.469 5.04 69.48 5.064 ;
     RECT  69.48 4.512 69.541 5.064 ;
     RECT  67.997 6.096 69.541 6.552 ;
     RECT  69.445 16.608 69.581 127.704 ;
     RECT  69.005 11.616 69.587 15.576 ;
     RECT  69.541 4.512 69.613 6.552 ;
     RECT  69.005 7.968 69.613 10.632 ;
     RECT  69.587 11.616 69.617 14.232 ;
     RECT  69.587 15.456 69.644 15.576 ;
     RECT  69.581 16.608 69.644 18.168 ;
     RECT  69.617 14.112 69.653 14.232 ;
     RECT  69.644 15.456 69.689 18.168 ;
     RECT  69.689 15.456 69.797 18.12 ;
     RECT  69.797 15.456 69.869 18.072 ;
     RECT  69.581 19.248 69.869 127.704 ;
     RECT  69.869 19.248 69.905 117.864 ;
     RECT  69.617 11.616 69.941 13.08 ;
     RECT  69.905 19.248 69.941 117.672 ;
     RECT  69.869 118.896 69.964 127.704 ;
     RECT  69.653 14.208 69.977 14.232 ;
     RECT  69.941 19.248 70.157 99.528 ;
     RECT  69.109 2.88 70.225 2.904 ;
     RECT  70.225 2.88 70.265 3.432 ;
     RECT  69.613 4.512 70.333 10.632 ;
     RECT  69.941 11.616 70.333 12.504 ;
     RECT  70.333 4.512 70.547 12.504 ;
     RECT  70.157 19.248 70.553 99.48 ;
     RECT  69.869 15.984 70.625 18.072 ;
     RECT  70.547 4.512 70.697 10.632 ;
     RECT  69.964 118.896 70.733 127.128 ;
     RECT  70.697 6.096 70.787 10.632 ;
     RECT  70.765 14.784 70.849 14.808 ;
     RECT  69.941 100.512 70.873 117.672 ;
     RECT  70.733 118.896 70.873 126.696 ;
     RECT  70.787 6.096 70.877 7.272 ;
     RECT  70.553 19.248 70.913 21.672 ;
     RECT  70.877 6.096 70.979 7.224 ;
     RECT  70.913 19.248 71.057 21.384 ;
     RECT  70.547 11.616 71.077 12.504 ;
     RECT  71.077 11.616 71.089 12.984 ;
     RECT  70.265 3.408 71.093 3.432 ;
     RECT  71.089 11.616 71.125 13.08 ;
     RECT  70.625 15.984 71.129 17.64 ;
     RECT  71.057 19.248 71.129 21.096 ;
     RECT  70.697 4.512 71.165 4.536 ;
     RECT  70.873 100.512 71.308 126.696 ;
     RECT  71.129 19.248 71.309 21.048 ;
     RECT  70.553 22.752 71.381 99.48 ;
     RECT  71.309 19.248 71.453 20.136 ;
     RECT  71.381 22.752 71.453 26.04 ;
     RECT  71.381 27.504 71.485 99.48 ;
     RECT  71.308 100.512 71.485 126.552 ;
     RECT  71.453 19.248 71.989 19.368 ;
     RECT  71.453 22.752 72.061 24.168 ;
     RECT  70.979 6.096 72.349 6.12 ;
     RECT  70.979 7.2 72.349 7.224 ;
     RECT  71.453 25.248 72.373 26.04 ;
     RECT  68.915 1.728 72.608 1.752 ;
     RECT  72.349 3.36 72.608 4.68 ;
     RECT  72.349 6.096 72.608 7.224 ;
     RECT  70.787 8.496 72.608 10.632 ;
     RECT  71.125 11.616 72.608 13.608 ;
     RECT  72.025 14.832 72.608 14.856 ;
     RECT  71.129 16.56 72.608 17.64 ;
     RECT  71.989 19.056 72.608 19.368 ;
     RECT  72.061 22.704 72.608 24.168 ;
     RECT  72.373 25.248 72.608 26.28 ;
     RECT  71.485 27.504 72.608 126.552 ;
     RECT  72.373 127.536 72.608 127.56 ;
     RECT  72.608 1.728 72.904 127.56 ;
     RECT  72.904 27.6 72.929 34.68 ;
     RECT  72.904 8.784 73.001 10.632 ;
     RECT  72.929 27.6 73.037 34.44 ;
     RECT  72.904 23.568 73.073 26.52 ;
     RECT  72.904 40.272 73.091 118.344 ;
     RECT  72.904 17.184 73.109 17.208 ;
     RECT  72.904 35.808 73.139 38.808 ;
     RECT  72.904 13.68 73.253 13.704 ;
     RECT  72.904 127.536 73.331 127.56 ;
     RECT  73.037 29.616 73.397 34.44 ;
     RECT  73.139 35.808 73.397 38.76 ;
     RECT  73.397 35.808 73.427 38.424 ;
     RECT  72.904 3.36 73.433 4.68 ;
     RECT  73.091 43.584 73.433 118.344 ;
     RECT  73.433 43.584 73.475 46.632 ;
     RECT  73.397 30.96 73.549 34.44 ;
     RECT  73.037 27.6 73.577 28.488 ;
     RECT  73.549 32.736 73.613 34.44 ;
     RECT  72.904 119.52 73.613 126.504 ;
     RECT  72.904 18.768 73.619 19.368 ;
     RECT  73.073 23.568 73.619 26.28 ;
     RECT  73.577 27.6 73.619 27.72 ;
     RECT  73.619 27.6 73.685 27.672 ;
     RECT  73.091 40.272 73.685 42.552 ;
     RECT  73.619 19.056 73.865 19.368 ;
     RECT  73.433 47.712 73.901 118.344 ;
     RECT  72.904 6.096 73.925 6.12 ;
     RECT  73.685 40.272 73.937 42.072 ;
     RECT  73.433 4.224 73.957 4.68 ;
     RECT  73.925 6.096 73.957 6.264 ;
     RECT  73.901 52.032 73.973 118.344 ;
     RECT  73.957 4.224 74.009 6.264 ;
     RECT  73.549 30.96 74.009 31.704 ;
     RECT  73.973 52.08 74.009 118.344 ;
     RECT  74.009 4.224 74.045 6.12 ;
     RECT  73.619 25.44 74.081 26.28 ;
     RECT  73.901 47.712 74.081 50.856 ;
     RECT  74.009 52.08 74.117 114.072 ;
     RECT  73.427 36.528 74.153 38.424 ;
     RECT  73.475 43.584 74.189 46.536 ;
     RECT  74.177 129.456 74.204 129.48 ;
     RECT  74.204 129.36 74.261 129.48 ;
     RECT  74.261 129.36 74.291 129.384 ;
     RECT  73.613 32.736 74.297 34.008 ;
     RECT  73.937 41.76 74.297 42.072 ;
     RECT  74.189 45.84 74.297 46.536 ;
     RECT  74.189 43.584 74.389 44.76 ;
     RECT  74.081 25.44 74.549 26.04 ;
     RECT  73.613 119.664 74.579 126.504 ;
     RECT  72.904 12.288 74.581 12.504 ;
     RECT  74.389 43.296 74.585 44.76 ;
     RECT  74.579 126.384 74.625 126.504 ;
     RECT  74.117 52.08 74.657 113.928 ;
     RECT  74.009 115.152 74.657 118.344 ;
     RECT  74.625 126.384 74.677 126.552 ;
     RECT  74.081 48.48 74.693 50.856 ;
     RECT  74.153 37.008 74.725 38.424 ;
     RECT  74.725 37.008 74.765 38.808 ;
     RECT  74.297 33.984 74.819 34.008 ;
     RECT  74.765 37.056 74.837 38.808 ;
     RECT  74.045 4.224 74.869 4.536 ;
     RECT  72.904 7.632 74.869 7.656 ;
     RECT  74.869 7.632 74.909 7.8 ;
     RECT  74.837 37.344 74.981 38.808 ;
     RECT  74.981 37.344 75.004 38.664 ;
     RECT  73.619 23.568 75.053 23.688 ;
     RECT  74.677 126.384 75.109 126.648 ;
     RECT  75.004 37.344 75.197 38.424 ;
     RECT  75.197 37.632 75.233 38.424 ;
     RECT  74.869 3.408 75.251 4.536 ;
     RECT  75.251 3.408 75.269 4.008 ;
     RECT  74.045 5.568 75.269 6.12 ;
     RECT  75.233 37.632 75.377 37.992 ;
     RECT  74.693 48.528 75.377 50.856 ;
     RECT  74.657 52.368 75.485 113.928 ;
     RECT  73.937 40.272 75.493 40.44 ;
     RECT  74.581 12.192 75.521 12.504 ;
     RECT  74.549 25.968 75.521 26.04 ;
     RECT  74.297 41.856 75.539 41.88 ;
     RECT  74.585 43.536 75.539 44.76 ;
     RECT  75.109 126.384 75.541 126.888 ;
     RECT  74.297 45.84 75.553 45.864 ;
     RECT  75.485 52.368 75.557 91.08 ;
     RECT  75.539 43.536 75.58 43.704 ;
     RECT  74.579 119.664 75.625 125.208 ;
     RECT  75.541 126.384 75.625 126.984 ;
     RECT  75.625 119.664 75.665 126.984 ;
     RECT  75.665 119.664 75.769 126.024 ;
     RECT  75.769 119.184 75.797 126.024 ;
     RECT  75.485 92.16 75.805 113.928 ;
     RECT  74.657 115.152 75.805 118.104 ;
     RECT  73.001 8.784 75.809 10.392 ;
     RECT  73.685 27.6 75.829 27.624 ;
     RECT  75.377 48.528 75.829 48.648 ;
     RECT  75.269 3.984 75.845 4.008 ;
     RECT  75.829 27.6 75.875 28.536 ;
     RECT  75.875 27.888 75.877 28.536 ;
     RECT  73.397 29.616 75.877 29.928 ;
     RECT  75.797 119.088 75.881 126.024 ;
     RECT  75.877 27.888 75.953 29.928 ;
     RECT  75.953 29.088 75.961 29.928 ;
     RECT  75.553 45.84 76.019 46.728 ;
     RECT  75.377 50.256 76.019 50.856 ;
     RECT  75.269 6.096 76.021 6.12 ;
     RECT  74.909 7.776 76.021 7.8 ;
     RECT  75.301 17.088 76.021 17.112 ;
     RECT  75.521 12.192 76.025 12.216 ;
     RECT  76.019 50.64 76.057 50.856 ;
     RECT  75.829 48.48 76.06 48.648 ;
     RECT  76.021 17.088 76.061 17.352 ;
     RECT  76.06 48.48 76.061 48.552 ;
     RECT  76.021 6.096 76.067 7.8 ;
     RECT  75.809 8.784 76.067 9.72 ;
     RECT  75.557 54 76.067 91.08 ;
     RECT  75.985 10.848 76.069 10.872 ;
     RECT  76.067 54.048 76.108 91.08 ;
     RECT  76.108 54.048 76.133 54.456 ;
     RECT  76.057 50.64 76.163 51.624 ;
     RECT  75.961 29.616 76.277 29.928 ;
     RECT  75.805 92.16 76.313 118.104 ;
     RECT  76.381 0.576 76.547 0.6 ;
     RECT  76.46 128.256 76.547 128.28 ;
     RECT  76.108 55.536 76.561 91.08 ;
     RECT  76.313 92.16 76.561 113.064 ;
     RECT  75.881 119.184 76.565 126.024 ;
     RECT  76.313 114.576 76.673 118.104 ;
     RECT  76.561 55.536 76.709 113.064 ;
     RECT  76.067 6.096 76.745 6.84 ;
     RECT  76.673 114.912 76.745 118.104 ;
     RECT  76.133 54.336 76.781 54.456 ;
     RECT  76.709 61.152 76.781 113.064 ;
     RECT  76.781 61.152 76.817 99.768 ;
     RECT  76.565 119.712 76.837 126.024 ;
     RECT  76.837 119.712 76.883 126.168 ;
     RECT  76.817 61.2 76.889 99.768 ;
     RECT  76.889 61.2 76.925 62.52 ;
     RECT  76.883 119.712 76.925 124.728 ;
     RECT  76.883 126 76.933 126.168 ;
     RECT  75.377 37.968 76.957 37.992 ;
     RECT  76.925 61.248 76.961 62.52 ;
     RECT  76.961 61.248 76.997 61.512 ;
     RECT  76.889 63.504 77.033 99.768 ;
     RECT  76.745 115.632 77.033 118.104 ;
     RECT  76.957 37.008 77.041 37.992 ;
     RECT  76.067 8.784 77.209 9.096 ;
     RECT  77.033 116.832 77.281 118.104 ;
     RECT  76.781 100.896 77.317 113.064 ;
     RECT  77.209 8.544 77.509 9.096 ;
     RECT  76.781 54.432 77.533 54.456 ;
     RECT  76.709 55.536 77.533 60.168 ;
     RECT  76.061 17.328 77.564 17.352 ;
     RECT  77.497 0.192 77.581 0.216 ;
     RECT  76.745 6.096 77.605 6.408 ;
     RECT  73.865 19.056 77.605 19.08 ;
     RECT  75.053 23.664 77.641 23.688 ;
     RECT  74.297 32.736 77.677 32.76 ;
     RECT  76.933 126 77.845 126.888 ;
     RECT  75.493 40.032 77.893 40.44 ;
     RECT  77.845 126 77.893 127.608 ;
     RECT  77.605 5.904 77.929 6.408 ;
     RECT  77.893 125.952 77.987 127.608 ;
     RECT  72.904 1.728 78.008 1.752 ;
     RECT  77.749 3.456 78.008 3.48 ;
     RECT  76.885 4.512 78.008 4.536 ;
     RECT  77.929 5.856 78.008 6.408 ;
     RECT  77.509 7.728 78.008 9.096 ;
     RECT  75.625 14.64 78.008 14.664 ;
     RECT  77.564 16.656 78.008 17.352 ;
     RECT  77.605 18.816 78.008 19.08 ;
     RECT  77.245 20.592 78.008 20.616 ;
     RECT  77.641 23.28 78.008 23.688 ;
     RECT  75.521 25.968 78.008 25.992 ;
     RECT  75.953 27.888 78.008 27.912 ;
     RECT  76.277 29.616 78.008 29.64 ;
     RECT  74.009 30.96 78.008 30.984 ;
     RECT  77.677 32.736 78.008 32.808 ;
     RECT  77.041 37.968 78.008 37.992 ;
     RECT  77.893 39.84 78.008 40.44 ;
     RECT  75.58 43.68 78.008 43.704 ;
     RECT  75.539 44.736 78.008 44.76 ;
     RECT  76.019 45.84 78.008 45.864 ;
     RECT  76.061 48.528 78.008 48.552 ;
     RECT  76.163 50.64 78.008 50.856 ;
     RECT  77.533 54.432 78.008 60.168 ;
     RECT  76.997 61.248 78.008 61.368 ;
     RECT  76.961 62.496 78.008 62.52 ;
     RECT  77.033 63.504 78.008 80.616 ;
     RECT  77.033 81.6 78.008 99.768 ;
     RECT  77.317 100.896 78.008 113.4 ;
     RECT  77.033 115.632 78.008 115.656 ;
     RECT  77.281 116.832 78.008 118.536 ;
     RECT  76.925 119.712 78.008 120.552 ;
     RECT  76.925 121.824 78.008 124.728 ;
     RECT  77.987 125.952 78.008 127.452 ;
     RECT  78.008 1.728 78.112 127.452 ;
     RECT  78.112 1.728 78.304 127.182 ;
     RECT  78.304 20.592 78.419 20.616 ;
     RECT  78.304 23.28 78.419 23.688 ;
     RECT  78.304 61.584 78.419 77.352 ;
     RECT  78.304 81.696 78.467 112.872 ;
     RECT  78.304 21.936 78.473 21.96 ;
     RECT  78.419 67.68 78.473 77.352 ;
     RECT  78.304 78.336 78.509 80.616 ;
     RECT  78.419 61.584 78.515 66.312 ;
     RECT  78.473 67.68 78.581 69 ;
     RECT  78.581 67.68 78.617 68.52 ;
     RECT  78.473 70.032 78.617 77.352 ;
     RECT  78.467 81.696 78.617 106.872 ;
     RECT  78.617 81.696 78.653 106.776 ;
     RECT  78.304 11.424 78.659 12.024 ;
     RECT  78.304 115.632 78.659 126.984 ;
     RECT  78.617 67.68 78.672 68.184 ;
     RECT  78.304 50.64 78.689 50.856 ;
     RECT  78.617 70.272 78.689 77.352 ;
     RECT  78.515 61.632 78.725 66.312 ;
     RECT  78.304 39.888 78.733 40.44 ;
     RECT  78.725 61.632 78.755 66.216 ;
     RECT  78.304 18.816 78.761 19.512 ;
     RECT  78.653 92.112 78.761 106.776 ;
     RECT  78.689 70.272 78.797 74.328 ;
     RECT  78.467 108.192 78.797 112.872 ;
     RECT  78.304 30.624 78.803 33 ;
     RECT  78.761 98.688 78.803 106.776 ;
     RECT  78.803 98.688 78.833 100.392 ;
     RECT  78.797 70.272 78.869 72.264 ;
     RECT  78.803 102 78.869 106.776 ;
     RECT  78.689 75.408 78.899 77.352 ;
     RECT  78.755 63.312 78.941 66.216 ;
     RECT  78.653 81.696 78.941 91.032 ;
     RECT  78.659 116.976 78.941 126.984 ;
     RECT  78.797 73.344 78.995 74.328 ;
     RECT  78.941 63.504 79.049 66.216 ;
     RECT  78.304 59.52 79.084 60.408 ;
     RECT  78.304 1.728 79.139 1.8 ;
     RECT  78.304 57.024 79.165 58.152 ;
     RECT  78.304 3.36 79.18 4.248 ;
     RECT  78.803 30.624 79.193 32.808 ;
     RECT  78.941 116.976 79.193 124.872 ;
     RECT  78.304 27.216 79.228 27.912 ;
     RECT  78.797 108.192 79.235 111.864 ;
     RECT  78.304 45.84 79.283 47.016 ;
     RECT  78.304 54.432 79.283 55.56 ;
     RECT  78.899 75.408 79.283 77.112 ;
     RECT  78.761 92.112 79.331 97.368 ;
     RECT  79.235 108.192 79.331 111.576 ;
     RECT  79.049 63.504 79.337 65.976 ;
     RECT  79.331 95.952 79.337 97.368 ;
     RECT  78.761 19.056 79.373 19.512 ;
     RECT  78.941 82.704 79.373 91.032 ;
     RECT  78.304 5.856 79.405 6.12 ;
     RECT  78.304 114.528 79.405 114.552 ;
     RECT  78.659 115.632 79.405 115.656 ;
     RECT  79.337 63.504 79.409 65.16 ;
     RECT  78.869 103.056 79.409 106.776 ;
     RECT  79.405 114.528 79.409 115.656 ;
     RECT  78.941 126 79.409 126.984 ;
     RECT  79.337 95.952 79.445 96.888 ;
     RECT  79.409 115.056 79.445 115.656 ;
     RECT  78.304 37.968 79.477 37.992 ;
     RECT  78.304 48.336 79.477 48.648 ;
     RECT  79.477 48.336 79.481 49.56 ;
     RECT  78.869 102 79.489 102.024 ;
     RECT  79.331 92.112 79.516 94.632 ;
     RECT  78.689 50.688 79.523 50.856 ;
     RECT  79.193 32.736 79.553 32.808 ;
     RECT  79.165 57.552 79.553 58.152 ;
     RECT  79.481 49.536 79.561 49.56 ;
     RECT  78.797 112.848 79.58 112.872 ;
     RECT  78.304 52.08 79.581 53.016 ;
     RECT  79.373 83.328 79.589 91.032 ;
     RECT  79.409 63.504 79.625 64.728 ;
     RECT  79.409 104.016 79.661 106.776 ;
     RECT  79.58 112.848 79.667 113.688 ;
     RECT  78.869 70.272 79.693 71.496 ;
     RECT  79.283 75.408 79.733 76.968 ;
     RECT  79.481 48.336 79.765 48.552 ;
     RECT  78.509 78.816 79.769 80.616 ;
     RECT  79.516 92.928 79.769 94.632 ;
     RECT  79.589 85.488 79.805 91.032 ;
     RECT  79.769 92.928 79.805 94.392 ;
     RECT  78.995 73.344 79.813 73.368 ;
     RECT  79.805 90.336 79.841 91.032 ;
     RECT  79.765 0.192 79.859 0.216 ;
     RECT  79.693 69.504 79.859 71.496 ;
     RECT  79.589 83.328 79.877 84.408 ;
     RECT  79.859 69.504 79.905 69.528 ;
     RECT  79.877 83.328 79.905 84.216 ;
     RECT  79.905 83.328 79.949 83.832 ;
     RECT  79.661 104.016 79.949 106.248 ;
     RECT  79.769 80.112 79.955 80.616 ;
     RECT  79.949 104.016 79.955 105.816 ;
     RECT  79.331 108.24 79.955 111.576 ;
     RECT  79.733 75.408 79.981 76.344 ;
     RECT  78.304 44.736 79.985 44.76 ;
     RECT  79.813 72.96 79.985 73.368 ;
     RECT  78.833 98.88 79.985 100.392 ;
     RECT  79.981 75.216 80.044 76.344 ;
     RECT  80.044 76.32 80.051 76.344 ;
     RECT  79.955 80.112 80.051 80.136 ;
     RECT  78.941 81.696 80.053 81.72 ;
     RECT  79.955 108.672 80.057 111.576 ;
     RECT  79.283 45.84 80.093 46.104 ;
     RECT  79.859 70.848 80.093 70.872 ;
     RECT  79.445 95.952 80.093 96.504 ;
     RECT  79.985 98.88 80.093 99.72 ;
     RECT  79.955 104.016 80.093 105.192 ;
     RECT  79.477 37.584 80.099 37.992 ;
     RECT  80.057 108.672 80.129 110.088 ;
     RECT  79.409 126.432 80.147 126.984 ;
     RECT  79.805 92.928 80.165 94.2 ;
     RECT  80.129 108.768 80.165 110.088 ;
     RECT  80.093 104.016 80.201 104.856 ;
     RECT  79.18 4.224 80.204 4.248 ;
     RECT  79.405 5.712 80.204 6.12 ;
     RECT  80.099 37.968 80.237 37.992 ;
     RECT  79.193 116.976 80.273 119.448 ;
     RECT  80.204 4.224 80.291 6.12 ;
     RECT  79.949 83.76 80.309 83.832 ;
     RECT  78.304 43.68 80.341 43.704 ;
     RECT  79.985 73.344 80.341 73.368 ;
     RECT  80.057 111.072 80.345 111.576 ;
     RECT  80.053 81.696 80.389 81.768 ;
     RECT  80.201 104.016 80.389 104.04 ;
     RECT  79.477 36.48 80.396 36.504 ;
     RECT  79.585 42.192 80.417 42.216 ;
     RECT  80.341 43.536 80.425 44.472 ;
     RECT  80.348 35.28 80.435 35.304 ;
     RECT  80.396 36.48 80.435 36.696 ;
     RECT  80.341 73.344 80.435 73.992 ;
     RECT  80.389 103.344 80.435 104.04 ;
     RECT  80.435 36.672 80.483 36.696 ;
     RECT  80.165 108.816 80.483 110.088 ;
     RECT  79.283 54.432 80.485 54.456 ;
     RECT  79.283 55.536 80.485 55.56 ;
     RECT  78.304 25.44 80.489 25.992 ;
     RECT  79.193 30.624 80.525 30.984 ;
     RECT  79.553 32.784 80.525 32.808 ;
     RECT  79.805 85.488 80.525 88.92 ;
     RECT  79.957 91.152 80.597 91.176 ;
     RECT  79.553 57.552 80.629 57.576 ;
     RECT  80.389 81.696 80.633 82.68 ;
     RECT  80.165 93.312 80.633 94.2 ;
     RECT  80.273 117.408 80.633 119.448 ;
     RECT  80.309 83.76 80.668 83.784 ;
     RECT  80.485 54.432 80.675 55.56 ;
     RECT  80.629 57.552 80.675 58.008 ;
     RECT  80.483 108.864 80.705 110.088 ;
     RECT  79.667 112.848 80.705 112.872 ;
     RECT  79.445 115.056 80.723 115.08 ;
     RECT  80.147 126.864 80.741 126.984 ;
     RECT  80.705 108.864 80.771 109.416 ;
     RECT  79.193 120.528 80.773 124.872 ;
     RECT  78.304 17.664 80.78 17.688 ;
     RECT  80.773 120.528 80.809 125.064 ;
     RECT  79.373 19.488 80.828 19.512 ;
     RECT  80.78 17.328 80.849 17.688 ;
     RECT  80.044 75.216 80.849 75.24 ;
     RECT  80.809 119.664 80.849 125.064 ;
     RECT  80.849 17.328 80.867 17.352 ;
     RECT  80.828 19.344 80.869 19.512 ;
     RECT  80.849 119.664 80.885 121.848 ;
     RECT  80.869 19.344 80.915 19.944 ;
     RECT  79.765 48.24 80.957 48.552 ;
     RECT  80.821 100.8 80.963 101.832 ;
     RECT  80.633 117.408 80.963 118.632 ;
     RECT  80.885 119.664 80.963 120.552 ;
     RECT  80.389 33.936 80.993 33.96 ;
     RECT  80.963 101.808 80.993 101.832 ;
     RECT  80.963 118.56 81.001 118.632 ;
     RECT  80.093 96.48 81.013 96.504 ;
     RECT  80.957 48.528 81.029 48.552 ;
     RECT  80.525 85.488 81.059 88.776 ;
     RECT  81.013 96.48 81.059 96.984 ;
     RECT  80.093 99.696 81.059 99.72 ;
     RECT  80.435 73.344 81.061 73.464 ;
     RECT  81.059 86.448 81.1 88.776 ;
     RECT  81.059 96.96 81.1 96.984 ;
     RECT  81.061 72.912 81.101 73.464 ;
     RECT  81.1 86.592 81.109 88.776 ;
     RECT  81.001 118.56 81.137 118.584 ;
     RECT  80.741 126.864 81.137 126.888 ;
     RECT  81.109 87.216 81.145 88.776 ;
     RECT  80.849 122.928 81.203 125.064 ;
     RECT  79.625 63.504 81.205 63.528 ;
     RECT  81.203 122.928 81.245 124.776 ;
     RECT  78.304 7.728 81.28 7.752 ;
     RECT  81.28 7.728 81.281 7.8 ;
     RECT  80.963 120.48 81.281 120.552 ;
     RECT  79.581 52.992 81.317 53.016 ;
     RECT  79.084 59.52 81.317 60.168 ;
     RECT  80.005 78.528 81.389 78.552 ;
     RECT  80.771 108.864 81.389 108.888 ;
     RECT  79.228 27.888 81.397 27.912 ;
     RECT  81.317 59.52 81.404 59.544 ;
     RECT  80.489 25.44 81.421 25.464 ;
     RECT  81.397 27.888 81.443 28.536 ;
     RECT  81.421 25.056 81.461 25.464 ;
     RECT  81.404 59.184 81.491 59.544 ;
     RECT  78.755 61.632 81.491 61.656 ;
     RECT  81.205 63.216 81.497 63.528 ;
     RECT  81.245 122.928 81.497 124.632 ;
     RECT  81.145 87.696 81.532 88.776 ;
     RECT  80.093 45.84 81.533 45.864 ;
     RECT  78.672 67.68 81.569 67.8 ;
     RECT  80.633 93.312 81.569 93.528 ;
     RECT  80.521 116.208 81.605 116.232 ;
     RECT  80.963 117.408 81.605 117.432 ;
     RECT  81.532 88.512 81.635 88.776 ;
     RECT  81.569 93.504 81.635 93.528 ;
     RECT  78.304 29.616 81.713 29.64 ;
     RECT  79.625 64.704 81.785 64.728 ;
     RECT  80.915 19.92 81.853 19.944 ;
     RECT  81.013 98.16 81.857 98.184 ;
     RECT  78.733 39.888 81.893 39.912 ;
     RECT  79.139 1.728 81.923 1.752 ;
     RECT  80.425 43.536 81.929 43.56 ;
     RECT  80.345 111.552 81.929 111.576 ;
     RECT  81.281 120.48 81.965 120.504 ;
     RECT  80.885 121.824 81.965 121.848 ;
     RECT  80.435 103.344 82.028 103.368 ;
     RECT  80.291 4.224 82.037 4.248 ;
     RECT  80.675 57.984 82.037 58.008 ;
     RECT  81.853 19.92 82.067 20.568 ;
     RECT  81.889 112.848 82.067 112.872 ;
     RECT  82.028 102.864 82.069 103.368 ;
     RECT  81.497 122.928 82.073 123.816 ;
     RECT  81.497 63.216 82.109 63.24 ;
     RECT  82.069 102 82.109 103.368 ;
     RECT  80.725 114.24 82.109 114.264 ;
     RECT  81.877 126.48 82.109 126.504 ;
     RECT  82.109 102 82.115 102.888 ;
     RECT  82.067 19.92 82.253 19.944 ;
     RECT  80.633 81.696 82.253 81.72 ;
     RECT  78.659 11.424 82.259 11.448 ;
     RECT  82.172 14.352 82.259 14.376 ;
     RECT  79.945 15.984 82.259 16.008 ;
     RECT  81.443 28.512 82.289 28.536 ;
     RECT  81.101 72.912 82.289 72.936 ;
     RECT  81.589 92.4 82.289 92.424 ;
     RECT  81.461 25.056 82.361 25.08 ;
     RECT  82.073 122.928 82.361 122.952 ;
     RECT  80.291 5.712 82.397 6.12 ;
     RECT  81.281 7.776 82.748 7.8 ;
     RECT  82.397 5.712 83.408 5.736 ;
     RECT  82.748 7.776 83.408 7.992 ;
     RECT  82.213 10.32 83.408 10.344 ;
     RECT  78.419 23.664 83.408 23.688 ;
     RECT  80.525 30.96 83.408 30.984 ;
     RECT  79.523 50.832 83.408 50.856 ;
     RECT  80.675 54.432 83.408 54.456 ;
     RECT  81.491 59.52 83.408 59.544 ;
     RECT  81.569 67.68 83.408 67.704 ;
     RECT  81.635 88.752 83.408 88.776 ;
     RECT  81.997 95.664 83.408 95.688 ;
     RECT  82.115 102 83.408 102.024 ;
     RECT  83.408 2.148 83.512 127.452 ;
     RECT  83.512 2.418 83.704 127.182 ;
     RECT  83.704 78.624 83.801 78.696 ;
     RECT  83.704 23.04 84.125 24.216 ;
     RECT  83.704 121.968 84.131 122.28 ;
     RECT  83.704 4.896 86.22 4.92 ;
     RECT  83.704 6.048 86.22 6.072 ;
     RECT  83.704 7.344 86.22 7.368 ;
     RECT  84.913 8.496 86.22 8.52 ;
     RECT  83.704 9.648 86.22 9.672 ;
     RECT  83.704 10.944 86.22 10.968 ;
     RECT  83.704 12.096 86.22 12.12 ;
     RECT  83.704 13.392 86.22 13.416 ;
     RECT  83.704 14.544 86.22 14.568 ;
     RECT  83.704 15.696 86.22 15.72 ;
     RECT  83.704 16.992 86.22 17.016 ;
     RECT  83.704 18.144 86.22 18.168 ;
     RECT  83.704 19.44 86.22 19.464 ;
     RECT  84.913 20.592 86.22 20.616 ;
     RECT  83.704 21.744 86.22 21.768 ;
     RECT  84.125 23.04 86.22 23.064 ;
     RECT  84.125 24.192 86.22 24.216 ;
     RECT  83.704 25.488 86.22 25.512 ;
     RECT  85.489 26.64 86.22 26.664 ;
     RECT  83.704 27.792 86.22 27.816 ;
     RECT  85.489 29.088 86.22 29.112 ;
     RECT  83.704 30.24 86.22 30.264 ;
     RECT  83.704 31.536 86.22 31.56 ;
     RECT  83.704 32.688 86.22 32.712 ;
     RECT  84.913 33.84 86.22 33.864 ;
     RECT  83.704 35.136 86.22 35.16 ;
     RECT  83.704 36.288 86.22 36.312 ;
     RECT  84.913 37.584 86.22 37.608 ;
     RECT  83.704 38.736 86.22 38.76 ;
     RECT  85.489 39.888 86.22 39.912 ;
     RECT  83.704 41.184 86.22 41.208 ;
     RECT  84.913 42.336 86.22 42.36 ;
     RECT  84.913 43.632 86.22 43.656 ;
     RECT  83.704 44.784 86.22 44.808 ;
     RECT  83.704 45.936 86.22 45.96 ;
     RECT  83.704 47.232 86.22 47.256 ;
     RECT  83.704 48.384 86.22 48.408 ;
     RECT  83.704 49.68 86.22 49.704 ;
     RECT  83.704 50.832 86.22 50.856 ;
     RECT  83.704 51.984 86.22 52.008 ;
     RECT  83.704 53.28 86.22 53.304 ;
     RECT  83.704 54.432 86.22 54.456 ;
     RECT  83.704 55.728 86.22 55.752 ;
     RECT  83.704 56.88 86.22 56.904 ;
     RECT  84.913 58.032 86.22 58.056 ;
     RECT  85.489 59.328 86.22 59.352 ;
     RECT  83.704 60.48 86.22 60.504 ;
     RECT  83.704 61.776 86.22 61.8 ;
     RECT  83.704 62.928 86.22 62.952 ;
     RECT  83.704 64.08 86.22 64.104 ;
     RECT  83.704 65.376 86.22 65.4 ;
     RECT  83.704 66.528 86.22 66.552 ;
     RECT  83.704 67.824 86.22 67.848 ;
     RECT  83.704 68.976 86.22 69 ;
     RECT  85.489 70.128 86.22 70.152 ;
     RECT  83.704 71.424 86.22 71.448 ;
     RECT  83.704 72.576 86.22 72.6 ;
     RECT  83.704 73.872 86.22 73.896 ;
     RECT  83.704 75.024 86.22 75.048 ;
     RECT  83.704 76.176 86.22 76.2 ;
     RECT  84.913 77.472 86.22 77.496 ;
     RECT  83.801 78.624 86.22 78.648 ;
     RECT  83.704 79.92 86.22 79.944 ;
     RECT  83.704 81.072 86.22 81.096 ;
     RECT  83.704 82.224 86.22 82.248 ;
     RECT  84.913 83.52 86.22 83.544 ;
     RECT  83.704 84.672 86.22 84.696 ;
     RECT  83.704 85.968 86.22 85.992 ;
     RECT  84.913 87.12 86.22 87.144 ;
     RECT  83.704 88.272 86.22 88.296 ;
     RECT  83.704 89.568 86.22 89.592 ;
     RECT  83.704 90.72 86.22 90.744 ;
     RECT  83.704 92.016 86.22 92.04 ;
     RECT  85.489 93.168 86.22 93.192 ;
     RECT  83.704 94.32 86.22 94.344 ;
     RECT  83.704 95.616 86.22 95.64 ;
     RECT  83.704 96.768 86.22 96.792 ;
     RECT  83.704 98.064 86.22 98.088 ;
     RECT  84.913 99.216 86.22 99.24 ;
     RECT  83.704 100.368 86.22 100.392 ;
     RECT  84.877 101.664 86.22 101.688 ;
     RECT  84.913 102.816 86.22 102.84 ;
     RECT  84.877 104.112 86.22 104.136 ;
     RECT  85.489 105.264 86.22 105.288 ;
     RECT  83.704 106.416 86.22 106.44 ;
     RECT  83.704 107.712 86.22 107.736 ;
     RECT  83.704 108.864 86.22 108.888 ;
     RECT  83.704 110.16 86.22 110.184 ;
     RECT  83.704 111.312 86.22 111.336 ;
     RECT  83.704 112.464 86.22 112.488 ;
     RECT  83.704 113.76 86.22 113.784 ;
     RECT  83.704 114.912 86.22 114.936 ;
     RECT  84.913 116.208 86.22 116.232 ;
     RECT  83.704 117.36 86.22 117.384 ;
     RECT  83.704 118.512 86.22 118.536 ;
     RECT  83.704 119.808 86.22 119.832 ;
     RECT  83.704 120.96 86.22 120.984 ;
     RECT  84.131 122.256 86.22 122.28 ;
     RECT  83.704 123.408 86.22 123.432 ;
     RECT  83.704 124.56 86.22 124.584 ;
    LAYER M5 ;
     RECT  4.464 0.144 81.912 0.227 ;
     RECT  4.464 0.227 64.632 0.611 ;
     RECT  65.856 0.227 81.912 0.611 ;
     RECT  39.12 0.611 59.544 1.139 ;
     RECT  4.464 0.611 5.496 1.763 ;
     RECT  6.576 0.611 21.576 1.763 ;
     RECT  22.656 0.611 37.944 1.763 ;
     RECT  39.12 1.139 47.304 1.763 ;
     RECT  48.288 1.139 59.544 1.763 ;
     RECT  60.72 0.611 64.632 1.763 ;
     RECT  65.856 0.611 75.72 1.763 ;
     RECT  76.8 0.611 81.912 1.763 ;
     RECT  9.6 1.763 11.4 1.811 ;
     RECT  14.736 1.763 14.76 1.811 ;
     RECT  78 1.763 79.128 1.811 ;
     RECT  66.864 1.763 68.904 1.859 ;
     RECT  40.128 1.763 41.448 2.051 ;
     RECT  2.4 2.137 2.52 2.151 ;
     RECT  83.4 2.137 83.52 2.151 ;
     RECT  9.6 1.811 9.624 2.291 ;
     RECT  59.232 1.763 59.256 2.291 ;
     RECT  66.864 1.859 67.512 2.291 ;
     RECT  68.88 1.859 68.904 2.291 ;
     RECT  28.176 1.763 31.32 2.339 ;
     RECT  20.16 1.763 21.576 2.677 ;
     RECT  17.952 1.763 19.176 2.725 ;
     RECT  20.16 2.677 21.768 2.725 ;
     RECT  24 1.763 26.568 2.725 ;
     RECT  56.4 1.763 57.96 2.773 ;
     RECT  11.088 1.811 11.4 2.821 ;
     RECT  40.2 2.051 41.448 2.821 ;
     RECT  51 1.763 51.312 2.821 ;
     RECT  56.4 2.773 58.008 2.821 ;
     RECT  28.272 2.339 31.32 2.915 ;
     RECT  40.2 2.821 42.072 2.915 ;
     RECT  33.552 1.763 35.112 3.157 ;
     RECT  36.336 1.763 37.656 3.157 ;
     RECT  42.048 2.915 42.072 3.205 ;
     RECT  78 1.811 78.312 3.349 ;
     RECT  45.6 1.763 45.912 3.397 ;
     RECT  31.248 2.915 31.32 3.443 ;
     RECT  23.136 2.725 26.568 3.491 ;
     RECT  33.552 3.157 37.656 3.733 ;
     RECT  7.8 1.763 8.568 3.827 ;
     RECT  17.952 2.725 21.768 3.829 ;
     RECT  33.504 3.733 37.656 3.829 ;
     RECT  17.856 3.829 21.768 3.925 ;
     RECT  33.456 3.829 37.656 3.925 ;
     RECT  11.088 2.821 12.12 4.019 ;
     RECT  25.392 3.491 26.568 4.019 ;
     RECT  28.272 2.915 29.928 4.019 ;
     RECT  31.248 3.443 31.272 4.019 ;
     RECT  32.304 1.763 32.328 4.019 ;
     RECT  33.408 3.925 37.656 4.019 ;
     RECT  28.992 4.019 29.928 4.211 ;
     RECT  14.784 2.821 14.808 4.259 ;
     RECT  78 3.349 79.128 4.259 ;
     RECT  40.2 2.915 41.016 4.501 ;
     RECT  75.216 3.973 75.24 4.547 ;
     RECT  25.488 4.019 26.568 4.643 ;
     RECT  56.4 2.821 58.92 4.643 ;
     RECT  17.856 3.925 22.056 4.645 ;
     RECT  25.584 4.643 26.568 4.645 ;
     RECT  25.584 4.645 27.528 4.739 ;
     RECT  58.656 4.643 58.92 4.789 ;
     RECT  29.136 4.211 29.928 4.981 ;
     RECT  39.888 4.501 41.016 4.981 ;
     RECT  42.048 3.205 42.12 4.981 ;
     RECT  29.136 4.981 30.216 5.029 ;
     RECT  13.2 1.763 13.512 5.077 ;
     RECT  17.856 4.645 22.152 5.077 ;
     RECT  23.136 3.491 24.312 5.077 ;
     RECT  39.888 4.981 42.12 5.077 ;
     RECT  11.328 4.019 12.12 5.171 ;
     RECT  26.16 4.739 27.528 5.171 ;
     RECT  29.136 5.029 30.984 5.171 ;
     RECT  33.408 4.019 37.032 5.171 ;
     RECT  39.888 5.077 42.312 5.171 ;
     RECT  44.688 3.397 45.912 5.605 ;
     RECT  47.616 3.205 47.64 5.605 ;
     RECT  29.28 5.171 30.984 5.699 ;
     RECT  17.856 5.077 24.312 5.747 ;
     RECT  33.456 5.171 37.032 5.747 ;
     RECT  39.888 5.171 40.512 5.747 ;
     RECT  56.4 4.643 57.336 5.747 ;
     RECT  69.552 4.501 69.576 5.747 ;
     RECT  80.256 5.077 80.28 5.747 ;
     RECT  17.904 5.747 24.312 5.843 ;
     RECT  26.16 5.171 26.184 5.845 ;
     RECT  27.504 5.171 27.528 5.845 ;
     RECT  78 4.259 78.312 5.893 ;
     RECT  58.656 4.789 59.304 6.085 ;
     RECT  67.2 2.291 67.512 6.181 ;
     RECT  25.68 5.845 26.184 6.229 ;
     RECT  27.504 5.845 28.248 6.229 ;
     RECT  33.456 5.747 33.528 6.229 ;
     RECT  40.2 5.747 40.512 6.229 ;
     RECT  41.616 5.171 42.312 6.229 ;
     RECT  63.696 6.181 63.72 6.229 ;
     RECT  65.232 5.317 65.256 6.229 ;
     RECT  25.68 6.229 28.248 6.277 ;
     RECT  34.512 5.747 37.032 6.371 ;
     RECT  9.936 4.501 9.96 6.613 ;
     RECT  12.096 5.171 12.12 6.613 ;
     RECT  13.2 5.077 13.656 6.613 ;
     RECT  16.032 5.173 16.056 6.659 ;
     RECT  33.312 6.229 33.528 6.659 ;
     RECT  25.536 6.277 28.248 6.709 ;
     RECT  61.8 1.763 62.112 6.757 ;
     RECT  63.696 6.229 65.256 6.803 ;
     RECT  12.096 6.613 13.656 6.805 ;
     RECT  20.496 5.843 24.312 6.805 ;
     RECT  25.536 6.709 28.344 6.805 ;
     RECT  33.312 6.659 33.384 6.805 ;
     RECT  58.656 6.085 59.544 6.805 ;
     RECT  66.48 6.181 67.512 6.805 ;
     RECT  63.696 6.803 65.064 6.851 ;
     RECT  9.696 6.613 9.96 6.947 ;
     RECT  50.208 2.821 51.312 7.141 ;
     RECT  70.944 4.501 70.968 7.189 ;
     RECT  72.6 1.763 72.912 7.189 ;
     RECT  50.208 7.141 51.432 7.237 ;
     RECT  53.568 6.229 53.592 7.331 ;
     RECT  44.688 5.605 47.64 7.379 ;
     RECT  16.272 7.237 16.296 7.381 ;
     RECT  20.496 6.805 28.344 7.381 ;
     RECT  29.4 5.699 30.984 7.381 ;
     RECT  32.544 6.805 33.384 7.381 ;
     RECT  34.8 6.371 35.112 7.381 ;
     RECT  43.584 6.853 43.608 7.381 ;
     RECT  44.688 7.379 46.632 7.381 ;
     RECT  37.008 6.371 37.032 7.429 ;
     RECT  58.128 6.805 59.544 7.429 ;
     RECT  12.048 6.805 14.184 7.475 ;
     RECT  17.904 5.843 19.512 7.475 ;
     RECT  20.496 7.381 30.984 7.475 ;
     RECT  58.128 7.429 60.072 7.523 ;
     RECT  22.272 7.475 30.984 7.667 ;
     RECT  36.096 7.429 37.032 7.667 ;
     RECT  73.968 4.213 73.992 7.667 ;
     RECT  77.664 5.893 78.312 7.717 ;
     RECT  61.344 6.757 62.112 7.765 ;
     RECT  13.2 7.475 14.184 7.909 ;
     RECT  56.4 5.747 56.712 7.909 ;
     RECT  61.344 7.765 62.328 7.955 ;
     RECT  36.144 7.667 37.032 7.957 ;
     RECT  49.632 7.237 51.432 7.957 ;
     RECT  83.4 2.151 83.712 7.957 ;
     RECT  20.496 7.475 20.952 8.003 ;
     RECT  22.32 7.667 30.984 8.003 ;
     RECT  16.272 7.381 16.872 8.101 ;
     RECT  17.904 7.475 18.912 8.101 ;
     RECT  43.584 7.381 46.632 8.147 ;
     RECT  70.944 7.189 72.912 8.197 ;
     RECT  36.144 7.957 37.704 8.245 ;
     RECT  44.64 8.147 46.632 8.435 ;
     RECT  47.616 7.379 47.64 8.437 ;
     RECT  49.104 7.957 51.432 8.437 ;
     RECT  66.48 6.805 67.896 8.485 ;
     RECT  70.752 8.197 72.912 8.531 ;
     RECT  61.8 7.955 62.328 8.579 ;
     RECT  7.8 3.827 8.112 8.581 ;
     RECT  13.2 7.909 14.52 8.677 ;
     RECT  16.272 8.101 18.912 8.677 ;
     RECT  77.52 7.717 78.312 8.819 ;
     RECT  40.2 6.229 42.312 8.821 ;
     RECT  43.584 8.147 43.608 8.821 ;
     RECT  40.2 8.821 43.608 8.869 ;
     RECT  47.616 8.437 51.432 8.869 ;
     RECT  55.824 7.909 56.712 8.917 ;
     RECT  66.48 8.485 68.472 8.917 ;
     RECT  69.504 6.229 69.528 9.013 ;
     RECT  70.752 8.531 70.968 9.013 ;
     RECT  69.504 9.013 70.968 9.059 ;
     RECT  53.664 7.333 53.688 9.061 ;
     RECT  10.272 7.381 10.296 9.157 ;
     RECT  12.048 7.475 12.12 9.157 ;
     RECT  32.304 7.381 33.384 9.157 ;
     RECT  53.04 9.061 54.408 9.349 ;
     RECT  58.176 7.523 60.072 9.349 ;
     RECT  20.496 8.003 20.808 9.445 ;
     RECT  34.704 7.381 35.112 9.445 ;
     RECT  36.144 8.245 38.04 9.445 ;
     RECT  13.2 8.677 18.912 9.541 ;
     RECT  61.8 8.579 62.112 9.589 ;
     RECT  39.744 8.869 43.608 9.637 ;
     RECT  44.64 8.435 46.488 9.637 ;
     RECT  55.824 8.917 56.808 9.637 ;
     RECT  9.12 9.541 9.144 9.779 ;
     RECT  7.584 8.581 8.112 9.827 ;
     RECT  58.128 9.349 60.072 9.877 ;
     RECT  20.496 9.445 21.288 9.925 ;
     RECT  22.32 8.003 29.712 9.925 ;
     RECT  55.824 9.637 57.048 9.925 ;
     RECT  55.584 9.925 57.048 9.973 ;
     RECT  58.08 9.877 60.072 9.973 ;
     RECT  6.24 6.229 6.264 10.021 ;
     RECT  5.904 10.021 6.264 10.067 ;
     RECT  61.344 9.589 62.112 10.117 ;
     RECT  10.272 9.157 12.12 10.165 ;
     RECT  13.2 9.541 19.032 10.259 ;
     RECT  61.344 10.117 62.664 10.259 ;
     RECT  20.496 9.925 29.712 10.261 ;
     RECT  31.536 9.157 33.384 10.261 ;
     RECT  34.704 9.445 38.04 10.261 ;
     RECT  55.584 9.973 60.072 10.261 ;
     RECT  69.504 9.059 70.776 10.307 ;
     RECT  82.8 7.957 83.712 10.309 ;
     RECT  82.224 10.309 83.712 10.355 ;
     RECT  47.616 8.869 51.624 10.357 ;
     RECT  47.616 10.357 51.816 10.643 ;
     RECT  76.032 7.765 76.056 10.883 ;
     RECT  39.744 9.637 46.488 10.885 ;
     RECT  55.536 10.261 60.072 10.885 ;
     RECT  61.344 10.259 62.112 10.885 ;
     RECT  9.456 10.165 12.12 11.077 ;
     RECT  13.2 10.259 18.912 11.077 ;
     RECT  20.496 10.261 30.264 11.173 ;
     RECT  55.536 10.885 62.112 11.269 ;
     RECT  7.8 9.827 8.112 11.317 ;
     RECT  9.456 11.077 18.912 11.317 ;
     RECT  39.552 10.885 46.488 11.365 ;
     RECT  55.44 11.269 62.112 11.365 ;
     RECT  63.696 6.851 64.536 11.365 ;
     RECT  70.752 10.307 70.776 11.365 ;
     RECT  20.496 11.173 30.504 11.411 ;
     RECT  78 8.819 78.312 11.413 ;
     RECT  39.456 11.365 46.488 11.509 ;
     RECT  47.616 10.643 51.624 11.509 ;
     RECT  70.512 11.365 70.776 11.605 ;
     RECT  72 8.531 72.912 11.605 ;
     RECT  52.8 9.349 54.408 11.653 ;
     RECT  55.44 11.365 64.536 11.653 ;
     RECT  7.8 11.317 18.912 11.893 ;
     RECT  39.456 11.509 51.624 11.893 ;
     RECT  7.8 11.893 19.128 11.989 ;
     RECT  20.496 11.411 30.264 11.989 ;
     RECT  52.8 11.653 64.536 11.989 ;
     RECT  78 11.413 78.648 12.035 ;
     RECT  52.8 11.989 64.968 12.229 ;
     RECT  31.488 10.261 38.04 12.277 ;
     RECT  39.024 11.893 51.624 12.277 ;
     RECT  52.704 12.229 64.968 12.277 ;
     RECT  4.464 12.325 4.488 12.373 ;
     RECT  5.904 10.067 5.928 12.373 ;
     RECT  70.512 11.605 72.912 12.373 ;
     RECT  7.8 11.989 30.264 12.517 ;
     RECT  31.488 12.277 64.968 12.661 ;
     RECT  31.488 12.661 65.016 12.707 ;
     RECT  4.464 12.373 5.928 12.757 ;
     RECT  31.488 12.707 51.672 12.949 ;
     RECT  52.704 12.707 65.016 13.093 ;
     RECT  66.096 8.917 68.472 13.093 ;
     RECT  4.464 12.757 6.264 13.139 ;
     RECT  7.392 12.517 30.264 13.189 ;
     RECT  31.296 12.949 51.672 13.189 ;
     RECT  52.704 13.093 68.472 13.669 ;
     RECT  4.512 13.139 6.264 13.715 ;
     RECT  70.512 12.373 73.032 13.715 ;
     RECT  7.392 13.189 51.672 14.005 ;
     RECT  52.656 13.669 68.472 14.005 ;
     RECT  4.512 13.715 4.536 14.051 ;
     RECT  7.392 14.005 68.472 14.197 ;
     RECT  69.504 10.307 69.528 14.197 ;
     RECT  70.512 13.715 72.912 14.197 ;
     RECT  7.392 14.197 72.912 14.339 ;
     RECT  5.904 13.715 5.928 14.725 ;
     RECT  3.792 14.341 3.816 15.443 ;
     RECT  82.224 10.355 82.248 16.019 ;
     RECT  2.4 2.151 2.712 16.501 ;
     RECT  5.904 14.725 6.6 16.501 ;
     RECT  78 12.035 78.312 16.645 ;
     RECT  5.856 16.501 6.6 17.077 ;
     RECT  2.4 16.501 2.856 17.219 ;
     RECT  80.832 15.973 80.856 17.363 ;
     RECT  3.936 16.309 3.96 17.509 ;
     RECT  5.136 17.077 6.6 17.509 ;
     RECT  3.936 17.509 6.6 18.181 ;
     RECT  2.4 17.219 2.808 18.661 ;
     RECT  3.936 18.181 6.792 18.661 ;
     RECT  7.8 14.339 72.912 18.757 ;
     RECT  77.616 16.645 78.312 18.851 ;
     RECT  7.8 18.757 73.608 19.091 ;
     RECT  2.4 18.661 2.856 19.285 ;
     RECT  3.888 18.661 6.792 19.285 ;
     RECT  2.4 19.285 6.792 19.429 ;
     RECT  7.8 19.091 71.592 19.429 ;
     RECT  78 18.851 78.312 19.477 ;
     RECT  80.88 19.333 80.904 19.955 ;
     RECT  0.288 20.005 0.312 20.149 ;
     RECT  82.032 19.909 82.056 20.579 ;
     RECT  2.4 19.429 71.592 21.011 ;
     RECT  0.288 20.149 0.552 21.155 ;
     RECT  2.4 21.011 5.544 21.155 ;
     RECT  0.528 21.155 0.552 21.203 ;
     RECT  2.4 21.155 5.496 21.203 ;
     RECT  2.4 21.203 2.712 21.493 ;
     RECT  6.816 21.011 71.592 21.827 ;
     RECT  6.816 21.827 54.696 22.165 ;
     RECT  2.304 21.493 2.712 22.549 ;
     RECT  2.304 22.549 2.856 22.645 ;
     RECT  56.4 21.827 71.592 22.693 ;
     RECT  72.6 19.091 73.608 22.693 ;
     RECT  4.368 21.203 5.496 22.741 ;
     RECT  6.672 22.165 54.696 22.741 ;
     RECT  2.304 22.645 3.336 23.315 ;
     RECT  2.4 23.315 3.336 23.317 ;
     RECT  4.368 22.741 54.696 23.317 ;
     RECT  56.4 22.693 73.608 25.045 ;
     RECT  78 19.477 78.408 25.475 ;
     RECT  56.064 25.045 73.608 25.715 ;
     RECT  2.4 23.317 54.696 26.197 ;
     RECT  2.4 26.197 55.368 26.243 ;
     RECT  78 25.475 78.312 27.205 ;
     RECT  2.4 26.243 2.808 27.301 ;
     RECT  3.888 26.243 55.368 27.301 ;
     RECT  75.888 19.045 75.912 27.589 ;
     RECT  56.4 25.715 73.608 27.731 ;
     RECT  78 27.205 79.176 27.923 ;
     RECT  0.192 27.877 0.216 28.115 ;
     RECT  0.288 28.213 0.312 28.357 ;
     RECT  0.288 28.357 0.36 28.547 ;
     RECT  75.84 27.589 75.912 28.547 ;
     RECT  81.408 27.877 81.432 28.547 ;
     RECT  75.888 28.547 75.912 29.123 ;
     RECT  0.288 28.547 0.312 29.221 ;
     RECT  0.192 29.221 0.312 29.411 ;
     RECT  2.4 27.301 55.368 29.845 ;
     RECT  56.4 27.731 73.464 29.845 ;
     RECT  2.4 29.845 73.464 30.083 ;
     RECT  0.288 29.411 0.312 30.371 ;
     RECT  78 27.923 78.648 30.659 ;
     RECT  2.4 30.083 54.744 31.331 ;
     RECT  56.304 30.083 73.464 31.861 ;
     RECT  78 30.659 78.408 31.861 ;
     RECT  55.92 31.861 73.464 31.957 ;
     RECT  55.92 31.957 73.512 32.483 ;
     RECT  2.4 31.331 54.696 32.675 ;
     RECT  2.4 32.675 2.856 32.771 ;
     RECT  3.936 32.675 54.696 32.773 ;
     RECT  55.92 32.483 73.464 32.773 ;
     RECT  3.936 32.773 73.464 33.011 ;
     RECT  4.08 33.011 73.464 35.845 ;
     RECT  80.4 33.925 80.424 36.515 ;
     RECT  3.984 35.845 73.464 37.571 ;
     RECT  78 31.861 79.176 37.573 ;
     RECT  80.448 36.661 80.472 37.573 ;
     RECT  4.128 37.571 73.464 37.861 ;
     RECT  4.128 37.861 73.56 38.003 ;
     RECT  2.4 32.771 2.712 38.533 ;
     RECT  4.128 38.003 73.464 38.533 ;
     RECT  74.784 33.973 74.808 38.629 ;
     RECT  74.784 38.629 74.952 38.771 ;
     RECT  2.4 38.533 73.464 39.443 ;
     RECT  76.992 36.997 77.016 39.829 ;
     RECT  78 37.573 80.472 39.829 ;
     RECT  76.992 39.829 80.472 39.923 ;
     RECT  74.784 38.771 74.808 40.021 ;
     RECT  3.792 39.443 73.464 40.259 ;
     RECT  80.448 39.923 80.472 42.181 ;
     RECT  4.128 40.259 73.464 43.285 ;
     RECT  74.784 40.021 75.528 43.285 ;
     RECT  80.352 42.181 80.472 44.483 ;
     RECT  4.128 43.285 75.528 44.627 ;
     RECT  76.992 39.923 79.176 46.069 ;
     RECT  75.984 46.693 76.008 48.469 ;
     RECT  76.992 46.069 79.272 49.525 ;
     RECT  80.448 44.483 80.472 49.525 ;
     RECT  75.84 48.469 76.008 50.629 ;
     RECT  76.992 49.525 80.472 50.629 ;
     RECT  4.128 44.627 74.808 51.637 ;
     RECT  75.84 50.629 80.472 52.115 ;
     RECT  4.032 51.637 74.808 53.267 ;
     RECT  4.128 53.267 74.808 54.131 ;
     RECT  80.448 52.115 80.472 54.661 ;
     RECT  75.84 52.115 79.272 54.755 ;
     RECT  75.84 54.755 79.176 55.427 ;
     RECT  4.128 54.131 20.568 55.525 ;
     RECT  80.448 54.661 80.664 55.525 ;
     RECT  80.4 55.525 80.664 55.571 ;
     RECT  21.984 54.131 74.808 56.341 ;
     RECT  75.84 55.427 75.864 56.341 ;
     RECT  2.4 39.443 2.712 56.917 ;
     RECT  2.4 56.917 2.856 57.109 ;
     RECT  4.128 55.525 20.808 57.109 ;
     RECT  80.4 55.571 80.472 57.541 ;
     RECT  80.4 57.541 80.664 57.587 ;
     RECT  21.984 56.341 75.864 57.877 ;
     RECT  80.448 57.587 80.664 57.973 ;
     RECT  80.448 57.973 81.48 58.019 ;
     RECT  0.288 57.157 0.312 58.163 ;
     RECT  21.984 57.877 75.912 58.405 ;
     RECT  76.944 55.427 79.176 58.405 ;
     RECT  2.4 57.109 20.808 59.749 ;
     RECT  21.984 58.405 79.176 59.749 ;
     RECT  0.288 60.373 0.312 61.091 ;
     RECT  2.4 59.749 79.176 62.771 ;
     RECT  81.456 58.019 81.48 63.251 ;
     RECT  3.84 62.771 79.176 64.019 ;
     RECT  2.4 62.771 2.856 64.451 ;
     RECT  3.84 64.019 6.408 64.451 ;
     RECT  7.44 64.019 79.176 64.931 ;
     RECT  4.128 64.451 6.408 65.797 ;
     RECT  2.4 64.451 2.712 65.941 ;
     RECT  3.792 65.797 6.408 65.941 ;
     RECT  2.4 65.941 6.408 66.037 ;
     RECT  7.536 64.931 79.176 66.037 ;
     RECT  2.4 66.037 79.176 67.765 ;
     RECT  80.448 58.019 80.472 67.765 ;
     RECT  2.4 67.765 80.472 67.907 ;
     RECT  2.4 67.907 2.904 67.955 ;
     RECT  3.888 67.907 80.472 68.435 ;
     RECT  2.4 67.955 2.808 69.493 ;
     RECT  4.128 68.435 80.472 69.493 ;
     RECT  2.4 69.493 80.472 70.739 ;
     RECT  49.872 70.739 80.472 71.797 ;
     RECT  2.4 70.739 48.6 71.843 ;
     RECT  0.192 71.557 0.216 71.845 ;
     RECT  0.192 71.845 0.312 72.467 ;
     RECT  0.288 72.467 0.312 72.515 ;
     RECT  3.84 71.843 48.6 72.563 ;
     RECT  3.888 72.563 48.6 72.853 ;
     RECT  49.776 71.797 80.472 72.853 ;
     RECT  2.4 71.843 2.856 72.995 ;
     RECT  3.888 72.853 80.472 72.995 ;
     RECT  80.448 72.995 80.472 73.957 ;
     RECT  3.888 72.995 79.176 74.677 ;
     RECT  3.792 74.677 79.176 75.541 ;
     RECT  80.4 73.957 80.472 75.541 ;
     RECT  2.4 72.995 2.712 75.637 ;
     RECT  3.792 75.541 80.472 75.637 ;
     RECT  2.4 75.637 80.472 78.371 ;
     RECT  4.128 78.371 80.472 78.707 ;
     RECT  4.224 78.707 80.472 80.627 ;
     RECT  80.448 80.627 80.472 81.733 ;
     RECT  4.224 80.627 79.272 82.021 ;
     RECT  80.4 81.733 80.472 82.691 ;
     RECT  80.448 82.691 80.472 83.749 ;
     RECT  4.128 82.021 79.272 84.181 ;
     RECT  80.448 83.749 80.616 84.181 ;
     RECT  4.128 84.181 80.616 85.381 ;
     RECT  3.936 85.381 80.616 85.429 ;
     RECT  3.696 85.429 80.616 85.477 ;
     RECT  3.696 85.477 81.048 86.581 ;
     RECT  3.696 86.581 81.096 87.251 ;
     RECT  3.696 87.251 80.472 87.395 ;
     RECT  3.744 87.395 80.472 87.683 ;
     RECT  81.456 87.685 81.48 88.501 ;
     RECT  81.456 88.501 81.624 88.547 ;
     RECT  3.744 87.683 79.368 88.933 ;
     RECT  3.744 88.933 79.464 89.315 ;
     RECT  3.744 89.315 79.368 89.699 ;
     RECT  4.128 89.699 79.368 90.997 ;
     RECT  4.128 90.997 79.464 91.141 ;
     RECT  80.448 87.683 80.472 91.141 ;
     RECT  81.6 88.547 81.624 93.539 ;
     RECT  4.128 91.141 80.472 94.259 ;
     RECT  64.176 94.259 80.472 94.451 ;
     RECT  0.192 94.597 0.216 94.883 ;
     RECT  4.128 94.259 63.048 95.653 ;
     RECT  64.272 94.451 80.472 95.653 ;
     RECT  4.128 95.653 80.472 96.469 ;
     RECT  4.128 96.469 81.048 99.731 ;
     RECT  4.128 99.731 80.856 100.789 ;
     RECT  4.128 100.789 80.952 100.931 ;
     RECT  2.4 78.371 2.712 102.565 ;
     RECT  4.128 100.931 80.856 102.565 ;
     RECT  82.08 101.989 82.104 102.899 ;
     RECT  2.4 102.565 80.856 103.379 ;
     RECT  2.4 103.379 80.472 109.381 ;
     RECT  2.4 109.381 80.76 110.291 ;
     RECT  4.128 110.291 80.76 111.875 ;
     RECT  4.128 111.875 78.84 112.837 ;
     RECT  79.968 111.875 80.76 112.837 ;
     RECT  4.128 112.837 80.76 112.883 ;
     RECT  4.128 112.883 78.408 113.171 ;
     RECT  70.752 113.171 78.408 113.459 ;
     RECT  79.632 112.883 80.76 113.699 ;
     RECT  4.128 113.171 69.768 113.843 ;
     RECT  82.032 112.837 82.056 114.275 ;
     RECT  70.752 113.459 75.288 114.467 ;
     RECT  4.128 113.843 69.192 114.611 ;
     RECT  76.608 113.459 78.408 114.611 ;
     RECT  77.136 114.611 78.408 115.621 ;
     RECT  70.752 114.467 73.32 115.715 ;
     RECT  4.128 114.611 48.696 115.717 ;
     RECT  49.68 114.611 69.192 115.717 ;
     RECT  77.136 115.621 78.648 116.339 ;
     RECT  71.76 115.715 73.32 116.579 ;
     RECT  4.128 115.717 69.192 116.915 ;
     RECT  74.4 114.467 75.288 117.059 ;
     RECT  4.128 116.915 59.496 117.107 ;
     RECT  77.136 116.339 78.408 117.397 ;
     RECT  60.624 116.915 69.192 117.587 ;
     RECT  76.368 117.397 78.408 117.685 ;
     RECT  79.968 113.699 80.76 117.685 ;
     RECT  12.576 117.107 59.496 117.779 ;
     RECT  76.368 117.685 80.76 117.781 ;
     RECT  49.008 117.779 59.496 117.827 ;
     RECT  74.64 117.059 75.288 118.019 ;
     RECT  76.368 117.781 80.952 118.019 ;
     RECT  12.576 117.779 47.64 118.499 ;
     RECT  4.128 117.107 11.544 118.549 ;
     RECT  12.576 118.499 42.408 118.549 ;
     RECT  77.136 118.019 80.952 118.595 ;
     RECT  79.968 118.595 80.952 118.643 ;
     RECT  49.056 117.827 59.496 118.787 ;
     RECT  49.056 118.787 55.224 118.837 ;
     RECT  48.768 118.837 55.224 118.979 ;
     RECT  53.712 118.979 55.224 119.027 ;
     RECT  70.752 115.715 70.776 119.077 ;
     RECT  71.76 116.579 72.912 119.077 ;
     RECT  75.264 118.019 75.288 119.077 ;
     RECT  4.128 118.549 42.408 119.123 ;
     RECT  60.672 117.587 69.192 119.459 ;
     RECT  12.576 119.123 42.408 119.461 ;
     RECT  43.584 118.499 47.64 119.651 ;
     RECT  79.968 118.643 80.76 119.653 ;
     RECT  61.8 119.459 69.192 119.699 ;
     RECT  46.992 119.651 47.64 119.749 ;
     RECT  48.768 118.979 52.392 119.749 ;
     RECT  70.752 119.077 72.912 119.891 ;
     RECT  56.4 118.787 59.496 119.939 ;
     RECT  4.128 119.123 11.544 120.085 ;
     RECT  12.576 119.461 42.504 120.085 ;
     RECT  75.264 119.077 75.864 120.133 ;
     RECT  4.128 120.085 42.504 120.229 ;
     RECT  77.136 118.595 78.408 120.229 ;
     RECT  0.288 120.133 0.312 120.275 ;
     RECT  3.936 120.229 42.504 120.275 ;
     RECT  79.968 119.653 80.952 120.515 ;
     RECT  46.992 119.749 52.392 120.611 ;
     RECT  12.72 120.275 42.504 120.755 ;
     RECT  46.992 120.611 49.176 120.755 ;
     RECT  18.6 120.755 42.504 120.851 ;
     RECT  46.992 120.755 48.984 120.851 ;
     RECT  70.752 119.891 70.776 120.853 ;
     RECT  3.936 120.275 11.544 120.899 ;
     RECT  61.8 119.699 67.512 120.899 ;
     RECT  70.704 120.853 70.776 120.995 ;
     RECT  18.6 120.851 42.408 121.235 ;
     RECT  70.704 120.995 70.728 121.331 ;
     RECT  75.264 120.133 76.104 121.331 ;
     RECT  53.856 119.027 55.224 121.333 ;
     RECT  46.992 120.851 48.744 121.811 ;
     RECT  79.968 120.515 80.76 121.811 ;
     RECT  83.4 10.355 83.712 121.957 ;
     RECT  20.976 121.235 42.408 122.051 ;
     RECT  53.712 121.333 55.224 122.051 ;
     RECT  3.936 120.899 11.256 122.099 ;
     RECT  36.336 122.051 42.408 122.099 ;
     RECT  46.992 121.811 48.36 122.099 ;
     RECT  79.968 121.811 79.992 122.099 ;
     RECT  75.264 121.331 75.288 122.101 ;
     RECT  83.4 121.957 84.12 122.291 ;
     RECT  20.976 122.051 35.208 122.435 ;
     RECT  75.216 122.101 75.288 122.435 ;
     RECT  20.976 122.435 35.112 122.483 ;
     RECT  57.84 119.939 59.496 122.675 ;
     RECT  18.6 121.235 19.992 122.725 ;
     RECT  18.48 122.725 19.992 122.773 ;
     RECT  20.976 122.483 25.368 122.773 ;
     RECT  18.48 122.773 25.368 123.059 ;
     RECT  68.784 119.699 69.192 123.061 ;
     RECT  26.448 122.483 35.112 123.155 ;
     RECT  56.4 119.939 56.712 123.157 ;
     RECT  18.6 123.059 25.368 123.299 ;
     RECT  77.136 120.229 78.456 123.445 ;
     RECT  79.488 122.773 79.512 123.445 ;
     RECT  12.72 120.755 17.304 123.491 ;
     RECT  20.88 123.299 25.368 123.587 ;
     RECT  77.136 123.445 79.512 123.635 ;
     RECT  80.928 122.917 80.952 123.637 ;
     RECT  4.128 122.099 11.256 123.731 ;
     RECT  79.488 123.635 79.512 123.731 ;
     RECT  29.4 123.155 35.112 123.733 ;
     RECT  71.76 119.891 72.912 123.733 ;
     RECT  75.216 122.435 75.24 123.779 ;
     RECT  80.928 123.637 81.192 123.779 ;
     RECT  68.784 123.061 70.152 123.781 ;
     RECT  9.888 123.731 11.256 123.827 ;
     RECT  20.976 123.587 25.368 123.875 ;
     RECT  53.952 122.051 55.224 123.875 ;
     RECT  68.784 123.781 70.248 123.923 ;
     RECT  18.6 123.299 19.224 123.971 ;
     RECT  65.232 120.899 67.512 123.971 ;
     RECT  29.4 123.733 35.256 124.211 ;
     RECT  77.136 123.635 78.456 124.213 ;
     RECT  10.32 123.827 11.256 124.307 ;
     RECT  76.848 124.213 78.456 124.309 ;
     RECT  56.256 123.157 56.712 124.355 ;
     RECT  76.8 124.309 78.456 124.451 ;
     RECT  49.2 123.877 49.224 124.547 ;
     RECT  68.784 123.923 70.152 124.547 ;
     RECT  50.208 120.611 52.392 124.549 ;
     RECT  76.848 124.451 78.456 124.597 ;
     RECT  76.848 124.597 79.08 124.787 ;
     RECT  68.784 124.547 69.672 124.835 ;
     RECT  11.232 124.307 11.256 124.883 ;
     RECT  12.72 123.491 14.04 124.883 ;
     RECT  60.672 119.459 60.696 124.883 ;
     RECT  4.128 123.731 8.112 124.931 ;
     RECT  54.24 123.875 55.224 124.931 ;
     RECT  15.552 123.491 17.304 124.979 ;
     RECT  68.784 124.835 69.288 125.075 ;
     RECT  81.168 123.779 81.192 125.075 ;
     RECT  29.4 124.211 35.112 125.123 ;
     RECT  54.432 124.931 55.224 125.123 ;
     RECT  42.096 122.099 42.408 125.171 ;
     RECT  71.76 123.733 73.128 125.171 ;
     RECT  76.848 124.787 78.456 125.219 ;
     RECT  15.936 124.979 17.304 125.221 ;
     RECT  18.6 123.971 18.912 125.221 ;
     RECT  21.264 123.875 25.368 125.315 ;
     RECT  50.208 124.549 52.632 125.363 ;
     RECT  5.328 124.931 8.112 125.459 ;
     RECT  30.72 125.123 35.112 125.459 ;
     RECT  36.336 122.099 41.064 125.459 ;
     RECT  46.992 122.099 47.64 125.459 ;
     RECT  50.208 125.363 52.392 125.459 ;
     RECT  68.784 125.075 69.192 125.459 ;
     RECT  71.76 125.171 72.912 125.459 ;
     RECT  39.072 125.459 41.064 125.461 ;
     RECT  42.096 125.171 42.264 125.461 ;
     RECT  4.128 124.931 4.152 125.507 ;
     RECT  33.312 125.459 35.112 125.507 ;
     RECT  65.856 123.971 67.512 125.507 ;
     RECT  43.584 119.651 45.912 125.557 ;
     RECT  46.992 125.459 47.352 125.557 ;
     RECT  21.264 125.315 24.504 125.605 ;
     RECT  5.472 125.459 5.736 125.651 ;
     RECT  43.584 125.557 47.352 125.651 ;
     RECT  51 125.459 52.392 125.651 ;
     RECT  57.84 122.675 58.392 125.651 ;
     RECT  43.584 125.651 43.608 125.653 ;
     RECT  21.12 125.605 24.504 125.747 ;
     RECT  26.448 123.155 28.2 125.747 ;
     RECT  21.12 125.747 22.824 125.843 ;
     RECT  26.544 125.747 28.2 125.843 ;
     RECT  6.912 125.459 8.112 125.845 ;
     RECT  31.056 125.459 31.176 125.891 ;
     RECT  44.736 125.651 47.352 125.891 ;
     RECT  13.2 124.883 14.04 125.893 ;
     RECT  36.336 125.459 38.088 125.939 ;
     RECT  61.8 120.899 64.104 125.939 ;
     RECT  34.8 125.507 35.112 125.941 ;
     RECT  15.936 125.221 18.912 125.987 ;
     RECT  21.12 125.843 21.816 125.987 ;
     RECT  26.784 125.843 28.2 125.987 ;
     RECT  15.936 125.987 17.304 126.035 ;
     RECT  21.792 125.987 21.816 126.035 ;
     RECT  37.344 125.939 38.088 126.035 ;
     RECT  39.072 125.461 42.264 126.035 ;
     RECT  43.248 125.653 43.608 126.035 ;
     RECT  57.84 125.651 58.008 126.035 ;
     RECT  16.368 126.035 17.304 126.083 ;
     RECT  39.072 126.035 41.448 126.083 ;
     RECT  65.856 125.507 65.88 126.083 ;
     RECT  26.928 125.987 28.2 126.131 ;
     RECT  33.312 125.507 33.336 126.131 ;
     RECT  43.248 126.035 43.272 126.179 ;
     RECT  57.936 126.035 58.008 126.179 ;
     RECT  76.848 125.219 78.408 126.179 ;
     RECT  59.472 122.675 59.496 126.227 ;
     RECT  13.2 125.893 14.232 126.229 ;
     RECT  28.176 126.131 28.2 126.275 ;
     RECT  72.6 125.459 72.912 126.373 ;
     RECT  74.544 125.077 74.568 126.373 ;
     RECT  54.912 125.123 55.224 126.421 ;
     RECT  72.6 126.373 74.664 126.421 ;
     RECT  38.064 126.035 38.088 126.467 ;
     RECT  51 125.651 52.152 126.467 ;
     RECT  6.912 125.845 8.472 126.469 ;
     RECT  13.056 126.229 14.232 126.469 ;
     RECT  54.768 126.421 55.224 126.469 ;
     RECT  56.4 124.355 56.712 126.469 ;
     RECT  67.2 125.507 67.512 126.469 ;
     RECT  68.592 126.421 68.616 126.469 ;
     RECT  71.232 125.941 71.256 126.469 ;
     RECT  72.384 126.421 74.664 126.469 ;
     RECT  80.112 126.421 80.136 126.469 ;
     RECT  44.736 125.891 46.728 126.515 ;
     RECT  10.224 125.893 10.248 126.517 ;
     RECT  13.008 126.469 14.232 126.517 ;
     RECT  29.4 125.123 29.712 126.565 ;
     RECT  17.28 126.083 17.304 126.611 ;
     RECT  70.032 126.469 74.664 126.613 ;
     RECT  33.072 126.421 33.096 126.659 ;
     RECT  5.472 125.651 5.496 126.853 ;
     RECT  6.72 126.469 8.472 126.853 ;
     RECT  24 125.747 24.504 126.853 ;
     RECT  67.2 126.469 68.616 126.853 ;
     RECT  70.032 126.613 74.712 126.853 ;
     RECT  76.944 126.179 78.408 126.853 ;
     RECT  79.68 126.469 80.136 126.853 ;
     RECT  81.888 126.469 81.912 126.853 ;
     RECT  4.896 126.853 8.904 126.949 ;
     RECT  67.2 126.853 75.144 126.949 ;
     RECT  4.464 126.949 8.904 127.045 ;
     RECT  10.224 126.517 10.776 127.045 ;
     RECT  12.576 126.517 14.76 127.045 ;
     RECT  18.6 125.987 18.912 127.093 ;
     RECT  22.8 125.843 22.824 127.093 ;
     RECT  24 126.853 24.552 127.093 ;
     RECT  26.928 126.131 26.952 127.093 ;
     RECT  29.4 126.565 30.36 127.093 ;
     RECT  54.768 126.469 56.712 127.093 ;
     RECT  61.8 125.939 63.72 127.093 ;
     RECT  67.2 126.949 75.576 127.093 ;
     RECT  54.768 127.093 56.952 127.141 ;
     RECT  61.44 127.093 63.72 127.141 ;
     RECT  61.44 127.141 64.488 127.237 ;
     RECT  42.72 127.093 42.744 127.381 ;
     RECT  2.4 110.291 2.712 127.449 ;
     RECT  83.4 122.291 83.712 127.449 ;
     RECT  2.4 127.449 2.52 127.463 ;
     RECT  66.288 127.093 75.576 127.463 ;
     RECT  83.4 127.449 83.52 127.463 ;
     RECT  34.8 125.941 36.072 127.573 ;
     RECT  4.464 127.045 15.192 127.669 ;
     RECT  16.944 127.093 16.968 127.669 ;
     RECT  18.6 127.093 19.272 127.669 ;
     RECT  20.976 127.093 21.432 127.669 ;
     RECT  22.8 127.093 24.552 127.669 ;
     RECT  26.928 127.093 27.144 127.669 ;
     RECT  28.464 127.093 31.656 127.669 ;
     RECT  33.456 127.093 33.48 127.669 ;
     RECT  34.752 127.573 36.072 127.669 ;
     RECT  44.976 126.515 46.728 127.669 ;
     RECT  49.92 127.621 49.944 127.669 ;
     RECT  51 126.467 51.312 127.669 ;
     RECT  52.512 127.093 52.536 127.669 ;
     RECT  53.808 127.141 56.952 127.669 ;
     RECT  57.936 126.179 57.96 127.669 ;
     RECT  59.232 127.093 59.256 127.669 ;
     RECT  61.44 127.237 64.92 127.669 ;
     RECT  66.288 127.463 67.176 127.669 ;
     RECT  20.544 127.669 21.432 128.197 ;
     RECT  22.8 127.669 25.416 128.197 ;
     RECT  26.928 127.669 36.072 128.197 ;
     RECT  37.344 127.669 37.368 128.197 ;
     RECT  39.696 126.083 41.448 128.197 ;
     RECT  44.976 127.669 47.592 128.197 ;
     RECT  49.92 127.669 51.312 128.197 ;
     RECT  52.512 127.669 56.952 128.197 ;
     RECT  68.16 127.463 75.576 128.245 ;
     RECT  76.944 126.853 81.912 128.245 ;
     RECT  4.464 127.669 19.272 128.725 ;
     RECT  20.544 128.197 25.416 128.725 ;
     RECT  4.464 128.725 25.416 128.821 ;
     RECT  26.928 128.197 37.8 128.821 ;
     RECT  38.832 128.197 41.448 128.821 ;
     RECT  42.72 127.381 43.176 128.821 ;
     RECT  44.976 128.197 56.952 128.821 ;
     RECT  57.936 127.669 59.256 128.821 ;
     RECT  61.008 127.669 67.176 128.821 ;
     RECT  68.16 128.245 81.912 128.821 ;
     RECT  4.464 128.821 37.8 129.424 ;
     RECT  38.832 128.821 81.912 129.424 ;
     RECT  74.208 129.424 74.232 129.491 ;
  END
END s81_a2f_field4
END LIBRARY
